NAMESCASESENSITIVE ON ;

UNITS
DATABASE MICRONS 1000 ;
END UNITS

LAYER NWELL
	TYPE MASTERSLICE ;
END NWELL
LAYER PP
	TYPE MASTERSLICE ;
END PP
LAYER NP
	TYPE MASTERSLICE ;
END NP
LAYER OD
	TYPE MASTERSLICE ;
END OD
LAYER POLY
	TYPE MASTERSLICE ;
END POLY
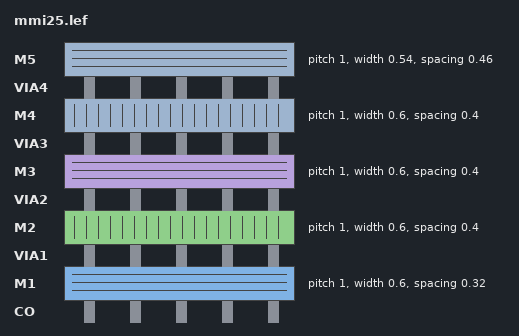
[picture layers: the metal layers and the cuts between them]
LAYER CO
	TYPE CUT ;
END CO
LAYER M1
	TYPE ROUTING ;
	PITCH 1.0 ;
	WIDTH 0.6 ;
	SPACING 0.32 ;
	DIRECTION HORIZONTAL ;
	RESISTANCE RPERSQ 0.09 ;
	CAPACITANCE CPERSQDIST .000389 ;
END M1
LAYER VIA1 
	TYPE CUT ;
END VIA1
LAYER M2
	TYPE ROUTING ;
	PITCH 1.0 ;
	WIDTH 0.6 ;
	SPACING 0.4 ;
	DIRECTION VERTICAL ;
	RESISTANCE RPERSQ 0.09 ;
	CAPACITANCE CPERSQDIST .000353 ;
END M2
LAYER VIA2
	TYPE CUT ;
END VIA2
LAYER M3
	TYPE ROUTING ;
	PITCH 1.0 ;
	WIDTH 0.6 ;
	SPACING 0.4 ;
	DIRECTION HORIZONTAL ;
	RESISTANCE RPERSQ 0.09 ;
	CAPACITANCE CPERSQDIST .000320 ;
END M3
LAYER VIA3
	TYPE CUT ;
END VIA3
LAYER M4
	TYPE ROUTING ;
	PITCH 1.0 ;
	WIDTH 0.6 ;
	SPACING 0.4 ;
	DIRECTION VERTICAL ;
	RESISTANCE RPERSQ 0.05 ;
	CAPACITANCE CPERSQDIST .000296 ;
END M4
LAYER VIA4
	TYPE CUT ;
END VIA4
LAYER M5
	TYPE ROUTING ;
	PITCH 1.0 ;
	WIDTH 0.54 ;
	SPACING 0.46 ;
	DIRECTION HORIZONTAL ;
	RESISTANCE RPERSQ 0.05 ;
	CAPACITANCE CPERSQDIST .000296 ;
END M5
VIA VIA12 DEFAULT
	RESISTANCE 1.21 ;
	LAYER M1 ; RECT -0.28 -0.28 0.28 0.28 ;
	LAYER VIA1 ; RECT -0.18 -0.18 0.18 0.18 ;
	LAYER M2 ; RECT -0.28 -0.28 0.28 0.28 ;
END VIA12
VIA VIA23 DEFAULT
	RESISTANCE 1.07 ;
	LAYER M2 ; RECT -0.28 -0.28 0.28 0.28 ;
	LAYER VIA2 ; RECT -0.18 -0.18 0.18 0.18 ;
	LAYER M3 ; RECT -0.28 -0.28 0.28 0.28 ;
END VIA23
VIA VIA34 DEFAULT
	RESISTANCE 1.19 ;
	LAYER M3 ; RECT -0.28 -0.28 0.28 0.28 ;
	LAYER VIA3 ; RECT -0.18 -0.18 0.18 0.18 ;
	LAYER M4 ; RECT -0.28 -0.28 0.28 0.28 ;
END VIA34
VIA VIA45 DEFAULT
	RESISTANCE 1.19 ;
	LAYER M4 ; RECT -0.27 -0.27 0.27 0.27 ;
	LAYER VIA4 ; RECT -0.18 -0.18 0.18 0.18 ;
	LAYER M5 ; RECT -0.27 -0.27 0.27 0.27 ;
END VIA45
VIARULE TURN1 GENERATE
	LAYER M1 ; DIRECTION HORIZONTAL ;
	LAYER M1 ; DIRECTION VERTICAL ;
END TURN1
VIARULE TURN2 GENERATE
	LAYER M2 ; DIRECTION VERTICAL ;
	LAYER M2 ; DIRECTION HORIZONTAL ;
END TURN2
VIARULE TURN3 GENERATE
	LAYER M3 ; DIRECTION HORIZONTAL ;
	LAYER M3 ; DIRECTION VERTICAL ;
END TURN3
VIARULE TURN4 GENERATE
	LAYER M4 ; DIRECTION VERTICAL ;
	LAYER M4 ; DIRECTION HORIZONTAL ;
END TURN4
VIARULE TURN5 GENERATE
	LAYER M5 ; DIRECTION HORIZONTAL ;
	LAYER M5 ; DIRECTION VERTICAL ;
END TURN5
VIARULE ONEVIA12
	LAYER M1 ; DIRECTION HORIZONTAL ; WIDTH 0.5 TO 0.9 ;
	LAYER M2 ; DIRECTION VERTICAL ; WIDTH 0.6 TO 0.9 ;
	VIA VIA12 ;
END ONEVIA12
VIARULE ONEVIA23
	LAYER M2 ; DIRECTION VERTICAL ; WIDTH 0.6 TO 0.9 ;
	LAYER M3 ; DIRECTION HORIZONTAL ; WIDTH 0.6 TO 0.9 ;
	VIA VIA23 ;
END ONEVIA23
VIARULE ONEVIA34
	LAYER M3 ; DIRECTION HORIZONTAL ; WIDTH 0.6 TO 0.9 ;
	LAYER M4 ; DIRECTION VERTICAL ; WIDTH 0.6 TO 0.9 ;
	VIA VIA34 ;
END ONEVIA34
VIARULE ONEVIA45
	LAYER M4 ; DIRECTION VERTICAL ; WIDTH 0.6 TO 0.9 ;
	LAYER M5 ; DIRECTION HORIZONTAL ; WIDTH 0.6 TO 0.9 ;
	VIA VIA45 ;
END ONEVIA45
VIARULE VIAGEN12 GENERATE
	LAYER M1 ; DIRECTION HORIZONTAL ; OVERHANG 0.1 ; METALOVERHANG 0.1 ;
	LAYER M2 ; DIRECTION VERTICAL ; OVERHANG 0.1 ; METALOVERHANG 0.1 ;
	LAYER VIA1 ; RECT  -0.18 -0.18 0.18 0.18 ; SPACING 1.00 BY 1.00 ;
END VIAGEN12
VIARULE VIAGEN23 GENERATE
	LAYER M2 ; DIRECTION VERTICAL ; OVERHANG 0.1 ; METALOVERHANG 0.1 ;
	LAYER M3 ; DIRECTION HORIZONTAL ; OVERHANG 0.1 ; METALOVERHANG 0.1 ;
	LAYER VIA2 ; RECT  -0.18 -0.18 0.18 0.18 ; SPACING 1.00 BY 1.00 ;
END VIAGEN23
VIARULE VIAGEN34 GENERATE
	LAYER M3 ; DIRECTION HORIZONTAL ; OVERHANG 0.1 ; METALOVERHANG 0.1 ;
	LAYER M4 ; DIRECTION VERTICAL ; OVERHANG 0.1 ; METALOVERHANG 0.1 ;
	LAYER VIA3 ; RECT  -0.18 -0.18 0.18 0.18 ; SPACING 1.00 BY 1.00 ;
END VIAGEN34
VIARULE VIAGEN45 GENERATE
	LAYER M4 ; DIRECTION VERTICAL ; OVERHANG 0.09 ; METALOVERHANG 0.09 ;
	LAYER M5 ; DIRECTION HORIZONTAL ; OVERHANG 0.09 ; METALOVERHANG 0.09 ;
	LAYER VIA4 ; RECT  -0.18 -0.18 0.18 0.18 ; SPACING 1.00 BY 1.00 ;
END VIAGEN45
SPACING
        SAMENET M1 M1 0.32 STACK ;
        SAMENET M2 M2 0.40 STACK ;
        SAMENET M3 M3 0.40 STACK ;
        SAMENET M4 M4 0.40 STACK ;
        SAMENET M5 M5 0.46 ;
	SAMENET VIA1 VIA1 0.35 STACK ;
	SAMENET VIA2 VIA2 0.35 STACK ;
	SAMENET VIA3 VIA3 0.35 STACK ;
	SAMENET VIA4 VIA4 0.35 STACK ;
END SPACING
MINFEATURE 0.01 0.01 ;
SITE CORE1
	SIZE 1.0 BY 10 ;
	CLASS CORE ;
	SYMMETRY Y ;
END CORE1
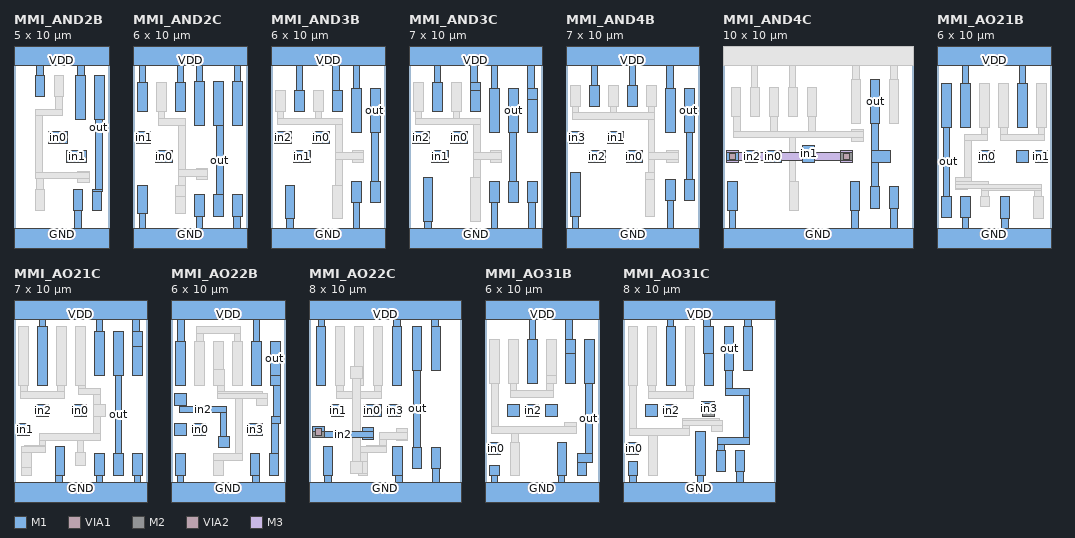
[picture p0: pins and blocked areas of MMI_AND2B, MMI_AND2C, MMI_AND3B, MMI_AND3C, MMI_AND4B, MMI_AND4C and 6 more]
MACRO MMI_AND2B
	CLASS CORE ;
	FOREIGN MMI_AND2B 0 0 ;
	SIZE 5 BY 10 ;
	SYMMETRY X Y ;
	SITE CORE1 ;
	PIN out
		DIRECTION output ;
		PORT
			LAYER M1 ;
			RECT 4.26 6.46 4.74 8.78 ;
			LAYER M1 ;
			RECT 4.28 2.76 4.64 6.46 ;
			LAYER M1 ;
			RECT 4.14 2.66 4.64 2.76 ;
			LAYER M1 ;
			RECT 4.14 1.64 4.62 2.66 ;
		END
	END out
	PIN in1
		DIRECTION input ;
		PORT
			LAYER M1 ;
			RECT 2.78 4.2 3.8 4.8 ;
		END
	END in1
	PIN GND
		DIRECTION inout ;
		USE GROUND ;
		SHAPE ABUTMENT ;
		PORT
			LAYER M1 ;
			RECT 3.14 1.64 3.62 2.76 ;
			LAYER M1 ;
			RECT 3.2 0.7 3.56 1.64 ;
			LAYER M1 ;
			RECT 0 -0.7 5 0.7 ;
		END
	END GND
	PIN VDD
		DIRECTION inout ;
		USE POWER ;
		SHAPE ABUTMENT ;
		PORT
			LAYER M1 ;
			RECT 0 9.3 5 10.7 ;
			LAYER M1 ;
			RECT 1.2 8.76 1.56 9.3 ;
			LAYER M1 ;
			RECT 3.32 8.78 3.7 9.3 ;
			LAYER M1 ;
			RECT 1.14 7.66 1.62 8.76 ;
			LAYER M1 ;
			RECT 3.26 6.46 3.74 8.78 ;
		END
	END VDD
	PIN in0
		DIRECTION input ;
		PORT
			LAYER M1 ;
			RECT 1.8 5.2 2.8 5.8 ;
		END
	END in0
	OBS
		LAYER M1 ;
		RECT 2.14 7.66 2.62 8.76 ;
		LAYER M1 ;
		RECT 2.2 6.98 2.56 7.66 ;
		LAYER M1 ;
		RECT 1.12 6.64 2.56 6.98 ;
		LAYER M1 ;
		RECT 1.12 3.66 1.48 6.64 ;
		LAYER M1 ;
		RECT 3.36 3.66 3.96 3.72 ;
		LAYER M1 ;
		RECT 1.12 3.32 3.96 3.66 ;
		LAYER M1 ;
		RECT 1.2 2.76 1.56 3.32 ;
		LAYER M1 ;
		RECT 3.36 3.12 3.96 3.32 ;
		LAYER M1 ;
		RECT 1.14 1.64 1.62 2.76 ;
	END
END MMI_AND2B
MACRO MMI_AND2C
	CLASS CORE ;
	FOREIGN MMI_AND2C 0 0 ;
	SIZE 6 BY 10 ;
	SYMMETRY X Y ;
	SITE CORE1 ;
	PIN in1
		DIRECTION input ;
		PORT
			LAYER M1 ;
			RECT 0.2 5.2 0.9 5.8 ;
		END
	END in1
	PIN out
		DIRECTION output ;
		PORT
			LAYER M1 ;
			RECT 4.26 6.14 4.74 8.46 ;
			LAYER M1 ;
			RECT 4.38 2.48 4.74 6.14 ;
			LAYER M1 ;
			RECT 4.26 1.36 4.74 2.48 ;
		END
	END out
	PIN GND
		DIRECTION inout ;
		USE GROUND ;
		SHAPE ABUTMENT ;
		PORT
			LAYER M1 ;
			RECT 0.26 1.48 0.74 3 ;
			LAYER M1 ;
			RECT 0.32 0.7 0.68 1.48 ;
			LAYER M1 ;
			RECT 3.26 1.36 3.74 2.48 ;
			LAYER M1 ;
			RECT 5.26 1.36 5.74 2.48 ;
			LAYER M1 ;
			RECT 3.32 0.7 3.66 1.36 ;
			LAYER M1 ;
			RECT 5.28 0.7 5.64 1.36 ;
			LAYER M1 ;
			RECT 0 -0.7 6 0.7 ;
		END
	END GND
	PIN VDD
		DIRECTION inout ;
		USE POWER ;
		SHAPE ABUTMENT ;
		PORT
			LAYER M1 ;
			RECT 0 9.3 6 10.7 ;
			LAYER M1 ;
			RECT 0.32 8.38 0.68 9.3 ;
			LAYER M1 ;
			RECT 2.32 8.38 2.68 9.3 ;
			LAYER M1 ;
			RECT 3.32 8.46 3.68 9.3 ;
			LAYER M1 ;
			RECT 5.32 8.46 5.68 9.3 ;
			LAYER M1 ;
			RECT 0.26 6.86 0.74 8.38 ;
			LAYER M1 ;
			RECT 2.26 6.86 2.74 8.38 ;
			LAYER M1 ;
			RECT 3.26 6.14 3.74 8.46 ;
			LAYER M1 ;
			RECT 5.26 6.14 5.74 8.46 ;
		END
	END VDD
	PIN in0
		DIRECTION input ;
		PORT
			LAYER M1 ;
			RECT 1.2 4.2 2.08 4.8 ;
		END
	END in0
	OBS
		LAYER M1 ;
		RECT 1.26 6.86 1.74 8.38 ;
		LAYER M1 ;
		RECT 1.32 6.48 1.68 6.86 ;
		LAYER M1 ;
		RECT 1.32 6.12 2.76 6.48 ;
		LAYER M1 ;
		RECT 2.4 3.82 2.76 6.12 ;
		LAYER M1 ;
		RECT 3.34 3.82 3.94 3.88 ;
		LAYER M1 ;
		RECT 2.4 3.46 3.94 3.82 ;
		LAYER M1 ;
		RECT 2.4 3 2.76 3.46 ;
		LAYER M1 ;
		RECT 3.34 3.28 3.94 3.46 ;
		LAYER M1 ;
		RECT 2.26 2.38 2.76 3 ;
		LAYER M1 ;
		RECT 2.26 1.48 2.74 2.38 ;
	END
END MMI_AND2C
MACRO MMI_AND3B
	CLASS CORE ;
	FOREIGN MMI_AND3B 0 0 ;
	SIZE 6 BY 10 ;
	SYMMETRY X Y ;
	SITE CORE1 ;
	PIN out
		DIRECTION output ;
		PORT
			LAYER M1 ;
			RECT 5.26 5.78 5.74 8.1 ;
			LAYER M1 ;
			RECT 5.28 3.2 5.64 5.78 ;
			LAYER M1 ;
			RECT 5.26 2.08 5.74 3.2 ;
		END
	END out
	PIN in1
		DIRECTION input ;
		PORT
			LAYER M1 ;
			RECT 1.2 4.2 2.08 4.8 ;
		END
	END in1
	PIN in2
		DIRECTION input ;
		PORT
			LAYER M1 ;
			RECT 0.2 5.2 1.06 5.8 ;
		END
	END in2
	PIN GND
		DIRECTION inout ;
		USE GROUND ;
		SHAPE ABUTMENT ;
		PORT
			LAYER M1 ;
			RECT 0.78 1.26 1.26 2.98 ;
			LAYER M1 ;
			RECT 4.26 2.08 4.74 3.2 ;
			LAYER M1 ;
			RECT 0.84 0.7 1.2 1.26 ;
			LAYER M1 ;
			RECT 4.32 0.7 4.66 2.08 ;
			LAYER M1 ;
			RECT 0 -0.7 6 0.7 ;
		END
	END GND
	PIN VDD
		DIRECTION inout ;
		USE POWER ;
		SHAPE ABUTMENT ;
		PORT
			LAYER M1 ;
			RECT 0 9.3 6 10.7 ;
			LAYER M1 ;
			RECT 1.32 7.96 1.66 9.3 ;
			LAYER M1 ;
			RECT 3.24 7.96 3.6 9.3 ;
			LAYER M1 ;
			RECT 4.32 8.1 4.66 9.3 ;
			LAYER M1 ;
			RECT 1.26 6.86 1.74 7.96 ;
			LAYER M1 ;
			RECT 3.26 6.86 3.74 7.96 ;
			LAYER M1 ;
			RECT 4.26 5.78 4.74 8.1 ;
		END
	END VDD
	PIN in0
		DIRECTION input ;
		PORT
			LAYER M1 ;
			RECT 2.2 5.2 3.08 5.8 ;
		END
	END in0
	OBS
		LAYER M1 ;
		RECT 0.26 6.86 0.74 7.96 ;
		LAYER M1 ;
		RECT 2.26 6.86 2.74 7.96 ;
		LAYER M1 ;
		RECT 0.32 6.52 0.66 6.86 ;
		LAYER M1 ;
		RECT 2.32 6.52 2.66 6.86 ;
		LAYER M1 ;
		RECT 0.32 6.16 3.74 6.52 ;
		LAYER M1 ;
		RECT 3.4 4.7 3.74 6.16 ;
		LAYER M1 ;
		RECT 4.28 4.7 4.88 4.8 ;
		LAYER M1 ;
		RECT 3.4 4.34 4.88 4.7 ;
		LAYER M1 ;
		RECT 3.4 2.98 3.74 4.34 ;
		LAYER M1 ;
		RECT 4.28 4.2 4.88 4.34 ;
		LAYER M1 ;
		RECT 3.26 1.26 3.74 2.98 ;
	END
END MMI_AND3B
MACRO MMI_AND3C
	CLASS CORE ;
	FOREIGN MMI_AND3C 0 0 ;
	SIZE 7 BY 10 ;
	SYMMETRY X Y ;
	SITE CORE1 ;
	PIN in1
		DIRECTION input ;
		PORT
			LAYER M1 ;
			RECT 1.2 4.2 2.06 4.8 ;
		END
	END in1
	PIN out
		DIRECTION output ;
		PORT
			LAYER M1 ;
			RECT 5.26 5.78 5.74 8.1 ;
			LAYER M1 ;
			RECT 5.28 3.2 5.64 5.78 ;
			LAYER M1 ;
			RECT 5.26 2.08 5.74 3.2 ;
		END
	END out
	PIN in2
		DIRECTION input ;
		PORT
			LAYER M1 ;
			RECT 0.2 5.2 1.06 5.8 ;
		END
	END in2
	PIN GND
		DIRECTION inout ;
		USE GROUND ;
		SHAPE ABUTMENT ;
		PORT
			LAYER M1 ;
			RECT 0.76 1.06 1.24 3.38 ;
			LAYER M1 ;
			RECT 4.26 2.08 4.74 3.2 ;
			LAYER M1 ;
			RECT 6.26 2.08 6.74 3.2 ;
			LAYER M1 ;
			RECT 0.84 0.7 1.2 1.06 ;
			LAYER M1 ;
			RECT 4.32 0.7 4.66 2.08 ;
			LAYER M1 ;
			RECT 6.28 0.7 6.64 2.08 ;
			LAYER M1 ;
			RECT 0 -0.7 7 0.7 ;
		END
	END GND
	PIN VDD
		DIRECTION inout ;
		USE POWER ;
		SHAPE ABUTMENT ;
		PORT
			LAYER M1 ;
			RECT 0 9.3 7 10.7 ;
			LAYER M1 ;
			RECT 1.32 8.38 1.66 9.3 ;
			LAYER M1 ;
			RECT 3.24 8.38 3.6 9.3 ;
			LAYER M1 ;
			RECT 1.26 6.86 1.74 8.38 ;
			LAYER M1 ;
			RECT 3.24 7.96 3.74 8.38 ;
			LAYER M1 ;
			RECT 4.32 8.1 4.66 9.3 ;
			LAYER M1 ;
			RECT 6.24 8.1 6.6 9.3 ;
			LAYER M1 ;
			RECT 3.26 6.86 3.74 7.96 ;
			LAYER M1 ;
			RECT 4.26 5.78 4.74 8.1 ;
			LAYER M1 ;
			RECT 6.24 7.48 6.74 8.1 ;
			LAYER M1 ;
			RECT 6.26 5.78 6.74 7.48 ;
		END
	END VDD
	PIN in0
		DIRECTION input ;
		PORT
			LAYER M1 ;
			RECT 2.2 5.2 3.08 5.8 ;
		END
	END in0
	OBS
		LAYER M1 ;
		RECT 0.26 6.86 0.74 8.38 ;
		LAYER M1 ;
		RECT 2.26 6.86 2.74 8.38 ;
		LAYER M1 ;
		RECT 0.32 6.52 0.66 6.86 ;
		LAYER M1 ;
		RECT 2.32 6.52 2.66 6.86 ;
		LAYER M1 ;
		RECT 0.32 6.16 3.74 6.52 ;
		LAYER M1 ;
		RECT 3.4 4.7 3.74 6.16 ;
		LAYER M1 ;
		RECT 4.28 4.7 4.88 4.8 ;
		LAYER M1 ;
		RECT 3.4 4.34 4.88 4.7 ;
		LAYER M1 ;
		RECT 3.4 3.38 3.74 4.34 ;
		LAYER M1 ;
		RECT 4.28 4.2 4.88 4.34 ;
		LAYER M1 ;
		RECT 3.26 1.06 3.74 3.38 ;
	END
END MMI_AND3C
MACRO MMI_AND4B
	CLASS CORE ;
	FOREIGN MMI_AND4B 0 0 ;
	SIZE 7 BY 10 ;
	SYMMETRY X Y ;
	SITE CORE1 ;
	PIN out
		DIRECTION output ;
		PORT
			LAYER M1 ;
			RECT 6.26 5.78 6.74 8.1 ;
			LAYER M1 ;
			RECT 6.32 3.28 6.68 5.78 ;
			LAYER M1 ;
			RECT 6.26 2.16 6.74 3.28 ;
		END
	END out
	PIN in1
		DIRECTION input ;
		PORT
			LAYER M1 ;
			RECT 2.2 5.2 3.04 5.8 ;
		END
	END in1
	PIN GND
		DIRECTION inout ;
		USE GROUND ;
		SHAPE ABUTMENT ;
		PORT
			LAYER M1 ;
			RECT 0.26 1.32 0.74 3.64 ;
			LAYER M1 ;
			RECT 5.26 2.16 5.74 3.28 ;
			LAYER M1 ;
			RECT 0.32 0.7 0.68 1.32 ;
			LAYER M1 ;
			RECT 5.32 0.7 5.68 2.16 ;
			LAYER M1 ;
			RECT 0 -0.7 7 0.7 ;
		END
	END GND
	PIN in2
		DIRECTION input ;
		PORT
			LAYER M1 ;
			RECT 1.2 4.2 2.08 4.8 ;
		END
	END in2
	PIN VDD
		DIRECTION inout ;
		USE POWER ;
		SHAPE ABUTMENT ;
		PORT
			LAYER M1 ;
			RECT 0 9.3 7 10.7 ;
			LAYER M1 ;
			RECT 1.32 8.24 1.66 9.3 ;
			LAYER M1 ;
			RECT 3.32 8.24 3.68 9.3 ;
			LAYER M1 ;
			RECT 1.26 7.14 1.74 8.24 ;
			LAYER M1 ;
			RECT 3.26 7.14 3.74 8.24 ;
			LAYER M1 ;
			RECT 5.28 8.1 5.64 9.3 ;
			LAYER M1 ;
			RECT 5.26 5.78 5.74 8.1 ;
		END
	END VDD
	PIN in3
		DIRECTION input ;
		PORT
			LAYER M1 ;
			RECT 0.2 5.2 0.9 5.8 ;
		END
	END in3
	PIN in0
		DIRECTION input ;
		PORT
			LAYER M1 ;
			RECT 3.2 4.2 4 4.8 ;
		END
	END in0
	OBS
		LAYER M1 ;
		RECT 0.26 7.14 0.74 8.24 ;
		LAYER M1 ;
		RECT 2.26 7.14 2.74 8.24 ;
		LAYER M1 ;
		RECT 4.26 7.14 4.74 8.24 ;
		LAYER M1 ;
		RECT 0.32 6.82 0.68 7.14 ;
		LAYER M1 ;
		RECT 2.32 6.82 2.68 7.14 ;
		LAYER M1 ;
		RECT 4.32 6.82 4.68 7.14 ;
		LAYER M1 ;
		RECT 0.32 6.46 4.68 6.82 ;
		LAYER M1 ;
		RECT 4.32 4.7 4.68 6.46 ;
		LAYER M1 ;
		RECT 5.3 4.7 5.9 4.8 ;
		LAYER M1 ;
		RECT 4.32 4.34 5.9 4.7 ;
		LAYER M1 ;
		RECT 4.32 3.64 4.68 4.34 ;
		LAYER M1 ;
		RECT 5.3 4.2 5.9 4.34 ;
		LAYER M1 ;
		RECT 4.16 3.28 4.68 3.64 ;
		LAYER M1 ;
		RECT 4.16 1.32 4.64 3.28 ;
	END
END MMI_AND4B
MACRO MMI_AND4C
	CLASS CORE ;
	FOREIGN MMI_AND4C 0 0 ;
	SIZE 10 BY 10 ;
	SYMMETRY X Y ;
	SITE CORE1 ;
	PIN out
		DIRECTION output ;
		PORT
			LAYER M1 ;
			RECT 7.76 6.22 8.24 8.54 ;
			LAYER M1 ;
			RECT 7.82 4.8 8.16 6.22 ;
			LAYER M1 ;
			RECT 7.82 4.2 8.8 4.8 ;
			LAYER M1 ;
			RECT 7.82 2.9 8.16 4.2 ;
			LAYER M1 ;
			RECT 7.76 1.78 8.24 2.9 ;
		END
	END out
	PIN in1
		DIRECTION input ;
		PORT
			LAYER M1 ;
			RECT 4.2 4.2 4.8 5.1 ;
		END
	END in1
	PIN in2
		DIRECTION input ;
		PORT
			LAYER M1 ;
			RECT 1.2 4.2 1.8 4.8 ;
		END
	END in2
	PIN GND
		DIRECTION inout ;
		USE GROUND ;
		SHAPE ABUTMENT ;
		PORT
			LAYER M1 ;
			RECT 0.26 1.68 0.74 3.2 ;
			LAYER M1 ;
			RECT 6.7 1.68 7.18 3.2 ;
			LAYER M1 ;
			RECT 8.76 1.78 9.24 2.9 ;
			LAYER M1 ;
			RECT 0.32 0.7 0.68 1.68 ;
			LAYER M1 ;
			RECT 6.76 0.7 7.12 1.68 ;
			LAYER M1 ;
			RECT 8.84 0.7 9.18 1.78 ;
			LAYER M1 ;
			RECT 0 -0.7 10 0.7 ;
		END
	END GND
	PIN in3
		DIRECTION input ;
		PORT
			LAYER M1 ;
			RECT 0.2 4.2 0.8 4.8 ;
			LAYER M1 ;
			RECT 6.2 4.2 6.8 4.8 ;
			LAYER VIA1 ;
			RECT 0.32 4.32 0.68 4.68 ;
			LAYER VIA1 ;
			RECT 6.32 4.32 6.68 4.68 ;
			LAYER M2 ;
			RECT 0.2 4.2 0.82 4.8 ;
			LAYER M2 ;
			RECT 6.2 4.2 6.8 4.8 ;
			LAYER VIA2 ;
			RECT 0.32 4.32 0.68 4.68 ;
			LAYER VIA2 ;
			RECT 6.32 4.32 6.68 4.68 ;
			LAYER M3 ;
			RECT 0.2 4.7 0.8 4.8 ;
			LAYER M3 ;
			RECT 6.2 4.7 6.8 4.8 ;
			LAYER M3 ;
			RECT 0.2 4.28 6.8 4.7 ;
			LAYER M3 ;
			RECT 0.2 4.2 0.8 4.28 ;
			LAYER M3 ;
			RECT 6.2 4.2 6.8 4.28 ;
		END
	END in3
	PIN in0
		DIRECTION input ;
		PORT
			LAYER M1 ;
			RECT 2.2 4.2 3.08 4.8 ;
		END
	END in0
	OBS
		LAYER M1 ;
		RECT 0 9.3 10 10.7 ;
		LAYER M1 ;
		RECT 1.5 8.14 1.84 9.3 ;
		LAYER M1 ;
		RECT 3.5 8.14 3.84 9.3 ;
		LAYER M1 ;
		RECT 6.84 8.54 7.18 9.3 ;
		LAYER M1 ;
		RECT 8.84 8.54 9.18 9.3 ;
		LAYER M1 ;
		RECT 0.46 6.62 0.94 8.14 ;
		LAYER M1 ;
		RECT 1.46 6.62 1.94 8.14 ;
		LAYER M1 ;
		RECT 2.46 6.62 2.94 8.14 ;
		LAYER M1 ;
		RECT 3.46 6.62 3.94 8.14 ;
		LAYER M1 ;
		RECT 4.46 6.62 4.94 8.14 ;
		LAYER M1 ;
		RECT 0.56 5.84 0.92 6.62 ;
		LAYER M1 ;
		RECT 2.52 5.84 2.88 6.62 ;
		LAYER M1 ;
		RECT 4.52 5.84 4.88 6.62 ;
		LAYER M1 ;
		RECT 6.76 6.22 7.24 8.54 ;
		LAYER M1 ;
		RECT 8.76 6.22 9.24 8.54 ;
		LAYER M1 ;
		RECT 6.78 5.84 7.38 5.9 ;
		LAYER M1 ;
		RECT 0.56 5.48 7.38 5.84 ;
		LAYER M1 ;
		RECT 3.48 3.2 3.84 5.48 ;
		LAYER M1 ;
		RECT 6.78 5.3 7.38 5.48 ;
		LAYER M1 ;
		RECT 3.48 1.68 3.96 3.2 ;
	END
END MMI_AND4C
MACRO MMI_AO21B
	CLASS CORE ;
	FOREIGN MMI_AO21B 0 0 ;
	SIZE 6 BY 10 ;
	SYMMETRY X Y ;
	SITE CORE1 ;
	PIN in1
		DIRECTION input ;
		PORT
			LAYER M1 ;
			RECT 5.2 4.2 5.8 4.8 ;
		END
	END in1
	PIN out
		DIRECTION output ;
		PORT
			LAYER M1 ;
			RECT 0.26 6.04 0.74 8.36 ;
			LAYER M1 ;
			RECT 0.32 2.42 0.66 6.04 ;
			LAYER M1 ;
			RECT 0.26 1.3 0.74 2.42 ;
		END
	END out
	PIN in2
		DIRECTION input ;
		PORT
			LAYER M1 ;
			RECT 4.2 4.2 4.8 4.8 ;
		END
	END in2
	PIN GND
		DIRECTION inout ;
		USE GROUND ;
		SHAPE ABUTMENT ;
		PORT
			LAYER M1 ;
			RECT 1.26 1.3 1.74 2.42 ;
			LAYER M1 ;
			RECT 1.32 0.7 1.66 1.3 ;
			LAYER M1 ;
			RECT 3.36 1.26 3.84 2.38 ;
			LAYER M1 ;
			RECT 3.42 0.7 3.78 1.26 ;
			LAYER M1 ;
			RECT 0 -0.7 6 0.7 ;
		END
	END GND
	PIN VDD
		DIRECTION inout ;
		USE POWER ;
		SHAPE ABUTMENT ;
		PORT
			LAYER M1 ;
			RECT 0 9.3 6 10.7 ;
			LAYER M1 ;
			RECT 1.32 8.36 1.66 9.3 ;
			LAYER M1 ;
			RECT 4.32 8.36 4.66 9.3 ;
			LAYER M1 ;
			RECT 1.26 6.04 1.74 8.36 ;
			LAYER M1 ;
			RECT 4.26 6.04 4.74 8.36 ;
		END
	END VDD
	PIN in0
		DIRECTION input ;
		PORT
			LAYER M1 ;
			RECT 2.2 4.2 3.02 4.8 ;
		END
	END in0
	OBS
		LAYER M1 ;
		RECT 2.26 6.04 2.74 8.36 ;
		LAYER M1 ;
		RECT 3.26 6.04 3.74 8.36 ;
		LAYER M1 ;
		RECT 5.26 6.04 5.74 8.36 ;
		LAYER M1 ;
		RECT 2.32 5.66 2.66 6.04 ;
		LAYER M1 ;
		RECT 1.46 5.32 2.66 5.66 ;
		LAYER M1 ;
		RECT 3.34 5.66 3.7 6.04 ;
		LAYER M1 ;
		RECT 5.32 5.66 5.68 6.04 ;
		LAYER M1 ;
		RECT 3.34 5.32 5.68 5.66 ;
		LAYER M1 ;
		RECT 1.46 3.38 1.82 5.32 ;
		LAYER M1 ;
		RECT 0.98 3.16 1.82 3.38 ;
		LAYER M1 ;
		RECT 0.98 3.04 2.7 3.16 ;
		LAYER M1 ;
		RECT 0.98 2.82 5.48 3.04 ;
		LAYER M1 ;
		RECT 0.98 2.78 1.58 2.82 ;
		LAYER M1 ;
		RECT 2.34 2.7 5.48 2.82 ;
		LAYER M1 ;
		RECT 2.34 2.38 2.7 2.7 ;
		LAYER M1 ;
		RECT 5.14 2.38 5.48 2.7 ;
		LAYER M1 ;
		RECT 2.3 1.86 2.78 2.38 ;
		LAYER M1 ;
		RECT 5.1 1.26 5.58 2.38 ;
	END
END MMI_AO21B
MACRO MMI_AO21C
	CLASS CORE ;
	FOREIGN MMI_AO21C 0 0 ;
	SIZE 7 BY 10 ;
	SYMMETRY X Y ;
	SITE CORE1 ;
	PIN in1
		DIRECTION input ;
		PORT
			LAYER M1 ;
			RECT 0.2 3.2 0.8 3.8 ;
		END
	END in1
	PIN out
		DIRECTION output ;
		PORT
			LAYER M1 ;
			RECT 5.26 6.34 5.74 8.66 ;
			LAYER M1 ;
			RECT 5.32 2.22 5.66 6.34 ;
			LAYER M1 ;
			RECT 5.26 1.1 5.74 2.22 ;
		END
	END out
	PIN in2
		DIRECTION input ;
		PORT
			LAYER M1 ;
			RECT 1.2 4.2 1.8 4.8 ;
		END
	END in2
	PIN GND
		DIRECTION inout ;
		USE GROUND ;
		SHAPE ABUTMENT ;
		PORT
			LAYER M1 ;
			RECT 2.16 1.1 2.64 2.62 ;
			LAYER M1 ;
			RECT 4.26 1.1 4.74 2.22 ;
			LAYER M1 ;
			RECT 6.26 1.1 6.74 2.22 ;
			LAYER M1 ;
			RECT 2.2 0.7 2.56 1.1 ;
			LAYER M1 ;
			RECT 4.32 0.7 4.66 1.1 ;
			LAYER M1 ;
			RECT 6.32 0.7 6.68 1.1 ;
			LAYER M1 ;
			RECT 0 -0.7 7 0.7 ;
		END
	END GND
	PIN VDD
		DIRECTION inout ;
		USE POWER ;
		SHAPE ABUTMENT ;
		PORT
			LAYER M1 ;
			RECT 0 9.3 7 10.7 ;
			LAYER M1 ;
			RECT 1.32 8.92 1.66 9.3 ;
			LAYER M1 ;
			RECT 1.26 5.82 1.74 8.92 ;
			LAYER M1 ;
			RECT 4.32 8.66 4.66 9.3 ;
			LAYER M1 ;
			RECT 6.24 8.66 6.6 9.3 ;
			LAYER M1 ;
			RECT 4.26 6.34 4.74 8.66 ;
			LAYER M1 ;
			RECT 6.24 7.86 6.74 8.66 ;
			LAYER M1 ;
			RECT 6.26 6.34 6.74 7.86 ;
		END
	END VDD
	PIN in0
		DIRECTION input ;
		PORT
			LAYER M1 ;
			RECT 3.18 4.2 3.8 4.8 ;
		END
	END in0
	OBS
		LAYER M1 ;
		RECT 0.26 5.82 0.74 8.92 ;
		LAYER M1 ;
		RECT 2.26 5.82 2.74 8.92 ;
		LAYER M1 ;
		RECT 3.26 5.82 3.74 8.92 ;
		LAYER M1 ;
		RECT 0.34 5.5 0.7 5.82 ;
		LAYER M1 ;
		RECT 2.28 5.5 2.64 5.82 ;
		LAYER M1 ;
		RECT 0.34 5.14 2.64 5.5 ;
		LAYER M1 ;
		RECT 3.4 5.68 3.74 5.82 ;
		LAYER M1 ;
		RECT 3.4 5.34 4.56 5.68 ;
		LAYER M1 ;
		RECT 4.2 4.8 4.56 5.34 ;
		LAYER M1 ;
		RECT 4.2 4.2 4.8 4.8 ;
		LAYER M1 ;
		RECT 4.2 3.3 4.56 4.2 ;
		LAYER M1 ;
		RECT 1.32 2.94 4.56 3.3 ;
		LAYER M1 ;
		RECT 1.32 2.64 1.66 2.94 ;
		LAYER M1 ;
		RECT 0.56 2.62 1.66 2.64 ;
		LAYER M1 ;
		RECT 0.42 2.28 1.66 2.62 ;
		LAYER M1 ;
		RECT 0.42 1.52 0.92 2.28 ;
		LAYER M1 ;
		RECT 0.42 1.1 0.9 1.52 ;
		LAYER M1 ;
		RECT 3.32 2.3 3.68 2.94 ;
		LAYER M1 ;
		RECT 3.24 1.58 3.74 2.3 ;
	END
END MMI_AO21C
MACRO MMI_AO22B
	CLASS CORE ;
	FOREIGN MMI_AO22B 0 0 ;
	SIZE 6 BY 10 ;
	SYMMETRY X Y ;
	SITE CORE1 ;
	PIN in1
		DIRECTION input ;
		PORT
			LAYER M1 ;
			RECT 0.2 3.2 0.8 3.8 ;
		END
	END in1
	PIN out
		DIRECTION input ;
		PORT
			LAYER M1 ;
			RECT 5.26 6.34 5.74 8.12 ;
			LAYER M1 ;
			RECT 5.26 5.8 5.76 6.34 ;
			LAYER M1 ;
			RECT 5.4 4.16 5.76 5.8 ;
			LAYER M1 ;
			RECT 5.28 3.84 5.76 4.16 ;
			LAYER M1 ;
			RECT 5.28 2.22 5.64 3.84 ;
			LAYER M1 ;
			RECT 5.2 1.1 5.68 2.22 ;
		END
	END out
	PIN in2
		DIRECTION input ;
		PORT
			LAYER M1 ;
			RECT 0.2 4.78 0.8 5.38 ;
			LAYER M1 ;
			RECT 0.44 4.72 0.8 4.78 ;
			LAYER M1 ;
			RECT 0.44 4.38 2.94 4.72 ;
			LAYER M1 ;
			RECT 2.58 3.14 2.94 4.38 ;
			LAYER M1 ;
			RECT 2.48 2.54 3.08 3.14 ;
		END
	END in2
	PIN GND
		DIRECTION inout ;
		USE GROUND ;
		SHAPE ABUTMENT ;
		PORT
			LAYER M1 ;
			RECT 0.26 1.1 0.74 2.22 ;
			LAYER M1 ;
			RECT 4.2 1.1 4.68 2.22 ;
			LAYER M1 ;
			RECT 0.32 0.7 0.66 1.1 ;
			LAYER M1 ;
			RECT 4.28 0.7 4.64 1.1 ;
			LAYER M1 ;
			RECT 0 -0.7 6 0.7 ;
		END
	END GND
	PIN in3
		DIRECTION input ;
		PORT
			LAYER M1 ;
			RECT 4.08 3.2 4.8 3.8 ;
		END
	END in3
	PIN VDD
		DIRECTION inout ;
		USE POWER ;
		SHAPE ABUTMENT ;
		PORT
			LAYER M1 ;
			RECT 0 9.3 6 10.7 ;
			LAYER M1 ;
			RECT 0.34 8.12 0.7 9.3 ;
			LAYER M1 ;
			RECT 4.32 8.12 4.68 9.3 ;
			LAYER M1 ;
			RECT 0.26 5.8 0.74 8.12 ;
			LAYER M1 ;
			RECT 4.26 5.8 4.74 8.12 ;
		END
	END VDD
	PIN in0
		DIRECTION input ;
		PORT
			LAYER M1 ;
			RECT 1.2 3.2 1.8 3.8 ;
		END
	END in0
	OBS
		LAYER M1 ;
		RECT 1.34 8.56 3.68 8.92 ;
		LAYER M1 ;
		RECT 1.34 8.12 1.7 8.56 ;
		LAYER M1 ;
		RECT 3.32 8.12 3.68 8.56 ;
		LAYER M1 ;
		RECT 1.26 5.8 1.74 8.12 ;
		LAYER M1 ;
		RECT 2.26 6.66 2.74 8.12 ;
		LAYER M1 ;
		RECT 2.26 5.8 2.82 6.66 ;
		LAYER M1 ;
		RECT 3.26 5.8 3.74 8.12 ;
		LAYER M1 ;
		RECT 2.46 5.48 2.82 5.8 ;
		LAYER M1 ;
		RECT 2.46 5.38 4.84 5.48 ;
		LAYER M1 ;
		RECT 2.46 5.12 5.08 5.38 ;
		LAYER M1 ;
		RECT 3.4 2.22 3.76 5.12 ;
		LAYER M1 ;
		RECT 4.48 4.78 5.08 5.12 ;
		LAYER M1 ;
		RECT 2.26 1.86 3.76 2.22 ;
		LAYER M1 ;
		RECT 2.26 1.1 2.74 1.86 ;
	END
END MMI_AO22B
MACRO MMI_AO22C
	CLASS CORE ;
	FOREIGN MMI_AO22C 0 0 ;
	SIZE 8 BY 10 ;
	SYMMETRY X Y ;
	SITE CORE1 ;
	PIN in1
		DIRECTION input ;
		PORT
			LAYER M1 ;
			RECT 1.2 4.2 1.8 4.8 ;
		END
	END in1
	PIN out
		DIRECTION output ;
		PORT
			LAYER M1 ;
			RECT 5.44 6.6 5.92 8.92 ;
			LAYER M1 ;
			RECT 5.52 2.56 5.88 6.6 ;
			LAYER M1 ;
			RECT 5.44 1.44 5.92 2.56 ;
		END
	END out
	PIN in2
		DIRECTION input ;
		PORT
			LAYER M1 ;
			RECT 0.2 3.42 0.84 3.66 ;
			LAYER M1 ;
			RECT 2.8 3.42 3.4 3.58 ;
			LAYER M1 ;
			RECT 0.2 3.06 3.4 3.42 ;
			LAYER M1 ;
			RECT 2.8 2.98 3.4 3.06 ;
			LAYER VIA1 ;
			RECT 0.32 3.18 0.68 3.54 ;
			LAYER M2 ;
			RECT 0.2 3.06 0.8 3.66 ;
		END
	END in2
	PIN GND
		DIRECTION inout ;
		USE GROUND ;
		SHAPE ABUTMENT ;
		PORT
			LAYER M1 ;
			RECT 0.78 1.1 1.26 2.62 ;
			LAYER M1 ;
			RECT 4.38 2.6 4.86 2.62 ;
			LAYER M1 ;
			RECT 4.38 1.1 4.9 2.6 ;
			LAYER M1 ;
			RECT 6.44 1.44 6.92 2.56 ;
			LAYER M1 ;
			RECT 0.8 0.7 1.18 1.1 ;
			LAYER M1 ;
			RECT 4.54 0.7 4.9 1.1 ;
			LAYER M1 ;
			RECT 6.5 0.7 6.86 1.44 ;
			LAYER M1 ;
			RECT 0 -0.7 8 0.7 ;
		END
	END GND
	PIN in3
		DIRECTION input ;
		PORT
			LAYER M1 ;
			RECT 4.2 4.2 4.8 4.8 ;
		END
	END in3
	PIN VDD
		DIRECTION inout ;
		USE POWER ;
		SHAPE ABUTMENT ;
		PORT
			LAYER M1 ;
			RECT 0 9.3 8 10.7 ;
			LAYER M1 ;
			RECT 0.48 8.9 0.84 9.3 ;
			LAYER M1 ;
			RECT 4.46 8.9 4.82 9.3 ;
			LAYER M1 ;
			RECT 6.46 8.92 6.8 9.3 ;
			LAYER M1 ;
			RECT 0.38 5.8 0.86 8.9 ;
			LAYER M1 ;
			RECT 4.38 5.8 4.86 8.9 ;
			LAYER M1 ;
			RECT 6.44 6.6 6.92 8.92 ;
		END
	END VDD
	PIN in0
		DIRECTION input ;
		PORT
			LAYER M1 ;
			RECT 2.86 4.2 3.8 4.8 ;
		END
	END in0
	OBS
		LAYER M1 ;
		RECT 1.38 5.8 1.86 8.9 ;
		LAYER M1 ;
		RECT 2.38 6.8 2.86 8.9 ;
		LAYER M1 ;
		RECT 2.2 6.2 2.86 6.8 ;
		LAYER M1 ;
		RECT 2.38 5.8 2.86 6.2 ;
		LAYER M1 ;
		RECT 3.38 5.8 3.86 8.9 ;
		LAYER M1 ;
		RECT 1.46 5.48 1.82 5.8 ;
		LAYER M1 ;
		RECT 3.46 5.48 3.82 5.8 ;
		LAYER M1 ;
		RECT 1.46 5.12 3.82 5.48 ;
		LAYER M1 ;
		RECT 4.6 3.32 5.2 3.54 ;
		LAYER M1 ;
		RECT 3.72 2.96 5.2 3.32 ;
		LAYER M1 ;
		RECT 3.72 2.64 4.06 2.96 ;
		LAYER M1 ;
		RECT 4.6 2.94 5.2 2.96 ;
		LAYER M1 ;
		RECT 3.04 2.62 4.06 2.64 ;
		LAYER M1 ;
		RECT 2.58 2.28 4.06 2.62 ;
		LAYER M1 ;
		RECT 4.38 2.6 4.86 2.62 ;
		LAYER M1 ;
		RECT 2.58 1.8 3.06 2.28 ;
		LAYER M1 ;
		RECT 2.2 1.2 3.06 1.8 ;
		LAYER M1 ;
		RECT 2.58 1.1 3.06 1.2 ;
		LAYER M2 ;
		RECT 2.2 6.2 2.8 6.8 ;
		LAYER M2 ;
		RECT 2.3 1.8 2.72 6.2 ;
		LAYER M2 ;
		RECT 2.2 1.2 2.8 1.8 ;
	END
END MMI_AO22C
MACRO MMI_AO31B
	CLASS CORE ;
	FOREIGN MMI_AO31B 0 0 ;
	SIZE 6 BY 10 ;
	SYMMETRY X Y ;
	SITE CORE1 ;
	PIN in1
		DIRECTION input ;
		PORT
			LAYER M1 ;
			RECT 1.2 4.2 1.8 4.8 ;
		END
	END in1
	PIN out
		DIRECTION output ;
		PORT
			LAYER M1 ;
			RECT 5.26 5.92 5.74 8.24 ;
			LAYER M1 ;
			RECT 5.3 2.22 5.66 5.92 ;
			LAYER M1 ;
			RECT 4.88 1.78 5.66 2.22 ;
			LAYER M1 ;
			RECT 4.88 1.1 5.36 1.78 ;
		END
	END out
	PIN in2
		DIRECTION input ;
		PORT
			LAYER M1 ;
			RECT 2.2 4.2 2.8 4.8 ;
		END
	END in2
	PIN GND
		DIRECTION inout ;
		USE GROUND ;
		SHAPE ABUTMENT ;
		PORT
			LAYER M1 ;
			RECT 0.26 1.1 0.74 1.62 ;
			LAYER M1 ;
			RECT 3.8 1.1 4.28 2.82 ;
			LAYER M1 ;
			RECT 0.32 0.7 0.66 1.1 ;
			LAYER M1 ;
			RECT 3.86 0.7 4.2 1.1 ;
			LAYER M1 ;
			RECT 0 -0.7 6 0.7 ;
		END
	END GND
	PIN in3
		DIRECTION input ;
		PORT
			LAYER M1 ;
			RECT 3.2 4.2 3.8 4.8 ;
		END
	END in3
	PIN VDD
		DIRECTION inout ;
		USE POWER ;
		SHAPE ABUTMENT ;
		PORT
			LAYER M1 ;
			RECT 0 9.3 6 10.7 ;
			LAYER M1 ;
			RECT 2.32 8.24 2.66 9.3 ;
			LAYER M1 ;
			RECT 4.24 8.24 4.6 9.3 ;
			LAYER M1 ;
			RECT 2.26 5.92 2.74 8.24 ;
			LAYER M1 ;
			RECT 4.24 7.48 4.74 8.24 ;
			LAYER M1 ;
			RECT 4.26 5.92 4.74 7.48 ;
		END
	END VDD
	PIN in0
		DIRECTION input ;
		PORT
			LAYER M1 ;
			RECT 0.2 2.2 0.8 2.8 ;
		END
	END in0
	OBS
		LAYER M1 ;
		RECT 0.26 5.92 0.74 8.24 ;
		LAYER M1 ;
		RECT 1.26 5.92 1.74 8.24 ;
		LAYER M1 ;
		RECT 3.26 6.34 3.74 8.24 ;
		LAYER M1 ;
		RECT 3.24 5.92 3.74 6.34 ;
		LAYER M1 ;
		RECT 0.34 3.64 0.7 5.92 ;
		LAYER M1 ;
		RECT 1.32 5.54 1.66 5.92 ;
		LAYER M1 ;
		RECT 3.24 5.54 3.6 5.92 ;
		LAYER M1 ;
		RECT 1.32 5.18 3.6 5.54 ;
		LAYER M1 ;
		RECT 4.2 3.64 4.8 3.88 ;
		LAYER M1 ;
		RECT 0.34 3.28 4.8 3.64 ;
		LAYER M1 ;
		RECT 1.38 2.82 1.74 3.28 ;
		LAYER M1 ;
		RECT 1.32 1.1 1.8 2.82 ;
	END
END MMI_AO31B
MACRO MMI_AO31C
	CLASS CORE ;
	FOREIGN MMI_AO31C 0 0 ;
	SIZE 8 BY 10 ;
	SYMMETRY X Y ;
	SITE CORE1 ;
	PIN in1
		DIRECTION input ;
		PORT
			LAYER M1 ;
			RECT 1.2 4.2 1.82 4.8 ;
		END
	END in1
	PIN out
		DIRECTION output ;
		PORT
			LAYER M1 ;
			RECT 5.34 6.62 5.82 8.94 ;
			LAYER M1 ;
			RECT 5.4 5.64 5.76 6.62 ;
			LAYER M1 ;
			RECT 5.4 5.28 6.66 5.64 ;
			LAYER M1 ;
			RECT 6.32 3.08 6.66 5.28 ;
			LAYER M1 ;
			RECT 4.96 2.72 6.66 3.08 ;
			LAYER M1 ;
			RECT 4.96 2.4 5.32 2.72 ;
			LAYER M1 ;
			RECT 4.9 1.28 5.38 2.4 ;
		END
	END out
	PIN in2
		DIRECTION input ;
		PORT
			LAYER M1 ;
			RECT 2.2 4.2 2.8 4.8 ;
		END
	END in2
	PIN GND
		DIRECTION inout ;
		USE GROUND ;
		SHAPE ABUTMENT ;
		PORT
			LAYER M1 ;
			RECT 0.28 1.1 0.78 1.82 ;
			LAYER M1 ;
			RECT 0.36 0.7 0.7 1.1 ;
			LAYER M1 ;
			RECT 3.84 1.08 4.32 3.4 ;
			LAYER M1 ;
			RECT 5.9 1.28 6.38 2.4 ;
			LAYER M1 ;
			RECT 3.92 0.7 4.26 1.08 ;
			LAYER M1 ;
			RECT 5.96 0.7 6.32 1.28 ;
			LAYER M1 ;
			RECT 0 -0.7 8 0.7 ;
		END
	END GND
	PIN in3
		DIRECTION input ;
		PORT
			LAYER M1 ;
			RECT 4.12 4.4 4.8 5 ;
			LAYER VIA1 ;
			RECT 4.32 4.52 4.68 4.88 ;
			LAYER M2 ;
			RECT 4.2 4.2 4.8 5 ;
		END
	END in3
	PIN VDD
		DIRECTION inout ;
		USE POWER ;
		SHAPE ABUTMENT ;
		PORT
			LAYER M1 ;
			RECT 0 9.3 8 10.7 ;
			LAYER M1 ;
			RECT 2.32 8.92 2.66 9.3 ;
			LAYER M1 ;
			RECT 4.24 8.92 4.6 9.3 ;
			LAYER M1 ;
			RECT 6.4 8.94 6.76 9.3 ;
			LAYER M1 ;
			RECT 2.28 5.82 2.76 8.92 ;
			LAYER M1 ;
			RECT 4.24 7.48 4.76 8.92 ;
			LAYER M1 ;
			RECT 4.28 5.82 4.76 7.48 ;
			LAYER M1 ;
			RECT 6.34 6.62 6.82 8.94 ;
		END
	END VDD
	PIN in0
		DIRECTION input ;
		PORT
			LAYER M1 ;
			RECT 0.2 2.2 0.8 2.8 ;
		END
	END in0
	OBS
		LAYER M1 ;
		RECT 0.28 5.82 0.76 8.92 ;
		LAYER M1 ;
		RECT 1.28 5.82 1.76 8.92 ;
		LAYER M1 ;
		RECT 3.28 5.82 3.76 8.92 ;
		LAYER M1 ;
		RECT 0.34 3.56 0.7 5.82 ;
		LAYER M1 ;
		RECT 1.36 5.5 1.7 5.82 ;
		LAYER M1 ;
		RECT 3.36 5.5 3.7 5.82 ;
		LAYER M1 ;
		RECT 1.36 5.14 3.7 5.5 ;
		LAYER M1 ;
		RECT 3.12 4 5.06 4.08 ;
		LAYER M1 ;
		RECT 3.12 3.72 5.24 4 ;
		LAYER M1 ;
		RECT 3.12 3.56 3.48 3.72 ;
		LAYER M1 ;
		RECT 0.34 3.2 3.48 3.56 ;
		LAYER M1 ;
		RECT 4.64 3.4 5.24 3.72 ;
		LAYER M1 ;
		RECT 1.34 1.08 1.82 3.2 ;
	END
END MMI_AO31C
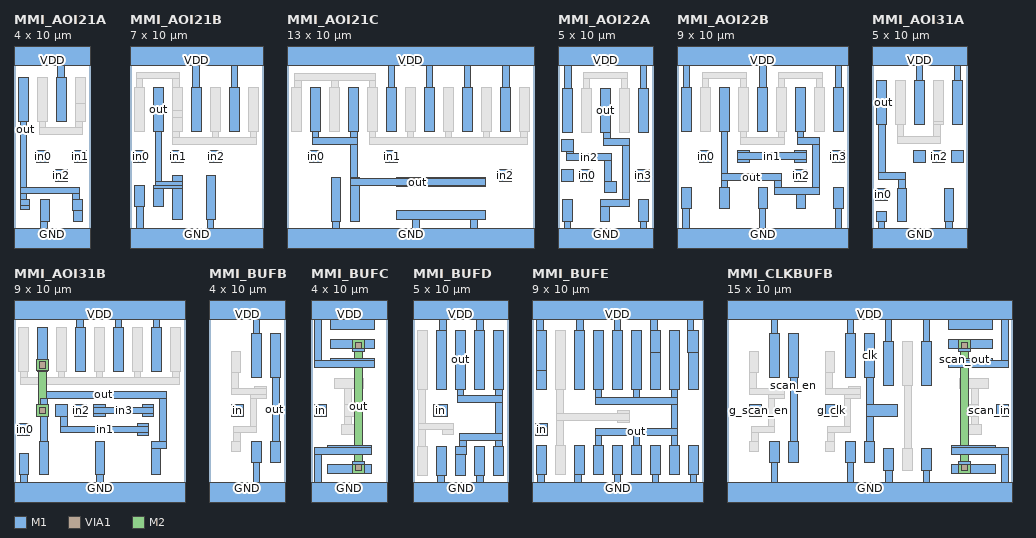
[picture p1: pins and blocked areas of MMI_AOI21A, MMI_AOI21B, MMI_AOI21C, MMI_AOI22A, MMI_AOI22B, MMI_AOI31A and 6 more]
MACRO MMI_AOI21A
	CLASS CORE ;
	FOREIGN MMI_AOI21A 0 0 ;
	SIZE 4 BY 10 ;
	SYMMETRY X Y ;
	SITE CORE1 ;
	PIN in1
		DIRECTION input ;
		PORT
			LAYER M1 ;
			RECT 3.2 4.2 3.8 4.8 ;
		END
	END in1
	PIN out
		DIRECTION output ;
		PORT
			LAYER M1 ;
			RECT 0.26 6.36 0.74 8.68 ;
			LAYER M1 ;
			RECT 0.32 2.88 0.66 6.36 ;
			LAYER M1 ;
			RECT 0.32 2.54 3.46 2.88 ;
			LAYER M1 ;
			RECT 0.32 2.22 0.66 2.54 ;
			LAYER M1 ;
			RECT 3.1 2.22 3.46 2.54 ;
			LAYER M1 ;
			RECT 0.32 1.92 0.82 2.22 ;
			LAYER M1 ;
			RECT 0.34 1.7 0.82 1.92 ;
			LAYER M1 ;
			RECT 3.1 1.64 3.62 2.22 ;
			LAYER M1 ;
			RECT 3.14 1.1 3.62 1.64 ;
		END
	END out
	PIN in2
		DIRECTION input ;
		PORT
			LAYER M1 ;
			RECT 2.16 3.2 2.8 3.8 ;
		END
	END in2
	PIN GND
		DIRECTION inout ;
		USE GROUND ;
		SHAPE ABUTMENT ;
		PORT
			LAYER M1 ;
			RECT 1.4 1.1 1.88 2.22 ;
			LAYER M1 ;
			RECT 1.42 0.7 1.78 1.1 ;
			LAYER M1 ;
			RECT 0 -0.7 4 0.7 ;
		END
	END GND
	PIN VDD
		DIRECTION inout ;
		USE POWER ;
		SHAPE ABUTMENT ;
		PORT
			LAYER M1 ;
			RECT 0 9.3 4 10.7 ;
			LAYER M1 ;
			RECT 2.28 8.68 2.64 9.3 ;
			LAYER M1 ;
			RECT 2.26 6.36 2.74 8.68 ;
		END
	END VDD
	PIN in0
		DIRECTION input ;
		PORT
			LAYER M1 ;
			RECT 1.2 4.2 1.8 4.8 ;
		END
	END in0
	OBS
		LAYER M1 ;
		RECT 1.26 6.36 1.74 8.68 ;
		LAYER M1 ;
		RECT 3.26 7.28 3.74 8.68 ;
		LAYER M1 ;
		RECT 3.24 6.36 3.74 7.28 ;
		LAYER M1 ;
		RECT 1.32 6.02 1.66 6.36 ;
		LAYER M1 ;
		RECT 3.24 6.02 3.6 6.36 ;
		LAYER M1 ;
		RECT 1.32 5.66 3.6 6.02 ;
	END
END MMI_AOI21A
MACRO MMI_AOI21B
	CLASS CORE ;
	FOREIGN MMI_AOI21B 0 0 ;
	SIZE 7 BY 10 ;
	SYMMETRY X Y ;
	SITE CORE1 ;
	PIN in1
		DIRECTION input ;
		PORT
			LAYER M1 ;
			RECT 2.2 4.2 2.8 4.8 ;
		END
	END in1
	PIN out
		DIRECTION output ;
		PORT
			LAYER M1 ;
			RECT 1.26 5.8 1.74 8.12 ;
			LAYER M1 ;
			RECT 1.32 3.2 1.66 5.8 ;
			LAYER M1 ;
			RECT 2.26 3.2 2.74 3.48 ;
			LAYER M1 ;
			RECT 1.32 3 2.74 3.2 ;
			LAYER M1 ;
			RECT 1.26 2.84 2.74 3 ;
			LAYER M1 ;
			RECT 1.26 1.88 1.74 2.84 ;
			LAYER M1 ;
			RECT 2.26 1.16 2.74 2.84 ;
		END
	END out
	PIN in2
		DIRECTION input ;
		PORT
			LAYER M1 ;
			RECT 4.2 4.2 4.8 4.8 ;
		END
	END in2
	PIN GND
		DIRECTION inout ;
		USE GROUND ;
		SHAPE ABUTMENT ;
		PORT
			LAYER M1 ;
			RECT 0.26 1.88 0.74 3 ;
			LAYER M1 ;
			RECT 0.34 0.7 0.7 1.88 ;
			LAYER M1 ;
			RECT 4 1.16 4.48 3.48 ;
			LAYER M1 ;
			RECT 4.06 0.7 4.42 1.16 ;
			LAYER M1 ;
			RECT 0 -0.7 7 0.7 ;
		END
	END GND
	PIN VDD
		DIRECTION inout ;
		USE POWER ;
		SHAPE ABUTMENT ;
		PORT
			LAYER M1 ;
			RECT 0 9.3 7 10.7 ;
			LAYER M1 ;
			RECT 3.3 8.12 3.66 9.3 ;
			LAYER M1 ;
			RECT 5.32 8.12 5.68 9.3 ;
			LAYER M1 ;
			RECT 3.26 5.8 3.74 8.12 ;
			LAYER M1 ;
			RECT 5.26 5.8 5.74 8.12 ;
		END
	END VDD
	PIN in0
		DIRECTION input ;
		PORT
			LAYER M1 ;
			RECT 0.2 4.2 0.8 4.8 ;
		END
	END in0
	OBS
		LAYER M1 ;
		RECT 0.32 8.58 2.6 8.94 ;
		LAYER M1 ;
		RECT 0.32 8.12 0.66 8.58 ;
		LAYER M1 ;
		RECT 2.24 8.12 2.6 8.58 ;
		LAYER M1 ;
		RECT 0.26 5.8 0.74 8.12 ;
		LAYER M1 ;
		RECT 2.24 6.9 2.74 8.12 ;
		LAYER M1 ;
		RECT 2.26 6.56 2.74 6.9 ;
		LAYER M1 ;
		RECT 2.24 5.8 2.74 6.56 ;
		LAYER M1 ;
		RECT 4.26 5.8 4.74 8.12 ;
		LAYER M1 ;
		RECT 6.26 5.8 6.74 8.12 ;
		LAYER M1 ;
		RECT 2.24 5.48 2.6 5.8 ;
		LAYER M1 ;
		RECT 4.32 5.48 4.68 5.8 ;
		LAYER M1 ;
		RECT 6.32 5.48 6.66 5.8 ;
		LAYER M1 ;
		RECT 2.24 5.12 6.66 5.48 ;
	END
END MMI_AOI21B
MACRO MMI_AOI21C
	CLASS CORE ;
	FOREIGN MMI_AOI21C 0 0 ;
	SIZE 13 BY 10 ;
	SYMMETRY X Y ;
	SITE CORE1 ;
	PIN in1
		DIRECTION input ;
		PORT
			LAYER M1 ;
			RECT 5.2 4.2 5.8 4.8 ;
		END
	END in1
	PIN out
		DIRECTION output ;
		PORT
			LAYER M1 ;
			RECT 1.26 5.8 1.74 8.12 ;
			LAYER M1 ;
			RECT 3.26 5.8 3.74 8.12 ;
			LAYER M1 ;
			RECT 1.32 5.48 1.68 5.8 ;
			LAYER M1 ;
			RECT 3.34 5.48 3.7 5.8 ;
			LAYER M1 ;
			RECT 1.32 5.12 3.7 5.48 ;
			LAYER M1 ;
			RECT 3.34 3.42 3.7 5.12 ;
			LAYER M1 ;
			RECT 3.32 3.32 3.8 3.42 ;
			LAYER M1 ;
			RECT 5.76 3.32 10.46 3.38 ;
			LAYER M1 ;
			RECT 3.32 2.96 10.46 3.32 ;
			LAYER M1 ;
			RECT 3.32 1.1 3.8 2.96 ;
			LAYER M1 ;
			RECT 5.76 2.9 10.46 2.96 ;
		END
	END out
	PIN in2
		DIRECTION input ;
		PORT
			LAYER M1 ;
			RECT 11.16 3.16 11.82 3.82 ;
		END
	END in2
	PIN GND
		DIRECTION inout ;
		USE GROUND ;
		SHAPE ABUTMENT ;
		PORT
			LAYER M1 ;
			RECT 2.32 1.1 2.8 3.42 ;
			LAYER M1 ;
			RECT 5.76 1.16 10.46 1.64 ;
			LAYER M1 ;
			RECT 2.38 0.7 2.74 1.1 ;
			LAYER M1 ;
			RECT 6.6 0.7 6.96 1.16 ;
			LAYER M1 ;
			RECT 9.66 0.7 10.02 1.16 ;
			LAYER M1 ;
			RECT 0 -0.7 13 0.7 ;
		END
	END GND
	PIN VDD
		DIRECTION inout ;
		USE POWER ;
		SHAPE ABUTMENT ;
		PORT
			LAYER M1 ;
			RECT 0 9.3 13 10.7 ;
			LAYER M1 ;
			RECT 5.32 8.12 5.68 9.3 ;
			LAYER M1 ;
			RECT 7.32 8.12 7.68 9.3 ;
			LAYER M1 ;
			RECT 9.34 8.12 9.68 9.3 ;
			LAYER M1 ;
			RECT 11.34 8.12 11.7 9.3 ;
			LAYER M1 ;
			RECT 5.26 5.8 5.74 8.12 ;
			LAYER M1 ;
			RECT 7.26 5.8 7.74 8.12 ;
			LAYER M1 ;
			RECT 9.26 5.8 9.74 8.12 ;
			LAYER M1 ;
			RECT 11.26 5.8 11.74 8.12 ;
		END
	END VDD
	PIN in0
		DIRECTION input ;
		PORT
			LAYER M1 ;
			RECT 1.2 4.2 1.8 4.8 ;
		END
	END in0
	OBS
		LAYER M1 ;
		RECT 0.38 8.5 4.68 8.86 ;
		LAYER M1 ;
		RECT 0.38 8.12 0.74 8.5 ;
		LAYER M1 ;
		RECT 2.34 8.12 2.7 8.5 ;
		LAYER M1 ;
		RECT 4.32 8.12 4.68 8.5 ;
		LAYER M1 ;
		RECT 0.26 5.8 0.74 8.12 ;
		LAYER M1 ;
		RECT 2.26 5.8 2.74 8.12 ;
		LAYER M1 ;
		RECT 4.26 5.8 4.74 8.12 ;
		LAYER M1 ;
		RECT 6.26 5.8 6.74 8.12 ;
		LAYER M1 ;
		RECT 8.26 5.8 8.74 8.12 ;
		LAYER M1 ;
		RECT 10.26 5.8 10.74 8.12 ;
		LAYER M1 ;
		RECT 12.26 5.8 12.74 8.12 ;
		LAYER M1 ;
		RECT 4.32 5.48 4.68 5.8 ;
		LAYER M1 ;
		RECT 6.32 5.48 6.68 5.8 ;
		LAYER M1 ;
		RECT 8.32 5.48 8.68 5.8 ;
		LAYER M1 ;
		RECT 10.32 5.48 10.68 5.8 ;
		LAYER M1 ;
		RECT 12.3 5.48 12.66 5.8 ;
		LAYER M1 ;
		RECT 4.32 5.12 12.66 5.48 ;
	END
END MMI_AOI21C
MACRO MMI_AOI22A
	CLASS CORE ;
	FOREIGN MMI_AOI22A 0 0 ;
	SIZE 5 BY 10 ;
	SYMMETRY X Y ;
	SITE CORE1 ;
	PIN in1
		DIRECTION input ;
		PORT
			LAYER M1 ;
			RECT 0.2 3.2 0.8 3.8 ;
		END
	END in1
	PIN out
		DIRECTION output ;
		PORT
			LAYER M1 ;
			RECT 2.26 5.78 2.74 8.1 ;
			LAYER M1 ;
			RECT 2.38 5.46 2.74 5.78 ;
			LAYER M1 ;
			RECT 2.38 5.1 3.74 5.46 ;
			LAYER M1 ;
			RECT 3.38 2.22 3.74 5.1 ;
			LAYER M1 ;
			RECT 2.24 1.86 3.74 2.22 ;
			LAYER M1 ;
			RECT 2.24 1.1 2.72 1.86 ;
		END
	END out
	PIN in2
		DIRECTION input ;
		PORT
			LAYER M1 ;
			RECT 0.2 4.78 0.8 5.38 ;
			LAYER M1 ;
			RECT 0.44 4.64 0.8 4.78 ;
			LAYER M1 ;
			RECT 0.44 4.28 2.8 4.64 ;
			LAYER M1 ;
			RECT 2.46 3.2 2.8 4.28 ;
			LAYER M1 ;
			RECT 2.46 2.6 3.06 3.2 ;
		END
	END in2
	PIN GND
		DIRECTION inout ;
		USE GROUND ;
		SHAPE ABUTMENT ;
		PORT
			LAYER M1 ;
			RECT 0.26 1.1 0.74 2.22 ;
			LAYER M1 ;
			RECT 4.26 1.1 4.74 2.22 ;
			LAYER M1 ;
			RECT 0.34 0.7 0.68 1.1 ;
			LAYER M1 ;
			RECT 4.32 0.7 4.68 1.1 ;
			LAYER M1 ;
			RECT 0 -0.7 5 0.7 ;
		END
	END GND
	PIN in3
		DIRECTION input ;
		PORT
			LAYER M1 ;
			RECT 4.2 3.2 4.8 3.8 ;
		END
	END in3
	PIN VDD
		DIRECTION inout ;
		USE POWER ;
		SHAPE ABUTMENT ;
		PORT
			LAYER M1 ;
			RECT 0 9.3 5 10.7 ;
			LAYER M1 ;
			RECT 0.34 8.1 0.7 9.3 ;
			LAYER M1 ;
			RECT 4.32 8.1 4.68 9.3 ;
			LAYER M1 ;
			RECT 0.26 5.78 0.74 8.1 ;
			LAYER M1 ;
			RECT 4.26 5.78 4.74 8.1 ;
		END
	END VDD
	PIN in0
		DIRECTION input ;
		PORT
			LAYER M1 ;
			RECT 1.2 3.2 1.8 3.8 ;
		END
	END in0
	OBS
		LAYER M1 ;
		RECT 1.32 8.58 3.68 8.94 ;
		LAYER M1 ;
		RECT 1.32 8.1 1.66 8.58 ;
		LAYER M1 ;
		RECT 3.32 8.1 3.68 8.58 ;
		LAYER M1 ;
		RECT 1.26 5.78 1.74 8.1 ;
		LAYER M1 ;
		RECT 3.26 5.78 3.74 8.1 ;
	END
END MMI_AOI22A
MACRO MMI_AOI22B
	CLASS CORE ;
	FOREIGN MMI_AOI22B 0 0 ;
	SIZE 9 BY 10 ;
	SYMMETRY X Y ;
	SITE CORE1 ;
	PIN in1
		DIRECTION input ;
		PORT
			LAYER M1 ;
			RECT 3.2 4.7 3.8 4.8 ;
			LAYER M1 ;
			RECT 6.2 4.7 6.8 4.8 ;
			LAYER M1 ;
			RECT 3.2 4.34 6.8 4.7 ;
			LAYER M1 ;
			RECT 3.2 4.2 3.8 4.34 ;
			LAYER M1 ;
			RECT 6.2 4.2 6.8 4.34 ;
		END
	END in1
	PIN out
		DIRECTION output ;
		PORT
			LAYER M1 ;
			RECT 2.26 5.82 2.74 8.14 ;
			LAYER M1 ;
			RECT 6.26 5.82 6.74 8.14 ;
			LAYER M1 ;
			RECT 2.32 3.6 2.66 5.82 ;
			LAYER M1 ;
			RECT 6.32 5.5 6.68 5.82 ;
			LAYER M1 ;
			RECT 6.32 5.14 7.5 5.5 ;
			LAYER M1 ;
			RECT 2.32 3.24 5.48 3.6 ;
			LAYER M1 ;
			RECT 2.32 2.88 2.66 3.24 ;
			LAYER M1 ;
			RECT 5.12 2.88 5.48 3.24 ;
			LAYER M1 ;
			RECT 7.14 2.88 7.5 5.14 ;
			LAYER M1 ;
			RECT 2.26 1.76 2.74 2.88 ;
			LAYER M1 ;
			RECT 5.12 2.52 7.5 2.88 ;
			LAYER M1 ;
			RECT 6.28 1.76 6.76 2.52 ;
		END
	END out
	PIN in2
		DIRECTION input ;
		PORT
			LAYER M1 ;
			RECT 6.2 3.2 6.8 3.8 ;
		END
	END in2
	PIN GND
		DIRECTION inout ;
		USE GROUND ;
		SHAPE ABUTMENT ;
		PORT
			LAYER M1 ;
			RECT 0.26 1.76 0.74 2.88 ;
			LAYER M1 ;
			RECT 4.28 1.76 4.76 2.88 ;
			LAYER M1 ;
			RECT 8.26 1.76 8.74 2.88 ;
			LAYER M1 ;
			RECT 0.28 0.7 0.64 1.76 ;
			LAYER M1 ;
			RECT 4.32 0.7 4.68 1.76 ;
			LAYER M1 ;
			RECT 8.32 0.7 8.68 1.76 ;
			LAYER M1 ;
			RECT 0 -0.68 9 0.7 ;
		END
	END GND
	PIN in3
		DIRECTION input ;
		PORT
			LAYER M1 ;
			RECT 8.2 4.2 8.8 4.8 ;
		END
	END in3
	PIN VDD
		DIRECTION inout ;
		USE POWER ;
		SHAPE ABUTMENT ;
		PORT
			LAYER M1 ;
			RECT 0 9.3 9 10.7 ;
			LAYER M1 ;
			RECT 0.32 8.14 0.66 9.3 ;
			LAYER M1 ;
			RECT 4.34 8.14 4.7 9.3 ;
			LAYER M1 ;
			RECT 8.32 8.14 8.68 9.3 ;
			LAYER M1 ;
			RECT 0.26 5.82 0.74 8.14 ;
			LAYER M1 ;
			RECT 4.26 5.82 4.74 8.14 ;
			LAYER M1 ;
			RECT 8.26 5.82 8.74 8.14 ;
		END
	END VDD
	PIN in0
		DIRECTION input ;
		PORT
			LAYER M1 ;
			RECT 1.2 4.2 1.8 4.8 ;
		END
	END in0
	OBS
		LAYER M1 ;
		RECT 1.32 8.58 3.68 8.94 ;
		LAYER M1 ;
		RECT 1.32 8.14 1.66 8.58 ;
		LAYER M1 ;
		RECT 3.32 8.14 3.68 8.58 ;
		LAYER M1 ;
		RECT 5.34 8.58 7.66 8.94 ;
		LAYER M1 ;
		RECT 5.34 8.14 5.68 8.58 ;
		LAYER M1 ;
		RECT 7.32 8.14 7.66 8.58 ;
		LAYER M1 ;
		RECT 1.26 5.82 1.74 8.14 ;
		LAYER M1 ;
		RECT 3.26 5.82 3.74 8.14 ;
		LAYER M1 ;
		RECT 5.26 5.82 5.74 8.14 ;
		LAYER M1 ;
		RECT 7.26 5.82 7.74 8.14 ;
		LAYER M1 ;
		RECT 3.32 5.5 3.68 5.82 ;
		LAYER M1 ;
		RECT 5.34 5.5 5.68 5.82 ;
		LAYER M1 ;
		RECT 3.32 5.14 5.68 5.5 ;
	END
END MMI_AOI22B
MACRO MMI_AOI31A
	CLASS CORE ;
	FOREIGN MMI_AOI31A 0 0 ;
	SIZE 5 BY 10 ;
	SYMMETRY X Y ;
	SITE CORE1 ;
	PIN in1
		DIRECTION input ;
		PORT
			LAYER M1 ;
			RECT 2.16 4.2 2.8 4.8 ;
		END
	END in1
	PIN out
		DIRECTION output ;
		PORT
			LAYER M1 ;
			RECT 0.26 6.16 0.74 8.48 ;
			LAYER M1 ;
			RECT 0.34 3.64 0.7 6.16 ;
			LAYER M1 ;
			RECT 0.34 3.28 1.74 3.64 ;
			LAYER M1 ;
			RECT 1.38 2.82 1.74 3.28 ;
			LAYER M1 ;
			RECT 1.34 1.1 1.82 2.82 ;
		END
	END out
	PIN in2
		DIRECTION input ;
		PORT
			LAYER M1 ;
			RECT 3.2 4.2 3.8 4.8 ;
		END
	END in2
	PIN GND
		DIRECTION inout ;
		USE GROUND ;
		SHAPE ABUTMENT ;
		PORT
			LAYER M1 ;
			RECT 0.26 1.1 0.74 1.62 ;
			LAYER M1 ;
			RECT 3.82 1.1 4.3 2.82 ;
			LAYER M1 ;
			RECT 0.32 0.7 0.66 1.1 ;
			LAYER M1 ;
			RECT 3.88 0.7 4.22 1.1 ;
			LAYER M1 ;
			RECT 0 -0.7 5 0.7 ;
		END
	END GND
	PIN in3
		DIRECTION input ;
		PORT
			LAYER M1 ;
			RECT 4.2 4.2 4.8 4.8 ;
		END
	END in3
	PIN VDD
		DIRECTION inout ;
		USE POWER ;
		SHAPE ABUTMENT ;
		PORT
			LAYER M1 ;
			RECT 0 9.3 5 10.7 ;
			LAYER M1 ;
			RECT 2.32 8.48 2.66 9.3 ;
			LAYER M1 ;
			RECT 4.32 8.48 4.68 9.3 ;
			LAYER M1 ;
			RECT 2.26 6.16 2.74 8.48 ;
			LAYER M1 ;
			RECT 4.26 6.16 4.74 8.48 ;
		END
	END VDD
	PIN in0
		DIRECTION input ;
		PORT
			LAYER M1 ;
			RECT 0.2 2.2 0.8 2.8 ;
		END
	END in0
	OBS
		LAYER M1 ;
		RECT 1.26 6.16 1.74 8.48 ;
		LAYER M1 ;
		RECT 3.26 6.34 3.74 8.48 ;
		LAYER M1 ;
		RECT 3.24 6.16 3.74 6.34 ;
		LAYER M1 ;
		RECT 1.32 5.54 1.66 6.16 ;
		LAYER M1 ;
		RECT 3.24 5.54 3.6 6.16 ;
		LAYER M1 ;
		RECT 1.32 5.18 3.6 5.54 ;
	END
END MMI_AOI31A
MACRO MMI_AOI31B
	CLASS CORE ;
	FOREIGN MMI_AOI31B 0 0 ;
	SIZE 9 BY 10 ;
	SYMMETRY X Y ;
	SITE CORE1 ;
	PIN in1
		DIRECTION input ;
		PORT
			LAYER M1 ;
			RECT 2.2 4.2 2.8 4.8 ;
			LAYER M1 ;
			RECT 2.46 3.68 2.8 4.2 ;
			LAYER M1 ;
			RECT 6.48 3.68 7.08 3.8 ;
			LAYER M1 ;
			RECT 2.46 3.34 7.08 3.68 ;
			LAYER M1 ;
			RECT 6.48 3.2 7.08 3.34 ;
		END
	END in1
	PIN out
		DIRECTION output ;
		PORT
			LAYER M1 ;
			RECT 1.26 7.18 1.74 8.86 ;
			LAYER M1 ;
			RECT 1.2 6.58 1.8 7.18 ;
			LAYER M1 ;
			RECT 1.26 6.54 1.74 6.58 ;
			LAYER M1 ;
			RECT 1.38 5.14 8.04 5.5 ;
			LAYER M1 ;
			RECT 1.38 4.8 1.74 5.14 ;
			LAYER M1 ;
			RECT 1.2 4.2 1.8 4.8 ;
			LAYER M1 ;
			RECT 1.38 2.86 1.74 4.2 ;
			LAYER M1 ;
			RECT 7.68 2.86 8.04 5.14 ;
			LAYER M1 ;
			RECT 1.34 1.14 1.82 2.86 ;
			LAYER M1 ;
			RECT 7.22 2.52 8.04 2.86 ;
			LAYER M1 ;
			RECT 7.22 1.14 7.7 2.52 ;
			LAYER VIA1 ;
			RECT 1.32 6.7 1.68 7.06 ;
			LAYER VIA1 ;
			RECT 1.32 4.32 1.68 4.68 ;
			LAYER M2 ;
			RECT 1.2 6.58 1.8 7.18 ;
			LAYER M2 ;
			RECT 1.28 4.8 1.7 6.58 ;
			LAYER M2 ;
			RECT 1.2 4.2 1.8 4.8 ;
		END
	END out
	PIN in2
		DIRECTION input ;
		PORT
			LAYER M1 ;
			RECT 3.2 4.2 3.82 4.8 ;
		END
	END in2
	PIN GND
		DIRECTION inout ;
		USE GROUND ;
		SHAPE ABUTMENT ;
		PORT
			LAYER M1 ;
			RECT 0.28 1.12 0.76 2.24 ;
			LAYER M1 ;
			RECT 4.28 1.14 4.76 2.86 ;
			LAYER M1 ;
			RECT 0.36 0.7 0.7 1.12 ;
			LAYER M1 ;
			RECT 4.34 0.7 4.7 1.14 ;
			LAYER M1 ;
			RECT 0 -0.7 9 0.7 ;
		END
	END GND
	PIN in3
		DIRECTION input ;
		PORT
			LAYER M1 ;
			RECT 4.2 4.66 4.8 4.8 ;
			LAYER M1 ;
			RECT 6.76 4.66 7.36 4.8 ;
			LAYER M1 ;
			RECT 4.2 4.32 7.36 4.66 ;
			LAYER M1 ;
			RECT 4.2 4.2 4.8 4.32 ;
			LAYER M1 ;
			RECT 6.76 4.2 7.36 4.32 ;
		END
	END in3
	PIN VDD
		DIRECTION inout ;
		USE POWER ;
		SHAPE ABUTMENT ;
		PORT
			LAYER M1 ;
			RECT 0 9.3 9 10.7 ;
			LAYER M1 ;
			RECT 3.3 8.86 3.66 9.3 ;
			LAYER M1 ;
			RECT 5.32 8.86 5.68 9.3 ;
			LAYER M1 ;
			RECT 7.34 8.86 7.68 9.3 ;
			LAYER M1 ;
			RECT 3.26 6.54 3.74 8.86 ;
			LAYER M1 ;
			RECT 5.26 6.54 5.74 8.86 ;
			LAYER M1 ;
			RECT 7.26 6.54 7.74 8.86 ;
		END
	END VDD
	PIN in0
		DIRECTION input ;
		PORT
			LAYER M1 ;
			RECT 0.2 3.2 0.8 3.8 ;
		END
	END in0
	OBS
		LAYER M1 ;
		RECT 0.26 6.54 0.74 8.86 ;
		LAYER M1 ;
		RECT 2.26 6.54 2.74 8.86 ;
		LAYER M1 ;
		RECT 4.26 6.54 4.74 8.86 ;
		LAYER M1 ;
		RECT 6.26 6.54 6.74 8.86 ;
		LAYER M1 ;
		RECT 8.26 6.54 8.74 8.86 ;
		LAYER M1 ;
		RECT 0.34 6.22 0.7 6.54 ;
		LAYER M1 ;
		RECT 2.32 6.22 2.66 6.54 ;
		LAYER M1 ;
		RECT 4.32 6.22 4.68 6.54 ;
		LAYER M1 ;
		RECT 6.34 6.22 6.68 6.54 ;
		LAYER M1 ;
		RECT 8.34 6.22 8.7 6.54 ;
		LAYER M1 ;
		RECT 0.34 5.86 8.7 6.22 ;
	END
END MMI_AOI31B
MACRO MMI_BUFB
	CLASS CORE ;
	FOREIGN MMI_BUFB 0 0 ;
	SIZE 4 BY 10 ;
	SYMMETRY X Y ;
	SITE CORE1 ;
	PIN out
		DIRECTION output ;
		PORT
			LAYER M1 ;
			RECT 3.26 6.24 3.74 8.56 ;
			LAYER M1 ;
			RECT 3.34 2.88 3.7 6.24 ;
			LAYER M1 ;
			RECT 3.26 1.76 3.74 2.88 ;
		END
	END out
	PIN GND
		DIRECTION inout ;
		USE GROUND ;
		SHAPE ABUTMENT ;
		PORT
			LAYER M1 ;
			RECT 2.26 1.76 2.74 2.88 ;
			LAYER M1 ;
			RECT 2.32 0.7 2.66 1.76 ;
			LAYER M1 ;
			RECT 0 -0.7 4 0.7 ;
		END
	END GND
	PIN VDD
		DIRECTION inout ;
		USE POWER ;
		SHAPE ABUTMENT ;
		PORT
			LAYER M1 ;
			RECT 0 9.3 4 10.7 ;
			LAYER M1 ;
			RECT 2.32 8.56 2.66 9.3 ;
			LAYER M1 ;
			RECT 2.26 6.24 2.74 8.56 ;
		END
	END VDD
	PIN in
		DIRECTION input ;
		PORT
			LAYER M1 ;
			RECT 1.2 4.2 1.82 4.8 ;
		END
	END in
	OBS
		LAYER M1 ;
		RECT 1.2 6.48 1.68 7.58 ;
		LAYER M1 ;
		RECT 1.2 5.68 1.56 6.48 ;
		LAYER M1 ;
		RECT 2.42 5.68 3.02 5.74 ;
		LAYER M1 ;
		RECT 1.2 5.34 3.02 5.68 ;
		LAYER M1 ;
		RECT 2.16 5.14 3.02 5.34 ;
		LAYER M1 ;
		RECT 2.16 3.66 2.52 5.14 ;
		LAYER M1 ;
		RECT 1.28 3.32 2.52 3.66 ;
		LAYER M1 ;
		RECT 1.28 2.88 1.64 3.32 ;
		LAYER M1 ;
		RECT 1.2 2.36 1.68 2.88 ;
	END
END MMI_BUFB
MACRO MMI_BUFC
	CLASS CORE ;
	FOREIGN MMI_BUFC 0 0 ;
	SIZE 4 BY 10 ;
	SYMMETRY X Y ;
	SITE CORE1 ;
	PIN out
		DIRECTION output ;
		PORT
			LAYER M1 ;
			RECT 1.02 7.74 3.34 8.22 ;
			LAYER M1 ;
			RECT 2.2 7.62 2.8 7.74 ;
			LAYER M1 ;
			RECT 2.2 1.66 2.8 1.8 ;
			LAYER M1 ;
			RECT 0.88 1.18 3.2 1.66 ;
			LAYER VIA1 ;
			RECT 2.32 7.74 2.68 8.1 ;
			LAYER VIA1 ;
			RECT 2.32 1.32 2.68 1.68 ;
			LAYER M2 ;
			RECT 2.2 7.62 2.8 8.22 ;
			LAYER M2 ;
			RECT 2.28 1.8 2.7 7.62 ;
			LAYER M2 ;
			RECT 2.2 1.2 2.8 1.8 ;
		END
	END out
	PIN GND
		DIRECTION inout ;
		USE GROUND ;
		SHAPE ABUTMENT ;
		PORT
			LAYER M1 ;
			RECT 0.88 2.56 3.2 2.66 ;
			LAYER M1 ;
			RECT 0.2 2.2 3.2 2.56 ;
			LAYER M1 ;
			RECT 0.2 0.7 0.56 2.2 ;
			LAYER M1 ;
			RECT 0.88 2.18 3.2 2.2 ;
			LAYER M1 ;
			RECT 0 -0.7 4 0.7 ;
		END
	END GND
	PIN VDD
		DIRECTION inout ;
		USE POWER ;
		SHAPE ABUTMENT ;
		PORT
			LAYER M1 ;
			RECT 0 9.3 4 10.7 ;
			LAYER M1 ;
			RECT 0.2 7.12 0.56 9.3 ;
			LAYER M1 ;
			RECT 1.02 8.74 3.34 9.3 ;
			LAYER M1 ;
			RECT 1.02 7.12 3.34 7.22 ;
			LAYER M1 ;
			RECT 0.2 6.76 3.34 7.12 ;
			LAYER M1 ;
			RECT 1.02 6.74 3.34 6.76 ;
		END
	END VDD
	PIN in
		DIRECTION input ;
		PORT
			LAYER M1 ;
			RECT 0.2 4.2 0.8 4.8 ;
		END
	END in
	OBS
		LAYER M1 ;
		RECT 1.22 5.68 2.74 6.16 ;
		LAYER M1 ;
		RECT 1.78 4.8 2.14 5.68 ;
		LAYER M1 ;
		RECT 1.78 4.2 2.38 4.8 ;
		LAYER M1 ;
		RECT 1.78 3.76 2.14 4.2 ;
		LAYER M1 ;
		RECT 1.6 3.26 2.32 3.76 ;
	END
END MMI_BUFC
MACRO MMI_BUFD
	CLASS CORE ;
	FOREIGN MMI_BUFD 0 0 ;
	SIZE 5 BY 10 ;
	SYMMETRY X Y ;
	SITE CORE1 ;
	PIN out
		DIRECTION output ;
		PORT
			LAYER M1 ;
			RECT 2.26 5.62 2.74 8.72 ;
			LAYER M1 ;
			RECT 4.26 5.62 4.74 8.72 ;
			LAYER M1 ;
			RECT 2.32 5.3 2.66 5.62 ;
			LAYER M1 ;
			RECT 4.34 5.3 4.7 5.62 ;
			LAYER M1 ;
			RECT 2.32 4.94 4.7 5.3 ;
			LAYER M1 ;
			RECT 4.34 3.28 4.7 4.94 ;
			LAYER M1 ;
			RECT 2.46 2.94 4.7 3.28 ;
			LAYER M1 ;
			RECT 2.46 2.62 2.82 2.94 ;
			LAYER M1 ;
			RECT 4.34 2.62 4.7 2.94 ;
			LAYER M1 ;
			RECT 2.26 2.18 2.82 2.62 ;
			LAYER M1 ;
			RECT 2.26 1.1 2.74 2.18 ;
			LAYER M1 ;
			RECT 4.26 1.1 4.74 2.62 ;
		END
	END out
	PIN GND
		DIRECTION inout ;
		USE GROUND ;
		SHAPE ABUTMENT ;
		PORT
			LAYER M1 ;
			RECT 1.26 1.1 1.74 2.62 ;
			LAYER M1 ;
			RECT 3.26 1.1 3.74 2.62 ;
			LAYER M1 ;
			RECT 1.28 0.7 1.64 1.1 ;
			LAYER M1 ;
			RECT 3.34 0.7 3.7 1.1 ;
			LAYER M1 ;
			RECT 0 -0.7 5 0.7 ;
		END
	END GND
	PIN VDD
		DIRECTION inout ;
		USE POWER ;
		SHAPE ABUTMENT ;
		PORT
			LAYER M1 ;
			RECT 0 9.3 5 10.7 ;
			LAYER M1 ;
			RECT 1.38 8.72 1.74 9.3 ;
			LAYER M1 ;
			RECT 3.34 8.72 3.7 9.3 ;
			LAYER M1 ;
			RECT 1.26 5.62 1.74 8.72 ;
			LAYER M1 ;
			RECT 3.26 5.62 3.74 8.72 ;
		END
	END VDD
	PIN in
		DIRECTION input ;
		PORT
			LAYER M1 ;
			RECT 1.08 4.2 1.8 4.8 ;
		END
	END in
	OBS
		LAYER M1 ;
		RECT 0.26 5.62 0.74 8.72 ;
		LAYER M1 ;
		RECT 0.3 3.84 0.64 5.62 ;
		LAYER M1 ;
		RECT 0.3 3.48 2.14 3.84 ;
		LAYER M1 ;
		RECT 0.3 2.62 0.64 3.48 ;
		LAYER M1 ;
		RECT 1.54 3.24 2.14 3.48 ;
		LAYER M1 ;
		RECT 0.26 1.1 0.74 2.62 ;
	END
END MMI_BUFD
MACRO MMI_BUFE
	CLASS CORE ;
	FOREIGN MMI_BUFE 0 0 ;
	SIZE 9 BY 10 ;
	SYMMETRY X Y ;
	SITE CORE1 ;
	PIN out
		DIRECTION output ;
		PORT
			LAYER M1 ;
			RECT 3.26 5.62 3.74 8.72 ;
			LAYER M1 ;
			RECT 5.26 5.62 5.74 8.72 ;
			LAYER M1 ;
			RECT 7.26 5.62 7.74 8.72 ;
			LAYER M1 ;
			RECT 3.32 5.16 3.68 5.62 ;
			LAYER M1 ;
			RECT 5.32 5.16 5.68 5.62 ;
			LAYER M1 ;
			RECT 7.32 5.16 7.68 5.62 ;
			LAYER M1 ;
			RECT 3.32 4.82 7.68 5.16 ;
			LAYER M1 ;
			RECT 7.32 3.56 7.68 4.82 ;
			LAYER M1 ;
			RECT 3.32 3.2 7.68 3.56 ;
			LAYER M1 ;
			RECT 3.32 2.66 3.68 3.2 ;
			LAYER M1 ;
			RECT 5.32 2.66 5.68 3.2 ;
			LAYER M1 ;
			RECT 7.32 2.66 7.68 3.2 ;
			LAYER M1 ;
			RECT 3.26 1.14 3.74 2.66 ;
			LAYER M1 ;
			RECT 5.26 1.14 5.74 2.66 ;
			LAYER M1 ;
			RECT 7.26 1.14 7.74 2.66 ;
		END
	END out
	PIN GND
		DIRECTION inout ;
		USE GROUND ;
		SHAPE ABUTMENT ;
		PORT
			LAYER M1 ;
			RECT 0.26 1.14 0.74 2.66 ;
			LAYER M1 ;
			RECT 2.26 1.14 2.74 2.66 ;
			LAYER M1 ;
			RECT 4.26 1.14 4.74 2.66 ;
			LAYER M1 ;
			RECT 6.26 1.14 6.74 2.66 ;
			LAYER M1 ;
			RECT 8.26 1.14 8.74 2.66 ;
			LAYER M1 ;
			RECT 0.3 0.7 0.64 1.14 ;
			LAYER M1 ;
			RECT 2.26 0.7 2.62 1.14 ;
			LAYER M1 ;
			RECT 4.34 0.7 4.68 1.14 ;
			LAYER M1 ;
			RECT 6.32 0.7 6.66 1.14 ;
			LAYER M1 ;
			RECT 8.32 0.7 8.68 1.14 ;
			LAYER M1 ;
			RECT 0 -0.7 9 0.7 ;
		END
	END GND
	PIN VDD
		DIRECTION inout ;
		USE POWER ;
		SHAPE ABUTMENT ;
		PORT
			LAYER M1 ;
			RECT 0 9.3 9 10.7 ;
			LAYER M1 ;
			RECT 0.24 8.72 0.6 9.3 ;
			LAYER M1 ;
			RECT 2.34 8.72 2.7 9.3 ;
			LAYER M1 ;
			RECT 4.32 8.72 4.66 9.3 ;
			LAYER M1 ;
			RECT 6.24 8.72 6.6 9.3 ;
			LAYER M1 ;
			RECT 8.16 8.72 8.52 9.3 ;
			LAYER M1 ;
			RECT 0.24 6.6 0.74 8.72 ;
			LAYER M1 ;
			RECT 0.26 5.62 0.74 6.6 ;
			LAYER M1 ;
			RECT 2.26 5.62 2.74 8.72 ;
			LAYER M1 ;
			RECT 4.26 5.62 4.74 8.72 ;
			LAYER M1 ;
			RECT 6.24 7.56 6.74 8.72 ;
			LAYER M1 ;
			RECT 8.16 7.56 8.74 8.72 ;
			LAYER M1 ;
			RECT 6.26 5.62 6.74 7.56 ;
			LAYER M1 ;
			RECT 8.26 5.62 8.74 7.56 ;
		END
	END VDD
	PIN in
		DIRECTION input ;
		PORT
			LAYER M1 ;
			RECT 0.2 3.2 0.8 3.8 ;
		END
	END in
	OBS
		LAYER M1 ;
		RECT 1.26 5.62 1.74 8.72 ;
		LAYER M1 ;
		RECT 1.28 4.34 1.64 5.62 ;
		LAYER M1 ;
		RECT 4.52 4.34 5.12 4.48 ;
		LAYER M1 ;
		RECT 1.28 4 5.12 4.34 ;
		LAYER M1 ;
		RECT 1.28 2.66 1.64 4 ;
		LAYER M1 ;
		RECT 4.52 3.88 5.12 4 ;
		LAYER M1 ;
		RECT 1.26 1.14 1.74 2.66 ;
	END
END MMI_BUFE
MACRO MMI_CLKBUFB
	CLASS CORE ;
	FOREIGN MMI_CLKBUFB 0 0 ;
	SIZE 15 BY 10 ;
	SYMMETRY X Y ;
	SITE CORE1 ;
	PIN g_clk
		DIRECTION input ;
		PORT
			LAYER M1 ;
			RECT 5.2 4.2 5.82 4.8 ;
		END
	END g_clk
	PIN scan_out
		DIRECTION output ;
		PORT
			LAYER M1 ;
			RECT 11.66 7.74 13.98 8.22 ;
			LAYER M1 ;
			RECT 12.2 7.62 12.8 7.74 ;
			LAYER M1 ;
			RECT 12.2 1.66 12.8 1.8 ;
			LAYER M1 ;
			RECT 11.8 1.18 14.12 1.66 ;
			LAYER VIA1 ;
			RECT 12.32 7.74 12.68 8.1 ;
			LAYER VIA1 ;
			RECT 12.32 1.32 12.68 1.68 ;
			LAYER M2 ;
			RECT 12.2 7.62 12.8 8.22 ;
			LAYER M2 ;
			RECT 12.3 1.8 12.72 7.62 ;
			LAYER M2 ;
			RECT 12.2 1.2 12.8 1.8 ;
		END
	END scan_out
	PIN GND
		DIRECTION inout ;
		USE GROUND ;
		SHAPE ABUTMENT ;
		PORT
			LAYER M1 ;
			RECT 2.26 1.76 2.74 2.88 ;
			LAYER M1 ;
			RECT 6.26 1.76 6.74 2.88 ;
			LAYER M1 ;
			RECT 11.8 2.56 14.12 2.66 ;
			LAYER M1 ;
			RECT 8.36 2.48 8.72 2.5 ;
			LAYER M1 ;
			RECT 2.32 0.7 2.66 1.76 ;
			LAYER M1 ;
			RECT 6.32 0.7 6.66 1.76 ;
			LAYER M1 ;
			RECT 8.26 1.36 8.74 2.48 ;
			LAYER M1 ;
			RECT 10.26 1.36 10.74 2.48 ;
			LAYER M1 ;
			RECT 11.8 2.2 14.8 2.56 ;
			LAYER M1 ;
			RECT 11.8 2.18 14.12 2.2 ;
			LAYER M1 ;
			RECT 8.36 0.7 8.72 1.36 ;
			LAYER M1 ;
			RECT 10.34 0.7 10.68 1.36 ;
			LAYER M1 ;
			RECT 14.44 0.7 14.8 2.2 ;
			LAYER M1 ;
			RECT 0 -0.7 15 0.7 ;
		END
	END GND
	PIN g_scan_en
		DIRECTION input ;
		PORT
			LAYER M1 ;
			RECT 1.2 4.2 1.82 4.8 ;
		END
	END g_scan_en
	PIN VDD
		DIRECTION inout ;
		USE POWER ;
		SHAPE ABUTMENT ;
		PORT
			LAYER M1 ;
			RECT 0 9.3 15 10.7 ;
			LAYER M1 ;
			RECT 2.32 8.56 2.66 9.3 ;
			LAYER M1 ;
			RECT 6.32 8.56 6.66 9.3 ;
			LAYER M1 ;
			RECT 2.26 6.24 2.74 8.56 ;
			LAYER M1 ;
			RECT 6.26 6.24 6.74 8.56 ;
			LAYER M1 ;
			RECT 8.34 8.12 8.68 9.3 ;
			LAYER M1 ;
			RECT 10.34 8.12 10.68 9.3 ;
			LAYER M1 ;
			RECT 11.66 8.74 13.98 9.3 ;
			LAYER M1 ;
			RECT 8.26 5.8 8.74 8.12 ;
			LAYER M1 ;
			RECT 10.26 5.8 10.74 8.12 ;
			LAYER M1 ;
			RECT 11.66 7.12 13.98 7.22 ;
			LAYER M1 ;
			RECT 14.44 7.12 14.8 9.3 ;
			LAYER M1 ;
			RECT 11.66 6.76 14.8 7.12 ;
			LAYER M1 ;
			RECT 11.66 6.74 13.98 6.76 ;
		END
	END VDD
	PIN clk
		DIRECTION output ;
		PORT
			LAYER M1 ;
			RECT 7.26 6.24 7.74 8.56 ;
			LAYER M1 ;
			RECT 7.34 4.8 7.7 6.24 ;
			LAYER M1 ;
			RECT 7.34 4.2 8.98 4.8 ;
			LAYER M1 ;
			RECT 7.34 2.88 7.7 4.2 ;
			LAYER M1 ;
			RECT 7.26 1.76 7.74 2.88 ;
		END
	END clk
	PIN scan_in
		DIRECTION input ;
		PORT
			LAYER M1 ;
			RECT 14.2 4.2 14.8 4.8 ;
		END
	END scan_in
	PIN scan_en
		DIRECTION output ;
		PORT
			LAYER M1 ;
			RECT 3.26 6.24 3.74 8.56 ;
			LAYER M1 ;
			RECT 3.34 2.88 3.7 6.24 ;
			LAYER M1 ;
			RECT 3.26 1.76 3.74 2.88 ;
		END
	END scan_en
	OBS
		LAYER M1 ;
		RECT 1.2 6.48 1.68 7.58 ;
		LAYER M1 ;
		RECT 1.2 5.68 1.56 6.48 ;
		LAYER M1 ;
		RECT 5.2 6.48 5.68 7.58 ;
		LAYER M1 ;
		RECT 2.42 5.68 3.02 5.74 ;
		LAYER M1 ;
		RECT 1.2 5.34 3.02 5.68 ;
		LAYER M1 ;
		RECT 2.16 5.14 3.02 5.34 ;
		LAYER M1 ;
		RECT 2.16 3.66 2.52 5.14 ;
		LAYER M1 ;
		RECT 1.28 3.32 2.52 3.66 ;
		LAYER M1 ;
		RECT 1.28 2.88 1.64 3.32 ;
		LAYER M1 ;
		RECT 5.2 5.68 5.56 6.48 ;
		LAYER M1 ;
		RECT 6.42 5.68 7.02 5.74 ;
		LAYER M1 ;
		RECT 5.2 5.34 7.02 5.68 ;
		LAYER M1 ;
		RECT 6.16 5.14 7.02 5.34 ;
		LAYER M1 ;
		RECT 6.16 3.66 6.52 5.14 ;
		LAYER M1 ;
		RECT 5.28 3.32 6.52 3.66 ;
		LAYER M1 ;
		RECT 9.26 5.8 9.74 8.12 ;
		LAYER M1 ;
		RECT 5.28 2.88 5.64 3.32 ;
		LAYER M1 ;
		RECT 1.2 2.36 1.68 2.88 ;
		LAYER M1 ;
		RECT 5.2 2.36 5.68 2.88 ;
		LAYER M1 ;
		RECT 8.36 2.48 8.72 2.5 ;
		LAYER M1 ;
		RECT 9.36 2.48 9.72 5.8 ;
		LAYER M1 ;
		RECT 12.26 5.68 13.78 6.16 ;
		LAYER M1 ;
		RECT 12.86 4.8 13.22 5.68 ;
		LAYER M1 ;
		RECT 12.62 4.2 13.22 4.8 ;
		LAYER M1 ;
		RECT 12.86 3.76 13.22 4.2 ;
		LAYER M1 ;
		RECT 12.68 3.26 13.4 3.76 ;
		LAYER M1 ;
		RECT 9.26 1.36 9.74 2.48 ;
	END
END MMI_CLKBUFB
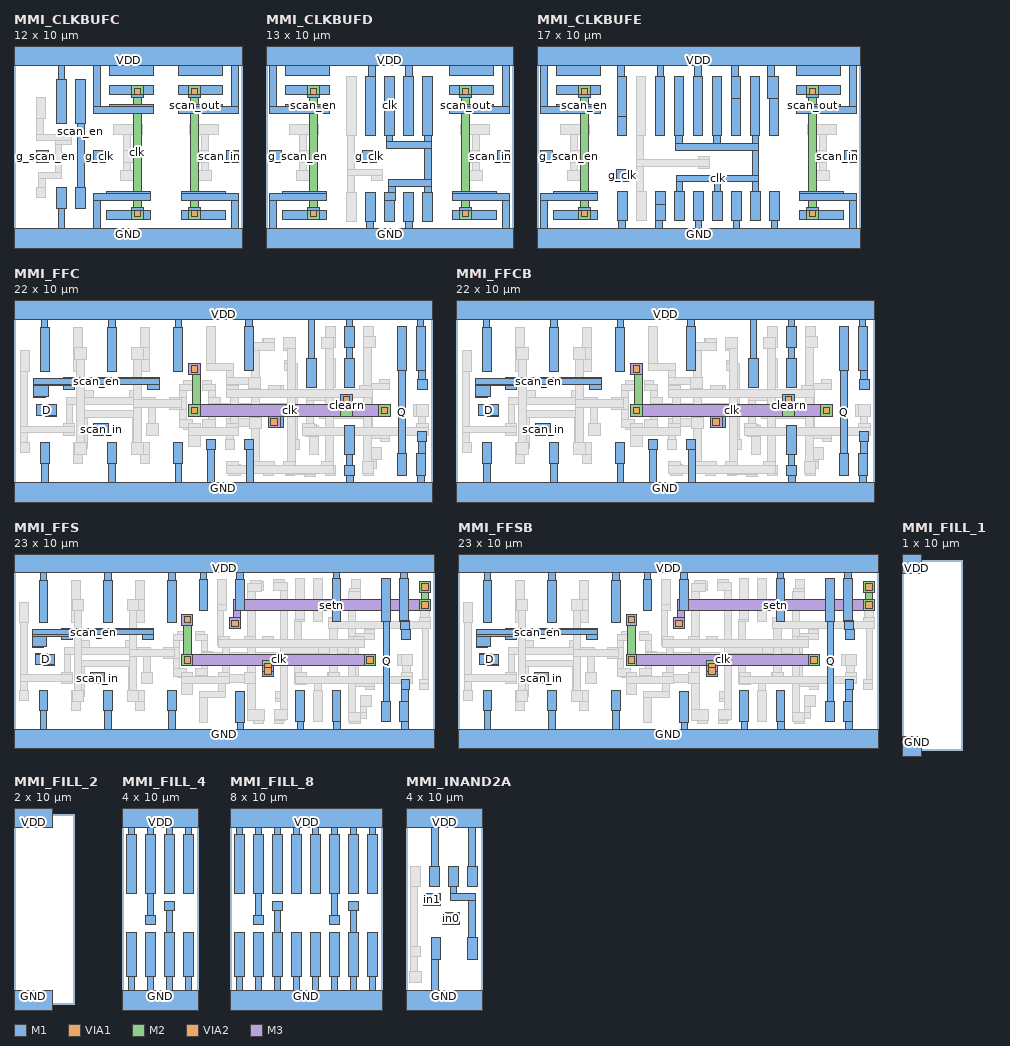
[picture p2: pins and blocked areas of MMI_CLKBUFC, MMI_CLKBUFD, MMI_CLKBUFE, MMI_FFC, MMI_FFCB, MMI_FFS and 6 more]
MACRO MMI_CLKBUFC
	CLASS CORE ;
	FOREIGN MMI_CLKBUFC 0 0 ;
	SIZE 12 BY 10 ;
	SYMMETRY X Y ;
	SITE CORE1 ;
	PIN scan_out
		DIRECTION output ;
		PORT
			LAYER M1 ;
			RECT 8.66 7.74 10.98 8.22 ;
			LAYER M1 ;
			RECT 9.2 7.62 9.8 7.74 ;
			LAYER M1 ;
			RECT 9.2 1.66 9.8 1.8 ;
			LAYER M1 ;
			RECT 8.8 1.18 11.12 1.66 ;
			LAYER VIA1 ;
			RECT 9.32 7.74 9.68 8.1 ;
			LAYER VIA1 ;
			RECT 9.32 1.32 9.68 1.68 ;
			LAYER M2 ;
			RECT 9.2 7.62 9.8 8.22 ;
			LAYER M2 ;
			RECT 9.3 1.8 9.72 7.62 ;
			LAYER M2 ;
			RECT 9.2 1.2 9.8 1.8 ;
		END
	END scan_out
	PIN g_clk
		DIRECTION input ;
		PORT
			LAYER M1 ;
			RECT 4.2 4.2 4.8 4.8 ;
		END
	END g_clk
	PIN GND
		DIRECTION inout ;
		USE GROUND ;
		SHAPE ABUTMENT ;
		PORT
			LAYER M1 ;
			RECT 2.26 1.76 2.74 2.88 ;
			LAYER M1 ;
			RECT 4.88 2.56 7.2 2.66 ;
			LAYER M1 ;
			RECT 4.2 2.2 7.2 2.56 ;
			LAYER M1 ;
			RECT 2.32 0.7 2.66 1.76 ;
			LAYER M1 ;
			RECT 4.2 0.7 4.56 2.2 ;
			LAYER M1 ;
			RECT 4.88 2.18 7.2 2.2 ;
			LAYER M1 ;
			RECT 8.8 2.56 11.12 2.66 ;
			LAYER M1 ;
			RECT 8.8 2.2 11.8 2.56 ;
			LAYER M1 ;
			RECT 8.8 2.18 11.12 2.2 ;
			LAYER M1 ;
			RECT 11.44 0.7 11.8 2.2 ;
			LAYER M1 ;
			RECT 0 -0.7 12 0.7 ;
		END
	END GND
	PIN g_scan_en
		DIRECTION input ;
		PORT
			LAYER M1 ;
			RECT 1.2 4.2 1.82 4.8 ;
		END
	END g_scan_en
	PIN VDD
		DIRECTION inout ;
		USE POWER ;
		SHAPE ABUTMENT ;
		PORT
			LAYER M1 ;
			RECT 0 9.3 12 10.7 ;
			LAYER M1 ;
			RECT 2.32 8.56 2.66 9.3 ;
			LAYER M1 ;
			RECT 2.26 6.24 2.74 8.56 ;
			LAYER M1 ;
			RECT 4.2 7.12 4.56 9.3 ;
			LAYER M1 ;
			RECT 5.02 8.74 7.34 9.3 ;
			LAYER M1 ;
			RECT 8.66 8.74 10.98 9.3 ;
			LAYER M1 ;
			RECT 5.02 7.12 7.34 7.22 ;
			LAYER M1 ;
			RECT 4.2 6.76 7.34 7.12 ;
			LAYER M1 ;
			RECT 5.02 6.74 7.34 6.76 ;
			LAYER M1 ;
			RECT 8.66 7.12 10.98 7.22 ;
			LAYER M1 ;
			RECT 11.44 7.12 11.8 9.3 ;
			LAYER M1 ;
			RECT 8.66 6.76 11.8 7.12 ;
			LAYER M1 ;
			RECT 8.66 6.74 10.98 6.76 ;
		END
	END VDD
	PIN clk
		DIRECTION output ;
		PORT
			LAYER M1 ;
			RECT 5.02 7.74 7.34 8.22 ;
			LAYER M1 ;
			RECT 6.2 7.62 6.8 7.74 ;
			LAYER M1 ;
			RECT 6.2 1.66 6.8 1.8 ;
			LAYER M1 ;
			RECT 4.88 1.18 7.2 1.66 ;
			LAYER VIA1 ;
			RECT 6.32 7.74 6.68 8.1 ;
			LAYER VIA1 ;
			RECT 6.32 1.32 6.68 1.68 ;
			LAYER M2 ;
			RECT 6.2 7.62 6.8 8.22 ;
			LAYER M2 ;
			RECT 6.28 1.8 6.7 7.62 ;
			LAYER M2 ;
			RECT 6.2 1.2 6.8 1.8 ;
		END
	END clk
	PIN scan_en
		DIRECTION output ;
		PORT
			LAYER M1 ;
			RECT 3.26 6.24 3.74 8.56 ;
			LAYER M1 ;
			RECT 3.34 2.88 3.7 6.24 ;
			LAYER M1 ;
			RECT 3.26 1.76 3.74 2.88 ;
		END
	END scan_en
	PIN scan_in
		DIRECTION input ;
		PORT
			LAYER M1 ;
			RECT 11.2 4.2 11.8 4.8 ;
		END
	END scan_in
	OBS
		LAYER M1 ;
		RECT 1.2 6.48 1.68 7.58 ;
		LAYER M1 ;
		RECT 1.2 5.68 1.56 6.48 ;
		LAYER M1 ;
		RECT 2.42 5.68 3.02 5.74 ;
		LAYER M1 ;
		RECT 1.2 5.34 3.02 5.68 ;
		LAYER M1 ;
		RECT 2.16 5.14 3.02 5.34 ;
		LAYER M1 ;
		RECT 2.16 3.66 2.52 5.14 ;
		LAYER M1 ;
		RECT 1.28 3.32 2.52 3.66 ;
		LAYER M1 ;
		RECT 1.28 2.88 1.64 3.32 ;
		LAYER M1 ;
		RECT 5.22 5.68 6.74 6.16 ;
		LAYER M1 ;
		RECT 9.26 5.68 10.78 6.16 ;
		LAYER M1 ;
		RECT 5.78 4.8 6.14 5.68 ;
		LAYER M1 ;
		RECT 9.86 4.8 10.22 5.68 ;
		LAYER M1 ;
		RECT 5.78 4.2 6.38 4.8 ;
		LAYER M1 ;
		RECT 9.62 4.2 10.22 4.8 ;
		LAYER M1 ;
		RECT 5.78 3.76 6.14 4.2 ;
		LAYER M1 ;
		RECT 9.86 3.76 10.22 4.2 ;
		LAYER M1 ;
		RECT 5.6 3.26 6.32 3.76 ;
		LAYER M1 ;
		RECT 9.68 3.26 10.4 3.76 ;
		LAYER M1 ;
		RECT 1.2 2.36 1.68 2.88 ;
	END
END MMI_CLKBUFC
MACRO MMI_CLKBUFD
	CLASS CORE ;
	FOREIGN MMI_CLKBUFD 0 0 ;
	SIZE 13 BY 10 ;
	SYMMETRY X Y ;
	SITE CORE1 ;
	PIN scan_out
		DIRECTION output ;
		PORT
			LAYER M1 ;
			RECT 9.66 7.74 11.98 8.22 ;
			LAYER M1 ;
			RECT 10.2 7.62 10.8 7.74 ;
			LAYER M1 ;
			RECT 10.2 1.66 10.8 1.8 ;
			LAYER M1 ;
			RECT 9.8 1.18 12.12 1.66 ;
			LAYER VIA1 ;
			RECT 10.32 7.74 10.68 8.1 ;
			LAYER VIA1 ;
			RECT 10.32 1.32 10.68 1.68 ;
			LAYER M2 ;
			RECT 10.2 7.62 10.8 8.22 ;
			LAYER M2 ;
			RECT 10.3 1.8 10.72 7.62 ;
			LAYER M2 ;
			RECT 10.2 1.2 10.8 1.8 ;
		END
	END scan_out
	PIN g_clk
		DIRECTION input ;
		PORT
			LAYER M1 ;
			RECT 5.08 4.2 5.8 4.8 ;
		END
	END g_clk
	PIN GND
		DIRECTION inout ;
		USE GROUND ;
		SHAPE ABUTMENT ;
		PORT
			LAYER M1 ;
			RECT 0.88 2.56 3.2 2.66 ;
			LAYER M1 ;
			RECT 0.2 2.2 3.2 2.56 ;
			LAYER M1 ;
			RECT 0.2 0.7 0.56 2.2 ;
			LAYER M1 ;
			RECT 0.88 2.18 3.2 2.2 ;
			LAYER M1 ;
			RECT 5.26 1.1 5.74 2.62 ;
			LAYER M1 ;
			RECT 7.26 1.1 7.74 2.62 ;
			LAYER M1 ;
			RECT 9.8 2.56 12.12 2.66 ;
			LAYER M1 ;
			RECT 9.8 2.2 12.8 2.56 ;
			LAYER M1 ;
			RECT 9.8 2.18 12.12 2.2 ;
			LAYER M1 ;
			RECT 5.28 0.7 5.64 1.1 ;
			LAYER M1 ;
			RECT 7.34 0.7 7.7 1.1 ;
			LAYER M1 ;
			RECT 12.44 0.7 12.8 2.2 ;
			LAYER M1 ;
			RECT 0 -0.7 13 0.7 ;
		END
	END GND
	PIN g_scan_en
		DIRECTION input ;
		PORT
			LAYER M1 ;
			RECT 0.2 4.2 0.8 4.8 ;
		END
	END g_scan_en
	PIN VDD
		DIRECTION inout ;
		USE POWER ;
		SHAPE ABUTMENT ;
		PORT
			LAYER M1 ;
			RECT 0 10.68 4 10.7 ;
			LAYER M1 ;
			RECT 9 10.68 13 10.7 ;
			LAYER M1 ;
			RECT 0 9.3 13 10.68 ;
			LAYER M1 ;
			RECT 0.2 7.12 0.56 9.3 ;
			LAYER M1 ;
			RECT 1.02 8.74 3.34 9.3 ;
			LAYER M1 ;
			RECT 4 9.28 9 9.3 ;
			LAYER M1 ;
			RECT 5.38 8.72 5.74 9.28 ;
			LAYER M1 ;
			RECT 7.34 8.72 7.7 9.28 ;
			LAYER M1 ;
			RECT 9.66 8.74 11.98 9.3 ;
			LAYER M1 ;
			RECT 1.02 7.12 3.34 7.22 ;
			LAYER M1 ;
			RECT 0.2 6.76 3.34 7.12 ;
			LAYER M1 ;
			RECT 1.02 6.74 3.34 6.76 ;
			LAYER M1 ;
			RECT 5.26 5.62 5.74 8.72 ;
			LAYER M1 ;
			RECT 7.26 5.62 7.74 8.72 ;
			LAYER M1 ;
			RECT 9.66 7.12 11.98 7.22 ;
			LAYER M1 ;
			RECT 12.44 7.12 12.8 9.3 ;
			LAYER M1 ;
			RECT 9.66 6.76 12.8 7.12 ;
			LAYER M1 ;
			RECT 9.66 6.74 11.98 6.76 ;
		END
	END VDD
	PIN clk
		DIRECTION output ;
		PORT
			LAYER M1 ;
			RECT 6.26 5.62 6.74 8.72 ;
			LAYER M1 ;
			RECT 8.26 5.62 8.74 8.72 ;
			LAYER M1 ;
			RECT 6.32 5.3 6.66 5.62 ;
			LAYER M1 ;
			RECT 8.34 5.3 8.7 5.62 ;
			LAYER M1 ;
			RECT 6.32 4.94 8.7 5.3 ;
			LAYER M1 ;
			RECT 8.34 3.28 8.7 4.94 ;
			LAYER M1 ;
			RECT 6.46 2.94 8.7 3.28 ;
			LAYER M1 ;
			RECT 6.46 2.62 6.82 2.94 ;
			LAYER M1 ;
			RECT 8.34 2.62 8.7 2.94 ;
			LAYER M1 ;
			RECT 6.26 2.18 6.82 2.62 ;
			LAYER M1 ;
			RECT 6.26 1.1 6.74 2.18 ;
			LAYER M1 ;
			RECT 8.26 1.1 8.74 2.62 ;
		END
	END clk
	PIN scan_in
		DIRECTION input ;
		PORT
			LAYER M1 ;
			RECT 12.2 4.2 12.8 4.8 ;
		END
	END scan_in
	PIN scan_en
		DIRECTION output ;
		PORT
			LAYER M1 ;
			RECT 1.02 7.74 3.34 8.22 ;
			LAYER M1 ;
			RECT 2.2 7.62 2.8 7.74 ;
			LAYER M1 ;
			RECT 2.2 1.66 2.8 1.8 ;
			LAYER M1 ;
			RECT 0.88 1.18 3.2 1.66 ;
			LAYER VIA1 ;
			RECT 2.32 7.74 2.68 8.1 ;
			LAYER VIA1 ;
			RECT 2.32 1.32 2.68 1.68 ;
			LAYER M2 ;
			RECT 2.2 7.62 2.8 8.22 ;
			LAYER M2 ;
			RECT 2.28 1.8 2.7 7.62 ;
			LAYER M2 ;
			RECT 2.2 1.2 2.8 1.8 ;
		END
	END scan_en
	OBS
		LAYER M1 ;
		RECT 0 10.68 4 10.7 ;
		LAYER M1 ;
		RECT 9 10.68 13 10.7 ;
		LAYER M1 ;
		RECT 1.22 5.68 2.74 6.16 ;
		LAYER M1 ;
		RECT 1.78 4.8 2.14 5.68 ;
		LAYER M1 ;
		RECT 4.26 5.62 4.74 8.72 ;
		LAYER M1 ;
		RECT 10.26 5.68 11.78 6.16 ;
		LAYER M1 ;
		RECT 1.78 4.2 2.38 4.8 ;
		LAYER M1 ;
		RECT 1.78 3.76 2.14 4.2 ;
		LAYER M1 ;
		RECT 4.3 3.84 4.64 5.62 ;
		LAYER M1 ;
		RECT 1.6 3.26 2.32 3.76 ;
		LAYER M1 ;
		RECT 4.3 3.48 6.14 3.84 ;
		LAYER M1 ;
		RECT 4.3 2.62 4.64 3.48 ;
		LAYER M1 ;
		RECT 5.54 3.24 6.14 3.48 ;
		LAYER M1 ;
		RECT 10.86 4.8 11.22 5.68 ;
		LAYER M1 ;
		RECT 10.62 4.2 11.22 4.8 ;
		LAYER M1 ;
		RECT 10.86 3.76 11.22 4.2 ;
		LAYER M1 ;
		RECT 10.68 3.26 11.4 3.76 ;
		LAYER M1 ;
		RECT 4.26 1.1 4.74 2.62 ;
	END
END MMI_CLKBUFD
MACRO MMI_CLKBUFE
	CLASS CORE ;
	FOREIGN MMI_CLKBUFE 0 0 ;
	SIZE 17 BY 10 ;
	SYMMETRY X Y ;
	SITE CORE1 ;
	PIN g_clk
		DIRECTION input ;
		PORT
			LAYER M1 ;
			RECT 4.2 3.2 4.8 3.8 ;
		END
	END g_clk
	PIN scan_out
		DIRECTION output ;
		PORT
			LAYER M1 ;
			RECT 13.66 7.74 15.98 8.22 ;
			LAYER M1 ;
			RECT 14.2 7.62 14.8 7.74 ;
			LAYER M1 ;
			RECT 14.2 1.66 14.8 1.8 ;
			LAYER M1 ;
			RECT 13.8 1.18 16.12 1.66 ;
			LAYER VIA1 ;
			RECT 14.32 7.74 14.68 8.1 ;
			LAYER VIA1 ;
			RECT 14.32 1.32 14.68 1.68 ;
			LAYER M2 ;
			RECT 14.2 7.62 14.8 8.22 ;
			LAYER M2 ;
			RECT 14.3 1.8 14.72 7.62 ;
			LAYER M2 ;
			RECT 14.2 1.2 14.8 1.8 ;
		END
	END scan_out
	PIN GND
		DIRECTION inout ;
		USE GROUND ;
		SHAPE ABUTMENT ;
		PORT
			LAYER M1 ;
			RECT 0.88 2.56 3.2 2.66 ;
			LAYER M1 ;
			RECT 0.2 2.2 3.2 2.56 ;
			LAYER M1 ;
			RECT 0.2 0.7 0.56 2.2 ;
			LAYER M1 ;
			RECT 0.88 2.18 3.2 2.2 ;
			LAYER M1 ;
			RECT 4.26 1.14 4.74 2.66 ;
			LAYER M1 ;
			RECT 6.26 1.96 6.74 2.66 ;
			LAYER M1 ;
			RECT 6.22 1.14 6.74 1.96 ;
			LAYER M1 ;
			RECT 8.26 1.14 8.74 2.66 ;
			LAYER M1 ;
			RECT 10.26 1.14 10.74 2.66 ;
			LAYER M1 ;
			RECT 12.26 1.14 12.74 2.66 ;
			LAYER M1 ;
			RECT 13.8 2.56 16.12 2.66 ;
			LAYER M1 ;
			RECT 13.8 2.2 16.8 2.56 ;
			LAYER M1 ;
			RECT 13.8 2.18 16.12 2.2 ;
			LAYER M1 ;
			RECT 4.3 0.7 4.64 1.14 ;
			LAYER M1 ;
			RECT 6.22 0.7 6.58 1.14 ;
			LAYER M1 ;
			RECT 8.34 0.7 8.68 1.14 ;
			LAYER M1 ;
			RECT 10.32 0.7 10.66 1.14 ;
			LAYER M1 ;
			RECT 12.32 0.7 12.68 1.14 ;
			LAYER M1 ;
			RECT 16.44 0.7 16.8 2.2 ;
			LAYER M1 ;
			RECT 0 -0.7 17 0.7 ;
		END
	END GND
	PIN g_scan_en
		DIRECTION input ;
		PORT
			LAYER M1 ;
			RECT 0.2 4.2 0.8 4.8 ;
		END
	END g_scan_en
	PIN VDD
		DIRECTION inout ;
		USE POWER ;
		SHAPE ABUTMENT ;
		PORT
			LAYER M1 ;
			RECT 0 9.3 17 10.7 ;
			LAYER M1 ;
			RECT 0.2 7.12 0.56 9.3 ;
			LAYER M1 ;
			RECT 1.02 8.74 3.34 9.3 ;
			LAYER M1 ;
			RECT 4.22 8.72 4.58 9.3 ;
			LAYER M1 ;
			RECT 6.32 8.72 6.68 9.3 ;
			LAYER M1 ;
			RECT 8.3 8.72 8.64 9.3 ;
			LAYER M1 ;
			RECT 10.22 8.72 10.58 9.3 ;
			LAYER M1 ;
			RECT 12.14 8.72 12.5 9.3 ;
			LAYER M1 ;
			RECT 13.66 8.74 15.98 9.3 ;
			LAYER M1 ;
			RECT 1.02 7.12 3.34 7.22 ;
			LAYER M1 ;
			RECT 0.2 6.76 3.34 7.12 ;
			LAYER M1 ;
			RECT 1.02 6.74 3.34 6.76 ;
			LAYER M1 ;
			RECT 4.22 6.6 4.72 8.72 ;
			LAYER M1 ;
			RECT 4.24 5.62 4.72 6.6 ;
			LAYER M1 ;
			RECT 6.24 5.62 6.72 8.72 ;
			LAYER M1 ;
			RECT 8.24 5.62 8.72 8.72 ;
			LAYER M1 ;
			RECT 10.22 7.56 10.72 8.72 ;
			LAYER M1 ;
			RECT 12.14 7.56 12.72 8.72 ;
			LAYER M1 ;
			RECT 10.24 5.62 10.72 7.56 ;
			LAYER M1 ;
			RECT 12.24 5.62 12.72 7.56 ;
			LAYER M1 ;
			RECT 13.66 7.12 15.98 7.22 ;
			LAYER M1 ;
			RECT 16.44 7.12 16.8 9.3 ;
			LAYER M1 ;
			RECT 13.66 6.76 16.8 7.12 ;
			LAYER M1 ;
			RECT 13.66 6.74 15.98 6.76 ;
		END
	END VDD
	PIN clk
		DIRECTION output ;
		PORT
			LAYER M1 ;
			RECT 7.24 5.62 7.72 8.72 ;
			LAYER M1 ;
			RECT 9.24 5.62 9.72 8.72 ;
			LAYER M1 ;
			RECT 11.24 5.62 11.72 8.72 ;
			LAYER M1 ;
			RECT 7.3 5.16 7.66 5.62 ;
			LAYER M1 ;
			RECT 9.3 5.16 9.66 5.62 ;
			LAYER M1 ;
			RECT 11.32 5.16 11.68 5.62 ;
			LAYER M1 ;
			RECT 7.3 4.82 11.68 5.16 ;
			LAYER M1 ;
			RECT 11.32 3.52 11.68 4.82 ;
			LAYER M1 ;
			RECT 7.32 3.16 11.68 3.52 ;
			LAYER M1 ;
			RECT 7.32 2.66 7.68 3.16 ;
			LAYER M1 ;
			RECT 9.32 2.66 9.68 3.16 ;
			LAYER M1 ;
			RECT 11.32 2.66 11.68 3.16 ;
			LAYER M1 ;
			RECT 7.26 1.14 7.74 2.66 ;
			LAYER M1 ;
			RECT 9.26 1.14 9.74 2.66 ;
			LAYER M1 ;
			RECT 11.26 1.14 11.74 2.66 ;
		END
	END clk
	PIN scan_en
		DIRECTION output ;
		PORT
			LAYER M1 ;
			RECT 1.02 7.74 3.34 8.22 ;
			LAYER M1 ;
			RECT 2.2 7.62 2.8 7.74 ;
			LAYER M1 ;
			RECT 2.2 1.66 2.8 1.8 ;
			LAYER M1 ;
			RECT 0.88 1.18 3.2 1.66 ;
			LAYER VIA1 ;
			RECT 2.32 7.74 2.68 8.1 ;
			LAYER VIA1 ;
			RECT 2.32 1.32 2.68 1.68 ;
			LAYER M2 ;
			RECT 2.2 7.62 2.8 8.22 ;
			LAYER M2 ;
			RECT 2.28 1.8 2.7 7.62 ;
			LAYER M2 ;
			RECT 2.2 1.2 2.8 1.8 ;
		END
	END scan_en
	PIN scan_in
		DIRECTION input ;
		PORT
			LAYER M1 ;
			RECT 16.2 4.2 16.8 4.8 ;
		END
	END scan_in
	OBS
		LAYER M1 ;
		RECT 1.22 5.68 2.74 6.16 ;
		LAYER M1 ;
		RECT 1.78 4.8 2.14 5.68 ;
		LAYER M1 ;
		RECT 5.24 5.62 5.72 8.72 ;
		LAYER M1 ;
		RECT 14.26 5.68 15.78 6.16 ;
		LAYER M1 ;
		RECT 1.78 4.2 2.38 4.8 ;
		LAYER M1 ;
		RECT 5.26 4.34 5.62 5.62 ;
		LAYER M1 ;
		RECT 8.5 4.34 9.1 4.48 ;
		LAYER M1 ;
		RECT 1.78 3.76 2.14 4.2 ;
		LAYER M1 ;
		RECT 5.26 4 9.1 4.34 ;
		LAYER M1 ;
		RECT 1.6 3.26 2.32 3.76 ;
		LAYER M1 ;
		RECT 5.26 2.66 5.62 4 ;
		LAYER M1 ;
		RECT 8.5 3.88 9.1 4 ;
		LAYER M1 ;
		RECT 14.86 4.8 15.22 5.68 ;
		LAYER M1 ;
		RECT 14.62 4.2 15.22 4.8 ;
		LAYER M1 ;
		RECT 14.86 3.76 15.22 4.2 ;
		LAYER M1 ;
		RECT 14.68 3.26 15.4 3.76 ;
		LAYER M1 ;
		RECT 5.26 1.14 5.74 2.66 ;
	END
END MMI_CLKBUFE
MACRO MMI_FFC
	CLASS CORE ;
	FOREIGN MMI_FFC 0 0 ;
	SIZE 22 BY 10 ;
	SYMMETRY X ;
	SITE CORE1 ;
	PIN Q
		DIRECTION output ;
		PORT
			LAYER M1 ;
			RECT 20.16 6.62 20.64 8.94 ;
			LAYER M1 ;
			RECT 20.24 2.22 20.58 6.62 ;
			LAYER M1 ;
			RECT 20.16 1.1 20.64 2.22 ;
		END
	END Q
	PIN D
		DIRECTION input ;
		PORT
			LAYER M1 ;
			RECT 1.2 4.8 1.86 4.84 ;
			LAYER M1 ;
			RECT 1.2 4.24 2.24 4.8 ;
			LAYER M1 ;
			RECT 1.64 4.2 2.24 4.24 ;
		END
	END D
	PIN clearn
		DIRECTION input ;
		PORT
			LAYER M1 ;
			RECT 17.16 4.74 17.8 5.34 ;
			LAYER VIA1 ;
			RECT 17.32 4.86 17.68 5.22 ;
			LAYER M2 ;
			RECT 17.2 4.2 17.8 5.34 ;
		END
	END clearn
	PIN scan_en
		DIRECTION input ;
		PORT
			LAYER M1 ;
			RECT 2.6 6.16 7.64 6.22 ;
			LAYER M1 ;
			RECT 1.04 5.86 7.64 6.16 ;
			LAYER M1 ;
			RECT 1.04 5.8 3.2 5.86 ;
			LAYER M1 ;
			RECT 1.04 5.24 1.8 5.8 ;
			LAYER M1 ;
			RECT 2.6 5.62 3.2 5.8 ;
			LAYER M1 ;
			RECT 7.04 5.62 7.64 5.86 ;
			LAYER M1 ;
			RECT 1.04 5.2 1.64 5.24 ;
		END
	END scan_en
	PIN GND
		DIRECTION inout ;
		USE GROUND ;
		SHAPE ABUTMENT ;
		PORT
			LAYER M1 ;
			RECT 1.38 1.7 1.86 2.82 ;
			LAYER M1 ;
			RECT 4.9 1.7 5.38 2.82 ;
			LAYER M1 ;
			RECT 8.4 1.7 8.88 2.82 ;
			LAYER M1 ;
			RECT 10.14 2.44 10.62 2.96 ;
			LAYER M1 ;
			RECT 12.12 2.44 12.62 2.96 ;
			LAYER M1 ;
			RECT 1.44 0.7 1.8 1.7 ;
			LAYER M1 ;
			RECT 4.96 0.7 5.32 1.7 ;
			LAYER M1 ;
			RECT 8.48 0.7 8.84 1.7 ;
			LAYER M1 ;
			RECT 10.2 0.7 10.56 2.44 ;
			LAYER M1 ;
			RECT 12.22 0.7 12.58 2.44 ;
			LAYER M1 ;
			RECT 17.42 2.2 17.9 3.72 ;
			LAYER M1 ;
			RECT 21.24 2.88 21.72 3.4 ;
			LAYER M1 ;
			RECT 21.3 2.22 21.64 2.88 ;
			LAYER M1 ;
			RECT 17.48 1.58 17.84 2.2 ;
			LAYER M1 ;
			RECT 17.42 1.06 17.9 1.58 ;
			LAYER M1 ;
			RECT 21.16 1.1 21.64 2.22 ;
			LAYER M1 ;
			RECT 17.48 0.7 17.86 1.06 ;
			LAYER M1 ;
			RECT 21.24 0.7 21.6 1.1 ;
			LAYER M1 ;
			RECT 0 -0.7 22 0.7 ;
		END
	END GND
	PIN clk
		DIRECTION input ;
		PORT
			LAYER M1 ;
			RECT 9.2 6.4 9.8 7 ;
			LAYER M1 ;
			RECT 19.2 4.2 19.8 4.8 ;
			LAYER M1 ;
			RECT 13.4 3.6 14.2 4.2 ;
			LAYER VIA1 ;
			RECT 9.32 6.52 9.68 6.88 ;
			LAYER VIA1 ;
			RECT 19.32 4.32 19.68 4.68 ;
			LAYER VIA1 ;
			RECT 13.52 3.72 13.88 4.08 ;
			LAYER M2 ;
			RECT 9.2 6.4 9.8 7 ;
			LAYER M2 ;
			RECT 9.4 4.8 9.8 6.4 ;
			LAYER M2 ;
			RECT 9.2 4.2 9.8 4.8 ;
			LAYER M2 ;
			RECT 19.2 4.2 19.8 4.8 ;
			LAYER M2 ;
			RECT 13.4 3.6 14 4.2 ;
			LAYER VIA2 ;
			RECT 9.32 6.52 9.68 6.88 ;
			LAYER VIA2 ;
			RECT 9.32 4.32 9.68 4.68 ;
			LAYER VIA2 ;
			RECT 19.32 4.32 19.68 4.68 ;
			LAYER VIA2 ;
			RECT 13.52 3.72 13.88 4.08 ;
			LAYER M3 ;
			RECT 9.2 6.4 9.8 7 ;
			LAYER M3 ;
			RECT 9.2 4.2 19.8 4.8 ;
			LAYER M3 ;
			RECT 13.4 3.6 14 4.2 ;
		END
	END clk
	PIN scan_in
		DIRECTION input ;
		PORT
			LAYER M1 ;
			RECT 4.2 3.2 4.96 3.8 ;
		END
	END scan_in
	PIN VDD
		DIRECTION inout ;
		USE POWER ;
		SHAPE ABUTMENT ;
		PORT
			LAYER M1 ;
			RECT 0 9.3 22 10.7 ;
			LAYER M1 ;
			RECT 1.44 8.86 1.78 9.3 ;
			LAYER M1 ;
			RECT 4.98 8.86 5.34 9.3 ;
			LAYER M1 ;
			RECT 8.48 8.86 8.84 9.3 ;
			LAYER M1 ;
			RECT 12.2 8.92 12.56 9.3 ;
			LAYER M1 ;
			RECT 1.38 6.54 1.86 8.86 ;
			LAYER M1 ;
			RECT 4.9 6.54 5.38 8.86 ;
			LAYER M1 ;
			RECT 8.4 6.54 8.88 8.86 ;
			LAYER M1 ;
			RECT 12.14 6.6 12.62 8.92 ;
			LAYER M1 ;
			RECT 15.48 7.22 15.84 9.3 ;
			LAYER M1 ;
			RECT 17.48 8.92 17.84 9.3 ;
			LAYER M1 ;
			RECT 21.24 8.94 21.56 9.3 ;
			LAYER M1 ;
			RECT 17.42 7.82 17.9 8.92 ;
			LAYER M1 ;
			RECT 17.48 7.22 17.84 7.82 ;
			LAYER M1 ;
			RECT 15.42 5.7 15.9 7.22 ;
			LAYER M1 ;
			RECT 17.42 5.7 17.9 7.22 ;
			LAYER M1 ;
			RECT 21.16 6.62 21.64 8.94 ;
			LAYER M1 ;
			RECT 21.3 6.14 21.64 6.62 ;
			LAYER M1 ;
			RECT 21.24 5.62 21.74 6.14 ;
			LAYER M1 ;
			RECT 21.3 5.58 21.64 5.62 ;
		END
	END VDD
	OBS
		LAYER M1 ;
		RECT 0.32 6.54 0.8 7.64 ;
		LAYER M1 ;
		RECT 3.14 7.8 3.62 8.86 ;
		LAYER M1 ;
		RECT 3.14 7.2 3.8 7.8 ;
		LAYER M1 ;
		RECT 3.14 6.54 3.62 7.2 ;
		LAYER M1 ;
		RECT 6.66 7.8 7.14 8.86 ;
		LAYER M1 ;
		RECT 6.2 7.2 7.14 7.8 ;
		LAYER M1 ;
		RECT 6.66 6.54 7.14 7.2 ;
		LAYER M1 ;
		RECT 0.36 3.68 0.72 6.54 ;
		LAYER M1 ;
		RECT 10.14 6.96 10.62 8.92 ;
		LAYER M1 ;
		RECT 10.14 6.6 11.56 6.96 ;
		LAYER M1 ;
		RECT 13.08 7.68 13.72 8.28 ;
		LAYER M1 ;
		RECT 14.2 7.66 14.84 8.34 ;
		LAYER M1 ;
		RECT 16.42 8.36 16.9 8.92 ;
		LAYER M1 ;
		RECT 16.2 7.82 16.9 8.36 ;
		LAYER M1 ;
		RECT 18.42 8.4 18.9 8.92 ;
		LAYER M1 ;
		RECT 16.2 7.76 16.8 7.82 ;
		LAYER M1 ;
		RECT 18.4 7.8 19 8.4 ;
		LAYER M1 ;
		RECT 14.22 6.98 14.7 7.12 ;
		LAYER M1 ;
		RECT 14.22 6.6 14.94 6.98 ;
		LAYER M1 ;
		RECT 11.2 6.24 11.56 6.6 ;
		LAYER M1 ;
		RECT 12.36 6.24 12.96 6.26 ;
		LAYER M1 ;
		RECT 8.94 5.86 9.42 6.06 ;
		LAYER M1 ;
		RECT 8.72 5.54 9.42 5.86 ;
		LAYER M1 ;
		RECT 9.94 5.88 10.42 6.06 ;
		LAYER M1 ;
		RECT 11.2 5.88 12.96 6.24 ;
		LAYER M1 ;
		RECT 9.94 5.54 10.62 5.88 ;
		LAYER M1 ;
		RECT 12.36 5.66 12.96 5.88 ;
		LAYER M1 ;
		RECT 3.56 5.16 4.16 5.54 ;
		LAYER M1 ;
		RECT 6.08 5.16 6.68 5.54 ;
		LAYER M1 ;
		RECT 8.72 5.16 9.08 5.54 ;
		LAYER M1 ;
		RECT 2.74 4.8 7.46 5.16 ;
		LAYER M1 ;
		RECT 2.74 3.8 3.1 4.8 ;
		LAYER M1 ;
		RECT 3.52 4.12 6.62 4.48 ;
		LAYER M1 ;
		RECT 2.6 3.68 3.2 3.8 ;
		LAYER M1 ;
		RECT 0.36 3.32 3.2 3.68 ;
		LAYER M1 ;
		RECT 0.36 2.82 0.72 3.32 ;
		LAYER M1 ;
		RECT 2.6 3.2 3.2 3.32 ;
		LAYER M1 ;
		RECT 3.52 2.82 3.88 4.12 ;
		LAYER M1 ;
		RECT 6.26 2.82 6.62 4.12 ;
		LAYER M1 ;
		RECT 7.1 3.8 7.46 4.8 ;
		LAYER M1 ;
		RECT 8.2 4.56 9.08 5.16 ;
		LAYER M1 ;
		RECT 8.72 4.04 9.08 4.56 ;
		LAYER M1 ;
		RECT 10.26 5.18 10.62 5.54 ;
		LAYER M1 ;
		RECT 13.4 5.2 14.2 5.8 ;
		LAYER M1 ;
		RECT 10.26 4.88 10.88 5.18 ;
		LAYER M1 ;
		RECT 14.54 4.88 14.94 6.6 ;
		LAYER M1 ;
		RECT 16.42 5.7 16.9 7.22 ;
		LAYER M1 ;
		RECT 19.24 5.94 19.74 6.14 ;
		LAYER M1 ;
		RECT 16.48 5.38 16.84 5.7 ;
		LAYER M1 ;
		RECT 10.26 4.52 14.94 4.88 ;
		LAYER M1 ;
		RECT 10.26 4.04 10.62 4.52 ;
		LAYER M1 ;
		RECT 12.4 4.06 13 4.14 ;
		LAYER M1 ;
		RECT 6.98 3.2 7.58 3.8 ;
		LAYER M1 ;
		RECT 8.72 3.6 9.42 4.04 ;
		LAYER M1 ;
		RECT 8.94 3.52 9.42 3.6 ;
		LAYER M1 ;
		RECT 9.94 3.62 10.62 4.04 ;
		LAYER M1 ;
		RECT 11.2 3.66 13 4.06 ;
		LAYER M1 ;
		RECT 9.94 3.52 10.42 3.62 ;
		LAYER M1 ;
		RECT 0.32 2.3 0.8 2.82 ;
		LAYER M1 ;
		RECT 3.14 2.5 3.88 2.82 ;
		LAYER M1 ;
		RECT 3.14 2.2 3.8 2.5 ;
		LAYER M1 ;
		RECT 3.14 1.7 3.62 2.2 ;
		LAYER M1 ;
		RECT 6.26 2.8 7.14 2.82 ;
		LAYER M1 ;
		RECT 6.2 2.2 7.14 2.8 ;
		LAYER M1 ;
		RECT 6.66 1.7 7.14 2.2 ;
		LAYER M1 ;
		RECT 9.2 2.6 9.8 3.2 ;
		LAYER M1 ;
		RECT 11.2 2.96 11.56 3.66 ;
		LAYER M1 ;
		RECT 12.4 3.54 13 3.66 ;
		LAYER M1 ;
		RECT 14.54 2.96 14.94 4.52 ;
		LAYER M1 ;
		RECT 15.4 5.02 16.84 5.38 ;
		LAYER M1 ;
		RECT 18.5 5.62 19.74 5.94 ;
		LAYER M1 ;
		RECT 15.4 3.74 15.76 5.02 ;
		LAYER M1 ;
		RECT 16.08 4.4 16.68 4.7 ;
		LAYER M1 ;
		RECT 18.5 4.4 18.88 5.62 ;
		LAYER M1 ;
		RECT 16.08 4.1 18.88 4.4 ;
		LAYER M1 ;
		RECT 16.22 4.06 18.88 4.1 ;
		LAYER M1 ;
		RECT 15.34 3.72 15.94 3.74 ;
		LAYER M1 ;
		RECT 15.34 3.14 16.02 3.72 ;
		LAYER M1 ;
		RECT 11.14 2.44 11.62 2.96 ;
		LAYER M1 ;
		RECT 14.52 2.44 15.02 2.96 ;
		LAYER M1 ;
		RECT 11.2 1.68 11.8 1.8 ;
		LAYER M1 ;
		RECT 11.2 1.2 11.9 1.68 ;
		LAYER M1 ;
		RECT 11.3 1.08 11.9 1.2 ;
		LAYER M1 ;
		RECT 15.54 2.2 16.02 3.14 ;
		LAYER M1 ;
		RECT 18.5 3.38 18.88 4.06 ;
		LAYER M1 ;
		RECT 19.28 3.38 19.76 3.4 ;
		LAYER M1 ;
		RECT 18.5 3.02 19.76 3.38 ;
		LAYER M1 ;
		RECT 19.28 2.88 19.76 3.02 ;
		LAYER M1 ;
		RECT 13.1 1.2 13.7 1.8 ;
		LAYER M1 ;
		RECT 14.2 1.5 14.8 1.8 ;
		LAYER M1 ;
		RECT 15.28 1.5 15.88 1.62 ;
		LAYER M1 ;
		RECT 14.2 1.2 15.88 1.5 ;
		LAYER M1 ;
		RECT 16.2 1.58 16.8 1.8 ;
		LAYER M1 ;
		RECT 18.72 1.94 19.32 2.54 ;
		LAYER M1 ;
		RECT 21 4.2 21.8 4.8 ;
		LAYER M1 ;
		RECT 18.72 1.8 19.08 1.94 ;
		LAYER M1 ;
		RECT 16.2 1.2 16.9 1.58 ;
		LAYER M1 ;
		RECT 13.14 1.06 13.64 1.2 ;
		LAYER M1 ;
		RECT 14.28 1.12 15.88 1.2 ;
		LAYER M1 ;
		RECT 14.28 1.06 14.78 1.12 ;
		LAYER M1 ;
		RECT 15.28 1.02 15.88 1.12 ;
		LAYER M1 ;
		RECT 16.42 1.06 16.9 1.2 ;
		LAYER M1 ;
		RECT 18.34 1.46 19.08 1.8 ;
		LAYER M1 ;
		RECT 18.34 1.2 18.94 1.46 ;
		LAYER M1 ;
		RECT 18.42 1.06 18.9 1.2 ;
		LAYER M2 ;
		RECT 13.12 8.08 13.72 8.28 ;
		LAYER M2 ;
		RECT 3.2 7.2 3.8 7.8 ;
		LAYER M2 ;
		RECT 6.2 7.2 6.8 7.8 ;
		LAYER M2 ;
		RECT 12.52 7.68 13.72 8.08 ;
		LAYER M2 ;
		RECT 14.2 7.74 14.8 8.34 ;
		LAYER M2 ;
		RECT 16.2 7.76 16.8 8.36 ;
		LAYER M2 ;
		RECT 3.3 2.8 3.7 7.2 ;
		LAYER M2 ;
		RECT 6.3 5.06 6.7 7.2 ;
		LAYER M2 ;
		RECT 8.2 5.06 8.8 5.16 ;
		LAYER M2 ;
		RECT 6.3 4.66 8.8 5.06 ;
		LAYER M2 ;
		RECT 12.52 6.26 12.92 7.68 ;
		LAYER M2 ;
		RECT 11.2 5.2 11.8 5.8 ;
		LAYER M2 ;
		RECT 12.36 5.66 12.96 6.26 ;
		LAYER M2 ;
		RECT 6.3 2.8 6.7 4.66 ;
		LAYER M2 ;
		RECT 8.2 4.56 8.8 4.66 ;
		LAYER M2 ;
		RECT 11.4 3.8 11.8 5.2 ;
		LAYER M2 ;
		RECT 12.52 4.14 12.92 5.66 ;
		LAYER M2 ;
		RECT 13.4 5.2 14 5.8 ;
		LAYER M2 ;
		RECT 3.2 2.2 3.8 2.8 ;
		LAYER M2 ;
		RECT 6.2 2.2 6.8 2.8 ;
		LAYER M2 ;
		RECT 9.2 2.6 9.8 3.8 ;
		LAYER M2 ;
		RECT 11.2 3.2 11.8 3.8 ;
		LAYER M2 ;
		RECT 12.4 3.54 13 4.14 ;
		LAYER M2 ;
		RECT 12.52 1.8 12.92 3.54 ;
		LAYER M2 ;
		RECT 14.4 1.8 14.8 7.74 ;
		LAYER M2 ;
		RECT 15.2 3.74 15.8 3.8 ;
		LAYER M2 ;
		RECT 15.2 3.2 15.94 3.74 ;
		LAYER M2 ;
		RECT 15.34 3.14 15.94 3.2 ;
		LAYER M2 ;
		RECT 16.4 1.8 16.8 7.76 ;
		LAYER M2 ;
		RECT 18.4 7.8 19 8.4 ;
		LAYER M2 ;
		RECT 18.4 5.8 18.8 7.8 ;
		LAYER M2 ;
		RECT 18.2 5.2 18.8 5.8 ;
		LAYER M2 ;
		RECT 18.4 1.8 18.8 5.2 ;
		LAYER M2 ;
		RECT 21.2 4.2 21.8 4.8 ;
		LAYER M2 ;
		RECT 21.28 3.8 21.68 4.2 ;
		LAYER M2 ;
		RECT 21.2 3.2 21.8 3.8 ;
		LAYER M2 ;
		RECT 11.2 1.2 11.8 1.8 ;
		LAYER M2 ;
		RECT 12.52 1.4 13.7 1.8 ;
		LAYER M2 ;
		RECT 13.1 1.2 13.7 1.4 ;
		LAYER M2 ;
		RECT 14.2 1.2 14.8 1.8 ;
		LAYER M2 ;
		RECT 16.2 1.2 16.8 1.8 ;
		LAYER M2 ;
		RECT 18.34 1.2 18.94 1.8 ;
		LAYER M3 ;
		RECT 11.2 5.6 11.8 5.8 ;
		LAYER M3 ;
		RECT 13.4 5.6 14 5.8 ;
		LAYER M3 ;
		RECT 18.2 5.6 18.8 5.8 ;
		LAYER M3 ;
		RECT 11.2 5.2 18.88 5.6 ;
		LAYER M3 ;
		RECT 9.2 3.6 9.8 3.8 ;
		LAYER M3 ;
		RECT 11.2 3.6 11.8 3.8 ;
		LAYER M3 ;
		RECT 15.2 3.6 15.8 3.8 ;
		LAYER M3 ;
		RECT 21.2 3.6 21.8 3.8 ;
		LAYER M3 ;
		RECT 9.2 3.2 11.8 3.6 ;
		LAYER M3 ;
		RECT 15.2 3.2 21.8 3.6 ;
		LAYER M3 ;
		RECT 11.2 1.6 11.8 1.8 ;
		LAYER M3 ;
		RECT 16.2 1.6 16.8 1.8 ;
		LAYER M3 ;
		RECT 11.2 1.2 16.8 1.6 ;
	END
END MMI_FFC
MACRO MMI_FFCB
	CLASS CORE ;
	FOREIGN MMI_FFCB 0 0 ;
	SIZE 22 BY 10 ;
	SYMMETRY X ;
	SITE CORE1 ;
	PIN Q
		DIRECTION output ;
		PORT
			LAYER M1 ;
			RECT 20.16 6.62 20.64 8.94 ;
			LAYER M1 ;
			RECT 20.24 2.22 20.58 6.62 ;
			LAYER M1 ;
			RECT 20.16 1.1 20.64 2.22 ;
		END
	END Q
	PIN D
		DIRECTION input ;
		PORT
			LAYER M1 ;
			RECT 1.2 4.8 1.86 4.84 ;
			LAYER M1 ;
			RECT 1.2 4.24 2.24 4.8 ;
			LAYER M1 ;
			RECT 1.64 4.2 2.24 4.24 ;
		END
	END D
	PIN clearn
		DIRECTION input ;
		PORT
			LAYER M1 ;
			RECT 17.16 4.74 17.8 5.34 ;
			LAYER VIA1 ;
			RECT 17.32 4.86 17.68 5.22 ;
			LAYER M2 ;
			RECT 17.2 4.2 17.8 5.34 ;
		END
	END clearn
	PIN scan_en
		DIRECTION input ;
		PORT
			LAYER M1 ;
			RECT 2.6 6.16 7.64 6.22 ;
			LAYER M1 ;
			RECT 1.04 5.86 7.64 6.16 ;
			LAYER M1 ;
			RECT 1.04 5.8 3.2 5.86 ;
			LAYER M1 ;
			RECT 1.04 5.24 1.8 5.8 ;
			LAYER M1 ;
			RECT 2.6 5.62 3.2 5.8 ;
			LAYER M1 ;
			RECT 7.04 5.62 7.64 5.86 ;
			LAYER M1 ;
			RECT 1.04 5.2 1.64 5.24 ;
		END
	END scan_en
	PIN GND
		DIRECTION inout ;
		USE GROUND ;
		SHAPE ABUTMENT ;
		PORT
			LAYER M1 ;
			RECT 1.38 1.7 1.86 2.82 ;
			LAYER M1 ;
			RECT 4.9 1.7 5.38 2.82 ;
			LAYER M1 ;
			RECT 8.4 1.7 8.88 2.82 ;
			LAYER M1 ;
			RECT 10.14 2.44 10.62 2.96 ;
			LAYER M1 ;
			RECT 12.12 2.44 12.62 2.96 ;
			LAYER M1 ;
			RECT 1.44 0.7 1.8 1.7 ;
			LAYER M1 ;
			RECT 4.96 0.7 5.32 1.7 ;
			LAYER M1 ;
			RECT 8.48 0.7 8.84 1.7 ;
			LAYER M1 ;
			RECT 10.2 0.7 10.56 2.44 ;
			LAYER M1 ;
			RECT 12.22 0.7 12.58 2.44 ;
			LAYER M1 ;
			RECT 17.42 2.2 17.9 3.72 ;
			LAYER M1 ;
			RECT 21.24 2.88 21.72 3.4 ;
			LAYER M1 ;
			RECT 21.3 2.22 21.64 2.88 ;
			LAYER M1 ;
			RECT 17.48 1.58 17.84 2.2 ;
			LAYER M1 ;
			RECT 17.42 1.06 17.9 1.58 ;
			LAYER M1 ;
			RECT 21.16 1.1 21.64 2.22 ;
			LAYER M1 ;
			RECT 17.48 0.7 17.86 1.06 ;
			LAYER M1 ;
			RECT 21.24 0.7 21.6 1.1 ;
			LAYER M1 ;
			RECT 0 -0.7 22 0.7 ;
		END
	END GND
	PIN clk
		DIRECTION input ;
		PORT
			LAYER M1 ;
			RECT 9.2 6.4 9.8 7 ;
			LAYER M1 ;
			RECT 19.2 4.2 19.8 4.8 ;
			LAYER M1 ;
			RECT 13.4 3.6 14.2 4.2 ;
			LAYER VIA1 ;
			RECT 9.32 6.52 9.68 6.88 ;
			LAYER VIA1 ;
			RECT 19.32 4.32 19.68 4.68 ;
			LAYER VIA1 ;
			RECT 13.52 3.72 13.88 4.08 ;
			LAYER M2 ;
			RECT 9.2 6.4 9.8 7 ;
			LAYER M2 ;
			RECT 9.4 4.8 9.8 6.4 ;
			LAYER M2 ;
			RECT 9.2 4.2 9.8 4.8 ;
			LAYER M2 ;
			RECT 19.2 4.2 19.8 4.8 ;
			LAYER M2 ;
			RECT 13.4 3.6 14 4.2 ;
			LAYER VIA2 ;
			RECT 9.32 6.52 9.68 6.88 ;
			LAYER VIA2 ;
			RECT 9.32 4.32 9.68 4.68 ;
			LAYER VIA2 ;
			RECT 19.32 4.32 19.68 4.68 ;
			LAYER VIA2 ;
			RECT 13.52 3.72 13.88 4.08 ;
			LAYER M3 ;
			RECT 9.2 6.4 9.8 7 ;
			LAYER M3 ;
			RECT 9.2 4.2 19.8 4.8 ;
			LAYER M3 ;
			RECT 13.4 3.6 14 4.2 ;
		END
	END clk
	PIN scan_in
		DIRECTION input ;
		PORT
			LAYER M1 ;
			RECT 4.2 3.2 4.96 3.8 ;
		END
	END scan_in
	PIN VDD
		DIRECTION inout ;
		USE POWER ;
		SHAPE ABUTMENT ;
		PORT
			LAYER M1 ;
			RECT 0 9.3 22 10.7 ;
			LAYER M1 ;
			RECT 1.44 8.86 1.78 9.3 ;
			LAYER M1 ;
			RECT 4.98 8.86 5.34 9.3 ;
			LAYER M1 ;
			RECT 8.48 8.86 8.84 9.3 ;
			LAYER M1 ;
			RECT 12.2 8.92 12.56 9.3 ;
			LAYER M1 ;
			RECT 1.38 6.54 1.86 8.86 ;
			LAYER M1 ;
			RECT 4.9 6.54 5.38 8.86 ;
			LAYER M1 ;
			RECT 8.4 6.54 8.88 8.86 ;
			LAYER M1 ;
			RECT 12.14 6.6 12.62 8.92 ;
			LAYER M1 ;
			RECT 15.48 7.22 15.84 9.3 ;
			LAYER M1 ;
			RECT 17.48 8.92 17.84 9.3 ;
			LAYER M1 ;
			RECT 21.24 8.94 21.56 9.3 ;
			LAYER M1 ;
			RECT 17.42 7.82 17.9 8.92 ;
			LAYER M1 ;
			RECT 17.48 7.22 17.84 7.82 ;
			LAYER M1 ;
			RECT 15.42 5.7 15.9 7.22 ;
			LAYER M1 ;
			RECT 17.42 5.7 17.9 7.22 ;
			LAYER M1 ;
			RECT 21.16 6.62 21.64 8.94 ;
			LAYER M1 ;
			RECT 21.3 6.14 21.64 6.62 ;
			LAYER M1 ;
			RECT 21.24 5.62 21.74 6.14 ;
			LAYER M1 ;
			RECT 21.3 5.58 21.64 5.62 ;
		END
	END VDD
	OBS
		LAYER M1 ;
		RECT 0.32 6.54 0.8 7.64 ;
		LAYER M1 ;
		RECT 3.14 7.8 3.62 8.86 ;
		LAYER M1 ;
		RECT 3.14 7.2 3.8 7.8 ;
		LAYER M1 ;
		RECT 3.14 6.54 3.62 7.2 ;
		LAYER M1 ;
		RECT 6.66 7.8 7.14 8.86 ;
		LAYER M1 ;
		RECT 6.2 7.2 7.14 7.8 ;
		LAYER M1 ;
		RECT 6.66 6.54 7.14 7.2 ;
		LAYER M1 ;
		RECT 0.36 3.68 0.72 6.54 ;
		LAYER M1 ;
		RECT 10.14 6.96 10.62 8.92 ;
		LAYER M1 ;
		RECT 10.14 6.6 11.56 6.96 ;
		LAYER M1 ;
		RECT 13.08 7.68 13.72 8.28 ;
		LAYER M1 ;
		RECT 14.2 7.66 14.84 8.34 ;
		LAYER M1 ;
		RECT 16.42 8.36 16.9 8.92 ;
		LAYER M1 ;
		RECT 16.2 7.82 16.9 8.36 ;
		LAYER M1 ;
		RECT 18.42 8.4 18.9 8.92 ;
		LAYER M1 ;
		RECT 16.2 7.76 16.8 7.82 ;
		LAYER M1 ;
		RECT 18.4 7.8 19 8.4 ;
		LAYER M1 ;
		RECT 14.22 6.98 14.7 7.12 ;
		LAYER M1 ;
		RECT 14.22 6.6 14.94 6.98 ;
		LAYER M1 ;
		RECT 11.2 6.24 11.56 6.6 ;
		LAYER M1 ;
		RECT 12.36 6.24 12.96 6.26 ;
		LAYER M1 ;
		RECT 8.94 5.86 9.42 6.06 ;
		LAYER M1 ;
		RECT 8.72 5.54 9.42 5.86 ;
		LAYER M1 ;
		RECT 9.94 5.88 10.42 6.06 ;
		LAYER M1 ;
		RECT 11.2 5.88 12.96 6.24 ;
		LAYER M1 ;
		RECT 9.94 5.54 10.62 5.88 ;
		LAYER M1 ;
		RECT 12.36 5.66 12.96 5.88 ;
		LAYER M1 ;
		RECT 3.56 5.16 4.16 5.54 ;
		LAYER M1 ;
		RECT 6.08 5.16 6.68 5.54 ;
		LAYER M1 ;
		RECT 8.72 5.16 9.08 5.54 ;
		LAYER M1 ;
		RECT 2.74 4.8 7.46 5.16 ;
		LAYER M1 ;
		RECT 2.74 3.8 3.1 4.8 ;
		LAYER M1 ;
		RECT 3.52 4.12 6.62 4.48 ;
		LAYER M1 ;
		RECT 2.6 3.68 3.2 3.8 ;
		LAYER M1 ;
		RECT 0.36 3.32 3.2 3.68 ;
		LAYER M1 ;
		RECT 0.36 2.82 0.72 3.32 ;
		LAYER M1 ;
		RECT 2.6 3.2 3.2 3.32 ;
		LAYER M1 ;
		RECT 3.52 2.82 3.88 4.12 ;
		LAYER M1 ;
		RECT 6.26 2.82 6.62 4.12 ;
		LAYER M1 ;
		RECT 7.1 3.8 7.46 4.8 ;
		LAYER M1 ;
		RECT 8.2 4.56 9.08 5.16 ;
		LAYER M1 ;
		RECT 8.72 4.04 9.08 4.56 ;
		LAYER M1 ;
		RECT 10.26 5.18 10.62 5.54 ;
		LAYER M1 ;
		RECT 13.4 5.2 14.2 5.8 ;
		LAYER M1 ;
		RECT 10.26 4.88 10.88 5.18 ;
		LAYER M1 ;
		RECT 14.54 4.88 14.94 6.6 ;
		LAYER M1 ;
		RECT 16.42 5.7 16.9 7.22 ;
		LAYER M1 ;
		RECT 19.24 5.94 19.74 6.14 ;
		LAYER M1 ;
		RECT 16.48 5.38 16.84 5.7 ;
		LAYER M1 ;
		RECT 10.26 4.52 14.94 4.88 ;
		LAYER M1 ;
		RECT 10.26 4.04 10.62 4.52 ;
		LAYER M1 ;
		RECT 12.4 4.06 13 4.14 ;
		LAYER M1 ;
		RECT 6.98 3.2 7.58 3.8 ;
		LAYER M1 ;
		RECT 8.72 3.6 9.42 4.04 ;
		LAYER M1 ;
		RECT 8.94 3.52 9.42 3.6 ;
		LAYER M1 ;
		RECT 9.94 3.62 10.62 4.04 ;
		LAYER M1 ;
		RECT 11.2 3.66 13 4.06 ;
		LAYER M1 ;
		RECT 9.94 3.52 10.42 3.62 ;
		LAYER M1 ;
		RECT 0.32 2.3 0.8 2.82 ;
		LAYER M1 ;
		RECT 3.14 2.5 3.88 2.82 ;
		LAYER M1 ;
		RECT 3.14 2.2 3.8 2.5 ;
		LAYER M1 ;
		RECT 3.14 1.7 3.62 2.2 ;
		LAYER M1 ;
		RECT 6.26 2.8 7.14 2.82 ;
		LAYER M1 ;
		RECT 6.2 2.2 7.14 2.8 ;
		LAYER M1 ;
		RECT 6.66 1.7 7.14 2.2 ;
		LAYER M1 ;
		RECT 9.2 2.6 9.8 3.2 ;
		LAYER M1 ;
		RECT 11.2 2.96 11.56 3.66 ;
		LAYER M1 ;
		RECT 12.4 3.54 13 3.66 ;
		LAYER M1 ;
		RECT 14.54 2.96 14.94 4.52 ;
		LAYER M1 ;
		RECT 15.4 5.02 16.84 5.38 ;
		LAYER M1 ;
		RECT 18.5 5.62 19.74 5.94 ;
		LAYER M1 ;
		RECT 15.4 3.74 15.76 5.02 ;
		LAYER M1 ;
		RECT 16.08 4.4 16.68 4.7 ;
		LAYER M1 ;
		RECT 18.5 4.4 18.88 5.62 ;
		LAYER M1 ;
		RECT 16.08 4.1 18.88 4.4 ;
		LAYER M1 ;
		RECT 16.22 4.06 18.88 4.1 ;
		LAYER M1 ;
		RECT 15.34 3.72 15.94 3.74 ;
		LAYER M1 ;
		RECT 15.34 3.14 16.02 3.72 ;
		LAYER M1 ;
		RECT 11.14 2.44 11.62 2.96 ;
		LAYER M1 ;
		RECT 14.52 2.44 15.02 2.96 ;
		LAYER M1 ;
		RECT 11.2 1.68 11.8 1.8 ;
		LAYER M1 ;
		RECT 11.2 1.2 11.9 1.68 ;
		LAYER M1 ;
		RECT 11.3 1.08 11.9 1.2 ;
		LAYER M1 ;
		RECT 15.54 2.2 16.02 3.14 ;
		LAYER M1 ;
		RECT 18.5 3.38 18.88 4.06 ;
		LAYER M1 ;
		RECT 19.28 3.38 19.76 3.4 ;
		LAYER M1 ;
		RECT 18.5 3.02 19.76 3.38 ;
		LAYER M1 ;
		RECT 19.28 2.88 19.76 3.02 ;
		LAYER M1 ;
		RECT 13.1 1.2 13.7 1.8 ;
		LAYER M1 ;
		RECT 14.2 1.5 14.8 1.8 ;
		LAYER M1 ;
		RECT 15.28 1.5 15.88 1.62 ;
		LAYER M1 ;
		RECT 14.2 1.2 15.88 1.5 ;
		LAYER M1 ;
		RECT 16.2 1.58 16.8 1.8 ;
		LAYER M1 ;
		RECT 18.72 1.94 19.32 2.54 ;
		LAYER M1 ;
		RECT 21 4.2 21.8 4.8 ;
		LAYER M1 ;
		RECT 18.72 1.8 19.08 1.94 ;
		LAYER M1 ;
		RECT 16.2 1.2 16.9 1.58 ;
		LAYER M1 ;
		RECT 13.14 1.06 13.64 1.2 ;
		LAYER M1 ;
		RECT 14.28 1.12 15.88 1.2 ;
		LAYER M1 ;
		RECT 14.28 1.06 14.78 1.12 ;
		LAYER M1 ;
		RECT 15.28 1.02 15.88 1.12 ;
		LAYER M1 ;
		RECT 16.42 1.06 16.9 1.2 ;
		LAYER M1 ;
		RECT 18.34 1.46 19.08 1.8 ;
		LAYER M1 ;
		RECT 18.34 1.2 18.94 1.46 ;
		LAYER M1 ;
		RECT 18.42 1.06 18.9 1.2 ;
		LAYER M2 ;
		RECT 13.12 8.08 13.72 8.28 ;
		LAYER M2 ;
		RECT 3.2 7.2 3.8 7.8 ;
		LAYER M2 ;
		RECT 6.2 7.2 6.8 7.8 ;
		LAYER M2 ;
		RECT 12.52 7.68 13.72 8.08 ;
		LAYER M2 ;
		RECT 14.2 7.74 14.8 8.34 ;
		LAYER M2 ;
		RECT 16.2 7.76 16.8 8.36 ;
		LAYER M2 ;
		RECT 3.3 2.8 3.7 7.2 ;
		LAYER M2 ;
		RECT 6.3 5.06 6.7 7.2 ;
		LAYER M2 ;
		RECT 8.2 5.06 8.8 5.16 ;
		LAYER M2 ;
		RECT 6.3 4.66 8.8 5.06 ;
		LAYER M2 ;
		RECT 12.52 6.26 12.92 7.68 ;
		LAYER M2 ;
		RECT 11.2 5.2 11.8 5.8 ;
		LAYER M2 ;
		RECT 12.36 5.66 12.96 6.26 ;
		LAYER M2 ;
		RECT 6.3 2.8 6.7 4.66 ;
		LAYER M2 ;
		RECT 8.2 4.56 8.8 4.66 ;
		LAYER M2 ;
		RECT 11.4 3.8 11.8 5.2 ;
		LAYER M2 ;
		RECT 12.52 4.14 12.92 5.66 ;
		LAYER M2 ;
		RECT 13.4 5.2 14 5.8 ;
		LAYER M2 ;
		RECT 3.2 2.2 3.8 2.8 ;
		LAYER M2 ;
		RECT 6.2 2.2 6.8 2.8 ;
		LAYER M2 ;
		RECT 9.2 2.6 9.8 3.8 ;
		LAYER M2 ;
		RECT 11.2 3.2 11.8 3.8 ;
		LAYER M2 ;
		RECT 12.4 3.54 13 4.14 ;
		LAYER M2 ;
		RECT 12.52 1.8 12.92 3.54 ;
		LAYER M2 ;
		RECT 14.4 1.8 14.8 7.74 ;
		LAYER M2 ;
		RECT 15.2 3.74 15.8 3.8 ;
		LAYER M2 ;
		RECT 15.2 3.2 15.94 3.74 ;
		LAYER M2 ;
		RECT 15.34 3.14 15.94 3.2 ;
		LAYER M2 ;
		RECT 16.4 1.8 16.8 7.76 ;
		LAYER M2 ;
		RECT 18.4 7.8 19 8.4 ;
		LAYER M2 ;
		RECT 18.4 5.8 18.8 7.8 ;
		LAYER M2 ;
		RECT 18.2 5.2 18.8 5.8 ;
		LAYER M2 ;
		RECT 18.4 1.8 18.8 5.2 ;
		LAYER M2 ;
		RECT 21.2 4.2 21.8 4.8 ;
		LAYER M2 ;
		RECT 21.28 3.8 21.68 4.2 ;
		LAYER M2 ;
		RECT 21.2 3.2 21.8 3.8 ;
		LAYER M2 ;
		RECT 11.2 1.2 11.8 1.8 ;
		LAYER M2 ;
		RECT 12.52 1.4 13.7 1.8 ;
		LAYER M2 ;
		RECT 13.1 1.2 13.7 1.4 ;
		LAYER M2 ;
		RECT 14.2 1.2 14.8 1.8 ;
		LAYER M2 ;
		RECT 16.2 1.2 16.8 1.8 ;
		LAYER M2 ;
		RECT 18.34 1.2 18.94 1.8 ;
		LAYER M3 ;
		RECT 11.2 5.6 11.8 5.8 ;
		LAYER M3 ;
		RECT 13.4 5.6 14 5.8 ;
		LAYER M3 ;
		RECT 18.2 5.6 18.8 5.8 ;
		LAYER M3 ;
		RECT 11.2 5.2 18.88 5.6 ;
		LAYER M3 ;
		RECT 9.2 3.6 9.8 3.8 ;
		LAYER M3 ;
		RECT 11.2 3.6 11.8 3.8 ;
		LAYER M3 ;
		RECT 15.2 3.6 15.8 3.8 ;
		LAYER M3 ;
		RECT 21.2 3.6 21.8 3.8 ;
		LAYER M3 ;
		RECT 9.2 3.2 11.8 3.6 ;
		LAYER M3 ;
		RECT 15.2 3.2 21.8 3.6 ;
		LAYER M3 ;
		RECT 11.2 1.6 11.8 1.8 ;
		LAYER M3 ;
		RECT 16.2 1.6 16.8 1.8 ;
		LAYER M3 ;
		RECT 11.2 1.2 16.8 1.6 ;
	END
END MMI_FFCB
MACRO MMI_FFS
	CLASS CORE ;
	FOREIGN MMI_FFS 0 0 ;
	SIZE 23 BY 10 ;
	SYMMETRY X ;
	SITE CORE1 ;
	PIN Q
		DIRECTION output ;
		PORT
			LAYER M1 ;
			RECT 20.12 6.62 20.6 8.94 ;
			LAYER M1 ;
			RECT 20.24 2.22 20.58 6.62 ;
			LAYER M1 ;
			RECT 20.12 1.1 20.6 2.22 ;
		END
	END Q
	PIN setn
		DIRECTION input ;
		PORT
			LAYER M1 ;
			RECT 22.2 8.2 22.8 8.8 ;
			LAYER M1 ;
			RECT 11.8 6.2 12.4 6.8 ;
			LAYER VIA1 ;
			RECT 22.32 8.32 22.68 8.68 ;
			LAYER VIA1 ;
			RECT 11.92 6.32 12.28 6.68 ;
			LAYER M2 ;
			RECT 22.2 8.2 22.8 8.8 ;
			LAYER M2 ;
			RECT 22.3 7.8 22.7 8.2 ;
			LAYER M2 ;
			RECT 22.2 7.2 22.8 7.8 ;
			LAYER M2 ;
			RECT 11.8 6.2 12.4 6.8 ;
			LAYER VIA2 ;
			RECT 22.32 7.32 22.68 7.68 ;
			LAYER VIA2 ;
			RECT 11.92 6.32 12.28 6.68 ;
			LAYER M3 ;
			RECT 12 7.2 22.8 7.8 ;
			LAYER M3 ;
			RECT 12 6.8 12.4 7.2 ;
			LAYER M3 ;
			RECT 11.8 6.2 12.4 6.8 ;
		END
	END setn
	PIN D
		DIRECTION input ;
		PORT
			LAYER M1 ;
			RECT 1.2 4.8 1.86 4.84 ;
			LAYER M1 ;
			RECT 1.2 4.24 2.24 4.8 ;
			LAYER M1 ;
			RECT 1.64 4.2 2.24 4.24 ;
		END
	END D
	PIN scan_en
		DIRECTION input ;
		PORT
			LAYER M1 ;
			RECT 2.6 6.16 7.64 6.22 ;
			LAYER M1 ;
			RECT 1.04 5.86 7.64 6.16 ;
			LAYER M1 ;
			RECT 1.04 5.8 3.2 5.86 ;
			LAYER M1 ;
			RECT 1.04 5.24 1.8 5.8 ;
			LAYER M1 ;
			RECT 2.6 5.62 3.2 5.8 ;
			LAYER M1 ;
			RECT 7.04 5.62 7.64 5.86 ;
			LAYER M1 ;
			RECT 1.04 5.2 1.64 5.24 ;
		END
	END scan_en
	PIN GND
		DIRECTION inout ;
		USE GROUND ;
		SHAPE ABUTMENT ;
		PORT
			LAYER M1 ;
			RECT 21.2 2.88 21.68 3.4 ;
			LAYER M1 ;
			RECT 1.38 1.7 1.86 2.82 ;
			LAYER M1 ;
			RECT 4.9 1.7 5.38 2.82 ;
			LAYER M1 ;
			RECT 8.4 1.7 8.88 2.82 ;
			LAYER M1 ;
			RECT 1.44 0.7 1.8 1.7 ;
			LAYER M1 ;
			RECT 4.96 0.7 5.32 1.7 ;
			LAYER M1 ;
			RECT 8.48 0.7 8.84 1.7 ;
			LAYER M1 ;
			RECT 12.14 1.06 12.62 2.78 ;
			LAYER M1 ;
			RECT 15.42 1.1 15.9 2.82 ;
			LAYER M1 ;
			RECT 17.42 1.1 17.9 2.82 ;
			LAYER M1 ;
			RECT 21.24 2.22 21.6 2.88 ;
			LAYER M1 ;
			RECT 21.12 1.1 21.6 2.22 ;
			LAYER M1 ;
			RECT 12.22 0.7 12.58 1.06 ;
			LAYER M1 ;
			RECT 15.5 0.7 15.86 1.1 ;
			LAYER M1 ;
			RECT 17.48 0.7 17.86 1.1 ;
			LAYER M1 ;
			RECT 21.24 0.7 21.6 1.1 ;
			LAYER M1 ;
			RECT 0 -0.7 23 0.7 ;
		END
	END GND
	PIN clk
		DIRECTION input ;
		PORT
			LAYER M1 ;
			RECT 9.2 6.4 9.8 7 ;
			LAYER M1 ;
			RECT 19.2 4.2 19.8 4.8 ;
			LAYER M1 ;
			RECT 13.6 3.6 14.2 4.2 ;
			LAYER VIA1 ;
			RECT 9.32 6.52 9.68 6.88 ;
			LAYER VIA1 ;
			RECT 19.32 4.32 19.68 4.68 ;
			LAYER VIA1 ;
			RECT 13.72 3.72 14.08 4.08 ;
			LAYER M2 ;
			RECT 9.2 6.4 9.8 7 ;
			LAYER M2 ;
			RECT 9.3 4.8 9.7 6.4 ;
			LAYER M2 ;
			RECT 9.2 4.2 9.8 4.8 ;
			LAYER M2 ;
			RECT 13.6 3.6 14.2 4.44 ;
			LAYER M2 ;
			RECT 19.2 4.2 19.8 4.8 ;
			LAYER VIA2 ;
			RECT 9.32 6.52 9.68 6.88 ;
			LAYER VIA2 ;
			RECT 9.32 4.32 9.68 4.68 ;
			LAYER VIA2 ;
			RECT 19.32 4.32 19.68 4.68 ;
			LAYER VIA2 ;
			RECT 13.72 3.96 14.08 4.32 ;
			LAYER M3 ;
			RECT 9.2 6.4 9.8 7 ;
			LAYER M3 ;
			RECT 9.2 4.2 19.8 4.8 ;
			LAYER M3 ;
			RECT 13.6 3.84 14.2 4.2 ;
		END
	END clk
	PIN scan_in
		DIRECTION input ;
		PORT
			LAYER M1 ;
			RECT 4.2 3.2 4.96 3.8 ;
		END
	END scan_in
	PIN VDD
		DIRECTION inout ;
		USE POWER ;
		SHAPE ABUTMENT ;
		PORT
			LAYER M1 ;
			RECT 0 9.3 23 10.7 ;
			LAYER M1 ;
			RECT 1.44 8.86 1.78 9.3 ;
			LAYER M1 ;
			RECT 4.98 8.86 5.34 9.3 ;
			LAYER M1 ;
			RECT 8.48 8.86 8.84 9.3 ;
			LAYER M1 ;
			RECT 10.2 8.92 10.56 9.3 ;
			LAYER M1 ;
			RECT 12.2 8.92 12.56 9.3 ;
			LAYER M1 ;
			RECT 17.48 8.94 17.84 9.3 ;
			LAYER M1 ;
			RECT 21.18 8.94 21.54 9.3 ;
			LAYER M1 ;
			RECT 1.38 6.54 1.86 8.86 ;
			LAYER M1 ;
			RECT 4.9 6.54 5.38 8.86 ;
			LAYER M1 ;
			RECT 8.4 6.54 8.88 8.86 ;
			LAYER M1 ;
			RECT 10.14 7.2 10.62 8.92 ;
			LAYER M1 ;
			RECT 12.14 7.2 12.62 8.92 ;
			LAYER M1 ;
			RECT 17.42 6.62 17.9 8.94 ;
			LAYER M1 ;
			RECT 21.12 6.64 21.6 8.94 ;
			LAYER M1 ;
			RECT 21.12 6.62 21.64 6.64 ;
			LAYER M1 ;
			RECT 21.16 6.14 21.64 6.62 ;
			LAYER M1 ;
			RECT 21.2 5.62 21.7 6.14 ;
		END
	END VDD
	OBS
		LAYER M1 ;
		RECT 0.32 6.54 0.8 7.64 ;
		LAYER M1 ;
		RECT 3.14 7.8 3.62 8.86 ;
		LAYER M1 ;
		RECT 3.14 7.2 3.8 7.8 ;
		LAYER M1 ;
		RECT 3.14 6.54 3.62 7.2 ;
		LAYER M1 ;
		RECT 6.66 7.8 7.14 8.86 ;
		LAYER M1 ;
		RECT 6.2 7.2 7.14 7.8 ;
		LAYER M1 ;
		RECT 6.66 6.54 7.14 7.2 ;
		LAYER M1 ;
		RECT 11.14 7.54 11.62 8.92 ;
		LAYER M1 ;
		RECT 11.12 7.2 11.62 7.54 ;
		LAYER M1 ;
		RECT 12.96 8.8 13.56 8.86 ;
		LAYER M1 ;
		RECT 12.96 8.3 13.64 8.8 ;
		LAYER M1 ;
		RECT 14.2 8.32 14.8 8.92 ;
		LAYER M1 ;
		RECT 14.28 8.3 14.78 8.32 ;
		LAYER M1 ;
		RECT 12.96 8.26 13.56 8.3 ;
		LAYER M1 ;
		RECT 14.22 7.56 14.7 7.72 ;
		LAYER M1 ;
		RECT 14.22 7.2 15 7.56 ;
		LAYER M1 ;
		RECT 0.36 3.68 0.72 6.54 ;
		LAYER M1 ;
		RECT 8.94 5.86 9.42 6.06 ;
		LAYER M1 ;
		RECT 8.72 5.54 9.42 5.86 ;
		LAYER M1 ;
		RECT 9.94 5.88 10.42 6.06 ;
		LAYER M1 ;
		RECT 9.94 5.54 10.62 5.88 ;
		LAYER M1 ;
		RECT 3.56 5.16 4.16 5.54 ;
		LAYER M1 ;
		RECT 6.08 5.16 6.68 5.54 ;
		LAYER M1 ;
		RECT 8.72 5.16 9.08 5.54 ;
		LAYER M1 ;
		RECT 2.74 4.8 7.46 5.16 ;
		LAYER M1 ;
		RECT 2.74 3.8 3.1 4.8 ;
		LAYER M1 ;
		RECT 3.52 4.12 6.62 4.48 ;
		LAYER M1 ;
		RECT 2.6 3.68 3.2 3.8 ;
		LAYER M1 ;
		RECT 0.36 3.32 3.2 3.68 ;
		LAYER M1 ;
		RECT 0.36 2.82 0.72 3.32 ;
		LAYER M1 ;
		RECT 2.6 3.2 3.2 3.32 ;
		LAYER M1 ;
		RECT 3.52 2.82 3.88 4.12 ;
		LAYER M1 ;
		RECT 6.26 2.82 6.62 4.12 ;
		LAYER M1 ;
		RECT 7.1 3.8 7.46 4.8 ;
		LAYER M1 ;
		RECT 8.2 4.56 9.08 5.16 ;
		LAYER M1 ;
		RECT 8.72 4.04 9.08 4.56 ;
		LAYER M1 ;
		RECT 10.26 4.96 10.62 5.54 ;
		LAYER M1 ;
		RECT 11.12 5.64 11.48 7.2 ;
		LAYER M1 ;
		RECT 12.6 5.64 13.2 5.8 ;
		LAYER M1 ;
		RECT 11.12 5.28 13.2 5.64 ;
		LAYER M1 ;
		RECT 12.6 5.2 13.2 5.28 ;
		LAYER M1 ;
		RECT 13.6 5.2 14.2 5.8 ;
		LAYER M1 ;
		RECT 10.26 4.88 10.88 4.96 ;
		LAYER M1 ;
		RECT 14.6 4.88 15 7.2 ;
		LAYER M1 ;
		RECT 15.42 6.72 15.9 8.94 ;
		LAYER M1 ;
		RECT 10.26 4.52 15 4.88 ;
		LAYER M1 ;
		RECT 10.26 4.36 10.88 4.52 ;
		LAYER M1 ;
		RECT 10.26 4.04 10.62 4.36 ;
		LAYER M1 ;
		RECT 6.98 3.2 7.58 3.8 ;
		LAYER M1 ;
		RECT 8.72 3.6 9.42 4.04 ;
		LAYER M1 ;
		RECT 8.94 3.52 9.42 3.6 ;
		LAYER M1 ;
		RECT 9.94 3.62 10.62 4.04 ;
		LAYER M1 ;
		RECT 12.6 3.68 13.2 3.8 ;
		LAYER M1 ;
		RECT 9.94 3.52 10.42 3.62 ;
		LAYER M1 ;
		RECT 11.2 3.28 13.2 3.68 ;
		LAYER M1 ;
		RECT 0.32 2.3 0.8 2.82 ;
		LAYER M1 ;
		RECT 3.14 2.5 3.88 2.82 ;
		LAYER M1 ;
		RECT 3.14 2.2 3.8 2.5 ;
		LAYER M1 ;
		RECT 3.14 1.7 3.62 2.2 ;
		LAYER M1 ;
		RECT 6.26 2.8 7.14 2.82 ;
		LAYER M1 ;
		RECT 6.2 2.2 7.14 2.8 ;
		LAYER M1 ;
		RECT 6.66 1.7 7.14 2.2 ;
		LAYER M1 ;
		RECT 9.2 2.6 9.8 3.2 ;
		LAYER M1 ;
		RECT 11.2 2.78 11.56 3.28 ;
		LAYER M1 ;
		RECT 12.6 3.2 13.2 3.28 ;
		LAYER M1 ;
		RECT 10.14 2.42 11.56 2.78 ;
		LAYER M1 ;
		RECT 10.14 1.06 10.62 2.42 ;
		LAYER M1 ;
		RECT 14.6 2.74 15 4.52 ;
		LAYER M1 ;
		RECT 15.38 6.62 15.9 6.72 ;
		LAYER M1 ;
		RECT 16.42 6.62 16.9 8.94 ;
		LAYER M1 ;
		RECT 18.5 8.38 18.98 8.92 ;
		LAYER M1 ;
		RECT 18.36 7.82 18.98 8.38 ;
		LAYER M1 ;
		RECT 18.36 7.78 18.96 7.82 ;
		LAYER M1 ;
		RECT 22.26 6.8 22.74 7.72 ;
		LAYER M1 ;
		RECT 15.38 3.74 15.74 6.62 ;
		LAYER M1 ;
		RECT 19.22 5.94 19.72 6.14 ;
		LAYER M1 ;
		RECT 18.5 5.62 19.72 5.94 ;
		LAYER M1 ;
		RECT 16.06 5.18 16.68 5.42 ;
		LAYER M1 ;
		RECT 18.5 5.18 18.88 5.62 ;
		LAYER M1 ;
		RECT 16.06 4.84 18.88 5.18 ;
		LAYER M1 ;
		RECT 16.06 4.82 16.68 4.84 ;
		LAYER M1 ;
		RECT 15.38 3.56 16 3.74 ;
		LAYER M1 ;
		RECT 15.38 3.2 16.84 3.56 ;
		LAYER M1 ;
		RECT 17.16 3.2 17.8 3.8 ;
		LAYER M1 ;
		RECT 18.5 3.38 18.88 4.84 ;
		LAYER M1 ;
		RECT 19.26 3.38 19.74 3.4 ;
		LAYER M1 ;
		RECT 15.4 3.14 16 3.2 ;
		LAYER M1 ;
		RECT 16.48 2.82 16.84 3.2 ;
		LAYER M1 ;
		RECT 18.5 3.02 19.74 3.38 ;
		LAYER M1 ;
		RECT 19.26 2.88 19.74 3.02 ;
		LAYER M1 ;
		RECT 14.3 2.38 15 2.74 ;
		LAYER M1 ;
		RECT 14.3 2.22 14.78 2.38 ;
		LAYER M1 ;
		RECT 13.1 1.2 13.7 1.8 ;
		LAYER M1 ;
		RECT 14.26 1.2 14.86 1.8 ;
		LAYER M1 ;
		RECT 13.14 1.02 13.64 1.2 ;
		LAYER M1 ;
		RECT 14.28 1.02 14.78 1.2 ;
		LAYER M1 ;
		RECT 16.42 1.1 16.9 2.82 ;
		LAYER M1 ;
		RECT 19 1.94 19.6 2.54 ;
		LAYER M1 ;
		RECT 22.2 6.2 22.8 6.8 ;
		LAYER M1 ;
		RECT 21 4.2 21.8 4.8 ;
		LAYER M1 ;
		RECT 22.36 3.4 22.72 6.2 ;
		LAYER M1 ;
		RECT 22.2 3.18 22.72 3.4 ;
		LAYER M1 ;
		RECT 22.2 2.88 22.68 3.18 ;
		LAYER M1 ;
		RECT 19 1.62 19.32 1.94 ;
		LAYER M1 ;
		RECT 18.4 1.26 19.32 1.62 ;
		LAYER M1 ;
		RECT 18.4 1.02 19 1.26 ;
		LAYER M2 ;
		RECT 12.96 8.66 13.56 8.86 ;
		LAYER M2 ;
		RECT 12.8 8.26 13.56 8.66 ;
		LAYER M2 ;
		RECT 14.2 8.76 14.8 8.92 ;
		LAYER M2 ;
		RECT 14.2 8.32 15 8.76 ;
		LAYER M2 ;
		RECT 3.2 7.2 3.8 7.8 ;
		LAYER M2 ;
		RECT 6.2 7.2 6.8 7.8 ;
		LAYER M2 ;
		RECT 3.3 2.8 3.7 7.2 ;
		LAYER M2 ;
		RECT 6.3 5.06 6.7 7.2 ;
		LAYER M2 ;
		RECT 8.2 5.06 8.8 5.16 ;
		LAYER M2 ;
		RECT 6.3 4.66 8.8 5.06 ;
		LAYER M2 ;
		RECT 12.8 5.8 13.2 8.26 ;
		LAYER M2 ;
		RECT 11.2 5.2 11.8 5.8 ;
		LAYER M2 ;
		RECT 12.6 5.2 13.2 5.8 ;
		LAYER M2 ;
		RECT 13.6 5.2 14.2 5.8 ;
		LAYER M2 ;
		RECT 14.6 5.22 15 8.32 ;
		LAYER M2 ;
		RECT 18.36 8.26 18.96 8.38 ;
		LAYER M2 ;
		RECT 18.3 7.78 18.96 8.26 ;
		LAYER M2 ;
		RECT 17.2 6.2 17.8 6.8 ;
		LAYER M2 ;
		RECT 16.06 5.22 16.66 5.42 ;
		LAYER M2 ;
		RECT 6.3 2.8 6.7 4.66 ;
		LAYER M2 ;
		RECT 8.2 4.56 8.8 4.66 ;
		LAYER M2 ;
		RECT 11.4 3.8 11.8 5.2 ;
		LAYER M2 ;
		RECT 12.8 3.8 13.2 5.2 ;
		LAYER M2 ;
		RECT 14.6 4.82 16.66 5.22 ;
		LAYER M2 ;
		RECT 3.2 2.2 3.8 2.8 ;
		LAYER M2 ;
		RECT 6.2 2.2 6.8 2.8 ;
		LAYER M2 ;
		RECT 9.2 2.6 9.8 3.8 ;
		LAYER M2 ;
		RECT 11.2 3.2 11.8 3.8 ;
		LAYER M2 ;
		RECT 12.6 3.2 13.2 3.8 ;
		LAYER M2 ;
		RECT 12.8 1.8 13.2 3.2 ;
		LAYER M2 ;
		RECT 14.6 1.8 15 4.82 ;
		LAYER M2 ;
		RECT 17.3 3.8 17.7 6.2 ;
		LAYER M2 ;
		RECT 18.3 5.8 18.7 7.78 ;
		LAYER M2 ;
		RECT 22.2 6.2 22.8 6.8 ;
		LAYER M2 ;
		RECT 18.3 5.2 19.2 5.8 ;
		LAYER M2 ;
		RECT 15.4 3.14 16 3.78 ;
		LAYER M2 ;
		RECT 17.2 3.2 17.8 3.8 ;
		LAYER M2 ;
		RECT 12.8 1.2 13.7 1.8 ;
		LAYER M2 ;
		RECT 14.26 1.24 15 1.8 ;
		LAYER M2 ;
		RECT 18.3 1.62 18.7 5.2 ;
		LAYER M2 ;
		RECT 21.2 4.2 21.8 4.8 ;
		LAYER M2 ;
		RECT 21.3 3.8 21.7 4.2 ;
		LAYER M2 ;
		RECT 21.2 3.2 21.8 3.8 ;
		LAYER M2 ;
		RECT 14.26 1.2 14.86 1.24 ;
		LAYER M2 ;
		RECT 18.3 1.14 19 1.62 ;
		LAYER M2 ;
		RECT 18.4 1.02 19 1.14 ;
		LAYER M3 ;
		RECT 17.2 6.6 17.8 6.8 ;
		LAYER M3 ;
		RECT 22.2 6.6 22.8 6.8 ;
		LAYER M3 ;
		RECT 17.2 6.2 22.8 6.6 ;
		LAYER M3 ;
		RECT 11.2 5.6 11.8 5.8 ;
		LAYER M3 ;
		RECT 13.6 5.6 14.2 5.8 ;
		LAYER M3 ;
		RECT 18.6 5.6 19.2 5.8 ;
		LAYER M3 ;
		RECT 11.2 5.2 19.2 5.6 ;
		LAYER M3 ;
		RECT 9.2 3.6 9.8 3.8 ;
		LAYER M3 ;
		RECT 11.2 3.6 11.8 3.8 ;
		LAYER M3 ;
		RECT 9.2 3.2 11.8 3.6 ;
		LAYER M3 ;
		RECT 15.4 3.6 16 3.78 ;
		LAYER M3 ;
		RECT 21.2 3.6 21.8 3.8 ;
		LAYER M3 ;
		RECT 15.4 3.2 21.8 3.6 ;
		LAYER M3 ;
		RECT 15.4 3.18 16 3.2 ;
	END
END MMI_FFS
MACRO MMI_FFSB
	CLASS CORE ;
	FOREIGN MMI_FFSB 0 0 ;
	SIZE 23 BY 10 ;
	SYMMETRY X ;
	SITE CORE1 ;
	PIN Q
		DIRECTION output ;
		PORT
			LAYER M1 ;
			RECT 20.12 6.62 20.6 8.94 ;
			LAYER M1 ;
			RECT 20.24 2.22 20.58 6.62 ;
			LAYER M1 ;
			RECT 20.12 1.1 20.6 2.22 ;
		END
	END Q
	PIN setn
		DIRECTION input ;
		PORT
			LAYER M1 ;
			RECT 22.2 8.2 22.8 8.8 ;
			LAYER M1 ;
			RECT 11.8 6.2 12.4 6.8 ;
			LAYER VIA1 ;
			RECT 22.32 8.32 22.68 8.68 ;
			LAYER VIA1 ;
			RECT 11.92 6.32 12.28 6.68 ;
			LAYER M2 ;
			RECT 22.2 8.2 22.8 8.8 ;
			LAYER M2 ;
			RECT 22.3 7.8 22.7 8.2 ;
			LAYER M2 ;
			RECT 22.2 7.2 22.8 7.8 ;
			LAYER M2 ;
			RECT 11.8 6.2 12.4 6.8 ;
			LAYER VIA2 ;
			RECT 22.32 7.32 22.68 7.68 ;
			LAYER VIA2 ;
			RECT 11.92 6.32 12.28 6.68 ;
			LAYER M3 ;
			RECT 12 7.2 22.8 7.8 ;
			LAYER M3 ;
			RECT 12 6.8 12.4 7.2 ;
			LAYER M3 ;
			RECT 11.8 6.2 12.4 6.8 ;
		END
	END setn
	PIN D
		DIRECTION input ;
		PORT
			LAYER M1 ;
			RECT 1.2 4.8 1.86 4.84 ;
			LAYER M1 ;
			RECT 1.2 4.24 2.24 4.8 ;
			LAYER M1 ;
			RECT 1.64 4.2 2.24 4.24 ;
		END
	END D
	PIN scan_en
		DIRECTION input ;
		PORT
			LAYER M1 ;
			RECT 2.6 6.16 7.64 6.22 ;
			LAYER M1 ;
			RECT 1.04 5.86 7.64 6.16 ;
			LAYER M1 ;
			RECT 1.04 5.8 3.2 5.86 ;
			LAYER M1 ;
			RECT 1.04 5.24 1.8 5.8 ;
			LAYER M1 ;
			RECT 2.6 5.62 3.2 5.8 ;
			LAYER M1 ;
			RECT 7.04 5.62 7.64 5.86 ;
			LAYER M1 ;
			RECT 1.04 5.2 1.64 5.24 ;
		END
	END scan_en
	PIN GND
		DIRECTION inout ;
		USE GROUND ;
		SHAPE ABUTMENT ;
		PORT
			LAYER M1 ;
			RECT 21.2 2.88 21.68 3.4 ;
			LAYER M1 ;
			RECT 1.38 1.7 1.86 2.82 ;
			LAYER M1 ;
			RECT 4.9 1.7 5.38 2.82 ;
			LAYER M1 ;
			RECT 8.4 1.7 8.88 2.82 ;
			LAYER M1 ;
			RECT 1.44 0.7 1.8 1.7 ;
			LAYER M1 ;
			RECT 4.96 0.7 5.32 1.7 ;
			LAYER M1 ;
			RECT 8.48 0.7 8.84 1.7 ;
			LAYER M1 ;
			RECT 12.14 1.06 12.62 2.78 ;
			LAYER M1 ;
			RECT 15.42 1.1 15.9 2.82 ;
			LAYER M1 ;
			RECT 17.42 1.1 17.9 2.82 ;
			LAYER M1 ;
			RECT 21.24 2.22 21.6 2.88 ;
			LAYER M1 ;
			RECT 21.12 1.1 21.6 2.22 ;
			LAYER M1 ;
			RECT 12.22 0.7 12.58 1.06 ;
			LAYER M1 ;
			RECT 15.5 0.7 15.86 1.1 ;
			LAYER M1 ;
			RECT 17.48 0.7 17.86 1.1 ;
			LAYER M1 ;
			RECT 21.24 0.7 21.6 1.1 ;
			LAYER M1 ;
			RECT 0 -0.7 23 0.7 ;
		END
	END GND
	PIN clk
		DIRECTION input ;
		PORT
			LAYER M1 ;
			RECT 9.2 6.4 9.8 7 ;
			LAYER M1 ;
			RECT 19.2 4.2 19.8 4.8 ;
			LAYER M1 ;
			RECT 13.6 3.6 14.2 4.2 ;
			LAYER VIA1 ;
			RECT 9.32 6.52 9.68 6.88 ;
			LAYER VIA1 ;
			RECT 19.32 4.32 19.68 4.68 ;
			LAYER VIA1 ;
			RECT 13.72 3.72 14.08 4.08 ;
			LAYER M2 ;
			RECT 9.2 6.4 9.8 7 ;
			LAYER M2 ;
			RECT 9.3 4.8 9.7 6.4 ;
			LAYER M2 ;
			RECT 9.2 4.2 9.8 4.8 ;
			LAYER M2 ;
			RECT 13.6 3.6 14.2 4.44 ;
			LAYER M2 ;
			RECT 19.2 4.2 19.8 4.8 ;
			LAYER VIA2 ;
			RECT 9.32 6.52 9.68 6.88 ;
			LAYER VIA2 ;
			RECT 9.32 4.32 9.68 4.68 ;
			LAYER VIA2 ;
			RECT 19.32 4.32 19.68 4.68 ;
			LAYER VIA2 ;
			RECT 13.72 3.96 14.08 4.32 ;
			LAYER M3 ;
			RECT 9.2 6.4 9.8 7 ;
			LAYER M3 ;
			RECT 9.2 4.2 19.8 4.8 ;
			LAYER M3 ;
			RECT 13.6 3.84 14.2 4.2 ;
		END
	END clk
	PIN scan_in
		DIRECTION input ;
		PORT
			LAYER M1 ;
			RECT 4.2 3.2 4.96 3.8 ;
		END
	END scan_in
	PIN VDD
		DIRECTION inout ;
		USE POWER ;
		SHAPE ABUTMENT ;
		PORT
			LAYER M1 ;
			RECT 0 9.3 23 10.7 ;
			LAYER M1 ;
			RECT 1.44 8.86 1.78 9.3 ;
			LAYER M1 ;
			RECT 4.98 8.86 5.34 9.3 ;
			LAYER M1 ;
			RECT 8.48 8.86 8.84 9.3 ;
			LAYER M1 ;
			RECT 10.2 8.92 10.56 9.3 ;
			LAYER M1 ;
			RECT 12.2 8.92 12.56 9.3 ;
			LAYER M1 ;
			RECT 17.48 8.94 17.84 9.3 ;
			LAYER M1 ;
			RECT 21.18 8.94 21.54 9.3 ;
			LAYER M1 ;
			RECT 1.38 6.54 1.86 8.86 ;
			LAYER M1 ;
			RECT 4.9 6.54 5.38 8.86 ;
			LAYER M1 ;
			RECT 8.4 6.54 8.88 8.86 ;
			LAYER M1 ;
			RECT 10.14 7.2 10.62 8.92 ;
			LAYER M1 ;
			RECT 12.14 7.2 12.62 8.92 ;
			LAYER M1 ;
			RECT 17.42 6.62 17.9 8.94 ;
			LAYER M1 ;
			RECT 21.12 6.64 21.6 8.94 ;
			LAYER M1 ;
			RECT 21.12 6.62 21.64 6.64 ;
			LAYER M1 ;
			RECT 21.16 6.14 21.64 6.62 ;
			LAYER M1 ;
			RECT 21.2 5.62 21.7 6.14 ;
		END
	END VDD
	OBS
		LAYER M1 ;
		RECT 0.32 6.54 0.8 7.64 ;
		LAYER M1 ;
		RECT 3.14 7.8 3.62 8.86 ;
		LAYER M1 ;
		RECT 3.14 7.2 3.8 7.8 ;
		LAYER M1 ;
		RECT 3.14 6.54 3.62 7.2 ;
		LAYER M1 ;
		RECT 6.66 7.8 7.14 8.86 ;
		LAYER M1 ;
		RECT 6.2 7.2 7.14 7.8 ;
		LAYER M1 ;
		RECT 6.66 6.54 7.14 7.2 ;
		LAYER M1 ;
		RECT 11.14 7.54 11.62 8.92 ;
		LAYER M1 ;
		RECT 11.12 7.2 11.62 7.54 ;
		LAYER M1 ;
		RECT 12.96 8.8 13.56 8.86 ;
		LAYER M1 ;
		RECT 12.96 8.3 13.64 8.8 ;
		LAYER M1 ;
		RECT 14.2 8.32 14.8 8.92 ;
		LAYER M1 ;
		RECT 14.28 8.3 14.78 8.32 ;
		LAYER M1 ;
		RECT 12.96 8.26 13.56 8.3 ;
		LAYER M1 ;
		RECT 14.22 7.56 14.7 7.72 ;
		LAYER M1 ;
		RECT 14.22 7.2 15 7.56 ;
		LAYER M1 ;
		RECT 0.36 3.68 0.72 6.54 ;
		LAYER M1 ;
		RECT 8.94 5.86 9.42 6.06 ;
		LAYER M1 ;
		RECT 8.72 5.54 9.42 5.86 ;
		LAYER M1 ;
		RECT 9.94 5.88 10.42 6.06 ;
		LAYER M1 ;
		RECT 9.94 5.54 10.62 5.88 ;
		LAYER M1 ;
		RECT 3.56 5.16 4.16 5.54 ;
		LAYER M1 ;
		RECT 6.08 5.16 6.68 5.54 ;
		LAYER M1 ;
		RECT 8.72 5.16 9.08 5.54 ;
		LAYER M1 ;
		RECT 2.74 4.8 7.46 5.16 ;
		LAYER M1 ;
		RECT 2.74 3.8 3.1 4.8 ;
		LAYER M1 ;
		RECT 3.52 4.12 6.62 4.48 ;
		LAYER M1 ;
		RECT 2.6 3.68 3.2 3.8 ;
		LAYER M1 ;
		RECT 0.36 3.32 3.2 3.68 ;
		LAYER M1 ;
		RECT 0.36 2.82 0.72 3.32 ;
		LAYER M1 ;
		RECT 2.6 3.2 3.2 3.32 ;
		LAYER M1 ;
		RECT 3.52 2.82 3.88 4.12 ;
		LAYER M1 ;
		RECT 6.26 2.82 6.62 4.12 ;
		LAYER M1 ;
		RECT 7.1 3.8 7.46 4.8 ;
		LAYER M1 ;
		RECT 8.2 4.56 9.08 5.16 ;
		LAYER M1 ;
		RECT 8.72 4.04 9.08 4.56 ;
		LAYER M1 ;
		RECT 10.26 4.96 10.62 5.54 ;
		LAYER M1 ;
		RECT 11.12 5.64 11.48 7.2 ;
		LAYER M1 ;
		RECT 12.6 5.64 13.2 5.8 ;
		LAYER M1 ;
		RECT 11.12 5.28 13.2 5.64 ;
		LAYER M1 ;
		RECT 12.6 5.2 13.2 5.28 ;
		LAYER M1 ;
		RECT 13.6 5.2 14.2 5.8 ;
		LAYER M1 ;
		RECT 10.26 4.88 10.88 4.96 ;
		LAYER M1 ;
		RECT 14.6 4.88 15 7.2 ;
		LAYER M1 ;
		RECT 15.42 6.72 15.9 8.94 ;
		LAYER M1 ;
		RECT 10.26 4.52 15 4.88 ;
		LAYER M1 ;
		RECT 10.26 4.36 10.88 4.52 ;
		LAYER M1 ;
		RECT 10.26 4.04 10.62 4.36 ;
		LAYER M1 ;
		RECT 6.98 3.2 7.58 3.8 ;
		LAYER M1 ;
		RECT 8.72 3.6 9.42 4.04 ;
		LAYER M1 ;
		RECT 8.94 3.52 9.42 3.6 ;
		LAYER M1 ;
		RECT 9.94 3.62 10.62 4.04 ;
		LAYER M1 ;
		RECT 12.6 3.68 13.2 3.8 ;
		LAYER M1 ;
		RECT 9.94 3.52 10.42 3.62 ;
		LAYER M1 ;
		RECT 11.2 3.28 13.2 3.68 ;
		LAYER M1 ;
		RECT 0.32 2.3 0.8 2.82 ;
		LAYER M1 ;
		RECT 3.14 2.5 3.88 2.82 ;
		LAYER M1 ;
		RECT 3.14 2.2 3.8 2.5 ;
		LAYER M1 ;
		RECT 3.14 1.7 3.62 2.2 ;
		LAYER M1 ;
		RECT 6.26 2.8 7.14 2.82 ;
		LAYER M1 ;
		RECT 6.2 2.2 7.14 2.8 ;
		LAYER M1 ;
		RECT 6.66 1.7 7.14 2.2 ;
		LAYER M1 ;
		RECT 9.2 2.6 9.8 3.2 ;
		LAYER M1 ;
		RECT 11.2 2.78 11.56 3.28 ;
		LAYER M1 ;
		RECT 12.6 3.2 13.2 3.28 ;
		LAYER M1 ;
		RECT 10.14 2.42 11.56 2.78 ;
		LAYER M1 ;
		RECT 10.14 1.06 10.62 2.42 ;
		LAYER M1 ;
		RECT 14.6 2.74 15 4.52 ;
		LAYER M1 ;
		RECT 15.38 6.62 15.9 6.72 ;
		LAYER M1 ;
		RECT 16.42 6.62 16.9 8.94 ;
		LAYER M1 ;
		RECT 18.5 8.38 18.98 8.92 ;
		LAYER M1 ;
		RECT 18.36 7.82 18.98 8.38 ;
		LAYER M1 ;
		RECT 18.36 7.78 18.96 7.82 ;
		LAYER M1 ;
		RECT 22.26 6.8 22.74 7.72 ;
		LAYER M1 ;
		RECT 15.38 3.74 15.74 6.62 ;
		LAYER M1 ;
		RECT 19.22 5.94 19.72 6.14 ;
		LAYER M1 ;
		RECT 18.5 5.62 19.72 5.94 ;
		LAYER M1 ;
		RECT 16.06 5.18 16.68 5.42 ;
		LAYER M1 ;
		RECT 18.5 5.18 18.88 5.62 ;
		LAYER M1 ;
		RECT 16.06 4.84 18.88 5.18 ;
		LAYER M1 ;
		RECT 16.06 4.82 16.68 4.84 ;
		LAYER M1 ;
		RECT 15.38 3.56 16 3.74 ;
		LAYER M1 ;
		RECT 15.38 3.2 16.84 3.56 ;
		LAYER M1 ;
		RECT 17.16 3.2 17.8 3.8 ;
		LAYER M1 ;
		RECT 18.5 3.38 18.88 4.84 ;
		LAYER M1 ;
		RECT 19.26 3.38 19.74 3.4 ;
		LAYER M1 ;
		RECT 15.4 3.14 16 3.2 ;
		LAYER M1 ;
		RECT 16.48 2.82 16.84 3.2 ;
		LAYER M1 ;
		RECT 18.5 3.02 19.74 3.38 ;
		LAYER M1 ;
		RECT 19.26 2.88 19.74 3.02 ;
		LAYER M1 ;
		RECT 14.3 2.38 15 2.74 ;
		LAYER M1 ;
		RECT 14.3 2.22 14.78 2.38 ;
		LAYER M1 ;
		RECT 13.1 1.2 13.7 1.8 ;
		LAYER M1 ;
		RECT 14.26 1.2 14.86 1.8 ;
		LAYER M1 ;
		RECT 13.14 1.02 13.64 1.2 ;
		LAYER M1 ;
		RECT 14.28 1.02 14.78 1.2 ;
		LAYER M1 ;
		RECT 16.42 1.1 16.9 2.82 ;
		LAYER M1 ;
		RECT 19 1.94 19.6 2.54 ;
		LAYER M1 ;
		RECT 22.2 6.2 22.8 6.8 ;
		LAYER M1 ;
		RECT 21 4.2 21.8 4.8 ;
		LAYER M1 ;
		RECT 22.36 3.4 22.72 6.2 ;
		LAYER M1 ;
		RECT 22.2 3.18 22.72 3.4 ;
		LAYER M1 ;
		RECT 22.2 2.88 22.68 3.18 ;
		LAYER M1 ;
		RECT 19 1.62 19.32 1.94 ;
		LAYER M1 ;
		RECT 18.4 1.26 19.32 1.62 ;
		LAYER M1 ;
		RECT 18.4 1.02 19 1.26 ;
		LAYER M2 ;
		RECT 12.96 8.66 13.56 8.86 ;
		LAYER M2 ;
		RECT 12.8 8.26 13.56 8.66 ;
		LAYER M2 ;
		RECT 14.2 8.76 14.8 8.92 ;
		LAYER M2 ;
		RECT 14.2 8.32 15 8.76 ;
		LAYER M2 ;
		RECT 3.2 7.2 3.8 7.8 ;
		LAYER M2 ;
		RECT 6.2 7.2 6.8 7.8 ;
		LAYER M2 ;
		RECT 3.3 2.8 3.7 7.2 ;
		LAYER M2 ;
		RECT 6.3 5.06 6.7 7.2 ;
		LAYER M2 ;
		RECT 8.2 5.06 8.8 5.16 ;
		LAYER M2 ;
		RECT 6.3 4.66 8.8 5.06 ;
		LAYER M2 ;
		RECT 12.8 5.8 13.2 8.26 ;
		LAYER M2 ;
		RECT 11.2 5.2 11.8 5.8 ;
		LAYER M2 ;
		RECT 12.6 5.2 13.2 5.8 ;
		LAYER M2 ;
		RECT 13.6 5.2 14.2 5.8 ;
		LAYER M2 ;
		RECT 14.6 5.22 15 8.32 ;
		LAYER M2 ;
		RECT 18.36 8.26 18.96 8.38 ;
		LAYER M2 ;
		RECT 18.3 7.78 18.96 8.26 ;
		LAYER M2 ;
		RECT 17.2 6.2 17.8 6.8 ;
		LAYER M2 ;
		RECT 16.06 5.22 16.66 5.42 ;
		LAYER M2 ;
		RECT 6.3 2.8 6.7 4.66 ;
		LAYER M2 ;
		RECT 8.2 4.56 8.8 4.66 ;
		LAYER M2 ;
		RECT 11.4 3.8 11.8 5.2 ;
		LAYER M2 ;
		RECT 12.8 3.8 13.2 5.2 ;
		LAYER M2 ;
		RECT 14.6 4.82 16.66 5.22 ;
		LAYER M2 ;
		RECT 3.2 2.2 3.8 2.8 ;
		LAYER M2 ;
		RECT 6.2 2.2 6.8 2.8 ;
		LAYER M2 ;
		RECT 9.2 2.6 9.8 3.8 ;
		LAYER M2 ;
		RECT 11.2 3.2 11.8 3.8 ;
		LAYER M2 ;
		RECT 12.6 3.2 13.2 3.8 ;
		LAYER M2 ;
		RECT 12.8 1.8 13.2 3.2 ;
		LAYER M2 ;
		RECT 14.6 1.8 15 4.82 ;
		LAYER M2 ;
		RECT 17.3 3.8 17.7 6.2 ;
		LAYER M2 ;
		RECT 18.3 5.8 18.7 7.78 ;
		LAYER M2 ;
		RECT 22.2 6.2 22.8 6.8 ;
		LAYER M2 ;
		RECT 18.3 5.2 19.2 5.8 ;
		LAYER M2 ;
		RECT 15.4 3.14 16 3.78 ;
		LAYER M2 ;
		RECT 17.2 3.2 17.8 3.8 ;
		LAYER M2 ;
		RECT 12.8 1.2 13.7 1.8 ;
		LAYER M2 ;
		RECT 14.26 1.24 15 1.8 ;
		LAYER M2 ;
		RECT 18.3 1.62 18.7 5.2 ;
		LAYER M2 ;
		RECT 21.2 4.2 21.8 4.8 ;
		LAYER M2 ;
		RECT 21.3 3.8 21.7 4.2 ;
		LAYER M2 ;
		RECT 21.2 3.2 21.8 3.8 ;
		LAYER M2 ;
		RECT 14.26 1.2 14.86 1.24 ;
		LAYER M2 ;
		RECT 18.3 1.14 19 1.62 ;
		LAYER M2 ;
		RECT 18.4 1.02 19 1.14 ;
		LAYER M3 ;
		RECT 17.2 6.6 17.8 6.8 ;
		LAYER M3 ;
		RECT 22.2 6.6 22.8 6.8 ;
		LAYER M3 ;
		RECT 17.2 6.2 22.8 6.6 ;
		LAYER M3 ;
		RECT 11.2 5.6 11.8 5.8 ;
		LAYER M3 ;
		RECT 13.6 5.6 14.2 5.8 ;
		LAYER M3 ;
		RECT 18.6 5.6 19.2 5.8 ;
		LAYER M3 ;
		RECT 11.2 5.2 19.2 5.6 ;
		LAYER M3 ;
		RECT 9.2 3.6 9.8 3.8 ;
		LAYER M3 ;
		RECT 11.2 3.6 11.8 3.8 ;
		LAYER M3 ;
		RECT 9.2 3.2 11.8 3.6 ;
		LAYER M3 ;
		RECT 15.4 3.6 16 3.78 ;
		LAYER M3 ;
		RECT 21.2 3.6 21.8 3.8 ;
		LAYER M3 ;
		RECT 15.4 3.2 21.8 3.6 ;
		LAYER M3 ;
		RECT 15.4 3.18 16 3.2 ;
	END
END MMI_FFSB
MACRO MMI_FILL_1
	CLASS CORE ;
	FOREIGN MMI_FILL_1 0 0 ;
	SIZE 1 BY 10 ;
	SYMMETRY X Y ;
	SITE CORE1 ;
	PIN GND
		DIRECTION inout ;
		USE GROUND ;
		SHAPE ABUTMENT ;
		PORT
			LAYER M1 ;
			RECT 0 -0.7 1 0.7 ;
		END
	END GND
	PIN VDD
		DIRECTION inout ;
		USE POWER ;
		SHAPE ABUTMENT ;
		PORT
			LAYER M1 ;
			RECT 0 9.3 1 10.7 ;
		END
	END VDD
	OBS
	END
END MMI_FILL_1
MACRO MMI_FILL_2
	CLASS CORE ;
	FOREIGN MMI_FILL_2 0 0 ;
	SIZE 2 BY 10 ;
	SYMMETRY X Y ;
	SITE CORE1 ;
	PIN GND
		DIRECTION inout ;
		USE GROUND ;
		SHAPE ABUTMENT ;
		PORT
			LAYER M1 ;
			RECT 0 -0.7 2 0.7 ;
		END
	END GND
	PIN VDD
		DIRECTION inout ;
		USE POWER ;
		SHAPE ABUTMENT ;
		PORT
			LAYER M1 ;
			RECT 0 9.3 2 10.7 ;
		END
	END VDD
	OBS
	END
END MMI_FILL_2
MACRO MMI_FILL_4
	CLASS CORE ;
	FOREIGN MMI_FILL_4 0 0 ;
	SIZE 4 BY 10 ;
	SYMMETRY X Y ;
	SITE CORE1 ;
	PIN GND
		DIRECTION inout ;
		USE GROUND ;
		SHAPE ABUTMENT ;
		PORT
			LAYER M1 ;
			RECT 2.26 4.94 2.74 5.42 ;
			LAYER M1 ;
			RECT 2.34 3.78 2.66 4.94 ;
			LAYER M1 ;
			RECT 0.26 1.46 0.74 3.78 ;
			LAYER M1 ;
			RECT 1.26 1.46 1.74 3.78 ;
			LAYER M1 ;
			RECT 2.26 1.46 2.74 3.78 ;
			LAYER M1 ;
			RECT 3.26 1.46 3.74 3.78 ;
			LAYER M1 ;
			RECT 0.34 0.7 0.66 1.46 ;
			LAYER M1 ;
			RECT 1.34 0.7 1.66 1.46 ;
			LAYER M1 ;
			RECT 2.34 0.7 2.66 1.46 ;
			LAYER M1 ;
			RECT 3.34 0.7 3.66 1.46 ;
			LAYER M1 ;
			RECT 0 -0.7 4 0.7 ;
		END
	END GND
	PIN VDD
		DIRECTION inout ;
		USE POWER ;
		SHAPE ABUTMENT ;
		PORT
			LAYER M1 ;
			RECT 0 9.3 4 10.7 ;
			LAYER M1 ;
			RECT 0.34 8.92 0.66 9.3 ;
			LAYER M1 ;
			RECT 1.34 8.92 1.66 9.3 ;
			LAYER M1 ;
			RECT 2.34 8.92 2.66 9.3 ;
			LAYER M1 ;
			RECT 3.34 8.92 3.66 9.3 ;
			LAYER M1 ;
			RECT 0.26 5.82 0.74 8.92 ;
			LAYER M1 ;
			RECT 1.26 5.82 1.74 8.92 ;
			LAYER M1 ;
			RECT 2.26 5.82 2.74 8.92 ;
			LAYER M1 ;
			RECT 3.26 5.82 3.74 8.92 ;
			LAYER M1 ;
			RECT 1.34 4.66 1.66 5.82 ;
			LAYER M1 ;
			RECT 1.26 4.18 1.74 4.66 ;
		END
	END VDD
	OBS
	END
END MMI_FILL_4
MACRO MMI_FILL_8
	CLASS CORE ;
	FOREIGN MMI_FILL_8 0 0 ;
	SIZE 8 BY 10 ;
	SYMMETRY X Y ;
	SITE CORE1 ;
	PIN GND
		DIRECTION inout ;
		USE GROUND ;
		SHAPE ABUTMENT ;
		PORT
			LAYER M1 ;
			RECT 2.26 4.94 2.74 5.42 ;
			LAYER M1 ;
			RECT 6.26 4.94 6.74 5.42 ;
			LAYER M1 ;
			RECT 2.34 3.78 2.66 4.94 ;
			LAYER M1 ;
			RECT 6.34 3.78 6.66 4.94 ;
			LAYER M1 ;
			RECT 0.26 1.46 0.74 3.78 ;
			LAYER M1 ;
			RECT 1.26 1.46 1.74 3.78 ;
			LAYER M1 ;
			RECT 2.26 1.46 2.74 3.78 ;
			LAYER M1 ;
			RECT 3.26 1.46 3.74 3.78 ;
			LAYER M1 ;
			RECT 4.26 1.46 4.74 3.78 ;
			LAYER M1 ;
			RECT 5.26 1.46 5.74 3.78 ;
			LAYER M1 ;
			RECT 6.26 1.46 6.74 3.78 ;
			LAYER M1 ;
			RECT 7.26 1.46 7.74 3.78 ;
			LAYER M1 ;
			RECT 0.34 0.7 0.66 1.46 ;
			LAYER M1 ;
			RECT 1.34 0.7 1.66 1.46 ;
			LAYER M1 ;
			RECT 2.34 0.7 2.66 1.46 ;
			LAYER M1 ;
			RECT 3.34 0.7 3.66 1.46 ;
			LAYER M1 ;
			RECT 4.34 0.7 4.66 1.46 ;
			LAYER M1 ;
			RECT 5.34 0.7 5.66 1.46 ;
			LAYER M1 ;
			RECT 6.34 0.7 6.66 1.46 ;
			LAYER M1 ;
			RECT 7.34 0.7 7.66 1.46 ;
			LAYER M1 ;
			RECT 0 -0.7 8 0.7 ;
		END
	END GND
	PIN VDD
		DIRECTION inout ;
		USE POWER ;
		SHAPE ABUTMENT ;
		PORT
			LAYER M1 ;
			RECT 0 9.3 8 10.7 ;
			LAYER M1 ;
			RECT 0.34 8.92 0.66 9.3 ;
			LAYER M1 ;
			RECT 1.34 8.92 1.66 9.3 ;
			LAYER M1 ;
			RECT 2.34 8.92 2.66 9.3 ;
			LAYER M1 ;
			RECT 3.34 8.92 3.66 9.3 ;
			LAYER M1 ;
			RECT 4.34 8.92 4.66 9.3 ;
			LAYER M1 ;
			RECT 5.34 8.92 5.66 9.3 ;
			LAYER M1 ;
			RECT 6.34 8.92 6.66 9.3 ;
			LAYER M1 ;
			RECT 7.34 8.92 7.66 9.3 ;
			LAYER M1 ;
			RECT 0.26 5.82 0.74 8.92 ;
			LAYER M1 ;
			RECT 1.26 5.82 1.74 8.92 ;
			LAYER M1 ;
			RECT 2.26 5.82 2.74 8.92 ;
			LAYER M1 ;
			RECT 3.26 5.82 3.74 8.92 ;
			LAYER M1 ;
			RECT 4.26 5.82 4.74 8.92 ;
			LAYER M1 ;
			RECT 5.26 5.82 5.74 8.92 ;
			LAYER M1 ;
			RECT 6.26 5.82 6.74 8.92 ;
			LAYER M1 ;
			RECT 7.26 5.82 7.74 8.92 ;
			LAYER M1 ;
			RECT 1.34 4.66 1.66 5.82 ;
			LAYER M1 ;
			RECT 5.34 4.66 5.66 5.82 ;
			LAYER M1 ;
			RECT 1.26 4.18 1.74 4.66 ;
			LAYER M1 ;
			RECT 5.26 4.18 5.74 4.66 ;
		END
	END VDD
	OBS
	END
END MMI_FILL_8
MACRO MMI_INAND2A
	CLASS CORE ;
	FOREIGN MMI_INAND2A 0 0 ;
	SIZE 4 BY 10 ;
	SYMMETRY X Y ;
	SITE CORE1 ;
	PIN in1
		DIRECTION input ;
		PORT
			LAYER M1 ;
			RECT 0.92 5.2 1.8 5.8 ;
		END
	END in1
	PIN out
		DIRECTION output ;
		PORT
			LAYER M1 ;
			RECT 2.26 6.16 2.74 7.26 ;
			LAYER M1 ;
			RECT 2.32 5.82 2.66 6.16 ;
			LAYER M1 ;
			RECT 2.32 5.46 3.64 5.82 ;
			LAYER M1 ;
			RECT 3.28 3.48 3.64 5.46 ;
			LAYER M1 ;
			RECT 3.26 2.36 3.74 3.48 ;
		END
	END out
	PIN GND
		DIRECTION inout ;
		USE GROUND ;
		SHAPE ABUTMENT ;
		PORT
			LAYER M1 ;
			RECT 1.34 2.36 1.82 3.48 ;
			LAYER M1 ;
			RECT 1.34 0.7 1.7 2.36 ;
			LAYER M1 ;
			RECT 0 -0.7 4 0.7 ;
		END
	END GND
	PIN VDD
		DIRECTION inout ;
		USE POWER ;
		SHAPE ABUTMENT ;
		PORT
			LAYER M1 ;
			RECT 0 9.3 4 10.7 ;
			LAYER M1 ;
			RECT 1.34 7.26 1.7 9.3 ;
			LAYER M1 ;
			RECT 3.28 7.26 3.64 9.3 ;
			LAYER M1 ;
			RECT 1.26 6.16 1.74 7.26 ;
			LAYER M1 ;
			RECT 3.26 6.16 3.74 7.26 ;
		END
	END VDD
	PIN in0
		DIRECTION input ;
		PORT
			LAYER M1 ;
			RECT 1.92 4.2 2.8 4.8 ;
		END
	END in0
	OBS
		LAYER M1 ;
		RECT 0.26 6.16 0.74 7.26 ;
		LAYER M1 ;
		RECT 0.26 3.02 0.6 6.16 ;
		LAYER M1 ;
		RECT 0.26 2.5 0.74 3.02 ;
		LAYER M1 ;
		RECT 0.26 1.72 0.6 2.5 ;
		LAYER M1 ;
		RECT 0.2 1.12 0.8 1.72 ;
	END
END MMI_INAND2A
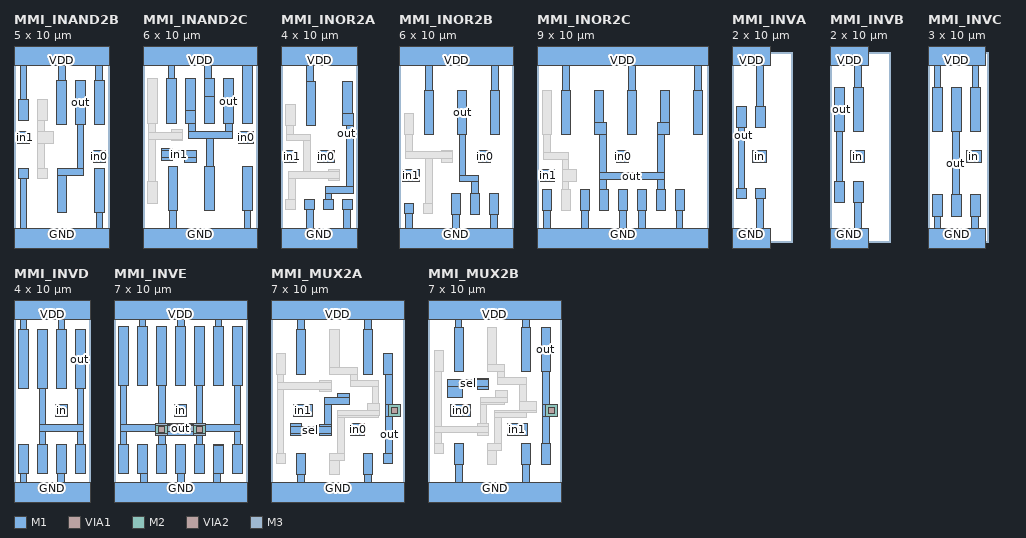
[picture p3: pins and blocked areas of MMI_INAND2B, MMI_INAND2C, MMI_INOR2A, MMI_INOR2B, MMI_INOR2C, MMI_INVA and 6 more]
MACRO MMI_INAND2B
	CLASS CORE ;
	FOREIGN MMI_INAND2B 0 0 ;
	SIZE 5 BY 10 ;
	SYMMETRY X Y ;
	SITE CORE1 ;
	PIN in1
		DIRECTION input ;
		PORT
			LAYER M1 ;
			RECT 0.2 5.2 0.8 5.8 ;
		END
	END in1
	PIN out
		DIRECTION output ;
		PORT
			LAYER M1 ;
			RECT 3.26 6.16 3.74 8.48 ;
			LAYER M1 ;
			RECT 3.32 3.88 3.68 6.16 ;
			LAYER M1 ;
			RECT 2.28 3.5 3.68 3.88 ;
			LAYER M1 ;
			RECT 2.28 1.56 2.76 3.5 ;
		END
	END out
	PIN GND
		DIRECTION inout ;
		USE GROUND ;
		SHAPE ABUTMENT ;
		PORT
			LAYER M1 ;
			RECT 0.26 3.36 0.74 3.88 ;
			LAYER M1 ;
			RECT 0.32 0.7 0.68 3.36 ;
			LAYER M1 ;
			RECT 4.26 1.56 4.74 3.88 ;
			LAYER M1 ;
			RECT 4.32 0.7 4.68 1.56 ;
			LAYER M1 ;
			RECT 0 -0.7 5 0.7 ;
		END
	END GND
	PIN VDD
		DIRECTION inout ;
		USE POWER ;
		SHAPE ABUTMENT ;
		PORT
			LAYER M1 ;
			RECT 0 9.3 5 10.7 ;
			LAYER M1 ;
			RECT 0.32 7.52 0.68 9.3 ;
			LAYER M1 ;
			RECT 2.34 8.48 2.7 9.3 ;
			LAYER M1 ;
			RECT 4.28 8.48 4.64 9.3 ;
			LAYER M1 ;
			RECT 0.26 6.42 0.74 7.52 ;
			LAYER M1 ;
			RECT 2.26 6.16 2.74 8.48 ;
			LAYER M1 ;
			RECT 4.26 6.16 4.74 8.48 ;
		END
	END VDD
	PIN in0
		DIRECTION input ;
		PORT
			LAYER M1 ;
			RECT 4.2 4.2 4.82 4.8 ;
		END
	END in0
	OBS
		LAYER M1 ;
		RECT 1.26 6.42 1.74 7.52 ;
		LAYER M1 ;
		RECT 1.26 5.8 1.6 6.42 ;
		LAYER M1 ;
		RECT 1.26 5.2 2.08 5.8 ;
		LAYER M1 ;
		RECT 1.26 3.88 1.6 5.2 ;
		LAYER M1 ;
		RECT 1.26 3.36 1.74 3.88 ;
	END
END MMI_INAND2B
MACRO MMI_INAND2C
	CLASS CORE ;
	FOREIGN MMI_INAND2C 0 0 ;
	SIZE 6 BY 10 ;
	SYMMETRY X Y ;
	SITE CORE1 ;
	PIN in1
		DIRECTION input ;
		PORT
			LAYER M1 ;
			RECT 0.96 4.8 1.56 4.9 ;
			LAYER M1 ;
			RECT 0.96 4.44 2.8 4.8 ;
			LAYER M1 ;
			RECT 0.96 4.3 1.56 4.44 ;
			LAYER M1 ;
			RECT 2.18 4.2 2.8 4.44 ;
		END
	END in1
	PIN out
		DIRECTION output ;
		PORT
			LAYER M1 ;
			RECT 2.26 6.92 2.74 8.58 ;
			LAYER M1 ;
			RECT 2.26 6.26 2.76 6.92 ;
			LAYER M1 ;
			RECT 4.26 6.26 4.74 8.58 ;
			LAYER M1 ;
			RECT 2.4 5.82 2.76 6.26 ;
			LAYER M1 ;
			RECT 4.36 5.82 4.7 6.26 ;
			LAYER M1 ;
			RECT 2.4 5.46 4.7 5.82 ;
			LAYER M1 ;
			RECT 3.34 3.98 3.7 5.46 ;
			LAYER M1 ;
			RECT 3.26 1.66 3.74 3.98 ;
		END
	END out
	PIN GND
		DIRECTION inout ;
		USE GROUND ;
		SHAPE ABUTMENT ;
		PORT
			LAYER M1 ;
			RECT 1.34 1.66 1.82 3.98 ;
			LAYER M1 ;
			RECT 5.26 1.66 5.74 3.98 ;
			LAYER M1 ;
			RECT 1.38 0.7 1.74 1.66 ;
			LAYER M1 ;
			RECT 5.32 0.7 5.68 1.66 ;
			LAYER M1 ;
			RECT 0 -0.7 6 0.7 ;
		END
	END GND
	PIN VDD
		DIRECTION inout ;
		USE POWER ;
		SHAPE ABUTMENT ;
		PORT
			LAYER M1 ;
			RECT 0 9.3 6 10.7 ;
			LAYER M1 ;
			RECT 1.32 8.58 1.66 9.3 ;
			LAYER M1 ;
			RECT 3.24 8.58 3.6 9.3 ;
			LAYER M1 ;
			RECT 1.26 6.26 1.74 8.58 ;
			LAYER M1 ;
			RECT 3.24 7.64 3.74 8.58 ;
			LAYER M1 ;
			RECT 3.26 6.26 3.74 7.64 ;
			LAYER M1 ;
			RECT 5.26 6.26 5.74 9.3 ;
		END
	END VDD
	PIN in0
		DIRECTION input ;
		PORT
			LAYER M1 ;
			RECT 5.02 5.2 5.8 5.8 ;
		END
	END in0
	OBS
		LAYER M1 ;
		RECT 0.26 6.26 0.74 8.58 ;
		LAYER M1 ;
		RECT 0.28 5.74 0.64 6.26 ;
		LAYER M1 ;
		RECT 1.48 5.74 2.08 5.94 ;
		LAYER M1 ;
		RECT 0.28 5.38 2.08 5.74 ;
		LAYER M1 ;
		RECT 0.28 3.16 0.64 5.38 ;
		LAYER M1 ;
		RECT 1.48 5.34 2.08 5.38 ;
		LAYER M1 ;
		RECT 0.26 2.04 0.74 3.16 ;
	END
END MMI_INAND2C
MACRO MMI_INOR2A
	CLASS CORE ;
	FOREIGN MMI_INOR2A 0 0 ;
	SIZE 4 BY 10 ;
	SYMMETRY X Y ;
	SITE CORE1 ;
	PIN in1
		DIRECTION input ;
		PORT
			LAYER M1 ;
			RECT 0.2 4.2 0.8 4.8 ;
		END
	END in1
	PIN out
		DIRECTION output ;
		PORT
			LAYER M1 ;
			RECT 3.26 6.78 3.74 8.44 ;
			LAYER M1 ;
			RECT 3.26 6.12 3.8 6.78 ;
			LAYER M1 ;
			RECT 3.44 2.92 3.8 6.12 ;
			LAYER M1 ;
			RECT 2.32 2.56 3.8 2.92 ;
			LAYER M1 ;
			RECT 2.32 2.24 2.66 2.56 ;
			LAYER M1 ;
			RECT 2.26 1.72 2.74 2.24 ;
		END
	END out
	PIN GND
		DIRECTION inout ;
		USE GROUND ;
		SHAPE ABUTMENT ;
		PORT
			LAYER M1 ;
			RECT 1.26 1.72 1.74 2.24 ;
			LAYER M1 ;
			RECT 3.26 1.72 3.74 2.24 ;
			LAYER M1 ;
			RECT 1.34 0.7 1.7 1.72 ;
			LAYER M1 ;
			RECT 3.28 0.7 3.64 1.72 ;
			LAYER M1 ;
			RECT 0 -0.7 4 0.7 ;
		END
	END GND
	PIN VDD
		DIRECTION inout ;
		USE POWER ;
		SHAPE ABUTMENT ;
		PORT
			LAYER M1 ;
			RECT 0 9.3 4 10.7 ;
			LAYER M1 ;
			RECT 1.34 8.44 1.7 9.3 ;
			LAYER M1 ;
			RECT 1.32 6.12 1.8 8.44 ;
		END
	END VDD
	PIN in0
		DIRECTION input ;
		PORT
			LAYER M1 ;
			RECT 1.92 4.2 2.8 4.8 ;
		END
	END in0
	OBS
		LAYER M1 ;
		RECT 0.26 6.12 0.74 7.22 ;
		LAYER M1 ;
		RECT 0.28 5.66 0.64 6.12 ;
		LAYER M1 ;
		RECT 0.28 5.32 1.56 5.66 ;
		LAYER M1 ;
		RECT 1.2 3.72 1.56 5.32 ;
		LAYER M1 ;
		RECT 2.48 3.72 3.08 3.84 ;
		LAYER M1 ;
		RECT 0.38 3.36 3.08 3.72 ;
		LAYER M1 ;
		RECT 0.38 2.24 0.74 3.36 ;
		LAYER M1 ;
		RECT 2.48 3.24 3.08 3.36 ;
		LAYER M1 ;
		RECT 0.26 1.72 0.74 2.24 ;
	END
END MMI_INOR2A
MACRO MMI_INOR2B
	CLASS CORE ;
	FOREIGN MMI_INOR2B 0 0 ;
	SIZE 6 BY 10 ;
	SYMMETRY X Y ;
	SITE CORE1 ;
	PIN in1
		DIRECTION input ;
		PORT
			LAYER M1 ;
			RECT 0.2 3.2 1.06 3.8 ;
		END
	END in1
	PIN out
		DIRECTION output ;
		PORT
			LAYER M1 ;
			RECT 3.08 5.68 3.56 8 ;
			LAYER M1 ;
			RECT 3.16 3.52 3.52 5.68 ;
			LAYER M1 ;
			RECT 3.16 3.16 4.2 3.52 ;
			LAYER M1 ;
			RECT 3.84 2.56 4.2 3.16 ;
			LAYER M1 ;
			RECT 3.78 1.44 4.26 2.56 ;
		END
	END out
	PIN GND
		DIRECTION inout ;
		USE GROUND ;
		SHAPE ABUTMENT ;
		PORT
			LAYER M1 ;
			RECT 0.28 1.5 0.76 2.02 ;
			LAYER M1 ;
			RECT 0.34 0.7 0.7 1.5 ;
			LAYER M1 ;
			RECT 2.78 1.44 3.26 2.56 ;
			LAYER M1 ;
			RECT 4.78 1.44 5.26 2.56 ;
			LAYER M1 ;
			RECT 2.84 0.7 3.18 1.44 ;
			LAYER M1 ;
			RECT 4.84 0.7 5.2 1.44 ;
			LAYER M1 ;
			RECT 0 -0.7 6 0.7 ;
		END
	END GND
	PIN VDD
		DIRECTION inout ;
		USE POWER ;
		SHAPE ABUTMENT ;
		PORT
			LAYER M1 ;
			RECT 0 9.3 6 10.7 ;
			LAYER M1 ;
			RECT 1.42 8 1.78 9.3 ;
			LAYER M1 ;
			RECT 4.86 8 5.22 9.3 ;
			LAYER M1 ;
			RECT 1.34 5.68 1.82 8 ;
			LAYER M1 ;
			RECT 4.82 5.68 5.3 8 ;
		END
	END VDD
	PIN in0
		DIRECTION input ;
		PORT
			LAYER M1 ;
			RECT 4.2 4.2 4.8 4.8 ;
		END
	END in0
	OBS
		LAYER M1 ;
		RECT 0.28 5.68 0.76 6.78 ;
		LAYER M1 ;
		RECT 0.34 4.74 0.7 5.68 ;
		LAYER M1 ;
		RECT 2.24 4.74 2.84 4.8 ;
		LAYER M1 ;
		RECT 0.34 4.38 2.84 4.74 ;
		LAYER M1 ;
		RECT 1.38 2.02 1.74 4.38 ;
		LAYER M1 ;
		RECT 2.24 4.2 2.84 4.38 ;
		LAYER M1 ;
		RECT 1.28 1.5 1.76 2.02 ;
	END
END MMI_INOR2B
MACRO MMI_INOR2C
	CLASS CORE ;
	FOREIGN MMI_INOR2C 0 0 ;
	SIZE 9 BY 10 ;
	SYMMETRY X Y ;
	SITE CORE1 ;
	PIN in1
		DIRECTION input ;
		PORT
			LAYER M1 ;
			RECT 0.2 3.2 0.9 3.8 ;
		END
	END in1
	PIN out
		DIRECTION output ;
		PORT
			LAYER M1 ;
			RECT 3.02 6.28 3.5 8 ;
			LAYER M1 ;
			RECT 6.5 6.28 6.98 8 ;
			LAYER M1 ;
			RECT 3.02 5.68 3.64 6.28 ;
			LAYER M1 ;
			RECT 3.28 3.64 3.64 5.68 ;
			LAYER M1 ;
			RECT 6.34 5.68 6.98 6.28 ;
			LAYER M1 ;
			RECT 6.34 3.64 6.7 5.68 ;
			LAYER M1 ;
			RECT 3.28 3.3 6.7 3.64 ;
			LAYER M1 ;
			RECT 3.28 2.78 3.64 3.3 ;
			LAYER M1 ;
			RECT 6.34 2.78 6.7 3.3 ;
			LAYER M1 ;
			RECT 3.28 1.66 3.76 2.78 ;
			LAYER M1 ;
			RECT 6.28 1.66 6.76 2.78 ;
		END
	END out
	PIN GND
		DIRECTION inout ;
		USE GROUND ;
		SHAPE ABUTMENT ;
		PORT
			LAYER M1 ;
			RECT 0.28 1.66 0.76 2.78 ;
			LAYER M1 ;
			RECT 2.28 1.66 2.76 2.78 ;
			LAYER M1 ;
			RECT 4.28 1.66 4.76 2.78 ;
			LAYER M1 ;
			RECT 5.28 1.66 5.76 2.78 ;
			LAYER M1 ;
			RECT 7.28 1.66 7.76 2.78 ;
			LAYER M1 ;
			RECT 0.34 0.7 0.7 1.66 ;
			LAYER M1 ;
			RECT 2.34 0.7 2.7 1.66 ;
			LAYER M1 ;
			RECT 4.34 0.7 4.7 1.66 ;
			LAYER M1 ;
			RECT 5.34 0.7 5.7 1.66 ;
			LAYER M1 ;
			RECT 7.32 0.7 7.66 1.66 ;
			LAYER M1 ;
			RECT 0 -0.7 9 0.7 ;
		END
	END GND
	PIN VDD
		DIRECTION inout ;
		USE POWER ;
		SHAPE ABUTMENT ;
		PORT
			LAYER M1 ;
			RECT 0 9.3 9 10.7 ;
			LAYER M1 ;
			RECT 1.36 8 1.7 9.3 ;
			LAYER M1 ;
			RECT 4.82 8 5.18 9.3 ;
			LAYER M1 ;
			RECT 8.3 8 8.66 9.3 ;
			LAYER M1 ;
			RECT 1.28 5.68 1.76 8 ;
			LAYER M1 ;
			RECT 4.76 5.68 5.24 8 ;
			LAYER M1 ;
			RECT 8.24 5.68 8.72 8 ;
		END
	END VDD
	PIN in0
		DIRECTION input ;
		PORT
			LAYER M1 ;
			RECT 4.2 4.2 4.8 4.8 ;
		END
	END in0
	OBS
		LAYER M1 ;
		RECT 0.28 5.68 0.76 8 ;
		LAYER M1 ;
		RECT 0.34 4.7 0.7 5.68 ;
		LAYER M1 ;
		RECT 0.34 4.34 1.66 4.7 ;
		LAYER M1 ;
		RECT 1.32 3.8 1.66 4.34 ;
		LAYER M1 ;
		RECT 1.32 3.2 2.1 3.8 ;
		LAYER M1 ;
		RECT 1.32 2.78 1.66 3.2 ;
		LAYER M1 ;
		RECT 1.28 1.66 1.76 2.78 ;
	END
END MMI_INOR2C
MACRO MMI_INVA
	CLASS CORE ;
	FOREIGN MMI_INVA 0 0 ;
	SIZE 2 BY 10 ;
	SYMMETRY X Y ;
	SITE CORE1 ;
	PIN out
		DIRECTION output ;
		PORT
			LAYER M1 ;
			RECT 0.26 6.04 0.74 7.14 ;
			LAYER M1 ;
			RECT 0.32 2.84 0.66 6.04 ;
			LAYER M1 ;
			RECT 0.32 2.82 0.72 2.84 ;
			LAYER M1 ;
			RECT 0.26 2.3 0.74 2.82 ;
		END
	END out
	PIN GND
		DIRECTION inout ;
		USE GROUND ;
		SHAPE ABUTMENT ;
		PORT
			LAYER M1 ;
			RECT 1.26 2.3 1.74 2.82 ;
			LAYER M1 ;
			RECT 1.3 0.7 1.64 2.3 ;
			LAYER M1 ;
			RECT 0 -0.7 2 0.7 ;
		END
	END GND
	PIN VDD
		DIRECTION inout ;
		USE POWER ;
		SHAPE ABUTMENT ;
		PORT
			LAYER M1 ;
			RECT 0 9.3 2 10.7 ;
			LAYER M1 ;
			RECT 1.3 7.14 1.64 9.3 ;
			LAYER M1 ;
			RECT 1.26 6.04 1.74 7.14 ;
		END
	END VDD
	PIN in
		DIRECTION input ;
		PORT
			LAYER M1 ;
			RECT 1.08 4.2 1.8 4.8 ;
		END
	END in
	OBS
	END
END MMI_INVA
MACRO MMI_INVB
	CLASS CORE ;
	FOREIGN MMI_INVB 0 0 ;
	SIZE 2 BY 10 ;
	SYMMETRY X Y ;
	SITE CORE1 ;
	PIN out
		DIRECTION output ;
		PORT
			LAYER M1 ;
			RECT 0.26 5.8 0.74 8.12 ;
			LAYER M1 ;
			RECT 0.34 3.2 0.68 5.8 ;
			LAYER M1 ;
			RECT 0.26 2.08 0.74 3.2 ;
		END
	END out
	PIN GND
		DIRECTION inout ;
		USE GROUND ;
		SHAPE ABUTMENT ;
		PORT
			LAYER M1 ;
			RECT 1.26 2.08 1.74 3.2 ;
			LAYER M1 ;
			RECT 1.3 0.7 1.64 2.08 ;
			LAYER M1 ;
			RECT 0 -0.7 2 0.7 ;
		END
	END GND
	PIN VDD
		DIRECTION inout ;
		USE POWER ;
		SHAPE ABUTMENT ;
		PORT
			LAYER M1 ;
			RECT 0 9.3 2 10.7 ;
			LAYER M1 ;
			RECT 1.3 8.12 1.64 9.3 ;
			LAYER M1 ;
			RECT 1.26 5.8 1.74 8.12 ;
		END
	END VDD
	PIN in
		DIRECTION input ;
		PORT
			LAYER M1 ;
			RECT 1.1 4.2 1.8 4.8 ;
		END
	END in
	OBS
	END
END MMI_INVB
MACRO MMI_INVC
	CLASS CORE ;
	FOREIGN MMI_INVC 0 0 ;
	SIZE 3 BY 10 ;
	SYMMETRY X Y ;
	SITE CORE1 ;
	PIN out
		DIRECTION output ;
		PORT
			LAYER M1 ;
			RECT 1.26 5.8 1.74 8.12 ;
			LAYER M1 ;
			RECT 1.28 2.48 1.64 5.8 ;
			LAYER M1 ;
			RECT 1.26 1.36 1.74 2.48 ;
		END
	END out
	PIN GND
		DIRECTION inout ;
		USE GROUND ;
		SHAPE ABUTMENT ;
		PORT
			LAYER M1 ;
			RECT 2.28 2.48 2.64 2.5 ;
			LAYER M1 ;
			RECT 0.26 1.36 0.74 2.48 ;
			LAYER M1 ;
			RECT 2.26 1.36 2.74 2.48 ;
			LAYER M1 ;
			RECT 0.32 0.7 0.66 1.36 ;
			LAYER M1 ;
			RECT 2.28 0.7 2.64 1.36 ;
			LAYER M1 ;
			RECT 0 -0.7 3 0.7 ;
		END
	END GND
	PIN VDD
		DIRECTION inout ;
		USE POWER ;
		SHAPE ABUTMENT ;
		PORT
			LAYER M1 ;
			RECT 0 9.3 3 10.7 ;
			LAYER M1 ;
			RECT 0.32 8.12 0.66 9.3 ;
			LAYER M1 ;
			RECT 2.32 8.12 2.66 9.3 ;
			LAYER M1 ;
			RECT 0.26 5.8 0.74 8.12 ;
			LAYER M1 ;
			RECT 2.26 5.8 2.74 8.12 ;
		END
	END VDD
	PIN in
		DIRECTION input ;
		PORT
			LAYER M1 ;
			RECT 2.02 4.2 2.8 4.8 ;
		END
	END in
	OBS
		LAYER M1 ;
		RECT 2.28 2.48 2.64 2.5 ;
	END
END MMI_INVC
MACRO MMI_INVD
	CLASS CORE ;
	FOREIGN MMI_INVD 0 0 ;
	SIZE 4 BY 10 ;
	SYMMETRY X Y ;
	SITE CORE1 ;
	PIN out
		DIRECTION output ;
		PORT
			LAYER M1 ;
			RECT 1.26 5.64 1.74 8.74 ;
			LAYER M1 ;
			RECT 3.26 5.64 3.74 8.74 ;
			LAYER M1 ;
			RECT 1.32 3.74 1.68 5.64 ;
			LAYER M1 ;
			RECT 3.32 3.74 3.68 5.64 ;
			LAYER M1 ;
			RECT 1.32 3.38 3.68 3.74 ;
			LAYER M1 ;
			RECT 1.32 2.7 1.68 3.38 ;
			LAYER M1 ;
			RECT 3.32 2.7 3.68 3.38 ;
			LAYER M1 ;
			RECT 1.26 1.18 1.74 2.7 ;
			LAYER M1 ;
			RECT 3.26 1.18 3.74 2.7 ;
		END
	END out
	PIN GND
		DIRECTION inout ;
		USE GROUND ;
		SHAPE ABUTMENT ;
		PORT
			LAYER M1 ;
			RECT 0.26 1.18 0.74 2.7 ;
			LAYER M1 ;
			RECT 2.26 1.18 2.74 2.7 ;
			LAYER M1 ;
			RECT 0.32 0.7 0.66 1.18 ;
			LAYER M1 ;
			RECT 2.28 0.7 2.64 1.18 ;
			LAYER M1 ;
			RECT 0 -0.7 4 0.7 ;
		END
	END GND
	PIN VDD
		DIRECTION inout ;
		USE POWER ;
		SHAPE ABUTMENT ;
		PORT
			LAYER M1 ;
			RECT 0 9.3 4 10.7 ;
			LAYER M1 ;
			RECT 0.32 8.74 0.66 9.3 ;
			LAYER M1 ;
			RECT 2.32 8.74 2.66 9.3 ;
			LAYER M1 ;
			RECT 0.26 5.64 0.74 8.74 ;
			LAYER M1 ;
			RECT 2.26 5.64 2.74 8.74 ;
		END
	END VDD
	PIN in
		DIRECTION input ;
		PORT
			LAYER M1 ;
			RECT 2.2 4.2 2.8 4.8 ;
		END
	END in
	OBS
	END
END MMI_INVD
MACRO MMI_INVE
	CLASS CORE ;
	FOREIGN MMI_INVE 0 0 ;
	SIZE 7 BY 10 ;
	SYMMETRY X Y ;
	SITE CORE1 ;
	PIN out
		DIRECTION output ;
		PORT
			LAYER M1 ;
			RECT 0.26 5.8 0.74 8.9 ;
			LAYER M1 ;
			RECT 2.26 5.8 2.74 8.9 ;
			LAYER M1 ;
			RECT 4.26 5.8 4.74 8.9 ;
			LAYER M1 ;
			RECT 6.26 5.8 6.74 8.9 ;
			LAYER M1 ;
			RECT 0.32 3.74 0.68 5.8 ;
			LAYER M1 ;
			RECT 2.34 3.82 2.7 5.8 ;
			LAYER M1 ;
			RECT 4.32 3.82 4.66 5.8 ;
			LAYER M1 ;
			RECT 2.24 3.8 4.66 3.82 ;
			LAYER M1 ;
			RECT 2.2 3.74 4.8 3.8 ;
			LAYER M1 ;
			RECT 6.32 3.74 6.68 5.8 ;
			LAYER M1 ;
			RECT 0.32 3.38 6.68 3.74 ;
			LAYER M1 ;
			RECT 0.32 2.7 0.68 3.38 ;
			LAYER M1 ;
			RECT 2.2 3.2 4.8 3.38 ;
			LAYER M1 ;
			RECT 2.24 3.16 4.66 3.2 ;
			LAYER M1 ;
			RECT 2.34 2.7 2.7 3.16 ;
			LAYER M1 ;
			RECT 4.32 2.7 4.66 3.16 ;
			LAYER M1 ;
			RECT 6.32 2.7 6.68 3.38 ;
			LAYER M1 ;
			RECT 0.26 1.18 0.74 2.7 ;
			LAYER M1 ;
			RECT 2.26 1.18 2.74 2.7 ;
			LAYER M1 ;
			RECT 4.26 1.18 4.74 2.7 ;
			LAYER M1 ;
			RECT 6.26 1.18 6.74 2.7 ;
			LAYER VIA1 ;
			RECT 2.32 3.32 2.68 3.68 ;
			LAYER VIA1 ;
			RECT 4.32 3.32 4.68 3.68 ;
			LAYER M2 ;
			RECT 2.2 3.2 2.8 3.8 ;
			LAYER M2 ;
			RECT 4.2 3.2 4.8 3.8 ;
			LAYER VIA2 ;
			RECT 2.32 3.32 2.68 3.68 ;
			LAYER VIA2 ;
			RECT 4.32 3.32 4.68 3.68 ;
			LAYER M3 ;
			RECT 2.2 3.7 2.8 3.8 ;
			LAYER M3 ;
			RECT 4.2 3.7 4.8 3.8 ;
			LAYER M3 ;
			RECT 2.2 3.28 4.8 3.7 ;
			LAYER M3 ;
			RECT 2.2 3.2 2.8 3.28 ;
			LAYER M3 ;
			RECT 4.2 3.2 4.8 3.28 ;
		END
	END out
	PIN GND
		DIRECTION inout ;
		USE GROUND ;
		SHAPE ABUTMENT ;
		PORT
			LAYER M1 ;
			RECT 1.26 1.18 1.74 2.7 ;
			LAYER M1 ;
			RECT 3.26 1.18 3.74 2.7 ;
			LAYER M1 ;
			RECT 5.26 2.64 5.74 2.7 ;
			LAYER M1 ;
			RECT 5.24 1.18 5.74 2.64 ;
			LAYER M1 ;
			RECT 1.38 0.7 1.74 1.18 ;
			LAYER M1 ;
			RECT 3.34 0.7 3.7 1.18 ;
			LAYER M1 ;
			RECT 5.24 0.7 5.6 1.18 ;
			LAYER M1 ;
			RECT 0 -0.7 7 0.7 ;
		END
	END GND
	PIN VDD
		DIRECTION inout ;
		USE POWER ;
		SHAPE ABUTMENT ;
		PORT
			LAYER M1 ;
			RECT 0 9.3 7 10.7 ;
			LAYER M1 ;
			RECT 1.32 8.9 1.68 9.3 ;
			LAYER M1 ;
			RECT 3.34 8.9 3.7 9.3 ;
			LAYER M1 ;
			RECT 5.32 8.9 5.68 9.3 ;
			LAYER M1 ;
			RECT 1.26 5.8 1.74 8.9 ;
			LAYER M1 ;
			RECT 3.26 5.8 3.74 8.9 ;
			LAYER M1 ;
			RECT 5.26 5.8 5.74 8.9 ;
		END
	END VDD
	PIN in
		DIRECTION input ;
		PORT
			LAYER M1 ;
			RECT 3.2 4.2 3.8 4.8 ;
		END
	END in
	OBS
		LAYER M1 ;
		RECT 2.24 3.8 4.66 3.82 ;
	END
END MMI_INVE
MACRO MMI_MUX2A
	CLASS CORE ;
	FOREIGN MMI_MUX2A 0 0 ;
	SIZE 7 BY 10 ;
	SYMMETRY X Y ;
	SITE CORE1 ;
	PIN in1
		DIRECTION input ;
		PORT
			LAYER M1 ;
			RECT 1.2 4.2 2.2 4.8 ;
		END
	END in1
	PIN sel
		DIRECTION input ;
		PORT
			LAYER M1 ;
			RECT 3.52 5.18 4.12 5.42 ;
			LAYER M1 ;
			RECT 2.8 4.82 4.12 5.18 ;
			LAYER M1 ;
			RECT 1 3.64 1.6 3.8 ;
			LAYER M1 ;
			RECT 2.8 3.76 3.16 4.82 ;
			LAYER M1 ;
			RECT 2.56 3.64 3.16 3.76 ;
			LAYER M1 ;
			RECT 1 3.28 3.16 3.64 ;
			LAYER M1 ;
			RECT 1 3.2 1.6 3.28 ;
			LAYER M1 ;
			RECT 2.56 3.16 3.16 3.28 ;
		END
	END sel
	PIN out
		DIRECTION output ;
		PORT
			LAYER M1 ;
			RECT 5.92 6.42 6.4 7.52 ;
			LAYER M1 ;
			RECT 6.04 4.8 6.4 6.42 ;
			LAYER M1 ;
			RECT 6.04 4.2 6.8 4.8 ;
			LAYER M1 ;
			RECT 6.04 2.24 6.4 4.2 ;
			LAYER M1 ;
			RECT 5.92 1.72 6.4 2.24 ;
			LAYER VIA1 ;
			RECT 6.32 4.32 6.68 4.68 ;
			LAYER M2 ;
			RECT 6.2 4.2 6.8 4.8 ;
		END
	END out
	PIN GND
		DIRECTION inout ;
		USE GROUND ;
		SHAPE ABUTMENT ;
		PORT
			LAYER M1 ;
			RECT 1.34 1.12 1.82 2.24 ;
			LAYER M1 ;
			RECT 4.86 1.12 5.34 2.24 ;
			LAYER M1 ;
			RECT 1.4 0.7 1.76 1.12 ;
			LAYER M1 ;
			RECT 4.92 0.7 5.28 1.12 ;
			LAYER M1 ;
			RECT 0 -0.7 7 0.7 ;
		END
	END GND
	PIN VDD
		DIRECTION inout ;
		USE POWER ;
		SHAPE ABUTMENT ;
		PORT
			LAYER M1 ;
			RECT 0 9.3 7 10.7 ;
			LAYER M1 ;
			RECT 1.4 8.74 1.74 9.3 ;
			LAYER M1 ;
			RECT 4.94 8.74 5.3 9.3 ;
			LAYER M1 ;
			RECT 1.34 6.42 1.82 8.74 ;
			LAYER M1 ;
			RECT 4.86 6.42 5.34 8.74 ;
		END
	END VDD
	PIN in0
		DIRECTION input ;
		PORT
			LAYER M1 ;
			RECT 4.2 3.2 4.92 3.8 ;
		END
	END in0
	OBS
		LAYER M1 ;
		RECT 0.28 6.42 0.76 7.52 ;
		LAYER M1 ;
		RECT 3.1 6.78 3.58 8.74 ;
		LAYER M1 ;
		RECT 3.1 6.42 4.54 6.78 ;
		LAYER M1 ;
		RECT 0.32 5.98 0.68 6.42 ;
		LAYER M1 ;
		RECT 4.18 6.1 4.54 6.42 ;
		LAYER M1 ;
		RECT 2.56 5.98 3.16 6.1 ;
		LAYER M1 ;
		RECT 0.32 5.62 3.16 5.98 ;
		LAYER M1 ;
		RECT 4.18 5.74 5.68 6.1 ;
		LAYER M1 ;
		RECT 0.32 2.24 0.68 5.62 ;
		LAYER M1 ;
		RECT 2.56 5.5 3.16 5.62 ;
		LAYER M1 ;
		RECT 5.32 4.86 5.68 5.74 ;
		LAYER M1 ;
		RECT 5.1 4.48 5.7 4.86 ;
		LAYER M1 ;
		RECT 3.52 4.26 5.7 4.48 ;
		LAYER M1 ;
		RECT 3.52 4.12 5.68 4.26 ;
		LAYER M1 ;
		RECT 3.52 2.24 3.88 4.12 ;
		LAYER M1 ;
		RECT 0.28 1.72 0.76 2.24 ;
		LAYER M1 ;
		RECT 3.1 1.88 3.88 2.24 ;
		LAYER M1 ;
		RECT 3.1 1.12 3.58 1.88 ;
	END
END MMI_MUX2A
MACRO MMI_MUX2B
	CLASS CORE ;
	FOREIGN MMI_MUX2B 0 0 ;
	SIZE 7 BY 10 ;
	SYMMETRY X Y ;
	SITE CORE1 ;
	PIN sel
		DIRECTION input ;
		PORT
			LAYER M1 ;
			RECT 2.6 6.12 3.2 6.2 ;
			LAYER M1 ;
			RECT 1.04 5.76 3.2 6.12 ;
			LAYER M1 ;
			RECT 1.04 5.2 1.8 5.76 ;
			LAYER M1 ;
			RECT 2.6 5.6 3.2 5.76 ;
		END
	END sel
	PIN in1
		DIRECTION input ;
		PORT
			LAYER M1 ;
			RECT 4.2 3.2 5.22 3.8 ;
		END
	END in1
	PIN out
		DIRECTION output ;
		PORT
			LAYER M1 ;
			RECT 5.96 6.54 6.44 8.86 ;
			LAYER M1 ;
			RECT 6.04 4.8 6.4 6.54 ;
			LAYER M1 ;
			RECT 6.04 4.2 6.8 4.8 ;
			LAYER M1 ;
			RECT 6.04 2.78 6.4 4.2 ;
			LAYER M1 ;
			RECT 5.96 1.66 6.44 2.78 ;
			LAYER VIA1 ;
			RECT 6.32 4.32 6.68 4.68 ;
			LAYER M2 ;
			RECT 6.2 4.2 6.8 4.8 ;
		END
	END out
	PIN GND
		DIRECTION inout ;
		USE GROUND ;
		SHAPE ABUTMENT ;
		PORT
			LAYER M1 ;
			RECT 1.38 1.66 1.86 2.78 ;
			LAYER M1 ;
			RECT 4.9 1.66 5.38 2.78 ;
			LAYER M1 ;
			RECT 1.44 0.7 1.8 1.66 ;
			LAYER M1 ;
			RECT 4.96 0.7 5.32 1.66 ;
			LAYER M1 ;
			RECT 0 -0.7 7 0.7 ;
		END
	END GND
	PIN VDD
		DIRECTION inout ;
		USE POWER ;
		SHAPE ABUTMENT ;
		PORT
			LAYER M1 ;
			RECT 0 9.3 7 10.7 ;
			LAYER M1 ;
			RECT 1.44 8.86 1.78 9.3 ;
			LAYER M1 ;
			RECT 4.98 8.86 5.34 9.3 ;
			LAYER M1 ;
			RECT 1.38 6.54 1.86 8.86 ;
			LAYER M1 ;
			RECT 4.9 6.54 5.38 8.86 ;
		END
	END VDD
	PIN in0
		DIRECTION input ;
		PORT
			LAYER M1 ;
			RECT 1.2 4.2 2.24 4.8 ;
		END
	END in0
	OBS
		LAYER M1 ;
		RECT 0.32 6.54 0.8 7.64 ;
		LAYER M1 ;
		RECT 3.14 6.9 3.62 8.86 ;
		LAYER M1 ;
		RECT 3.14 6.54 4 6.9 ;
		LAYER M1 ;
		RECT 0.36 3.68 0.72 6.54 ;
		LAYER M1 ;
		RECT 3.64 6.22 4 6.54 ;
		LAYER M1 ;
		RECT 3.64 5.86 5.18 6.22 ;
		LAYER M1 ;
		RECT 3.56 5.16 4.16 5.54 ;
		LAYER M1 ;
		RECT 2.74 4.94 4.16 5.16 ;
		LAYER M1 ;
		RECT 4.82 5 5.18 5.86 ;
		LAYER M1 ;
		RECT 2.74 4.8 4.04 4.94 ;
		LAYER M1 ;
		RECT 2.74 3.8 3.1 4.8 ;
		LAYER M1 ;
		RECT 4.82 4.48 5.72 5 ;
		LAYER M1 ;
		RECT 3.52 4.4 5.72 4.48 ;
		LAYER M1 ;
		RECT 3.52 4.12 5.18 4.4 ;
		LAYER M1 ;
		RECT 2.6 3.68 3.2 3.8 ;
		LAYER M1 ;
		RECT 0.36 3.32 3.2 3.68 ;
		LAYER M1 ;
		RECT 0.36 2.78 0.72 3.32 ;
		LAYER M1 ;
		RECT 2.6 3.2 3.2 3.32 ;
		LAYER M1 ;
		RECT 3.52 2.78 3.88 4.12 ;
		LAYER M1 ;
		RECT 0.32 2.26 0.8 2.78 ;
		LAYER M1 ;
		RECT 3.14 2.42 3.88 2.78 ;
		LAYER M1 ;
		RECT 3.14 1.66 3.62 2.42 ;
	END
END MMI_MUX2B
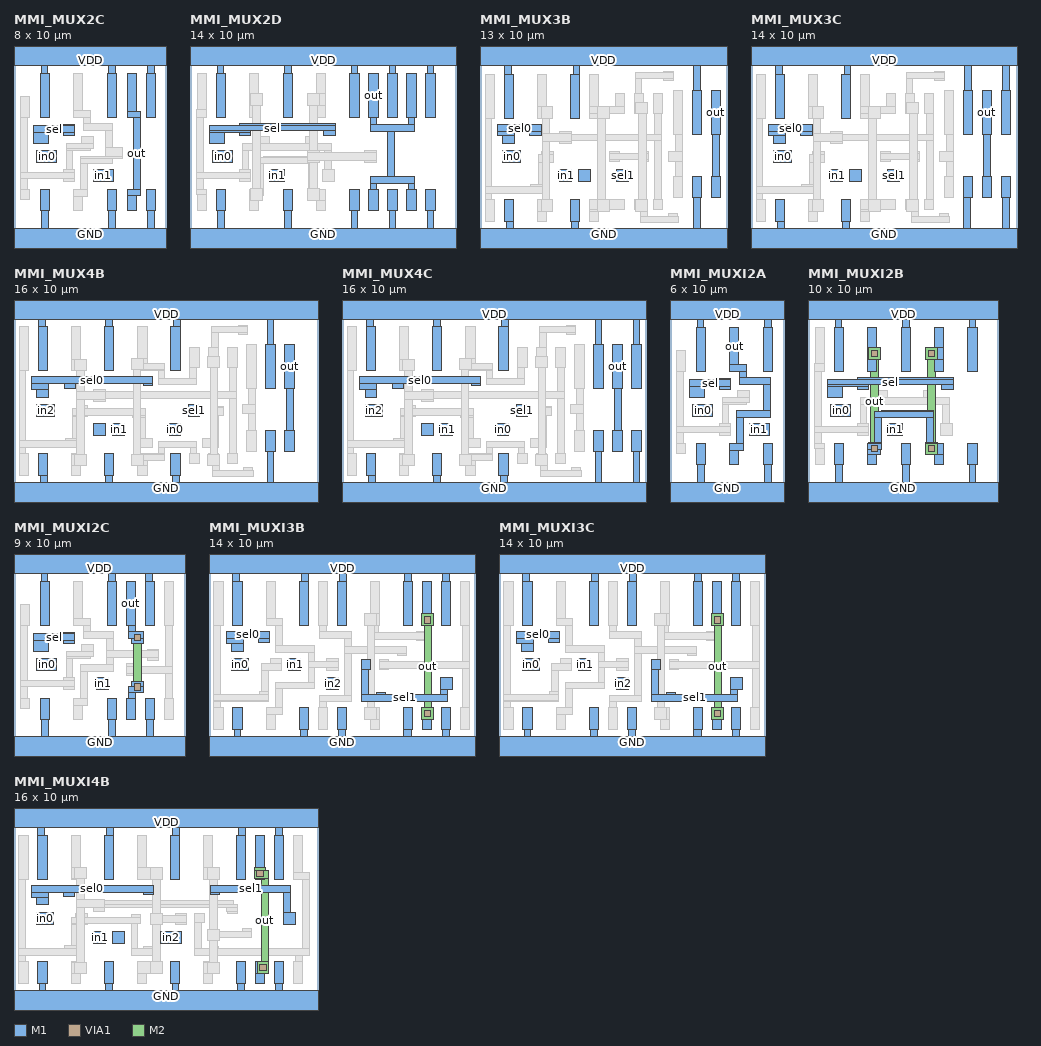
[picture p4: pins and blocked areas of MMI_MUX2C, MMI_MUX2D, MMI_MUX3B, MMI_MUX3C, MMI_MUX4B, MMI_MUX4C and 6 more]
MACRO MMI_MUX2C
	CLASS CORE ;
	FOREIGN MMI_MUX2C 0 0 ;
	SIZE 8 BY 10 ;
	SYMMETRY X Y ;
	SITE CORE1 ;
	PIN out
		DIRECTION output ;
		PORT
			LAYER M1 ;
			RECT 5.96 6.88 6.44 8.86 ;
			LAYER M1 ;
			RECT 5.96 6.54 6.64 6.88 ;
			LAYER M1 ;
			RECT 6.28 2.78 6.64 6.54 ;
			LAYER M1 ;
			RECT 5.96 2.46 6.64 2.78 ;
			LAYER M1 ;
			RECT 5.96 1.66 6.44 2.46 ;
		END
	END out
	PIN sel
		DIRECTION input ;
		PORT
			LAYER M1 ;
			RECT 2.6 6.12 3.2 6.2 ;
			LAYER M1 ;
			RECT 1.04 5.76 3.2 6.12 ;
			LAYER M1 ;
			RECT 1.04 5.2 1.8 5.76 ;
			LAYER M1 ;
			RECT 2.6 5.6 3.2 5.76 ;
		END
	END sel
	PIN in1
		DIRECTION input ;
		PORT
			LAYER M1 ;
			RECT 4.2 3.2 5.22 3.8 ;
		END
	END in1
	PIN GND
		DIRECTION inout ;
		USE GROUND ;
		SHAPE ABUTMENT ;
		PORT
			LAYER M1 ;
			RECT 1.38 1.66 1.86 2.78 ;
			LAYER M1 ;
			RECT 4.9 1.66 5.38 2.78 ;
			LAYER M1 ;
			RECT 6.96 1.66 7.44 2.78 ;
			LAYER M1 ;
			RECT 1.44 0.7 1.8 1.66 ;
			LAYER M1 ;
			RECT 4.96 0.7 5.32 1.66 ;
			LAYER M1 ;
			RECT 7.02 0.7 7.38 1.66 ;
			LAYER M1 ;
			RECT 0 -0.7 8 0.7 ;
		END
	END GND
	PIN VDD
		DIRECTION inout ;
		USE POWER ;
		SHAPE ABUTMENT ;
		PORT
			LAYER M1 ;
			RECT 0 9.3 8 10.7 ;
			LAYER M1 ;
			RECT 1.44 8.86 1.78 9.3 ;
			LAYER M1 ;
			RECT 4.98 8.86 5.34 9.3 ;
			LAYER M1 ;
			RECT 7.02 8.86 7.38 9.3 ;
			LAYER M1 ;
			RECT 1.38 6.54 1.86 8.86 ;
			LAYER M1 ;
			RECT 4.9 6.54 5.38 8.86 ;
			LAYER M1 ;
			RECT 6.96 6.54 7.44 8.86 ;
		END
	END VDD
	PIN in0
		DIRECTION input ;
		PORT
			LAYER M1 ;
			RECT 1.2 4.2 2.24 4.8 ;
		END
	END in0
	OBS
		LAYER M1 ;
		RECT 0.32 6.54 0.8 7.64 ;
		LAYER M1 ;
		RECT 3.14 6.9 3.62 8.86 ;
		LAYER M1 ;
		RECT 3.14 6.54 4 6.9 ;
		LAYER M1 ;
		RECT 0.36 3.68 0.72 6.54 ;
		LAYER M1 ;
		RECT 3.64 6.22 4 6.54 ;
		LAYER M1 ;
		RECT 3.64 5.86 5.18 6.22 ;
		LAYER M1 ;
		RECT 3.56 5.16 4.16 5.54 ;
		LAYER M1 ;
		RECT 2.74 4.94 4.16 5.16 ;
		LAYER M1 ;
		RECT 4.82 5 5.18 5.86 ;
		LAYER M1 ;
		RECT 2.74 4.8 4.04 4.94 ;
		LAYER M1 ;
		RECT 2.74 3.8 3.1 4.8 ;
		LAYER M1 ;
		RECT 4.82 4.48 5.72 5 ;
		LAYER M1 ;
		RECT 3.52 4.4 5.72 4.48 ;
		LAYER M1 ;
		RECT 3.52 4.12 5.18 4.4 ;
		LAYER M1 ;
		RECT 2.6 3.68 3.2 3.8 ;
		LAYER M1 ;
		RECT 0.36 3.32 3.2 3.68 ;
		LAYER M1 ;
		RECT 0.36 2.78 0.72 3.32 ;
		LAYER M1 ;
		RECT 2.6 3.2 3.2 3.32 ;
		LAYER M1 ;
		RECT 3.52 2.78 3.88 4.12 ;
		LAYER M1 ;
		RECT 0.32 2.26 0.8 2.78 ;
		LAYER M1 ;
		RECT 3.14 2.42 3.88 2.78 ;
		LAYER M1 ;
		RECT 3.14 1.66 3.62 2.42 ;
	END
END MMI_MUX2C
MACRO MMI_MUX2D
	CLASS CORE ;
	FOREIGN MMI_MUX2D 0 0 ;
	SIZE 14 BY 10 ;
	SYMMETRY X Y ;
	SITE CORE1 ;
	PIN out
		DIRECTION output ;
		PORT
			LAYER M1 ;
			RECT 9.42 6.54 9.9 8.86 ;
			LAYER M1 ;
			RECT 11.42 6.54 11.9 8.86 ;
			LAYER M1 ;
			RECT 9.48 6.2 9.84 6.54 ;
			LAYER M1 ;
			RECT 11.48 6.2 11.84 6.54 ;
			LAYER M1 ;
			RECT 9.48 5.84 11.84 6.2 ;
			LAYER M1 ;
			RECT 10.4 3.46 10.76 5.84 ;
			LAYER M1 ;
			RECT 9.48 3.1 11.84 3.46 ;
			LAYER M1 ;
			RECT 9.48 2.78 9.84 3.1 ;
			LAYER M1 ;
			RECT 11.48 2.78 11.84 3.1 ;
			LAYER M1 ;
			RECT 9.42 1.66 9.9 2.78 ;
			LAYER M1 ;
			RECT 11.42 1.66 11.9 2.78 ;
		END
	END out
	PIN sel
		DIRECTION input ;
		PORT
			LAYER M1 ;
			RECT 2.6 6.12 7.64 6.22 ;
			LAYER M1 ;
			RECT 1.04 5.86 7.64 6.12 ;
			LAYER M1 ;
			RECT 1.04 5.76 3.2 5.86 ;
			LAYER M1 ;
			RECT 1.04 5.2 1.8 5.76 ;
			LAYER M1 ;
			RECT 2.6 5.62 3.2 5.76 ;
			LAYER M1 ;
			RECT 7.04 5.62 7.64 5.86 ;
		END
	END sel
	PIN in1
		DIRECTION input ;
		PORT
			LAYER M1 ;
			RECT 4.2 3.2 4.96 3.8 ;
		END
	END in1
	PIN GND
		DIRECTION inout ;
		USE GROUND ;
		SHAPE ABUTMENT ;
		PORT
			LAYER M1 ;
			RECT 1.38 1.66 1.86 2.78 ;
			LAYER M1 ;
			RECT 4.9 1.66 5.38 2.78 ;
			LAYER M1 ;
			RECT 8.42 1.66 8.9 2.78 ;
			LAYER M1 ;
			RECT 10.42 1.66 10.9 2.78 ;
			LAYER M1 ;
			RECT 12.42 1.66 12.9 2.78 ;
			LAYER M1 ;
			RECT 1.44 0.7 1.8 1.66 ;
			LAYER M1 ;
			RECT 4.96 0.7 5.32 1.66 ;
			LAYER M1 ;
			RECT 8.48 0.7 8.84 1.66 ;
			LAYER M1 ;
			RECT 10.48 0.7 10.84 1.66 ;
			LAYER M1 ;
			RECT 12.48 0.7 12.84 1.66 ;
			LAYER M1 ;
			RECT 0 -0.7 14 0.7 ;
		END
	END GND
	PIN VDD
		DIRECTION inout ;
		USE POWER ;
		SHAPE ABUTMENT ;
		PORT
			LAYER M1 ;
			RECT 0 9.3 14 10.7 ;
			LAYER M1 ;
			RECT 1.44 8.86 1.78 9.3 ;
			LAYER M1 ;
			RECT 4.98 8.86 5.34 9.3 ;
			LAYER M1 ;
			RECT 8.48 8.86 8.84 9.3 ;
			LAYER M1 ;
			RECT 10.48 8.86 10.84 9.3 ;
			LAYER M1 ;
			RECT 12.48 8.86 12.84 9.3 ;
			LAYER M1 ;
			RECT 1.38 6.54 1.86 8.86 ;
			LAYER M1 ;
			RECT 4.9 6.54 5.38 8.86 ;
			LAYER M1 ;
			RECT 8.42 6.54 8.9 8.86 ;
			LAYER M1 ;
			RECT 10.42 6.54 10.9 8.86 ;
			LAYER M1 ;
			RECT 12.42 6.54 12.9 8.86 ;
		END
	END VDD
	PIN in0
		DIRECTION input ;
		PORT
			LAYER M1 ;
			RECT 1.2 4.2 2.24 4.8 ;
		END
	END in0
	OBS
		LAYER M1 ;
		RECT 0.38 6.96 0.86 8.86 ;
		LAYER M1 ;
		RECT 0.36 6.54 0.86 6.96 ;
		LAYER M1 ;
		RECT 3.14 7.8 3.62 8.86 ;
		LAYER M1 ;
		RECT 3.14 7.2 3.8 7.8 ;
		LAYER M1 ;
		RECT 3.14 6.54 3.62 7.2 ;
		LAYER M1 ;
		RECT 6.66 7.8 7.14 8.86 ;
		LAYER M1 ;
		RECT 6.2 7.2 7.14 7.8 ;
		LAYER M1 ;
		RECT 6.66 6.54 7.14 7.2 ;
		LAYER M1 ;
		RECT 0.36 3.68 0.72 6.54 ;
		LAYER M1 ;
		RECT 3.56 5.16 4.16 5.54 ;
		LAYER M1 ;
		RECT 6.08 5.16 6.68 5.54 ;
		LAYER M1 ;
		RECT 2.74 4.8 7.46 5.16 ;
		LAYER M1 ;
		RECT 2.74 3.8 3.1 4.8 ;
		LAYER M1 ;
		RECT 3.86 4.46 6.62 4.48 ;
		LAYER M1 ;
		RECT 3.52 4.12 6.62 4.46 ;
		LAYER M1 ;
		RECT 2.6 3.68 3.2 3.8 ;
		LAYER M1 ;
		RECT 0.36 3.32 3.2 3.68 ;
		LAYER M1 ;
		RECT 0.36 2.78 0.72 3.32 ;
		LAYER M1 ;
		RECT 2.6 3.2 3.2 3.32 ;
		LAYER M1 ;
		RECT 3.52 2.8 3.88 4.12 ;
		LAYER M1 ;
		RECT 6.26 2.8 6.62 4.12 ;
		LAYER M1 ;
		RECT 7.1 3.8 7.46 4.8 ;
		LAYER M1 ;
		RECT 9.2 4.2 9.8 4.8 ;
		LAYER M1 ;
		RECT 6.98 3.2 7.58 3.8 ;
		LAYER M1 ;
		RECT 3.2 2.78 3.88 2.8 ;
		LAYER M1 ;
		RECT 6.2 2.78 6.8 2.8 ;
		LAYER M1 ;
		RECT 0.36 2.5 0.86 2.78 ;
		LAYER M1 ;
		RECT 0.38 1.66 0.86 2.5 ;
		LAYER M1 ;
		RECT 3.14 2.46 3.88 2.78 ;
		LAYER M1 ;
		RECT 3.14 2.2 3.8 2.46 ;
		LAYER M1 ;
		RECT 3.14 1.66 3.62 2.2 ;
		LAYER M1 ;
		RECT 6.2 2.2 7.14 2.78 ;
		LAYER M1 ;
		RECT 6.66 1.66 7.14 2.2 ;
		LAYER M2 ;
		RECT 3.2 7.2 3.8 7.8 ;
		LAYER M2 ;
		RECT 6.2 7.2 6.8 7.8 ;
		LAYER M2 ;
		RECT 3.3 2.8 3.7 7.2 ;
		LAYER M2 ;
		RECT 6.3 4.8 6.7 7.2 ;
		LAYER M2 ;
		RECT 6.2 4.2 6.8 4.8 ;
		LAYER M2 ;
		RECT 9.2 4.2 9.8 4.8 ;
		LAYER M2 ;
		RECT 6.3 2.8 6.7 4.2 ;
		LAYER M2 ;
		RECT 3.2 2.2 3.8 2.8 ;
		LAYER M2 ;
		RECT 6.2 2.2 6.8 2.8 ;
		LAYER M3 ;
		RECT 6.2 4.7 6.8 4.8 ;
		LAYER M3 ;
		RECT 9.2 4.7 9.8 4.8 ;
		LAYER M3 ;
		RECT 6.2 4.3 9.8 4.7 ;
		LAYER M3 ;
		RECT 6.2 4.2 6.8 4.3 ;
		LAYER M3 ;
		RECT 9.2 4.2 9.8 4.3 ;
	END
END MMI_MUX2D
MACRO MMI_MUX3B
	CLASS CORE ;
	FOREIGN MMI_MUX3B 0 0 ;
	SIZE 13 BY 10 ;
	SYMMETRY X Y ;
	SITE CORE1 ;
	PIN out
		DIRECTION output ;
		PORT
			LAYER M1 ;
			RECT 12.18 5.66 12.66 7.98 ;
			LAYER M1 ;
			RECT 12.26 3.44 12.62 5.66 ;
			LAYER M1 ;
			RECT 12.18 2.32 12.66 3.44 ;
		END
	END out
	PIN in0
		DIRECTION input ;
		PORT
			LAYER M1 ;
			RECT 1.2 4.2 2.12 4.8 ;
		END
	END in0
	PIN in1
		DIRECTION input ;
		PORT
			LAYER M1 ;
			RECT 4.2 3.2 4.8 3.8 ;
		END
	END in1
	PIN GND
		DIRECTION inout ;
		USE GROUND ;
		SHAPE ABUTMENT ;
		PORT
			LAYER M1 ;
			RECT 11.18 2.32 11.66 3.44 ;
			LAYER M1 ;
			RECT 1.38 2.22 1.74 2.24 ;
			LAYER M1 ;
			RECT 1.3 1.1 1.78 2.22 ;
			LAYER M1 ;
			RECT 4.78 1.1 5.26 2.22 ;
			LAYER M1 ;
			RECT 1.38 0.7 1.74 1.1 ;
			LAYER M1 ;
			RECT 4.84 0.7 5.2 1.1 ;
			LAYER M1 ;
			RECT 11.24 0.7 11.6 2.32 ;
			LAYER M1 ;
			RECT 0 -0.7 13 0.7 ;
		END
	END GND
	PIN in2
		DIRECTION input ;
		PORT
			LAYER M1 ;
			RECT 5.2 3.2 5.8 3.8 ;
		END
	END in2
	PIN sel0
		DIRECTION input ;
		PORT
			LAYER M1 ;
			RECT 0.94 5.82 3.22 6.18 ;
			LAYER M1 ;
			RECT 0.94 5.58 1.8 5.82 ;
			LAYER M1 ;
			RECT 2.62 5.58 3.22 5.82 ;
			LAYER M1 ;
			RECT 1.2 5.2 1.8 5.58 ;
		END
	END sel0
	PIN sel1
		DIRECTION input ;
		PORT
			LAYER M1 ;
			RECT 7.2 3.2 7.8 3.8 ;
		END
	END sel1
	PIN VDD
		DIRECTION inout ;
		USE POWER ;
		SHAPE ABUTMENT ;
		PORT
			LAYER M1 ;
			RECT 0 9.3 13 10.7 ;
			LAYER M1 ;
			RECT 1.3 8.84 1.66 9.3 ;
			LAYER M1 ;
			RECT 4.9 8.84 5.26 9.3 ;
			LAYER M1 ;
			RECT 1.3 6.52 1.78 8.84 ;
			LAYER M1 ;
			RECT 4.78 6.52 5.26 8.84 ;
			LAYER M1 ;
			RECT 11.24 7.98 11.6 9.3 ;
			LAYER M1 ;
			RECT 11.18 5.66 11.66 7.98 ;
		END
	END VDD
	OBS
		LAYER M1 ;
		RECT 9.68 8.92 10.16 8.96 ;
		LAYER M1 ;
		RECT 0.3 6.52 0.78 8.84 ;
		LAYER M1 ;
		RECT 3.04 7.12 3.52 8.84 ;
		LAYER M1 ;
		RECT 3.04 6.52 3.82 7.12 ;
		LAYER M1 ;
		RECT 5.78 7.12 6.26 8.84 ;
		LAYER M1 ;
		RECT 8.2 8.6 10.16 8.92 ;
		LAYER M1 ;
		RECT 8.2 7.84 8.52 8.6 ;
		LAYER M1 ;
		RECT 9.68 8.48 10.16 8.6 ;
		LAYER M1 ;
		RECT 7.12 7.12 7.6 7.84 ;
		LAYER M1 ;
		RECT 5.78 6.74 7.6 7.12 ;
		LAYER M1 ;
		RECT 8.12 7.36 8.6 7.84 ;
		LAYER M1 ;
		RECT 8.12 6.76 8.8 7.36 ;
		LAYER M1 ;
		RECT 8.12 6.74 8.6 6.76 ;
		LAYER M1 ;
		RECT 9.12 6.74 9.6 7.84 ;
		LAYER M1 ;
		RECT 5.78 6.52 6.8 6.74 ;
		LAYER M1 ;
		RECT 0.3 2.92 0.62 6.52 ;
		LAYER M1 ;
		RECT 4.2 5.68 4.8 5.8 ;
		LAYER M1 ;
		RECT 9.2 5.68 9.56 6.74 ;
		LAYER M1 ;
		RECT 4.2 5.32 9.56 5.68 ;
		LAYER M1 ;
		RECT 10.18 5.66 10.66 7.98 ;
		LAYER M1 ;
		RECT 4.2 5.2 4.8 5.32 ;
		LAYER M1 ;
		RECT 3.26 4.62 3.86 4.76 ;
		LAYER M1 ;
		RECT 3.1 4.16 3.86 4.62 ;
		LAYER M1 ;
		RECT 6.84 4.68 7.32 4.74 ;
		LAYER M1 ;
		RECT 8.4 4.68 8.88 4.74 ;
		LAYER M1 ;
		RECT 6.84 4.32 8.88 4.68 ;
		LAYER M1 ;
		RECT 6.84 4.26 7.32 4.32 ;
		LAYER M1 ;
		RECT 8.4 4.26 8.88 4.32 ;
		LAYER M1 ;
		RECT 3.1 3.04 3.44 4.16 ;
		LAYER M1 ;
		RECT 2.68 2.92 3.44 3.04 ;
		LAYER M1 ;
		RECT 0.3 2.56 3.44 2.92 ;
		LAYER M1 ;
		RECT 0.3 2.22 0.62 2.56 ;
		LAYER M1 ;
		RECT 1.38 2.22 1.74 2.24 ;
		LAYER M1 ;
		RECT 9.2 2.22 9.56 5.32 ;
		LAYER M1 ;
		RECT 10.28 4.74 10.64 5.66 ;
		LAYER M1 ;
		RECT 9.9 4.26 10.64 4.74 ;
		LAYER M1 ;
		RECT 10.28 3.44 10.64 4.26 ;
		LAYER M1 ;
		RECT 10.18 2.32 10.66 3.44 ;
		LAYER M1 ;
		RECT 0.3 1.1 0.78 2.22 ;
		LAYER M1 ;
		RECT 3.04 1.62 3.82 2.22 ;
		LAYER M1 ;
		RECT 3.04 1.1 3.52 1.62 ;
		LAYER M1 ;
		RECT 5.78 1.7 7.6 2.22 ;
		LAYER M1 ;
		RECT 8.12 1.7 8.8 2.22 ;
		LAYER M1 ;
		RECT 9.12 1.7 9.6 2.22 ;
		LAYER M1 ;
		RECT 5.78 1.62 6.8 1.7 ;
		LAYER M1 ;
		RECT 8.2 1.62 8.8 1.7 ;
		LAYER M1 ;
		RECT 5.78 1.1 6.26 1.62 ;
		LAYER M1 ;
		RECT 8.44 1.34 8.8 1.62 ;
		LAYER M1 ;
		RECT 9.92 1.34 10.4 1.5 ;
		LAYER M1 ;
		RECT 8.44 1.02 10.44 1.34 ;
		LAYER M2 ;
		RECT 3.22 6.52 3.82 7.12 ;
		LAYER M2 ;
		RECT 6.2 6.52 6.8 7.12 ;
		LAYER M2 ;
		RECT 8.2 6.76 8.8 7.36 ;
		LAYER M2 ;
		RECT 3.28 5.7 3.68 6.52 ;
		LAYER M2 ;
		RECT 4.2 5.7 4.8 5.8 ;
		LAYER M2 ;
		RECT 3.28 5.3 4.8 5.7 ;
		LAYER M2 ;
		RECT 3.28 2.22 3.68 5.3 ;
		LAYER M2 ;
		RECT 4.2 5.2 4.8 5.3 ;
		LAYER M2 ;
		RECT 6.2 2.22 6.6 6.52 ;
		LAYER M2 ;
		RECT 8.34 2.22 8.74 6.76 ;
		LAYER M2 ;
		RECT 3.22 1.62 3.82 2.22 ;
		LAYER M2 ;
		RECT 6.2 1.62 6.8 2.22 ;
		LAYER M2 ;
		RECT 8.2 1.62 8.8 2.22 ;
	END
END MMI_MUX3B
MACRO MMI_MUX3C
	CLASS CORE ;
	FOREIGN MMI_MUX3C 0 0 ;
	SIZE 14 BY 10 ;
	SYMMETRY X Y ;
	SITE CORE1 ;
	PIN out
		DIRECTION output ;
		PORT
			LAYER M1 ;
			RECT 12.18 5.66 12.66 7.98 ;
			LAYER M1 ;
			RECT 12.26 3.44 12.62 5.66 ;
			LAYER M1 ;
			RECT 12.18 2.32 12.66 3.44 ;
		END
	END out
	PIN in0
		DIRECTION input ;
		PORT
			LAYER M1 ;
			RECT 1.2 4.2 2.12 4.8 ;
		END
	END in0
	PIN in1
		DIRECTION input ;
		PORT
			LAYER M1 ;
			RECT 4.2 3.2 4.8 3.8 ;
		END
	END in1
	PIN GND
		DIRECTION inout ;
		USE GROUND ;
		SHAPE ABUTMENT ;
		PORT
			LAYER M1 ;
			RECT 11.18 2.32 11.66 3.44 ;
			LAYER M1 ;
			RECT 13.18 2.32 13.66 3.44 ;
			LAYER M1 ;
			RECT 1.38 2.22 1.74 2.24 ;
			LAYER M1 ;
			RECT 1.3 1.1 1.78 2.22 ;
			LAYER M1 ;
			RECT 4.78 1.1 5.26 2.22 ;
			LAYER M1 ;
			RECT 1.38 0.7 1.74 1.1 ;
			LAYER M1 ;
			RECT 4.84 0.7 5.2 1.1 ;
			LAYER M1 ;
			RECT 11.18 0.7 11.54 2.32 ;
			LAYER M1 ;
			RECT 13.24 0.7 13.6 2.32 ;
			LAYER M1 ;
			RECT 0 -0.7 14 0.7 ;
		END
	END GND
	PIN in2
		DIRECTION input ;
		PORT
			LAYER M1 ;
			RECT 5.2 3.2 5.8 3.8 ;
		END
	END in2
	PIN sel0
		DIRECTION input ;
		PORT
			LAYER M1 ;
			RECT 0.94 5.82 3.22 6.18 ;
			LAYER M1 ;
			RECT 0.94 5.58 1.8 5.82 ;
			LAYER M1 ;
			RECT 2.62 5.58 3.22 5.82 ;
			LAYER M1 ;
			RECT 1.2 5.2 1.8 5.58 ;
		END
	END sel0
	PIN sel1
		DIRECTION input ;
		PORT
			LAYER M1 ;
			RECT 7.2 3.2 7.8 3.8 ;
		END
	END sel1
	PIN VDD
		DIRECTION inout ;
		USE POWER ;
		SHAPE ABUTMENT ;
		PORT
			LAYER M1 ;
			RECT 0 9.3 14 10.7 ;
			LAYER M1 ;
			RECT 1.3 8.84 1.66 9.3 ;
			LAYER M1 ;
			RECT 4.9 8.84 5.26 9.3 ;
			LAYER M1 ;
			RECT 1.3 6.52 1.78 8.84 ;
			LAYER M1 ;
			RECT 4.78 6.52 5.26 8.84 ;
			LAYER M1 ;
			RECT 11.24 7.98 11.6 9.3 ;
			LAYER M1 ;
			RECT 13.24 7.98 13.6 9.3 ;
			LAYER M1 ;
			RECT 11.18 5.66 11.66 7.98 ;
			LAYER M1 ;
			RECT 13.18 5.66 13.66 7.98 ;
		END
	END VDD
	OBS
		LAYER M1 ;
		RECT 9.68 8.92 10.16 8.96 ;
		LAYER M1 ;
		RECT 0.3 6.52 0.78 8.84 ;
		LAYER M1 ;
		RECT 3.04 7.12 3.52 8.84 ;
		LAYER M1 ;
		RECT 3.04 6.52 3.82 7.12 ;
		LAYER M1 ;
		RECT 5.78 7.12 6.26 8.84 ;
		LAYER M1 ;
		RECT 8.2 8.6 10.16 8.92 ;
		LAYER M1 ;
		RECT 8.2 7.84 8.52 8.6 ;
		LAYER M1 ;
		RECT 9.68 8.48 10.16 8.6 ;
		LAYER M1 ;
		RECT 7.12 7.12 7.6 7.84 ;
		LAYER M1 ;
		RECT 5.78 6.74 7.6 7.12 ;
		LAYER M1 ;
		RECT 8.12 7.36 8.6 7.84 ;
		LAYER M1 ;
		RECT 8.12 6.76 8.8 7.36 ;
		LAYER M1 ;
		RECT 8.12 6.74 8.6 6.76 ;
		LAYER M1 ;
		RECT 9.12 6.74 9.6 7.84 ;
		LAYER M1 ;
		RECT 5.78 6.52 6.8 6.74 ;
		LAYER M1 ;
		RECT 0.3 2.92 0.62 6.52 ;
		LAYER M1 ;
		RECT 4.2 5.68 4.8 5.8 ;
		LAYER M1 ;
		RECT 9.22 5.68 9.58 6.74 ;
		LAYER M1 ;
		RECT 4.2 5.32 9.58 5.68 ;
		LAYER M1 ;
		RECT 10.18 5.66 10.66 7.98 ;
		LAYER M1 ;
		RECT 4.2 5.2 4.8 5.32 ;
		LAYER M1 ;
		RECT 3.26 4.62 3.86 4.76 ;
		LAYER M1 ;
		RECT 3.1 4.16 3.86 4.62 ;
		LAYER M1 ;
		RECT 6.84 4.68 7.32 4.74 ;
		LAYER M1 ;
		RECT 8.4 4.68 8.88 4.74 ;
		LAYER M1 ;
		RECT 6.84 4.32 8.88 4.68 ;
		LAYER M1 ;
		RECT 6.84 4.26 7.32 4.32 ;
		LAYER M1 ;
		RECT 8.4 4.26 8.88 4.32 ;
		LAYER M1 ;
		RECT 3.1 3.04 3.44 4.16 ;
		LAYER M1 ;
		RECT 2.68 2.92 3.44 3.04 ;
		LAYER M1 ;
		RECT 0.3 2.56 3.44 2.92 ;
		LAYER M1 ;
		RECT 0.3 2.22 0.62 2.56 ;
		LAYER M1 ;
		RECT 1.38 2.22 1.74 2.24 ;
		LAYER M1 ;
		RECT 9.22 2.22 9.58 5.32 ;
		LAYER M1 ;
		RECT 10.28 4.74 10.64 5.66 ;
		LAYER M1 ;
		RECT 9.9 4.26 10.64 4.74 ;
		LAYER M1 ;
		RECT 10.28 3.44 10.64 4.26 ;
		LAYER M1 ;
		RECT 10.18 2.32 10.66 3.44 ;
		LAYER M1 ;
		RECT 0.3 1.1 0.78 2.22 ;
		LAYER M1 ;
		RECT 3.04 1.62 3.82 2.22 ;
		LAYER M1 ;
		RECT 3.04 1.1 3.52 1.62 ;
		LAYER M1 ;
		RECT 5.78 1.7 7.6 2.22 ;
		LAYER M1 ;
		RECT 8.12 1.7 8.8 2.22 ;
		LAYER M1 ;
		RECT 9.12 1.7 9.6 2.22 ;
		LAYER M1 ;
		RECT 5.78 1.62 6.8 1.7 ;
		LAYER M1 ;
		RECT 8.2 1.62 8.8 1.7 ;
		LAYER M1 ;
		RECT 5.78 1.1 6.26 1.62 ;
		LAYER M1 ;
		RECT 8.44 1.34 8.8 1.62 ;
		LAYER M1 ;
		RECT 9.92 1.34 10.4 1.5 ;
		LAYER M1 ;
		RECT 8.44 1.02 10.44 1.34 ;
		LAYER M2 ;
		RECT 3.22 6.52 3.82 7.12 ;
		LAYER M2 ;
		RECT 6.2 6.52 6.8 7.12 ;
		LAYER M2 ;
		RECT 8.2 6.76 8.8 7.36 ;
		LAYER M2 ;
		RECT 3.28 5.7 3.68 6.52 ;
		LAYER M2 ;
		RECT 4.2 5.7 4.8 5.8 ;
		LAYER M2 ;
		RECT 3.28 5.3 4.8 5.7 ;
		LAYER M2 ;
		RECT 3.28 2.22 3.68 5.3 ;
		LAYER M2 ;
		RECT 4.2 5.2 4.8 5.3 ;
		LAYER M2 ;
		RECT 6.2 2.22 6.6 6.52 ;
		LAYER M2 ;
		RECT 8.34 2.22 8.74 6.76 ;
		LAYER M2 ;
		RECT 3.22 1.62 3.82 2.22 ;
		LAYER M2 ;
		RECT 6.2 1.62 6.8 2.22 ;
		LAYER M2 ;
		RECT 8.2 1.62 8.8 2.22 ;
	END
END MMI_MUX3C
MACRO MMI_MUX4B
	CLASS CORE ;
	FOREIGN MMI_MUX4B 0 0 ;
	SIZE 16 BY 10 ;
	SYMMETRY X Y ;
	SITE CORE1 ;
	PIN out
		DIRECTION output ;
		PORT
			LAYER M1 ;
			RECT 14.26 5.66 14.74 7.98 ;
			LAYER M1 ;
			RECT 14.34 3.44 14.7 5.66 ;
			LAYER M1 ;
			RECT 14.26 2.32 14.74 3.44 ;
		END
	END out
	PIN in0
		DIRECTION input ;
		PORT
			LAYER M1 ;
			RECT 8.16 3.2 8.76 3.8 ;
		END
	END in0
	PIN in1
		DIRECTION input ;
		PORT
			LAYER M1 ;
			RECT 5.2 3.2 5.8 3.8 ;
		END
	END in1
	PIN GND
		DIRECTION inout ;
		USE GROUND ;
		SHAPE ABUTMENT ;
		PORT
			LAYER M1 ;
			RECT 13.26 2.32 13.74 3.44 ;
			LAYER M1 ;
			RECT 1.3 1.1 1.78 2.22 ;
			LAYER M1 ;
			RECT 4.78 1.1 5.26 2.22 ;
			LAYER M1 ;
			RECT 8.26 1.1 8.74 2.22 ;
			LAYER M1 ;
			RECT 1.38 0.7 1.74 1.1 ;
			LAYER M1 ;
			RECT 4.84 0.7 5.2 1.1 ;
			LAYER M1 ;
			RECT 8.34 0.7 8.7 1.1 ;
			LAYER M1 ;
			RECT 13.32 0.7 13.68 2.32 ;
			LAYER M1 ;
			RECT 0 -0.7 16 0.7 ;
		END
	END GND
	PIN in2
		DIRECTION input ;
		PORT
			LAYER M1 ;
			RECT 1.2 4.2 2.12 4.8 ;
		END
	END in2
	PIN in3
		DIRECTION input ;
		PORT
			LAYER M1 ;
			RECT 4.2 3.2 4.8 3.8 ;
		END
	END in3
	PIN sel0
		DIRECTION input ;
		PORT
			LAYER M1 ;
			RECT 0.94 5.92 7.3 6.28 ;
			LAYER M1 ;
			RECT 0.94 5.58 1.82 5.92 ;
			LAYER M1 ;
			RECT 2.66 5.68 3.26 5.92 ;
			LAYER M1 ;
			RECT 6.82 5.8 7.3 5.92 ;
			LAYER M1 ;
			RECT 1.2 5.2 1.82 5.58 ;
		END
	END sel0
	PIN sel1
		DIRECTION input ;
		PORT
			LAYER M1 ;
			RECT 9.16 4.2 9.76 4.8 ;
		END
	END sel1
	PIN VDD
		DIRECTION inout ;
		USE POWER ;
		SHAPE ABUTMENT ;
		PORT
			LAYER M1 ;
			RECT 0 9.3 16 10.7 ;
			LAYER M1 ;
			RECT 1.3 8.94 1.66 9.3 ;
			LAYER M1 ;
			RECT 4.84 8.94 5.2 9.3 ;
			LAYER M1 ;
			RECT 8.38 8.94 8.74 9.3 ;
			LAYER M1 ;
			RECT 1.3 6.62 1.78 8.94 ;
			LAYER M1 ;
			RECT 4.78 6.62 5.26 8.94 ;
			LAYER M1 ;
			RECT 8.26 6.62 8.74 8.94 ;
			LAYER M1 ;
			RECT 13.32 7.98 13.68 9.3 ;
			LAYER M1 ;
			RECT 13.26 5.66 13.74 7.98 ;
		END
	END VDD
	OBS
		LAYER M1 ;
		RECT 0.3 6.62 0.78 8.94 ;
		LAYER M1 ;
		RECT 3.04 7.2 3.52 8.94 ;
		LAYER M1 ;
		RECT 3.04 6.62 3.8 7.2 ;
		LAYER M1 ;
		RECT 6.52 7.24 7 8.94 ;
		LAYER M1 ;
		RECT 6.2 6.98 7 7.24 ;
		LAYER M1 ;
		RECT 6.2 6.64 7.94 6.98 ;
		LAYER M1 ;
		RECT 6.52 6.62 7.94 6.64 ;
		LAYER M1 ;
		RECT 11.82 8.92 12.3 8.96 ;
		LAYER M1 ;
		RECT 10.42 8.6 12.3 8.92 ;
		LAYER M1 ;
		RECT 10.42 7.84 10.74 8.6 ;
		LAYER M1 ;
		RECT 11.82 8.48 12.3 8.6 ;
		LAYER M1 ;
		RECT 9.26 6.74 9.74 7.84 ;
		LAYER M1 ;
		RECT 10.26 7.36 10.74 7.84 ;
		LAYER M1 ;
		RECT 10.2 6.76 10.8 7.36 ;
		LAYER M1 ;
		RECT 10.26 6.74 10.74 6.76 ;
		LAYER M1 ;
		RECT 11.26 6.74 11.74 7.84 ;
		LAYER M1 ;
		RECT 0.3 2.9 0.62 6.62 ;
		LAYER M1 ;
		RECT 3.2 6.6 3.8 6.62 ;
		LAYER M1 ;
		RECT 7.62 6.18 7.94 6.62 ;
		LAYER M1 ;
		RECT 9.26 6.18 9.6 6.74 ;
		LAYER M1 ;
		RECT 7.62 5.86 9.6 6.18 ;
		LAYER M1 ;
		RECT 4.2 5.48 4.8 5.6 ;
		LAYER M1 ;
		RECT 11.36 5.48 11.72 6.74 ;
		LAYER M1 ;
		RECT 12.26 5.66 12.74 7.98 ;
		LAYER M1 ;
		RECT 4.2 5.12 11.72 5.48 ;
		LAYER M1 ;
		RECT 4.2 5 4.8 5.12 ;
		LAYER M1 ;
		RECT 3.28 4.62 3.88 4.76 ;
		LAYER M1 ;
		RECT 3.1 4.26 6.9 4.62 ;
		LAYER M1 ;
		RECT 3.1 4.16 3.88 4.26 ;
		LAYER M1 ;
		RECT 3.1 3.02 3.44 4.16 ;
		LAYER M1 ;
		RECT 6.22 4.12 6.9 4.26 ;
		LAYER M1 ;
		RECT 10.54 4.68 11.02 4.7 ;
		LAYER M1 ;
		RECT 10.38 4.22 11.02 4.68 ;
		LAYER M1 ;
		RECT 2.7 2.9 3.44 3.02 ;
		LAYER M1 ;
		RECT 0.3 2.54 3.44 2.9 ;
		LAYER M1 ;
		RECT 6.56 3.04 6.9 4.12 ;
		LAYER M1 ;
		RECT 10.38 3.04 10.74 4.22 ;
		LAYER M1 ;
		RECT 6.56 2.56 7.3 3.04 ;
		LAYER M1 ;
		RECT 6.56 2.54 7.1 2.56 ;
		LAYER M1 ;
		RECT 7.62 2.54 9.62 2.88 ;
		LAYER M1 ;
		RECT 9.94 2.56 10.74 3.04 ;
		LAYER M1 ;
		RECT 0.3 2.22 0.62 2.54 ;
		LAYER M1 ;
		RECT 7.62 2.22 7.94 2.54 ;
		LAYER M1 ;
		RECT 9.28 2.22 9.62 2.54 ;
		LAYER M1 ;
		RECT 11.36 2.22 11.72 5.12 ;
		LAYER M1 ;
		RECT 12.36 4.8 12.72 5.66 ;
		LAYER M1 ;
		RECT 12.04 4.32 12.72 4.8 ;
		LAYER M1 ;
		RECT 12.36 3.44 12.72 4.32 ;
		LAYER M1 ;
		RECT 12.26 2.32 12.74 3.44 ;
		LAYER M1 ;
		RECT 0.3 1.1 0.78 2.22 ;
		LAYER M1 ;
		RECT 3.04 2.2 3.52 2.22 ;
		LAYER M1 ;
		RECT 3.04 1.6 3.8 2.2 ;
		LAYER M1 ;
		RECT 3.04 1.1 3.52 1.6 ;
		LAYER M1 ;
		RECT 6.52 2.2 7.94 2.22 ;
		LAYER M1 ;
		RECT 6.2 1.86 7.94 2.2 ;
		LAYER M1 ;
		RECT 6.2 1.6 7 1.86 ;
		LAYER M1 ;
		RECT 6.52 1.1 7 1.6 ;
		LAYER M1 ;
		RECT 9.26 1.7 9.74 2.22 ;
		LAYER M1 ;
		RECT 10.26 2.2 10.74 2.22 ;
		LAYER M1 ;
		RECT 10.2 1.6 10.8 2.2 ;
		LAYER M1 ;
		RECT 11.26 1.7 11.74 2.22 ;
		LAYER M1 ;
		RECT 10.44 1.34 10.8 1.6 ;
		LAYER M1 ;
		RECT 12.06 1.34 12.54 1.5 ;
		LAYER M1 ;
		RECT 10.44 1.02 12.58 1.34 ;
		LAYER M2 ;
		RECT 3.2 6.6 3.8 7.2 ;
		LAYER M2 ;
		RECT 6.2 6.64 6.8 7.24 ;
		LAYER M2 ;
		RECT 10.2 6.76 10.8 7.36 ;
		LAYER M2 ;
		RECT 3.3 5.48 3.7 6.6 ;
		LAYER M2 ;
		RECT 4.2 5.48 4.8 5.6 ;
		LAYER M2 ;
		RECT 3.3 5.08 4.8 5.48 ;
		LAYER M2 ;
		RECT 3.3 2.2 3.7 5.08 ;
		LAYER M2 ;
		RECT 4.2 5 4.8 5.08 ;
		LAYER M2 ;
		RECT 6.28 2.2 6.68 6.64 ;
		LAYER M2 ;
		RECT 10.32 2.2 10.72 6.76 ;
		LAYER M2 ;
		RECT 3.2 1.6 3.8 2.2 ;
		LAYER M2 ;
		RECT 6.2 1.6 6.8 2.2 ;
		LAYER M2 ;
		RECT 10.2 1.6 10.8 2.2 ;
	END
END MMI_MUX4B
MACRO MMI_MUX4C
	CLASS CORE ;
	FOREIGN MMI_MUX4C 0 0 ;
	SIZE 16 BY 10 ;
	SYMMETRY X Y ;
	SITE CORE1 ;
	PIN out
		DIRECTION output ;
		PORT
			LAYER M1 ;
			RECT 14.26 5.66 14.74 7.98 ;
			LAYER M1 ;
			RECT 14.34 3.44 14.7 5.66 ;
			LAYER M1 ;
			RECT 14.26 2.32 14.74 3.44 ;
		END
	END out
	PIN in0
		DIRECTION input ;
		PORT
			LAYER M1 ;
			RECT 8.16 3.2 8.76 3.8 ;
		END
	END in0
	PIN in1
		DIRECTION input ;
		PORT
			LAYER M1 ;
			RECT 5.2 3.2 5.8 3.8 ;
		END
	END in1
	PIN GND
		DIRECTION inout ;
		USE GROUND ;
		SHAPE ABUTMENT ;
		PORT
			LAYER M1 ;
			RECT 13.26 2.32 13.74 3.44 ;
			LAYER M1 ;
			RECT 15.26 2.32 15.74 3.44 ;
			LAYER M1 ;
			RECT 1.3 1.1 1.78 2.22 ;
			LAYER M1 ;
			RECT 4.78 1.1 5.26 2.22 ;
			LAYER M1 ;
			RECT 8.26 1.1 8.74 2.22 ;
			LAYER M1 ;
			RECT 1.38 0.7 1.74 1.1 ;
			LAYER M1 ;
			RECT 4.84 0.7 5.2 1.1 ;
			LAYER M1 ;
			RECT 8.34 0.7 8.7 1.1 ;
			LAYER M1 ;
			RECT 13.32 0.7 13.68 2.32 ;
			LAYER M1 ;
			RECT 15.32 0.7 15.68 2.32 ;
			LAYER M1 ;
			RECT 0 -0.7 16 0.7 ;
		END
	END GND
	PIN in2
		DIRECTION input ;
		PORT
			LAYER M1 ;
			RECT 1.24 4.2 2.12 4.8 ;
		END
	END in2
	PIN in3
		DIRECTION input ;
		PORT
			LAYER M1 ;
			RECT 4.2 3.2 4.8 3.8 ;
		END
	END in3
	PIN sel0
		DIRECTION input ;
		PORT
			LAYER M1 ;
			RECT 0.94 5.92 7.3 6.28 ;
			LAYER M1 ;
			RECT 0.94 5.58 1.84 5.92 ;
			LAYER M1 ;
			RECT 2.66 5.68 3.26 5.92 ;
			LAYER M1 ;
			RECT 6.82 5.8 7.3 5.92 ;
			LAYER M1 ;
			RECT 1.22 5.2 1.84 5.58 ;
		END
	END sel0
	PIN sel1
		DIRECTION input ;
		PORT
			LAYER M1 ;
			RECT 9.16 4.2 9.76 4.8 ;
		END
	END sel1
	PIN VDD
		DIRECTION inout ;
		USE POWER ;
		SHAPE ABUTMENT ;
		PORT
			LAYER M1 ;
			RECT 0 9.3 16 10.7 ;
			LAYER M1 ;
			RECT 1.3 8.94 1.66 9.3 ;
			LAYER M1 ;
			RECT 4.84 8.94 5.2 9.3 ;
			LAYER M1 ;
			RECT 8.38 8.94 8.74 9.3 ;
			LAYER M1 ;
			RECT 1.3 6.62 1.78 8.94 ;
			LAYER M1 ;
			RECT 4.78 6.62 5.26 8.94 ;
			LAYER M1 ;
			RECT 8.26 6.62 8.74 8.94 ;
			LAYER M1 ;
			RECT 13.32 7.98 13.68 9.3 ;
			LAYER M1 ;
			RECT 15.32 7.98 15.68 9.3 ;
			LAYER M1 ;
			RECT 13.26 5.66 13.74 7.98 ;
			LAYER M1 ;
			RECT 15.26 5.66 15.74 7.98 ;
		END
	END VDD
	OBS
		LAYER M1 ;
		RECT 0.3 6.62 0.78 8.94 ;
		LAYER M1 ;
		RECT 3.04 7.2 3.52 8.94 ;
		LAYER M1 ;
		RECT 3.04 6.62 3.8 7.2 ;
		LAYER M1 ;
		RECT 6.52 7.24 7 8.94 ;
		LAYER M1 ;
		RECT 6.2 6.98 7 7.24 ;
		LAYER M1 ;
		RECT 6.2 6.64 7.94 6.98 ;
		LAYER M1 ;
		RECT 6.52 6.62 7.94 6.64 ;
		LAYER M1 ;
		RECT 11.82 8.92 12.3 8.96 ;
		LAYER M1 ;
		RECT 10.42 8.6 12.3 8.92 ;
		LAYER M1 ;
		RECT 10.42 7.84 10.74 8.6 ;
		LAYER M1 ;
		RECT 11.82 8.48 12.3 8.6 ;
		LAYER M1 ;
		RECT 9.26 6.74 9.74 7.84 ;
		LAYER M1 ;
		RECT 10.26 7.36 10.74 7.84 ;
		LAYER M1 ;
		RECT 10.2 6.76 10.8 7.36 ;
		LAYER M1 ;
		RECT 10.26 6.74 10.74 6.76 ;
		LAYER M1 ;
		RECT 11.26 6.74 11.74 7.84 ;
		LAYER M1 ;
		RECT 0.3 2.9 0.62 6.62 ;
		LAYER M1 ;
		RECT 3.2 6.6 3.8 6.62 ;
		LAYER M1 ;
		RECT 7.62 6.18 7.94 6.62 ;
		LAYER M1 ;
		RECT 9.26 6.18 9.6 6.74 ;
		LAYER M1 ;
		RECT 7.62 5.86 9.6 6.18 ;
		LAYER M1 ;
		RECT 4.2 5.48 4.8 5.6 ;
		LAYER M1 ;
		RECT 11.36 5.48 11.72 6.74 ;
		LAYER M1 ;
		RECT 12.26 5.66 12.74 7.98 ;
		LAYER M1 ;
		RECT 4.2 5.12 11.72 5.48 ;
		LAYER M1 ;
		RECT 4.2 5 4.8 5.12 ;
		LAYER M1 ;
		RECT 3.28 4.62 3.88 4.76 ;
		LAYER M1 ;
		RECT 3.1 4.26 6.9 4.62 ;
		LAYER M1 ;
		RECT 3.1 4.16 3.88 4.26 ;
		LAYER M1 ;
		RECT 3.1 3.02 3.44 4.16 ;
		LAYER M1 ;
		RECT 6.22 4.12 6.9 4.26 ;
		LAYER M1 ;
		RECT 10.54 4.68 11.02 4.7 ;
		LAYER M1 ;
		RECT 10.38 4.22 11.02 4.68 ;
		LAYER M1 ;
		RECT 2.7 2.9 3.44 3.02 ;
		LAYER M1 ;
		RECT 0.3 2.54 3.44 2.9 ;
		LAYER M1 ;
		RECT 6.56 3.04 6.9 4.12 ;
		LAYER M1 ;
		RECT 10.38 3.04 10.74 4.22 ;
		LAYER M1 ;
		RECT 6.56 2.56 7.3 3.04 ;
		LAYER M1 ;
		RECT 6.56 2.54 7.1 2.56 ;
		LAYER M1 ;
		RECT 7.62 2.54 9.62 2.88 ;
		LAYER M1 ;
		RECT 9.94 2.56 10.74 3.04 ;
		LAYER M1 ;
		RECT 0.3 2.22 0.62 2.54 ;
		LAYER M1 ;
		RECT 7.62 2.22 7.94 2.54 ;
		LAYER M1 ;
		RECT 9.28 2.22 9.62 2.54 ;
		LAYER M1 ;
		RECT 11.36 2.22 11.72 5.12 ;
		LAYER M1 ;
		RECT 12.36 4.8 12.72 5.66 ;
		LAYER M1 ;
		RECT 12.04 4.32 12.72 4.8 ;
		LAYER M1 ;
		RECT 12.36 3.44 12.72 4.32 ;
		LAYER M1 ;
		RECT 12.26 2.32 12.74 3.44 ;
		LAYER M1 ;
		RECT 0.3 1.1 0.78 2.22 ;
		LAYER M1 ;
		RECT 3.04 2.2 3.52 2.22 ;
		LAYER M1 ;
		RECT 3.04 1.6 3.8 2.2 ;
		LAYER M1 ;
		RECT 3.04 1.1 3.52 1.6 ;
		LAYER M1 ;
		RECT 6.52 2.2 7.94 2.22 ;
		LAYER M1 ;
		RECT 6.2 1.86 7.94 2.2 ;
		LAYER M1 ;
		RECT 6.2 1.6 7 1.86 ;
		LAYER M1 ;
		RECT 6.52 1.1 7 1.6 ;
		LAYER M1 ;
		RECT 9.26 1.7 9.74 2.22 ;
		LAYER M1 ;
		RECT 10.26 2.2 10.74 2.22 ;
		LAYER M1 ;
		RECT 10.2 1.6 10.8 2.2 ;
		LAYER M1 ;
		RECT 11.26 1.7 11.74 2.22 ;
		LAYER M1 ;
		RECT 10.44 1.34 10.8 1.6 ;
		LAYER M1 ;
		RECT 12.06 1.34 12.54 1.5 ;
		LAYER M1 ;
		RECT 10.44 1.02 12.58 1.34 ;
		LAYER M2 ;
		RECT 3.2 6.6 3.8 7.2 ;
		LAYER M2 ;
		RECT 6.2 6.64 6.8 7.24 ;
		LAYER M2 ;
		RECT 10.2 6.76 10.8 7.36 ;
		LAYER M2 ;
		RECT 3.3 5.48 3.7 6.6 ;
		LAYER M2 ;
		RECT 4.2 5.48 4.8 5.6 ;
		LAYER M2 ;
		RECT 3.3 5.08 4.8 5.48 ;
		LAYER M2 ;
		RECT 3.3 2.2 3.7 5.08 ;
		LAYER M2 ;
		RECT 4.2 5 4.8 5.08 ;
		LAYER M2 ;
		RECT 6.28 2.2 6.68 6.64 ;
		LAYER M2 ;
		RECT 10.32 2.2 10.72 6.76 ;
		LAYER M2 ;
		RECT 3.2 1.6 3.8 2.2 ;
		LAYER M2 ;
		RECT 6.2 1.6 6.8 2.2 ;
		LAYER M2 ;
		RECT 10.2 1.6 10.8 2.2 ;
	END
END MMI_MUX4C
MACRO MMI_MUXI2A
	CLASS CORE ;
	FOREIGN MMI_MUXI2A 0 0 ;
	SIZE 6 BY 10 ;
	SYMMETRY X Y ;
	SITE CORE1 ;
	PIN sel
		DIRECTION input ;
		PORT
			LAYER M1 ;
			RECT 2.6 6.12 3.2 6.2 ;
			LAYER M1 ;
			RECT 1.04 5.76 3.2 6.12 ;
			LAYER M1 ;
			RECT 1.04 5.2 1.8 5.76 ;
			LAYER M1 ;
			RECT 2.6 5.6 3.2 5.76 ;
		END
	END sel
	PIN out
		DIRECTION output ;
		PORT
			LAYER M1 ;
			RECT 3.14 6.9 3.62 8.86 ;
			LAYER M1 ;
			RECT 3.14 6.54 4 6.9 ;
			LAYER M1 ;
			RECT 3.64 6.22 4 6.54 ;
			LAYER M1 ;
			RECT 3.64 5.86 5.3 6.22 ;
			LAYER M1 ;
			RECT 4.94 4.48 5.3 5.86 ;
			LAYER M1 ;
			RECT 3.52 4.12 5.3 4.48 ;
			LAYER M1 ;
			RECT 3.52 2.78 3.88 4.12 ;
			LAYER M1 ;
			RECT 3.14 2.42 3.88 2.78 ;
			LAYER M1 ;
			RECT 3.14 1.66 3.62 2.42 ;
		END
	END out
	PIN in1
		DIRECTION input ;
		PORT
			LAYER M1 ;
			RECT 4.2 3.2 5.22 3.8 ;
		END
	END in1
	PIN GND
		DIRECTION inout ;
		USE GROUND ;
		SHAPE ABUTMENT ;
		PORT
			LAYER M1 ;
			RECT 1.38 1.66 1.86 2.78 ;
			LAYER M1 ;
			RECT 4.9 1.66 5.38 2.78 ;
			LAYER M1 ;
			RECT 1.44 0.7 1.8 1.66 ;
			LAYER M1 ;
			RECT 4.96 0.7 5.32 1.66 ;
			LAYER M1 ;
			RECT 0 -0.7 6 0.7 ;
		END
	END GND
	PIN VDD
		DIRECTION inout ;
		USE POWER ;
		SHAPE ABUTMENT ;
		PORT
			LAYER M1 ;
			RECT 0 9.3 6 10.7 ;
			LAYER M1 ;
			RECT 1.44 8.86 1.78 9.3 ;
			LAYER M1 ;
			RECT 4.98 8.86 5.34 9.3 ;
			LAYER M1 ;
			RECT 1.38 6.54 1.86 8.86 ;
			LAYER M1 ;
			RECT 4.9 6.54 5.38 8.86 ;
		END
	END VDD
	PIN in0
		DIRECTION input ;
		PORT
			LAYER M1 ;
			RECT 1.2 4.2 2.24 4.8 ;
		END
	END in0
	OBS
		LAYER M1 ;
		RECT 0.32 6.54 0.8 7.64 ;
		LAYER M1 ;
		RECT 0.36 3.68 0.72 6.54 ;
		LAYER M1 ;
		RECT 3.56 5.16 4.16 5.54 ;
		LAYER M1 ;
		RECT 2.74 4.94 4.16 5.16 ;
		LAYER M1 ;
		RECT 2.74 4.8 4.04 4.94 ;
		LAYER M1 ;
		RECT 2.74 3.8 3.1 4.8 ;
		LAYER M1 ;
		RECT 2.6 3.68 3.2 3.8 ;
		LAYER M1 ;
		RECT 0.36 3.32 3.2 3.68 ;
		LAYER M1 ;
		RECT 0.36 2.78 0.72 3.32 ;
		LAYER M1 ;
		RECT 2.6 3.2 3.2 3.32 ;
		LAYER M1 ;
		RECT 0.32 2.26 0.8 2.78 ;
	END
END MMI_MUXI2A
MACRO MMI_MUXI2B
	CLASS CORE ;
	FOREIGN MMI_MUXI2B 0 0 ;
	SIZE 10 BY 10 ;
	SYMMETRY X Y ;
	SITE CORE1 ;
	PIN sel
		DIRECTION input ;
		PORT
			LAYER M1 ;
			RECT 2.6 6.12 7.64 6.22 ;
			LAYER M1 ;
			RECT 1.04 5.86 7.64 6.12 ;
			LAYER M1 ;
			RECT 1.04 5.76 3.2 5.86 ;
			LAYER M1 ;
			RECT 1.04 5.2 1.8 5.76 ;
			LAYER M1 ;
			RECT 2.6 5.62 3.2 5.76 ;
			LAYER M1 ;
			RECT 7.04 5.62 7.64 5.86 ;
		END
	END sel
	PIN out
		DIRECTION output ;
		PORT
			LAYER M1 ;
			RECT 3.14 7.8 3.62 8.86 ;
			LAYER M1 ;
			RECT 6.66 7.8 7.14 8.86 ;
			LAYER M1 ;
			RECT 3.14 7.2 3.8 7.8 ;
			LAYER M1 ;
			RECT 6.2 7.2 7.14 7.8 ;
			LAYER M1 ;
			RECT 3.14 6.54 3.62 7.2 ;
			LAYER M1 ;
			RECT 6.66 6.54 7.14 7.2 ;
			LAYER M1 ;
			RECT 3.86 4.46 6.62 4.48 ;
			LAYER M1 ;
			RECT 3.52 4.12 6.62 4.46 ;
			LAYER M1 ;
			RECT 3.52 2.8 3.88 4.12 ;
			LAYER M1 ;
			RECT 6.26 2.8 6.62 4.12 ;
			LAYER M1 ;
			RECT 3.2 2.78 3.88 2.8 ;
			LAYER M1 ;
			RECT 3.14 2.46 3.88 2.78 ;
			LAYER M1 ;
			RECT 6.2 2.78 6.8 2.8 ;
			LAYER M1 ;
			RECT 3.14 2.2 3.8 2.46 ;
			LAYER M1 ;
			RECT 6.2 2.2 7.14 2.78 ;
			LAYER M1 ;
			RECT 3.14 1.66 3.62 2.2 ;
			LAYER M1 ;
			RECT 6.66 1.66 7.14 2.2 ;
			LAYER VIA1 ;
			RECT 3.32 7.32 3.68 7.68 ;
			LAYER VIA1 ;
			RECT 6.32 7.32 6.68 7.68 ;
			LAYER VIA1 ;
			RECT 3.32 2.32 3.68 2.68 ;
			LAYER VIA1 ;
			RECT 6.32 2.32 6.68 2.68 ;
			LAYER M2 ;
			RECT 3.2 7.2 3.8 7.8 ;
			LAYER M2 ;
			RECT 6.2 7.2 6.8 7.8 ;
			LAYER M2 ;
			RECT 3.3 2.8 3.7 7.2 ;
			LAYER M2 ;
			RECT 6.3 2.8 6.7 7.2 ;
			LAYER M2 ;
			RECT 3.2 2.2 3.8 2.8 ;
			LAYER M2 ;
			RECT 6.2 2.2 6.8 2.8 ;
		END
	END out
	PIN in1
		DIRECTION input ;
		PORT
			LAYER M1 ;
			RECT 4.2 3.2 4.96 3.8 ;
		END
	END in1
	PIN GND
		DIRECTION inout ;
		USE GROUND ;
		SHAPE ABUTMENT ;
		PORT
			LAYER M1 ;
			RECT 1.38 1.66 1.86 2.78 ;
			LAYER M1 ;
			RECT 4.9 1.66 5.38 2.78 ;
			LAYER M1 ;
			RECT 8.42 1.66 8.9 2.78 ;
			LAYER M1 ;
			RECT 1.44 0.7 1.8 1.66 ;
			LAYER M1 ;
			RECT 4.96 0.7 5.32 1.66 ;
			LAYER M1 ;
			RECT 8.48 0.7 8.84 1.66 ;
			LAYER M1 ;
			RECT 0 -0.7 10 0.7 ;
		END
	END GND
	PIN VDD
		DIRECTION inout ;
		USE POWER ;
		SHAPE ABUTMENT ;
		PORT
			LAYER M1 ;
			RECT 0 9.3 10 10.7 ;
			LAYER M1 ;
			RECT 1.44 8.86 1.78 9.3 ;
			LAYER M1 ;
			RECT 4.98 8.86 5.34 9.3 ;
			LAYER M1 ;
			RECT 8.48 8.86 8.84 9.3 ;
			LAYER M1 ;
			RECT 1.38 6.54 1.86 8.86 ;
			LAYER M1 ;
			RECT 4.9 6.54 5.38 8.86 ;
			LAYER M1 ;
			RECT 8.42 6.54 8.9 8.86 ;
		END
	END VDD
	PIN in0
		DIRECTION input ;
		PORT
			LAYER M1 ;
			RECT 1.2 4.2 2.24 4.8 ;
		END
	END in0
	OBS
		LAYER M1 ;
		RECT 0.38 6.96 0.86 8.86 ;
		LAYER M1 ;
		RECT 0.36 6.54 0.86 6.96 ;
		LAYER M1 ;
		RECT 0.36 3.68 0.72 6.54 ;
		LAYER M1 ;
		RECT 3.56 5.16 4.16 5.54 ;
		LAYER M1 ;
		RECT 6.08 5.16 6.68 5.54 ;
		LAYER M1 ;
		RECT 2.74 4.8 7.46 5.16 ;
		LAYER M1 ;
		RECT 2.74 3.8 3.1 4.8 ;
		LAYER M1 ;
		RECT 2.6 3.68 3.2 3.8 ;
		LAYER M1 ;
		RECT 0.36 3.32 3.2 3.68 ;
		LAYER M1 ;
		RECT 0.36 2.78 0.72 3.32 ;
		LAYER M1 ;
		RECT 2.6 3.2 3.2 3.32 ;
		LAYER M1 ;
		RECT 7.1 3.8 7.46 4.8 ;
		LAYER M1 ;
		RECT 6.98 3.2 7.58 3.8 ;
		LAYER M1 ;
		RECT 0.36 2.5 0.86 2.78 ;
		LAYER M1 ;
		RECT 0.38 1.66 0.86 2.5 ;
	END
END MMI_MUXI2B
MACRO MMI_MUXI2C
	CLASS CORE ;
	FOREIGN MMI_MUXI2C 0 0 ;
	SIZE 9 BY 10 ;
	SYMMETRY X Y ;
	SITE CORE1 ;
	PIN sel
		DIRECTION input ;
		PORT
			LAYER M1 ;
			RECT 2.6 6.12 3.2 6.2 ;
			LAYER M1 ;
			RECT 1.04 5.76 3.2 6.12 ;
			LAYER M1 ;
			RECT 1.04 5.2 1.8 5.76 ;
			LAYER M1 ;
			RECT 2.6 5.6 3.2 5.76 ;
		END
	END sel
	PIN out
		DIRECTION output ;
		PORT
			LAYER M1 ;
			RECT 5.9 6.54 6.38 8.86 ;
			LAYER M1 ;
			RECT 6 6.22 6.38 6.54 ;
			LAYER M1 ;
			RECT 6 5.86 6.8 6.22 ;
			LAYER M1 ;
			RECT 6.2 5.62 6.8 5.86 ;
			LAYER M1 ;
			RECT 6.2 3.36 6.8 3.62 ;
			LAYER M1 ;
			RECT 6.02 3.02 6.8 3.36 ;
			LAYER M1 ;
			RECT 6.02 2.7 6.38 3.02 ;
			LAYER M1 ;
			RECT 5.9 1.58 6.38 2.7 ;
			LAYER VIA1 ;
			RECT 6.32 5.74 6.68 6.1 ;
			LAYER VIA1 ;
			RECT 6.32 3.14 6.68 3.5 ;
			LAYER M2 ;
			RECT 6.2 5.62 6.8 6.22 ;
			LAYER M2 ;
			RECT 6.3 3.62 6.7 5.62 ;
			LAYER M2 ;
			RECT 6.2 3.02 6.8 3.62 ;
		END
	END out
	PIN in1
		DIRECTION input ;
		PORT
			LAYER M1 ;
			RECT 4.36 3.2 4.96 3.8 ;
		END
	END in1
	PIN GND
		DIRECTION inout ;
		USE GROUND ;
		SHAPE ABUTMENT ;
		PORT
			LAYER M1 ;
			RECT 1.38 1.58 1.86 2.7 ;
			LAYER M1 ;
			RECT 4.9 1.58 5.38 2.7 ;
			LAYER M1 ;
			RECT 6.9 1.58 7.38 2.7 ;
			LAYER M1 ;
			RECT 1.44 0.7 1.8 1.58 ;
			LAYER M1 ;
			RECT 4.96 0.7 5.32 1.58 ;
			LAYER M1 ;
			RECT 6.96 0.7 7.32 1.58 ;
			LAYER M1 ;
			RECT 0 -0.7 9 0.7 ;
		END
	END GND
	PIN VDD
		DIRECTION inout ;
		USE POWER ;
		SHAPE ABUTMENT ;
		PORT
			LAYER M1 ;
			RECT 0 9.3 9 10.7 ;
			LAYER M1 ;
			RECT 1.44 8.86 1.78 9.3 ;
			LAYER M1 ;
			RECT 4.98 8.86 5.34 9.3 ;
			LAYER M1 ;
			RECT 6.94 8.86 7.3 9.3 ;
			LAYER M1 ;
			RECT 1.38 6.54 1.86 8.86 ;
			LAYER M1 ;
			RECT 4.9 6.54 5.38 8.86 ;
			LAYER M1 ;
			RECT 6.9 6.54 7.38 8.86 ;
		END
	END VDD
	PIN in0
		DIRECTION input ;
		PORT
			LAYER M1 ;
			RECT 1.2 4.2 2.24 4.8 ;
		END
	END in0
	OBS
		LAYER M1 ;
		RECT 0.32 6.54 0.8 7.64 ;
		LAYER M1 ;
		RECT 3.14 6.9 3.62 8.86 ;
		LAYER M1 ;
		RECT 3.14 6.54 4 6.9 ;
		LAYER M1 ;
		RECT 7.9 6.54 8.38 8.86 ;
		LAYER M1 ;
		RECT 0.36 3.68 0.72 6.54 ;
		LAYER M1 ;
		RECT 3.64 6.22 4 6.54 ;
		LAYER M1 ;
		RECT 3.64 5.86 5.22 6.22 ;
		LAYER M1 ;
		RECT 3.56 5.16 4.16 5.54 ;
		LAYER M1 ;
		RECT 2.74 4.94 4.16 5.16 ;
		LAYER M1 ;
		RECT 4.86 5.22 5.22 5.86 ;
		LAYER M1 ;
		RECT 7 5.22 7.6 5.3 ;
		LAYER M1 ;
		RECT 2.74 4.8 4.04 4.94 ;
		LAYER M1 ;
		RECT 4.86 4.86 7.6 5.22 ;
		LAYER M1 ;
		RECT 2.74 3.8 3.1 4.8 ;
		LAYER M1 ;
		RECT 4.86 4.48 5.22 4.86 ;
		LAYER M1 ;
		RECT 7 4.7 7.6 4.86 ;
		LAYER M1 ;
		RECT 3.52 4.12 5.22 4.48 ;
		LAYER M1 ;
		RECT 5.94 4.38 6.54 4.54 ;
		LAYER M1 ;
		RECT 7.98 4.38 8.34 6.54 ;
		LAYER M1 ;
		RECT 2.6 3.68 3.2 3.8 ;
		LAYER M1 ;
		RECT 0.36 3.32 3.2 3.68 ;
		LAYER M1 ;
		RECT 0.36 2.7 0.72 3.32 ;
		LAYER M1 ;
		RECT 2.6 3.2 3.2 3.32 ;
		LAYER M1 ;
		RECT 3.52 2.7 3.88 4.12 ;
		LAYER M1 ;
		RECT 5.94 4.02 8.34 4.38 ;
		LAYER M1 ;
		RECT 5.94 3.94 6.54 4.02 ;
		LAYER M1 ;
		RECT 7.98 2.7 8.34 4.02 ;
		LAYER M1 ;
		RECT 0.32 2.18 0.8 2.7 ;
		LAYER M1 ;
		RECT 3.14 2.34 3.88 2.7 ;
		LAYER M1 ;
		RECT 3.14 1.58 3.62 2.34 ;
		LAYER M1 ;
		RECT 7.9 1.58 8.38 2.7 ;
	END
END MMI_MUXI2C
MACRO MMI_MUXI3B
	CLASS CORE ;
	FOREIGN MMI_MUXI3B 0 0 ;
	SIZE 14 BY 10 ;
	SYMMETRY X Y ;
	SITE CORE1 ;
	PIN out
		DIRECTION output ;
		PORT
			LAYER M1 ;
			RECT 11.22 7.16 11.7 8.88 ;
			LAYER M1 ;
			RECT 11.2 6.56 11.8 7.16 ;
			LAYER M1 ;
			RECT 11.2 1.62 11.8 2.22 ;
			LAYER M1 ;
			RECT 11.22 1.1 11.7 1.62 ;
			LAYER VIA1 ;
			RECT 11.32 6.68 11.68 7.04 ;
			LAYER VIA1 ;
			RECT 11.32 1.74 11.68 2.1 ;
			LAYER M2 ;
			RECT 11.2 6.56 11.8 7.16 ;
			LAYER M2 ;
			RECT 11.32 2.22 11.72 6.56 ;
			LAYER M2 ;
			RECT 11.2 1.62 11.8 2.22 ;
		END
	END out
	PIN in0
		DIRECTION input ;
		PORT
			LAYER M1 ;
			RECT 1.2 4.2 2.08 4.8 ;
		END
	END in0
	PIN in1
		DIRECTION input ;
		PORT
			LAYER M1 ;
			RECT 4.2 4.2 4.8 4.8 ;
		END
	END in1
	PIN GND
		DIRECTION inout ;
		USE GROUND ;
		SHAPE ABUTMENT ;
		PORT
			LAYER M1 ;
			RECT 1.26 1.1 1.74 2.22 ;
			LAYER M1 ;
			RECT 4.74 1.1 5.22 2.22 ;
			LAYER M1 ;
			RECT 6.74 1.1 7.22 2.22 ;
			LAYER M1 ;
			RECT 10.22 1.1 10.7 2.22 ;
			LAYER M1 ;
			RECT 12.22 1.1 12.7 2.22 ;
			LAYER M1 ;
			RECT 1.32 0.7 1.68 1.1 ;
			LAYER M1 ;
			RECT 4.8 0.7 5.16 1.1 ;
			LAYER M1 ;
			RECT 6.82 0.7 7.18 1.1 ;
			LAYER M1 ;
			RECT 10.26 0.7 10.64 1.1 ;
			LAYER M1 ;
			RECT 12.28 0.7 12.64 1.1 ;
			LAYER M1 ;
			RECT 0 -0.7 14 0.7 ;
		END
	END GND
	PIN in2
		DIRECTION input ;
		PORT
			LAYER M1 ;
			RECT 6.2 3.2 6.8 3.8 ;
		END
	END in2
	PIN sel0
		DIRECTION input ;
		PORT
			LAYER M1 ;
			RECT 0.9 5.88 3.18 6.24 ;
			LAYER M1 ;
			RECT 0.9 5.58 1.8 5.88 ;
			LAYER M1 ;
			RECT 2.58 5.64 3.18 5.88 ;
			LAYER M1 ;
			RECT 1.2 5.2 1.8 5.58 ;
		END
	END sel0
	PIN sel1
		DIRECTION input ;
		PORT
			LAYER M1 ;
			RECT 8.02 4.26 8.5 4.74 ;
			LAYER M1 ;
			RECT 8.02 2.92 8.38 4.26 ;
			LAYER M1 ;
			RECT 12.2 3.2 12.8 3.8 ;
			LAYER M1 ;
			RECT 8.8 2.92 9.28 3.02 ;
			LAYER M1 ;
			RECT 12.2 2.92 12.56 3.2 ;
			LAYER M1 ;
			RECT 8.02 2.56 12.56 2.92 ;
			LAYER M1 ;
			RECT 8.8 2.54 9.28 2.56 ;
		END
	END sel1
	PIN VDD
		DIRECTION inout ;
		USE POWER ;
		SHAPE ABUTMENT ;
		PORT
			LAYER M1 ;
			RECT 0 9.3 14 10.7 ;
			LAYER M1 ;
			RECT 1.26 8.88 1.62 9.3 ;
			LAYER M1 ;
			RECT 4.86 8.88 5.22 9.3 ;
			LAYER M1 ;
			RECT 6.86 8.88 7.22 9.3 ;
			LAYER M1 ;
			RECT 10.3 8.88 10.66 9.3 ;
			LAYER M1 ;
			RECT 12.28 8.88 12.64 9.3 ;
			LAYER M1 ;
			RECT 1.26 6.56 1.74 8.88 ;
			LAYER M1 ;
			RECT 4.74 6.56 5.22 8.88 ;
			LAYER M1 ;
			RECT 6.74 6.56 7.22 8.88 ;
			LAYER M1 ;
			RECT 10.22 6.56 10.7 8.88 ;
			LAYER M1 ;
			RECT 12.22 6.56 12.7 8.88 ;
		END
	END VDD
	OBS
		LAYER M1 ;
		RECT 0.26 6.56 0.74 8.88 ;
		LAYER M1 ;
		RECT 3 6.92 3.48 8.88 ;
		LAYER M1 ;
		RECT 3 6.56 3.86 6.92 ;
		LAYER M1 ;
		RECT 5.74 6.56 6.22 8.88 ;
		LAYER M1 ;
		RECT 8.48 7.16 8.96 8.88 ;
		LAYER M1 ;
		RECT 8.2 6.56 8.96 7.16 ;
		LAYER M1 ;
		RECT 13.22 6.56 13.7 8.88 ;
		LAYER M1 ;
		RECT 0.26 2.92 0.58 6.56 ;
		LAYER M1 ;
		RECT 3.52 5.48 3.86 6.56 ;
		LAYER M1 ;
		RECT 5.8 6.24 6.16 6.56 ;
		LAYER M1 ;
		RECT 5.8 5.88 7.5 6.24 ;
		LAYER M1 ;
		RECT 3.52 5.12 5.56 5.48 ;
		LAYER M1 ;
		RECT 3.22 4.54 3.82 4.8 ;
		LAYER M1 ;
		RECT 2.78 4.2 3.82 4.54 ;
		LAYER M1 ;
		RECT 5.22 4.68 5.56 5.12 ;
		LAYER M1 ;
		RECT 7.14 5.44 7.5 5.88 ;
		LAYER M1 ;
		RECT 8.54 6.2 8.9 6.56 ;
		LAYER M1 ;
		RECT 10.9 6.2 11.38 6.24 ;
		LAYER M1 ;
		RECT 8.54 5.84 11.38 6.2 ;
		LAYER M1 ;
		RECT 10.9 5.76 11.38 5.84 ;
		LAYER M1 ;
		RECT 9.94 5.44 10.42 5.46 ;
		LAYER M1 ;
		RECT 7.14 5.08 10.42 5.44 ;
		LAYER M1 ;
		RECT 6.2 4.68 6.8 4.8 ;
		LAYER M1 ;
		RECT 5.22 4.32 6.8 4.68 ;
		LAYER M1 ;
		RECT 2.78 3.06 3.12 4.2 ;
		LAYER M1 ;
		RECT 5.22 3.56 5.56 4.32 ;
		LAYER M1 ;
		RECT 6.2 4.2 6.8 4.32 ;
		LAYER M1 ;
		RECT 3.52 3.24 5.56 3.56 ;
		LAYER M1 ;
		RECT 2.66 2.92 3.14 3.06 ;
		LAYER M1 ;
		RECT 0.26 2.58 3.14 2.92 ;
		LAYER M1 ;
		RECT 0.26 2.56 3.12 2.58 ;
		LAYER M1 ;
		RECT 0.26 2.22 0.58 2.56 ;
		LAYER M1 ;
		RECT 3.52 2.22 3.88 3.24 ;
		LAYER M1 ;
		RECT 7.14 2.86 7.5 5.08 ;
		LAYER M1 ;
		RECT 9.94 4.98 10.42 5.08 ;
		LAYER M1 ;
		RECT 5.8 2.54 7.5 2.86 ;
		LAYER M1 ;
		RECT 8.98 4.64 9.46 4.74 ;
		LAYER M1 ;
		RECT 13.34 4.64 13.7 6.56 ;
		LAYER M1 ;
		RECT 8.98 4.28 13.7 4.64 ;
		LAYER M1 ;
		RECT 8.98 4.26 9.46 4.28 ;
		LAYER M1 ;
		RECT 5.8 2.22 6.16 2.54 ;
		LAYER M1 ;
		RECT 13.34 2.22 13.7 4.28 ;
		LAYER M1 ;
		RECT 0.26 1.1 0.74 2.22 ;
		LAYER M1 ;
		RECT 3 1.86 3.88 2.22 ;
		LAYER M1 ;
		RECT 3 1.1 3.48 1.86 ;
		LAYER M1 ;
		RECT 5.74 1.1 6.22 2.22 ;
		LAYER M1 ;
		RECT 8.2 1.62 8.96 2.22 ;
		LAYER M1 ;
		RECT 8.48 1.1 8.96 1.62 ;
		LAYER M1 ;
		RECT 13.22 1.1 13.7 2.22 ;
		LAYER M2 ;
		RECT 8.2 6.56 8.8 7.16 ;
		LAYER M2 ;
		RECT 8.32 2.22 8.72 6.56 ;
		LAYER M2 ;
		RECT 8.2 1.62 8.8 2.22 ;
	END
END MMI_MUXI3B
MACRO MMI_MUXI3C
	CLASS CORE ;
	FOREIGN MMI_MUXI3C 0 0 ;
	SIZE 14 BY 10 ;
	SYMMETRY X Y ;
	SITE CORE1 ;
	PIN out
		DIRECTION output ;
		PORT
			LAYER M1 ;
			RECT 11.22 7.16 11.7 8.88 ;
			LAYER M1 ;
			RECT 11.2 6.56 11.8 7.16 ;
			LAYER M1 ;
			RECT 11.2 1.62 11.8 2.22 ;
			LAYER M1 ;
			RECT 11.22 1.1 11.7 1.62 ;
			LAYER VIA1 ;
			RECT 11.32 6.68 11.68 7.04 ;
			LAYER VIA1 ;
			RECT 11.32 1.74 11.68 2.1 ;
			LAYER M2 ;
			RECT 11.2 6.56 11.8 7.16 ;
			LAYER M2 ;
			RECT 11.32 2.22 11.72 6.56 ;
			LAYER M2 ;
			RECT 11.2 1.62 11.8 2.22 ;
		END
	END out
	PIN in0
		DIRECTION input ;
		PORT
			LAYER M1 ;
			RECT 1.26 4.2 2.14 4.8 ;
		END
	END in0
	PIN in1
		DIRECTION input ;
		PORT
			LAYER M1 ;
			RECT 4.2 4.2 4.8 4.8 ;
		END
	END in1
	PIN GND
		DIRECTION inout ;
		USE GROUND ;
		SHAPE ABUTMENT ;
		PORT
			LAYER M1 ;
			RECT 1.26 1.1 1.74 2.22 ;
			LAYER M1 ;
			RECT 4.74 1.1 5.22 2.22 ;
			LAYER M1 ;
			RECT 6.74 1.1 7.22 2.22 ;
			LAYER M1 ;
			RECT 10.22 1.1 10.7 2.22 ;
			LAYER M1 ;
			RECT 12.22 1.1 12.7 2.22 ;
			LAYER M1 ;
			RECT 1.32 0.7 1.68 1.1 ;
			LAYER M1 ;
			RECT 4.8 0.7 5.16 1.1 ;
			LAYER M1 ;
			RECT 6.82 0.7 7.18 1.1 ;
			LAYER M1 ;
			RECT 10.26 0.7 10.64 1.1 ;
			LAYER M1 ;
			RECT 12.28 0.7 12.64 1.1 ;
			LAYER M1 ;
			RECT 0 -0.7 14 0.7 ;
		END
	END GND
	PIN in2
		DIRECTION input ;
		PORT
			LAYER M1 ;
			RECT 6.2 3.2 6.8 3.8 ;
		END
	END in2
	PIN sel0
		DIRECTION input ;
		PORT
			LAYER M1 ;
			RECT 0.9 5.88 3.18 6.24 ;
			LAYER M1 ;
			RECT 0.9 5.58 1.8 5.88 ;
			LAYER M1 ;
			RECT 2.58 5.64 3.18 5.88 ;
			LAYER M1 ;
			RECT 1.2 5.2 1.8 5.58 ;
		END
	END sel0
	PIN sel1
		DIRECTION input ;
		PORT
			LAYER M1 ;
			RECT 8.02 4.26 8.5 4.74 ;
			LAYER M1 ;
			RECT 8.02 2.92 8.38 4.26 ;
			LAYER M1 ;
			RECT 12.2 3.2 12.8 3.8 ;
			LAYER M1 ;
			RECT 8.8 2.92 9.28 3.02 ;
			LAYER M1 ;
			RECT 12.2 2.92 12.56 3.2 ;
			LAYER M1 ;
			RECT 8.02 2.56 12.56 2.92 ;
			LAYER M1 ;
			RECT 8.8 2.54 9.28 2.56 ;
		END
	END sel1
	PIN VDD
		DIRECTION inout ;
		USE POWER ;
		SHAPE ABUTMENT ;
		PORT
			LAYER M1 ;
			RECT 0 9.3 14 10.7 ;
			LAYER M1 ;
			RECT 1.26 8.88 1.62 9.3 ;
			LAYER M1 ;
			RECT 4.86 8.88 5.22 9.3 ;
			LAYER M1 ;
			RECT 6.86 8.88 7.22 9.3 ;
			LAYER M1 ;
			RECT 10.3 8.88 10.66 9.3 ;
			LAYER M1 ;
			RECT 12.28 8.88 12.64 9.3 ;
			LAYER M1 ;
			RECT 1.26 6.56 1.74 8.88 ;
			LAYER M1 ;
			RECT 4.74 6.56 5.22 8.88 ;
			LAYER M1 ;
			RECT 6.74 6.56 7.22 8.88 ;
			LAYER M1 ;
			RECT 10.22 6.56 10.7 8.88 ;
			LAYER M1 ;
			RECT 12.22 6.56 12.7 8.88 ;
		END
	END VDD
	OBS
		LAYER M1 ;
		RECT 0.26 6.56 0.74 8.88 ;
		LAYER M1 ;
		RECT 3 6.92 3.48 8.88 ;
		LAYER M1 ;
		RECT 3 6.56 3.86 6.92 ;
		LAYER M1 ;
		RECT 5.74 6.56 6.22 8.88 ;
		LAYER M1 ;
		RECT 8.48 7.16 8.96 8.88 ;
		LAYER M1 ;
		RECT 8.2 6.56 8.96 7.16 ;
		LAYER M1 ;
		RECT 13.22 6.56 13.7 8.88 ;
		LAYER M1 ;
		RECT 0.26 2.92 0.58 6.56 ;
		LAYER M1 ;
		RECT 3.52 5.48 3.86 6.56 ;
		LAYER M1 ;
		RECT 5.8 6.24 6.16 6.56 ;
		LAYER M1 ;
		RECT 5.8 5.88 7.5 6.24 ;
		LAYER M1 ;
		RECT 3.52 5.12 5.56 5.48 ;
		LAYER M1 ;
		RECT 3.22 4.54 3.82 4.8 ;
		LAYER M1 ;
		RECT 2.78 4.2 3.82 4.54 ;
		LAYER M1 ;
		RECT 5.22 4.68 5.56 5.12 ;
		LAYER M1 ;
		RECT 7.14 5.44 7.5 5.88 ;
		LAYER M1 ;
		RECT 8.54 6.2 8.9 6.56 ;
		LAYER M1 ;
		RECT 10.9 6.2 11.38 6.24 ;
		LAYER M1 ;
		RECT 8.54 5.84 11.38 6.2 ;
		LAYER M1 ;
		RECT 10.9 5.76 11.38 5.84 ;
		LAYER M1 ;
		RECT 9.94 5.44 10.42 5.46 ;
		LAYER M1 ;
		RECT 7.14 5.08 10.42 5.44 ;
		LAYER M1 ;
		RECT 6.2 4.68 6.8 4.8 ;
		LAYER M1 ;
		RECT 5.22 4.32 6.8 4.68 ;
		LAYER M1 ;
		RECT 2.78 3.06 3.12 4.2 ;
		LAYER M1 ;
		RECT 5.22 3.56 5.56 4.32 ;
		LAYER M1 ;
		RECT 6.2 4.2 6.8 4.32 ;
		LAYER M1 ;
		RECT 3.52 3.24 5.56 3.56 ;
		LAYER M1 ;
		RECT 2.66 2.92 3.14 3.06 ;
		LAYER M1 ;
		RECT 0.26 2.58 3.14 2.92 ;
		LAYER M1 ;
		RECT 0.26 2.56 3.12 2.58 ;
		LAYER M1 ;
		RECT 0.26 2.22 0.58 2.56 ;
		LAYER M1 ;
		RECT 3.52 2.22 3.88 3.24 ;
		LAYER M1 ;
		RECT 7.14 2.86 7.5 5.08 ;
		LAYER M1 ;
		RECT 9.94 4.98 10.42 5.08 ;
		LAYER M1 ;
		RECT 5.8 2.54 7.5 2.86 ;
		LAYER M1 ;
		RECT 8.98 4.64 9.46 4.74 ;
		LAYER M1 ;
		RECT 13.34 4.64 13.7 6.56 ;
		LAYER M1 ;
		RECT 8.98 4.28 13.7 4.64 ;
		LAYER M1 ;
		RECT 8.98 4.26 9.46 4.28 ;
		LAYER M1 ;
		RECT 5.8 2.22 6.16 2.54 ;
		LAYER M1 ;
		RECT 13.34 2.22 13.7 4.28 ;
		LAYER M1 ;
		RECT 0.26 1.1 0.74 2.22 ;
		LAYER M1 ;
		RECT 3 1.86 3.88 2.22 ;
		LAYER M1 ;
		RECT 3 1.1 3.48 1.86 ;
		LAYER M1 ;
		RECT 5.74 1.1 6.22 2.22 ;
		LAYER M1 ;
		RECT 8.2 1.62 8.96 2.22 ;
		LAYER M1 ;
		RECT 8.48 1.1 8.96 1.62 ;
		LAYER M1 ;
		RECT 13.22 1.1 13.7 2.22 ;
		LAYER M2 ;
		RECT 8.2 6.56 8.8 7.16 ;
		LAYER M2 ;
		RECT 8.32 2.22 8.72 6.56 ;
		LAYER M2 ;
		RECT 8.2 1.62 8.8 2.22 ;
	END
END MMI_MUXI3C
MACRO MMI_MUXI4B
	CLASS CORE ;
	FOREIGN MMI_MUXI4B 0 0 ;
	SIZE 16 BY 10 ;
	SYMMETRY X Y ;
	SITE CORE1 ;
	PIN out
		DIRECTION output ;
		PORT
			LAYER M1 ;
			RECT 12.72 7.18 13.2 8.88 ;
			LAYER M1 ;
			RECT 12.66 6.58 13.26 7.18 ;
			LAYER M1 ;
			RECT 12.72 6.56 13.2 6.58 ;
			LAYER M1 ;
			RECT 12.72 1.62 13.4 2.22 ;
			LAYER M1 ;
			RECT 12.72 1.1 13.2 1.62 ;
			LAYER VIA1 ;
			RECT 12.78 6.7 13.14 7.06 ;
			LAYER VIA1 ;
			RECT 12.92 1.74 13.28 2.1 ;
			LAYER M2 ;
			RECT 12.66 7.02 13.26 7.18 ;
			LAYER M2 ;
			RECT 12.66 6.58 13.4 7.02 ;
			LAYER M2 ;
			RECT 13 2.22 13.4 6.58 ;
			LAYER M2 ;
			RECT 12.8 1.62 13.4 2.22 ;
		END
	END out
	PIN in0
		DIRECTION input ;
		PORT
			LAYER M1 ;
			RECT 1.2 4.2 2.08 4.8 ;
		END
	END in0
	PIN in1
		DIRECTION input ;
		PORT
			LAYER M1 ;
			RECT 4.2 3.2 4.8 3.8 ;
		END
	END in1
	PIN GND
		DIRECTION inout ;
		USE GROUND ;
		SHAPE ABUTMENT ;
		PORT
			LAYER M1 ;
			RECT 1.26 1.1 1.74 2.22 ;
			LAYER M1 ;
			RECT 4.74 1.1 5.22 2.22 ;
			LAYER M1 ;
			RECT 8.24 1.1 8.72 2.22 ;
			LAYER M1 ;
			RECT 11.72 1.1 12.2 2.22 ;
			LAYER M1 ;
			RECT 13.72 1.1 14.2 2.22 ;
			LAYER M1 ;
			RECT 1.32 0.7 1.68 1.1 ;
			LAYER M1 ;
			RECT 4.8 0.7 5.16 1.1 ;
			LAYER M1 ;
			RECT 8.32 0.7 8.68 1.1 ;
			LAYER M1 ;
			RECT 11.76 0.7 12.14 1.1 ;
			LAYER M1 ;
			RECT 13.78 0.7 14.14 1.1 ;
			LAYER M1 ;
			RECT 0 -0.7 16 0.7 ;
		END
	END GND
	PIN in2
		DIRECTION input ;
		PORT
			LAYER M1 ;
			RECT 7.72 3.2 8.8 3.8 ;
		END
	END in2
	PIN in3
		DIRECTION input ;
		PORT
			LAYER M1 ;
			RECT 5.2 3.2 5.8 3.8 ;
		END
	END in3
	PIN sel0
		DIRECTION input ;
		PORT
			LAYER M1 ;
			RECT 0.9 5.88 7.32 6.24 ;
			LAYER M1 ;
			RECT 0.9 5.58 1.8 5.88 ;
			LAYER M1 ;
			RECT 2.58 5.64 3.18 5.88 ;
			LAYER M1 ;
			RECT 6.84 5.76 7.32 5.88 ;
			LAYER M1 ;
			RECT 1.2 5.22 1.8 5.58 ;
		END
	END sel0
	PIN sel1
		DIRECTION input ;
		PORT
			LAYER M1 ;
			RECT 10.34 5.88 14.56 6.24 ;
			LAYER M1 ;
			RECT 10.34 5.76 10.82 5.88 ;
			LAYER M1 ;
			RECT 14.2 4.8 14.56 5.88 ;
			LAYER M1 ;
			RECT 14.2 4.2 14.8 4.8 ;
		END
	END sel1
	PIN VDD
		DIRECTION inout ;
		USE POWER ;
		SHAPE ABUTMENT ;
		PORT
			LAYER M1 ;
			RECT 0 9.3 16 10.7 ;
			LAYER M1 ;
			RECT 1.26 8.88 1.62 9.3 ;
			LAYER M1 ;
			RECT 4.86 8.88 5.22 9.3 ;
			LAYER M1 ;
			RECT 8.36 8.88 8.72 9.3 ;
			LAYER M1 ;
			RECT 11.8 8.88 12.16 9.3 ;
			LAYER M1 ;
			RECT 13.78 8.88 14.14 9.3 ;
			LAYER M1 ;
			RECT 1.26 6.56 1.74 8.88 ;
			LAYER M1 ;
			RECT 4.74 6.56 5.22 8.88 ;
			LAYER M1 ;
			RECT 8.24 6.56 8.72 8.88 ;
			LAYER M1 ;
			RECT 11.72 6.56 12.2 8.88 ;
			LAYER M1 ;
			RECT 13.72 6.56 14.2 8.88 ;
		END
	END VDD
	OBS
		LAYER M1 ;
		RECT 0.26 6.56 0.74 8.88 ;
		LAYER M1 ;
		RECT 3 7.18 3.48 8.88 ;
		LAYER M1 ;
		RECT 3 6.58 3.8 7.18 ;
		LAYER M1 ;
		RECT 3 6.56 3.48 6.58 ;
		LAYER M1 ;
		RECT 6.5 7.16 6.98 8.88 ;
		LAYER M1 ;
		RECT 6.5 6.56 7.8 7.16 ;
		LAYER M1 ;
		RECT 9.98 7.16 10.46 8.88 ;
		LAYER M1 ;
		RECT 9.98 6.56 10.8 7.16 ;
		LAYER M1 ;
		RECT 14.72 6.92 15.2 8.88 ;
		LAYER M1 ;
		RECT 14.72 6.56 15.54 6.92 ;
		LAYER M1 ;
		RECT 0.26 2.92 0.58 6.56 ;
		LAYER M1 ;
		RECT 4.18 5.44 4.78 5.48 ;
		LAYER M1 ;
		RECT 4.18 5.22 11.56 5.44 ;
		LAYER M1 ;
		RECT 4.18 5.08 11.74 5.22 ;
		LAYER M1 ;
		RECT 4.18 4.88 4.78 5.08 ;
		LAYER M1 ;
		RECT 11.2 4.88 11.74 5.08 ;
		LAYER M1 ;
		RECT 3.26 4.56 3.86 4.78 ;
		LAYER M1 ;
		RECT 6.18 4.56 6.66 4.7 ;
		LAYER M1 ;
		RECT 3.04 4.22 6.66 4.56 ;
		LAYER M1 ;
		RECT 7.2 4.64 7.8 4.76 ;
		LAYER M1 ;
		RECT 8.5 4.64 9.1 4.76 ;
		LAYER M1 ;
		RECT 7.2 4.28 9.1 4.64 ;
		LAYER M1 ;
		RECT 3.04 4.18 3.86 4.22 ;
		LAYER M1 ;
		RECT 3.04 3.06 3.38 4.18 ;
		LAYER M1 ;
		RECT 2.66 2.92 3.38 3.06 ;
		LAYER M1 ;
		RECT 0.26 2.56 3.38 2.92 ;
		LAYER M1 ;
		RECT 6.16 2.92 6.5 4.22 ;
		LAYER M1 ;
		RECT 7.2 4.16 7.8 4.28 ;
		LAYER M1 ;
		RECT 8.5 4.16 9.1 4.28 ;
		LAYER M1 ;
		RECT 9.52 4.28 10 4.76 ;
		LAYER M1 ;
		RECT 11.26 4.74 11.74 4.88 ;
		LAYER M1 ;
		RECT 6.82 2.92 7.3 3.04 ;
		LAYER M1 ;
		RECT 6.16 2.56 7.3 2.92 ;
		LAYER M1 ;
		RECT 9.52 2.92 9.88 4.28 ;
		LAYER M1 ;
		RECT 10.2 3.82 10.8 3.94 ;
		LAYER M1 ;
		RECT 12 3.82 12.48 3.96 ;
		LAYER M1 ;
		RECT 10.2 3.48 12.48 3.82 ;
		LAYER M1 ;
		RECT 10.2 3.34 10.8 3.48 ;
		LAYER M1 ;
		RECT 10.3 2.92 10.78 3.02 ;
		LAYER M1 ;
		RECT 15.18 2.92 15.54 6.56 ;
		LAYER M1 ;
		RECT 9.52 2.56 15.54 2.92 ;
		LAYER M1 ;
		RECT 0.26 2.22 0.58 2.56 ;
		LAYER M1 ;
		RECT 10.3 2.54 10.78 2.56 ;
		LAYER M1 ;
		RECT 14.84 2.22 15.2 2.56 ;
		LAYER M1 ;
		RECT 0.26 1.1 0.74 2.22 ;
		LAYER M1 ;
		RECT 3 2.2 3.48 2.22 ;
		LAYER M1 ;
		RECT 3 1.6 3.8 2.2 ;
		LAYER M1 ;
		RECT 3 1.1 3.48 1.6 ;
		LAYER M1 ;
		RECT 6.5 1.62 7.8 2.22 ;
		LAYER M1 ;
		RECT 6.5 1.1 6.98 1.62 ;
		LAYER M1 ;
		RECT 9.98 2.2 10.46 2.22 ;
		LAYER M1 ;
		RECT 9.98 1.6 10.8 2.2 ;
		LAYER M1 ;
		RECT 9.98 1.1 10.46 1.6 ;
		LAYER M1 ;
		RECT 14.72 1.1 15.2 2.22 ;
		LAYER M2 ;
		RECT 3.2 6.58 3.8 7.18 ;
		LAYER M2 ;
		RECT 3.3 5.48 3.7 6.58 ;
		LAYER M2 ;
		RECT 7.2 6.56 7.8 7.16 ;
		LAYER M2 ;
		RECT 10.2 6.56 10.8 7.16 ;
		LAYER M2 ;
		RECT 3.3 5.08 4.78 5.48 ;
		LAYER M2 ;
		RECT 3.3 2.2 3.7 5.08 ;
		LAYER M2 ;
		RECT 4.18 4.88 4.78 5.08 ;
		LAYER M2 ;
		RECT 7.3 4.76 7.7 6.56 ;
		LAYER M2 ;
		RECT 7.2 4.16 7.8 4.76 ;
		LAYER M2 ;
		RECT 7.3 2.22 7.7 4.16 ;
		LAYER M2 ;
		RECT 10.3 3.94 10.7 6.56 ;
		LAYER M2 ;
		RECT 10.2 3.34 10.8 3.94 ;
		LAYER M2 ;
		RECT 3.2 1.6 3.8 2.2 ;
		LAYER M2 ;
		RECT 7.2 1.62 7.8 2.22 ;
		LAYER M2 ;
		RECT 10.3 2.2 10.7 3.34 ;
		LAYER M2 ;
		RECT 10.2 1.6 10.8 2.2 ;
	END
END MMI_MUXI4B
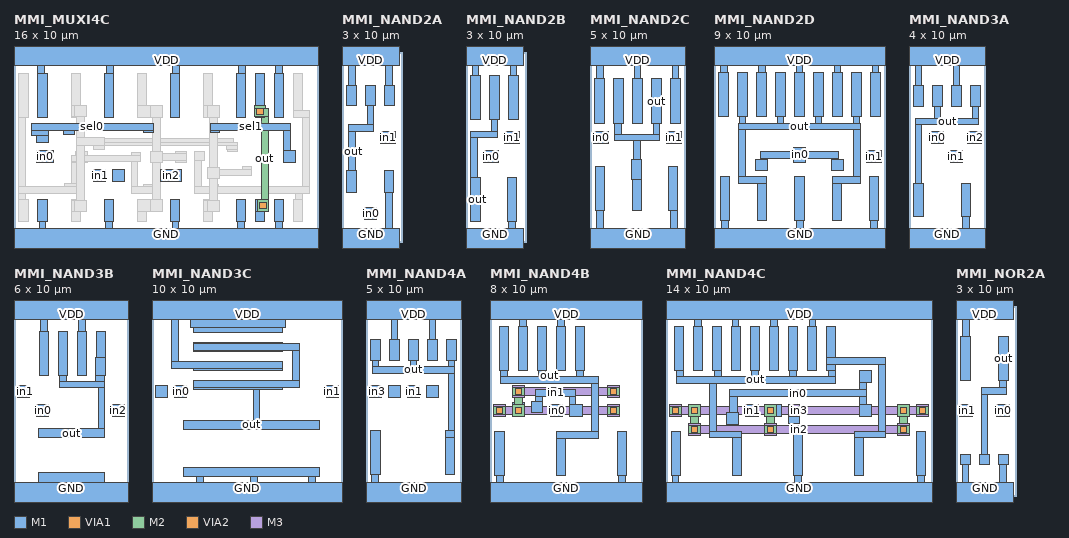
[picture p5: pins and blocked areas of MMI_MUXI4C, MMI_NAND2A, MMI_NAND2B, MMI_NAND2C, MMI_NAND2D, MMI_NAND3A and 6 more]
MACRO MMI_MUXI4C
	CLASS CORE ;
	FOREIGN MMI_MUXI4C 0 0 ;
	SIZE 16 BY 10 ;
	SYMMETRY X Y ;
	SITE CORE1 ;
	PIN out
		DIRECTION output ;
		PORT
			LAYER M1 ;
			RECT 12.72 7.18 13.2 8.88 ;
			LAYER M1 ;
			RECT 12.66 6.58 13.26 7.18 ;
			LAYER M1 ;
			RECT 12.72 6.56 13.2 6.58 ;
			LAYER M1 ;
			RECT 12.72 1.62 13.4 2.22 ;
			LAYER M1 ;
			RECT 12.72 1.1 13.2 1.62 ;
			LAYER VIA1 ;
			RECT 12.78 6.7 13.14 7.06 ;
			LAYER VIA1 ;
			RECT 12.92 1.74 13.28 2.1 ;
			LAYER M2 ;
			RECT 12.66 7.02 13.26 7.18 ;
			LAYER M2 ;
			RECT 12.66 6.58 13.4 7.02 ;
			LAYER M2 ;
			RECT 13 2.22 13.4 6.58 ;
			LAYER M2 ;
			RECT 12.8 1.62 13.4 2.22 ;
		END
	END out
	PIN in0
		DIRECTION input ;
		PORT
			LAYER M1 ;
			RECT 1.2 4.2 2.08 4.8 ;
		END
	END in0
	PIN in1
		DIRECTION input ;
		PORT
			LAYER M1 ;
			RECT 4.2 3.2 4.8 3.8 ;
		END
	END in1
	PIN GND
		DIRECTION inout ;
		USE GROUND ;
		SHAPE ABUTMENT ;
		PORT
			LAYER M1 ;
			RECT 1.26 1.1 1.74 2.22 ;
			LAYER M1 ;
			RECT 4.74 1.1 5.22 2.22 ;
			LAYER M1 ;
			RECT 8.24 1.1 8.72 2.22 ;
			LAYER M1 ;
			RECT 11.72 1.1 12.2 2.22 ;
			LAYER M1 ;
			RECT 13.72 1.1 14.2 2.22 ;
			LAYER M1 ;
			RECT 1.32 0.7 1.68 1.1 ;
			LAYER M1 ;
			RECT 4.8 0.7 5.16 1.1 ;
			LAYER M1 ;
			RECT 8.32 0.7 8.68 1.1 ;
			LAYER M1 ;
			RECT 11.76 0.7 12.14 1.1 ;
			LAYER M1 ;
			RECT 13.78 0.7 14.14 1.1 ;
			LAYER M1 ;
			RECT 0 -0.7 16 0.7 ;
		END
	END GND
	PIN in2
		DIRECTION input ;
		PORT
			LAYER M1 ;
			RECT 7.72 3.2 8.8 3.8 ;
		END
	END in2
	PIN in3
		DIRECTION input ;
		PORT
			LAYER M1 ;
			RECT 5.2 3.2 5.8 3.8 ;
		END
	END in3
	PIN sel0
		DIRECTION input ;
		PORT
			LAYER M1 ;
			RECT 0.9 5.88 7.32 6.24 ;
			LAYER M1 ;
			RECT 0.9 5.58 1.8 5.88 ;
			LAYER M1 ;
			RECT 2.58 5.64 3.18 5.88 ;
			LAYER M1 ;
			RECT 6.84 5.76 7.32 5.88 ;
			LAYER M1 ;
			RECT 1.2 5.22 1.8 5.58 ;
		END
	END sel0
	PIN sel1
		DIRECTION input ;
		PORT
			LAYER M1 ;
			RECT 10.34 5.88 14.56 6.24 ;
			LAYER M1 ;
			RECT 10.34 5.76 10.82 5.88 ;
			LAYER M1 ;
			RECT 14.2 4.8 14.56 5.88 ;
			LAYER M1 ;
			RECT 14.2 4.2 14.8 4.8 ;
		END
	END sel1
	PIN VDD
		DIRECTION inout ;
		USE POWER ;
		SHAPE ABUTMENT ;
		PORT
			LAYER M1 ;
			RECT 0 9.3 16 10.7 ;
			LAYER M1 ;
			RECT 1.26 8.88 1.62 9.3 ;
			LAYER M1 ;
			RECT 4.86 8.88 5.22 9.3 ;
			LAYER M1 ;
			RECT 8.36 8.88 8.72 9.3 ;
			LAYER M1 ;
			RECT 11.8 8.88 12.16 9.3 ;
			LAYER M1 ;
			RECT 13.78 8.88 14.14 9.3 ;
			LAYER M1 ;
			RECT 1.26 6.56 1.74 8.88 ;
			LAYER M1 ;
			RECT 4.74 6.56 5.22 8.88 ;
			LAYER M1 ;
			RECT 8.24 6.56 8.72 8.88 ;
			LAYER M1 ;
			RECT 11.72 6.56 12.2 8.88 ;
			LAYER M1 ;
			RECT 13.72 6.56 14.2 8.88 ;
		END
	END VDD
	OBS
		LAYER M1 ;
		RECT 0.26 6.56 0.74 8.88 ;
		LAYER M1 ;
		RECT 3 7.18 3.48 8.88 ;
		LAYER M1 ;
		RECT 3 6.58 3.8 7.18 ;
		LAYER M1 ;
		RECT 3 6.56 3.48 6.58 ;
		LAYER M1 ;
		RECT 6.5 7.16 6.98 8.88 ;
		LAYER M1 ;
		RECT 6.5 6.56 7.8 7.16 ;
		LAYER M1 ;
		RECT 9.98 7.16 10.46 8.88 ;
		LAYER M1 ;
		RECT 9.98 6.56 10.8 7.16 ;
		LAYER M1 ;
		RECT 14.72 6.92 15.2 8.88 ;
		LAYER M1 ;
		RECT 14.72 6.56 15.54 6.92 ;
		LAYER M1 ;
		RECT 0.26 2.92 0.58 6.56 ;
		LAYER M1 ;
		RECT 4.18 5.44 4.78 5.48 ;
		LAYER M1 ;
		RECT 4.18 5.22 11.56 5.44 ;
		LAYER M1 ;
		RECT 4.18 5.08 11.74 5.22 ;
		LAYER M1 ;
		RECT 4.18 4.88 4.78 5.08 ;
		LAYER M1 ;
		RECT 11.2 4.88 11.74 5.08 ;
		LAYER M1 ;
		RECT 3.26 4.56 3.86 4.78 ;
		LAYER M1 ;
		RECT 6.18 4.56 6.66 4.7 ;
		LAYER M1 ;
		RECT 3.04 4.22 6.66 4.56 ;
		LAYER M1 ;
		RECT 7.2 4.64 7.8 4.76 ;
		LAYER M1 ;
		RECT 8.5 4.64 9.1 4.76 ;
		LAYER M1 ;
		RECT 7.2 4.28 9.1 4.64 ;
		LAYER M1 ;
		RECT 3.04 4.18 3.86 4.22 ;
		LAYER M1 ;
		RECT 3.04 3.06 3.38 4.18 ;
		LAYER M1 ;
		RECT 2.66 2.92 3.38 3.06 ;
		LAYER M1 ;
		RECT 0.26 2.56 3.38 2.92 ;
		LAYER M1 ;
		RECT 6.16 2.92 6.5 4.22 ;
		LAYER M1 ;
		RECT 7.2 4.16 7.8 4.28 ;
		LAYER M1 ;
		RECT 8.5 4.16 9.1 4.28 ;
		LAYER M1 ;
		RECT 9.52 4.28 10 4.76 ;
		LAYER M1 ;
		RECT 11.26 4.74 11.74 4.88 ;
		LAYER M1 ;
		RECT 6.82 2.92 7.3 3.04 ;
		LAYER M1 ;
		RECT 6.16 2.56 7.3 2.92 ;
		LAYER M1 ;
		RECT 9.52 2.92 9.88 4.28 ;
		LAYER M1 ;
		RECT 10.2 3.82 10.8 3.94 ;
		LAYER M1 ;
		RECT 12 3.82 12.48 3.96 ;
		LAYER M1 ;
		RECT 10.2 3.48 12.48 3.82 ;
		LAYER M1 ;
		RECT 10.2 3.34 10.8 3.48 ;
		LAYER M1 ;
		RECT 10.3 2.92 10.78 3.02 ;
		LAYER M1 ;
		RECT 15.18 2.92 15.54 6.56 ;
		LAYER M1 ;
		RECT 9.52 2.56 15.54 2.92 ;
		LAYER M1 ;
		RECT 0.26 2.22 0.58 2.56 ;
		LAYER M1 ;
		RECT 10.3 2.54 10.78 2.56 ;
		LAYER M1 ;
		RECT 14.84 2.22 15.2 2.56 ;
		LAYER M1 ;
		RECT 0.26 1.1 0.74 2.22 ;
		LAYER M1 ;
		RECT 3 2.2 3.48 2.22 ;
		LAYER M1 ;
		RECT 3 1.6 3.8 2.2 ;
		LAYER M1 ;
		RECT 3 1.1 3.48 1.6 ;
		LAYER M1 ;
		RECT 6.5 1.62 7.8 2.22 ;
		LAYER M1 ;
		RECT 6.5 1.1 6.98 1.62 ;
		LAYER M1 ;
		RECT 9.98 2.2 10.46 2.22 ;
		LAYER M1 ;
		RECT 9.98 1.6 10.8 2.2 ;
		LAYER M1 ;
		RECT 9.98 1.1 10.46 1.6 ;
		LAYER M1 ;
		RECT 14.72 1.1 15.2 2.22 ;
		LAYER M2 ;
		RECT 3.2 6.58 3.8 7.18 ;
		LAYER M2 ;
		RECT 3.3 5.48 3.7 6.58 ;
		LAYER M2 ;
		RECT 7.2 6.56 7.8 7.16 ;
		LAYER M2 ;
		RECT 10.2 6.56 10.8 7.16 ;
		LAYER M2 ;
		RECT 3.3 5.08 4.78 5.48 ;
		LAYER M2 ;
		RECT 3.3 2.2 3.7 5.08 ;
		LAYER M2 ;
		RECT 4.18 4.88 4.78 5.08 ;
		LAYER M2 ;
		RECT 7.3 4.76 7.7 6.56 ;
		LAYER M2 ;
		RECT 7.2 4.16 7.8 4.76 ;
		LAYER M2 ;
		RECT 7.3 2.22 7.7 4.16 ;
		LAYER M2 ;
		RECT 10.3 3.94 10.7 6.56 ;
		LAYER M2 ;
		RECT 10.2 3.34 10.8 3.94 ;
		LAYER M2 ;
		RECT 3.2 1.6 3.8 2.2 ;
		LAYER M2 ;
		RECT 7.2 1.62 7.8 2.22 ;
		LAYER M2 ;
		RECT 10.3 2.2 10.7 3.34 ;
		LAYER M2 ;
		RECT 10.2 1.6 10.8 2.2 ;
	END
END MMI_MUXI4C
MACRO MMI_NAND2A
	CLASS CORE ;
	FOREIGN MMI_NAND2A 0 0 ;
	SIZE 3 BY 10 ;
	SYMMETRY X Y ;
	SITE CORE1 ;
	PIN in1
		DIRECTION input ;
		PORT
			LAYER M1 ;
			RECT 2.02 5.2 2.8 5.8 ;
		END
	END in1
	PIN out
		DIRECTION output ;
		PORT
			LAYER M1 ;
			RECT 1.26 7.16 1.74 8.26 ;
			LAYER M1 ;
			RECT 1.32 6.16 1.66 7.16 ;
			LAYER M1 ;
			RECT 0.34 5.82 1.66 6.16 ;
			LAYER M1 ;
			RECT 0.34 3.74 0.7 5.82 ;
			LAYER M1 ;
			RECT 0.26 2.62 0.74 3.74 ;
		END
	END out
	PIN GND
		DIRECTION inout ;
		USE GROUND ;
		SHAPE ABUTMENT ;
		PORT
			LAYER M1 ;
			RECT 2.22 2.62 2.7 3.74 ;
			LAYER M1 ;
			RECT 2.28 0.7 2.64 2.62 ;
			LAYER M1 ;
			RECT 0 -0.7 3 0.7 ;
		END
	END GND
	PIN VDD
		DIRECTION inout ;
		USE POWER ;
		SHAPE ABUTMENT ;
		PORT
			LAYER M1 ;
			RECT 0 9.3 3 10.7 ;
			LAYER M1 ;
			RECT 0.34 8.26 0.7 9.3 ;
			LAYER M1 ;
			RECT 2.28 8.26 2.64 9.3 ;
			LAYER M1 ;
			RECT 0.26 7.16 0.74 8.26 ;
			LAYER M1 ;
			RECT 2.26 7.16 2.74 8.26 ;
		END
	END VDD
	PIN in0
		DIRECTION input ;
		PORT
			LAYER M1 ;
			RECT 1.2 1.2 1.8 1.8 ;
		END
	END in0
	OBS
	END
END MMI_NAND2A
MACRO MMI_NAND2B
	CLASS CORE ;
	FOREIGN MMI_NAND2B 0 0 ;
	SIZE 3 BY 10 ;
	SYMMETRY X Y ;
	SITE CORE1 ;
	PIN out
		DIRECTION output ;
		PORT
			LAYER M1 ;
			RECT 1.26 6.46 1.74 8.78 ;
			LAYER M1 ;
			RECT 1.32 5.84 1.68 6.46 ;
			LAYER M1 ;
			RECT 0.26 5.48 1.68 5.84 ;
			LAYER M1 ;
			RECT 0.26 3.42 0.62 5.48 ;
			LAYER M1 ;
			RECT 0.26 1.1 0.74 3.42 ;
		END
	END out
	PIN in1
		DIRECTION input ;
		PORT
			LAYER M1 ;
			RECT 2 5.2 2.8 5.8 ;
		END
	END in1
	PIN GND
		DIRECTION inout ;
		USE GROUND ;
		SHAPE ABUTMENT ;
		PORT
			LAYER M1 ;
			RECT 2.2 1.1 2.68 3.42 ;
			LAYER M1 ;
			RECT 2.26 0.7 2.62 1.1 ;
			LAYER M1 ;
			RECT 0 -0.7 3 0.7 ;
		END
	END GND
	PIN VDD
		DIRECTION inout ;
		USE POWER ;
		SHAPE ABUTMENT ;
		PORT
			LAYER M1 ;
			RECT 0 9.3 3 10.7 ;
			LAYER M1 ;
			RECT 0.32 8.78 0.68 9.3 ;
			LAYER M1 ;
			RECT 2.32 8.78 2.68 9.3 ;
			LAYER M1 ;
			RECT 0.26 6.46 0.74 8.78 ;
			LAYER M1 ;
			RECT 2.26 6.46 2.74 8.78 ;
		END
	END VDD
	PIN in0
		DIRECTION input ;
		PORT
			LAYER M1 ;
			RECT 0.94 4.2 1.72 4.8 ;
		END
	END in0
	OBS
	END
END MMI_NAND2B
MACRO MMI_NAND2C
	CLASS CORE ;
	FOREIGN MMI_NAND2C 0 0 ;
	SIZE 5 BY 10 ;
	SYMMETRY X Y ;
	SITE CORE1 ;
	PIN in1
		DIRECTION input ;
		PORT
			LAYER M1 ;
			RECT 4 5.2 4.8 5.8 ;
		END
	END in1
	PIN out
		DIRECTION output ;
		PORT
			LAYER M1 ;
			RECT 1.26 6.26 1.74 8.58 ;
			LAYER M1 ;
			RECT 3.26 6.26 3.74 8.58 ;
			LAYER M1 ;
			RECT 1.3 5.66 1.66 6.26 ;
			LAYER M1 ;
			RECT 3.32 5.66 3.68 6.26 ;
			LAYER M1 ;
			RECT 1.3 5.32 3.68 5.66 ;
			LAYER M1 ;
			RECT 2.28 4.32 2.64 5.32 ;
			LAYER M1 ;
			RECT 2.2 3.28 2.7 4.32 ;
			LAYER M1 ;
			RECT 2.22 1.66 2.7 3.28 ;
		END
	END out
	PIN GND
		DIRECTION inout ;
		USE GROUND ;
		SHAPE ABUTMENT ;
		PORT
			LAYER M1 ;
			RECT 0.3 1.66 0.78 3.98 ;
			LAYER M1 ;
			RECT 4.14 1.66 4.62 3.98 ;
			LAYER M1 ;
			RECT 0.36 0.7 0.7 1.66 ;
			LAYER M1 ;
			RECT 4.22 0.7 4.58 1.66 ;
			LAYER M1 ;
			RECT 0 -0.7 5 0.7 ;
		END
	END GND
	PIN VDD
		DIRECTION inout ;
		USE POWER ;
		SHAPE ABUTMENT ;
		PORT
			LAYER M1 ;
			RECT 0 9.3 5 10.7 ;
			LAYER M1 ;
			RECT 0.34 8.58 0.7 9.3 ;
			LAYER M1 ;
			RECT 2.32 8.58 2.68 9.3 ;
			LAYER M1 ;
			RECT 4.32 8.58 4.68 9.3 ;
			LAYER M1 ;
			RECT 0.26 6.26 0.74 8.58 ;
			LAYER M1 ;
			RECT 2.26 6.26 2.74 8.58 ;
			LAYER M1 ;
			RECT 4.26 6.26 4.74 8.58 ;
		END
	END VDD
	PIN in0
		DIRECTION input ;
		PORT
			LAYER M1 ;
			RECT 0.2 5.2 0.98 5.8 ;
		END
	END in0
	OBS
	END
END MMI_NAND2C
MACRO MMI_NAND2D
	CLASS CORE ;
	FOREIGN MMI_NAND2D 0 0 ;
	SIZE 9 BY 10 ;
	SYMMETRY X Y ;
	SITE CORE1 ;
	PIN in1
		DIRECTION input ;
		PORT
			LAYER M1 ;
			RECT 8.04 4.2 8.8 4.8 ;
		END
	END in1
	PIN out
		DIRECTION output ;
		PORT
			LAYER M1 ;
			RECT 1.26 6.58 1.74 8.9 ;
			LAYER M1 ;
			RECT 3.26 6.58 3.74 8.9 ;
			LAYER M1 ;
			RECT 5.26 6.58 5.74 8.9 ;
			LAYER M1 ;
			RECT 7.26 6.58 7.74 8.9 ;
			LAYER M1 ;
			RECT 1.32 6.26 1.68 6.58 ;
			LAYER M1 ;
			RECT 3.32 6.26 3.68 6.58 ;
			LAYER M1 ;
			RECT 5.32 6.26 5.68 6.58 ;
			LAYER M1 ;
			RECT 7.32 6.26 7.68 6.58 ;
			LAYER M1 ;
			RECT 1.28 5.9 7.72 6.26 ;
			LAYER M1 ;
			RECT 1.28 3.44 1.64 5.9 ;
			LAYER M1 ;
			RECT 7.36 3.44 7.72 5.9 ;
			LAYER M1 ;
			RECT 1.28 3.08 2.78 3.44 ;
			LAYER M1 ;
			RECT 2.3 1.12 2.78 3.08 ;
			LAYER M1 ;
			RECT 6.22 3.08 7.72 3.44 ;
			LAYER M1 ;
			RECT 6.22 1.12 6.7 3.08 ;
		END
	END out
	PIN GND
		DIRECTION inout ;
		USE GROUND ;
		SHAPE ABUTMENT ;
		PORT
			LAYER M1 ;
			RECT 0.34 1.12 0.82 3.44 ;
			LAYER M1 ;
			RECT 4.26 1.12 4.74 3.44 ;
			LAYER M1 ;
			RECT 8.18 1.12 8.66 3.44 ;
			LAYER M1 ;
			RECT 0.42 0.7 0.76 1.12 ;
			LAYER M1 ;
			RECT 4.34 0.7 4.7 1.12 ;
			LAYER M1 ;
			RECT 8.24 0.7 8.6 1.12 ;
			LAYER M1 ;
			RECT 0 -0.7 9 0.7 ;
		END
	END GND
	PIN VDD
		DIRECTION inout ;
		USE POWER ;
		SHAPE ABUTMENT ;
		PORT
			LAYER M1 ;
			RECT 0 9.3 9 10.7 ;
			LAYER M1 ;
			RECT 0.34 8.9 0.7 9.3 ;
			LAYER M1 ;
			RECT 2.34 8.9 2.7 9.3 ;
			LAYER M1 ;
			RECT 4.32 8.9 4.68 9.3 ;
			LAYER M1 ;
			RECT 6.32 8.9 6.66 9.3 ;
			LAYER M1 ;
			RECT 8.32 8.9 8.68 9.3 ;
			LAYER M1 ;
			RECT 0.26 6.58 0.74 8.9 ;
			LAYER M1 ;
			RECT 2.26 6.58 2.74 8.9 ;
			LAYER M1 ;
			RECT 4.26 6.58 4.74 8.9 ;
			LAYER M1 ;
			RECT 6.26 6.58 6.74 8.9 ;
			LAYER M1 ;
			RECT 8.26 6.58 8.74 8.9 ;
		END
	END VDD
	PIN in0
		DIRECTION input ;
		PORT
			LAYER M1 ;
			RECT 4.2 4.76 4.8 5 ;
			LAYER M1 ;
			RECT 2.44 4.4 6.56 4.76 ;
			LAYER M1 ;
			RECT 2.44 4.36 2.8 4.4 ;
			LAYER M1 ;
			RECT 2.2 3.76 2.8 4.36 ;
			LAYER M1 ;
			RECT 4.2 4.2 4.8 4.4 ;
			LAYER M1 ;
			RECT 6.2 4.36 6.56 4.4 ;
			LAYER M1 ;
			RECT 6.2 3.76 6.8 4.36 ;
		END
	END in0
	OBS
	END
END MMI_NAND2D
MACRO MMI_NAND3A
	CLASS CORE ;
	FOREIGN MMI_NAND3A 0 0 ;
	SIZE 4 BY 10 ;
	SYMMETRY X Y ;
	SITE CORE1 ;
	PIN out
		DIRECTION output ;
		PORT
			LAYER M1 ;
			RECT 1.26 7.14 1.74 8.24 ;
			LAYER M1 ;
			RECT 3.26 7.14 3.74 8.24 ;
			LAYER M1 ;
			RECT 1.32 6.52 1.68 7.14 ;
			LAYER M1 ;
			RECT 3.32 6.52 3.68 7.14 ;
			LAYER M1 ;
			RECT 0.32 6.16 3.68 6.52 ;
			LAYER M1 ;
			RECT 0.32 3.08 0.68 6.16 ;
			LAYER M1 ;
			RECT 0.26 1.36 0.74 3.08 ;
		END
	END out
	PIN in1
		DIRECTION input ;
		PORT
			LAYER M1 ;
			RECT 2.16 4.2 2.8 4.8 ;
		END
	END in1
	PIN in2
		DIRECTION input ;
		PORT
			LAYER M1 ;
			RECT 3.1 5.2 3.8 5.8 ;
		END
	END in2
	PIN GND
		DIRECTION inout ;
		USE GROUND ;
		SHAPE ABUTMENT ;
		PORT
			LAYER M1 ;
			RECT 2.74 1.36 3.22 3.08 ;
			LAYER M1 ;
			RECT 2.8 0.7 3.16 1.36 ;
			LAYER M1 ;
			RECT 0 -0.7 4 0.7 ;
		END
	END GND
	PIN VDD
		DIRECTION inout ;
		USE POWER ;
		SHAPE ABUTMENT ;
		PORT
			LAYER M1 ;
			RECT 0 9.3 4 10.7 ;
			LAYER M1 ;
			RECT 0.32 8.24 0.68 9.3 ;
			LAYER M1 ;
			RECT 2.32 8.24 2.68 9.3 ;
			LAYER M1 ;
			RECT 0.26 7.14 0.74 8.24 ;
			LAYER M1 ;
			RECT 2.26 7.14 2.74 8.24 ;
		END
	END VDD
	PIN in0
		DIRECTION input ;
		PORT
			LAYER M1 ;
			RECT 1.16 5.2 1.8 5.8 ;
		END
	END in0
	OBS
	END
END MMI_NAND3A
MACRO MMI_NAND3B
	CLASS CORE ;
	FOREIGN MMI_NAND3B 0 0 ;
	SIZE 6 BY 10 ;
	SYMMETRY X Y ;
	SITE CORE1 ;
	PIN in1
		DIRECTION input ;
		PORT
			LAYER M1 ;
			RECT 0.2 5.2 0.8 5.8 ;
		END
	END in1
	PIN out
		DIRECTION output ;
		PORT
			LAYER M1 ;
			RECT 2.32 6.36 2.8 8.68 ;
			LAYER M1 ;
			RECT 4.32 7.28 4.8 8.68 ;
			LAYER M1 ;
			RECT 4.28 6.36 4.8 7.28 ;
			LAYER M1 ;
			RECT 2.42 6.02 2.78 6.36 ;
			LAYER M1 ;
			RECT 4.28 6.02 4.78 6.36 ;
			LAYER M1 ;
			RECT 2.42 5.7 4.78 6.02 ;
			LAYER M1 ;
			RECT 4.44 3.54 4.78 5.7 ;
			LAYER M1 ;
			RECT 1.3 3.06 4.78 3.54 ;
		END
	END out
	PIN in2
		DIRECTION input ;
		PORT
			LAYER M1 ;
			RECT 5.2 4.2 5.8 4.8 ;
		END
	END in2
	PIN GND
		DIRECTION inout ;
		USE GROUND ;
		SHAPE ABUTMENT ;
		PORT
			LAYER M1 ;
			RECT 1.3 0.7 4.78 1.26 ;
			LAYER M1 ;
			RECT 0 -0.7 6 0.7 ;
		END
	END GND
	PIN VDD
		DIRECTION inout ;
		USE POWER ;
		SHAPE ABUTMENT ;
		PORT
			LAYER M1 ;
			RECT 0 9.3 6 10.7 ;
			LAYER M1 ;
			RECT 1.42 8.68 1.78 9.3 ;
			LAYER M1 ;
			RECT 3.42 8.68 3.78 9.3 ;
			LAYER M1 ;
			RECT 1.32 6.36 1.8 8.68 ;
			LAYER M1 ;
			RECT 3.32 6.36 3.8 8.68 ;
		END
	END VDD
	PIN in0
		DIRECTION input ;
		PORT
			LAYER M1 ;
			RECT 1.2 4.2 1.8 4.8 ;
		END
	END in0
	OBS
	END
END MMI_NAND3B
MACRO MMI_NAND3C
	CLASS CORE ;
	FOREIGN MMI_NAND3C 0 0 ;
	SIZE 10 BY 10 ;
	SYMMETRY X Y ;
	SITE CORE1 ;
	PIN out
		DIRECTION output ;
		PORT
			LAYER M1 ;
			RECT 2.16 8.02 6.88 8.1 ;
			LAYER M1 ;
			RECT 2.16 7.66 7.74 8.02 ;
			LAYER M1 ;
			RECT 2.16 7.62 6.88 7.66 ;
			LAYER M1 ;
			RECT 2.16 6.06 6.88 6.1 ;
			LAYER M1 ;
			RECT 7.38 6.06 7.74 7.66 ;
			LAYER M1 ;
			RECT 2.16 5.7 7.74 6.06 ;
			LAYER M1 ;
			RECT 2.16 5.62 6.88 5.7 ;
			LAYER M1 ;
			RECT 5.32 4 5.66 5.62 ;
			LAYER M1 ;
			RECT 1.68 3.52 8.8 4 ;
		END
	END out
	PIN in1
		DIRECTION input ;
		PORT
			LAYER M1 ;
			RECT 9.2 5.2 9.8 5.8 ;
		END
	END in1
	PIN GND
		DIRECTION inout ;
		USE GROUND ;
		SHAPE ABUTMENT ;
		PORT
			LAYER M1 ;
			RECT 1.68 1.04 8.8 1.52 ;
			LAYER M1 ;
			RECT 2.34 0.7 2.7 1.04 ;
			LAYER M1 ;
			RECT 5.2 0.7 5.56 1.04 ;
			LAYER M1 ;
			RECT 8.24 0.7 8.6 1.04 ;
			LAYER M1 ;
			RECT 0 -0.7 10 0.7 ;
		END
	END GND
	PIN in2
		DIRECTION input ;
		PORT
			LAYER M1 ;
			RECT 0.2 5.2 0.8 5.8 ;
		END
	END in2
	PIN VDD
		DIRECTION inout ;
		USE POWER ;
		SHAPE ABUTMENT ;
		PORT
			LAYER M1 ;
			RECT 0 9.3 10 10.7 ;
			LAYER M1 ;
			RECT 1.02 7.06 1.38 9.3 ;
			LAYER M1 ;
			RECT 2.02 8.88 7.02 9.3 ;
			LAYER M1 ;
			RECT 2.16 8.62 6.88 8.88 ;
			LAYER M1 ;
			RECT 2.16 7.06 6.88 7.1 ;
			LAYER M1 ;
			RECT 1.02 6.7 6.88 7.06 ;
			LAYER M1 ;
			RECT 2.16 6.62 6.88 6.7 ;
		END
	END VDD
	PIN in0
		DIRECTION input ;
		PORT
			LAYER M1 ;
			RECT 1.2 5.2 1.8 5.8 ;
		END
	END in0
	OBS
	END
END MMI_NAND3C
MACRO MMI_NAND4A
	CLASS CORE ;
	FOREIGN MMI_NAND4A 0 0 ;
	SIZE 5 BY 10 ;
	SYMMETRY X Y ;
	SITE CORE1 ;
	PIN in1
		DIRECTION input ;
		PORT
			LAYER M1 ;
			RECT 2.2 5.2 2.8 5.8 ;
		END
	END in1
	PIN out
		DIRECTION output ;
		PORT
			LAYER M1 ;
			RECT 0.26 7.14 0.74 8.24 ;
			LAYER M1 ;
			RECT 2.26 7.14 2.74 8.24 ;
			LAYER M1 ;
			RECT 4.26 7.14 4.74 8.24 ;
			LAYER M1 ;
			RECT 0.32 6.82 0.68 7.14 ;
			LAYER M1 ;
			RECT 2.32 6.82 2.68 7.14 ;
			LAYER M1 ;
			RECT 4.32 6.82 4.68 7.14 ;
			LAYER M1 ;
			RECT 0.32 6.46 4.68 6.82 ;
			LAYER M1 ;
			RECT 4.32 3.44 4.68 6.46 ;
			LAYER M1 ;
			RECT 4.16 3.06 4.68 3.44 ;
			LAYER M1 ;
			RECT 4.16 1.12 4.64 3.06 ;
		END
	END out
	PIN in2
		DIRECTION input ;
		PORT
			LAYER M1 ;
			RECT 1.2 5.2 1.8 5.8 ;
		END
	END in2
	PIN GND
		DIRECTION inout ;
		USE GROUND ;
		SHAPE ABUTMENT ;
		PORT
			LAYER M1 ;
			RECT 0.26 1.12 0.74 3.44 ;
			LAYER M1 ;
			RECT 0.28 0.7 0.64 1.12 ;
			LAYER M1 ;
			RECT 0 -0.7 5 0.7 ;
		END
	END GND
	PIN VDD
		DIRECTION inout ;
		USE POWER ;
		SHAPE ABUTMENT ;
		PORT
			LAYER M1 ;
			RECT 0 9.3 5 10.7 ;
			LAYER M1 ;
			RECT 1.32 8.24 1.66 9.3 ;
			LAYER M1 ;
			RECT 3.32 8.24 3.68 9.3 ;
			LAYER M1 ;
			RECT 1.26 7.14 1.74 8.24 ;
			LAYER M1 ;
			RECT 3.26 7.14 3.74 8.24 ;
		END
	END VDD
	PIN in3
		DIRECTION input ;
		PORT
			LAYER M1 ;
			RECT 0.2 5.2 0.8 5.8 ;
		END
	END in3
	PIN in0
		DIRECTION input ;
		PORT
			LAYER M1 ;
			RECT 3.2 5.2 3.82 5.8 ;
		END
	END in0
	OBS
	END
END MMI_NAND4A
MACRO MMI_NAND4B
	CLASS CORE ;
	FOREIGN MMI_NAND4B 0 0 ;
	SIZE 8 BY 10 ;
	SYMMETRY X Y ;
	SITE CORE1 ;
	PIN out
		DIRECTION output ;
		PORT
			LAYER M1 ;
			RECT 0.48 6.62 0.96 8.94 ;
			LAYER M1 ;
			RECT 2.48 6.62 2.96 8.94 ;
			LAYER M1 ;
			RECT 4.48 6.62 4.96 8.94 ;
			LAYER M1 ;
			RECT 0.56 6.3 0.92 6.62 ;
			LAYER M1 ;
			RECT 2.54 6.3 2.9 6.62 ;
			LAYER M1 ;
			RECT 4.54 6.3 4.9 6.62 ;
			LAYER M1 ;
			RECT 0.56 5.94 5.72 6.3 ;
			LAYER M1 ;
			RECT 3.48 3.4 3.96 3.42 ;
			LAYER M1 ;
			RECT 5.36 3.4 5.72 5.94 ;
			LAYER M1 ;
			RECT 3.48 3.04 5.72 3.4 ;
			LAYER M1 ;
			RECT 3.48 1.1 3.96 3.04 ;
		END
	END out
	PIN in1
		DIRECTION input ;
		PORT
			LAYER M1 ;
			RECT 2.42 5.26 4.52 5.62 ;
			LAYER M1 ;
			RECT 2.42 4.98 2.78 5.26 ;
			LAYER M1 ;
			RECT 2.18 4.38 2.78 4.98 ;
			LAYER M1 ;
			RECT 4.16 4.8 4.52 5.26 ;
			LAYER M1 ;
			RECT 4.16 4.2 4.88 4.8 ;
		END
	END in1
	PIN in2
		DIRECTION input ;
		PORT
			LAYER M1 ;
			RECT 6.2 5.2 6.8 5.8 ;
			LAYER M1 ;
			RECT 1.2 4.2 1.8 4.9 ;
			LAYER VIA1 ;
			RECT 6.32 5.32 6.68 5.68 ;
			LAYER VIA1 ;
			RECT 1.32 4.32 1.68 4.68 ;
			LAYER M2 ;
			RECT 1.2 5.2 1.8 5.8 ;
			LAYER M2 ;
			RECT 6.2 5.2 6.8 5.8 ;
			LAYER M2 ;
			RECT 1.28 4.8 1.72 5.2 ;
			LAYER M2 ;
			RECT 1.2 4.2 1.8 4.8 ;
			LAYER VIA2 ;
			RECT 1.32 5.32 1.68 5.68 ;
			LAYER VIA2 ;
			RECT 6.32 5.32 6.68 5.68 ;
			LAYER M3 ;
			RECT 1.2 5.72 1.8 5.8 ;
			LAYER M3 ;
			RECT 6.2 5.72 6.8 5.8 ;
			LAYER M3 ;
			RECT 1.2 5.3 6.8 5.72 ;
			LAYER M3 ;
			RECT 1.2 5.2 1.8 5.3 ;
			LAYER M3 ;
			RECT 6.2 5.2 6.8 5.3 ;
		END
	END in2
	PIN GND
		DIRECTION inout ;
		USE GROUND ;
		SHAPE ABUTMENT ;
		PORT
			LAYER M1 ;
			RECT 0.26 1.1 0.74 3.42 ;
			LAYER M1 ;
			RECT 6.7 1.1 7.18 3.42 ;
			LAYER M1 ;
			RECT 0.34 0.7 0.7 1.1 ;
			LAYER M1 ;
			RECT 6.76 0.7 7.12 1.1 ;
			LAYER M1 ;
			RECT 0 -0.7 8 0.7 ;
		END
	END GND
	PIN VDD
		DIRECTION inout ;
		USE POWER ;
		SHAPE ABUTMENT ;
		PORT
			LAYER M1 ;
			RECT 0 9.3 8 10.7 ;
			LAYER M1 ;
			RECT 1.56 8.94 1.9 9.3 ;
			LAYER M1 ;
			RECT 3.56 8.94 3.9 9.3 ;
			LAYER M1 ;
			RECT 1.48 6.62 1.96 8.94 ;
			LAYER M1 ;
			RECT 3.48 6.62 3.96 8.94 ;
		END
	END VDD
	PIN in3
		DIRECTION input ;
		PORT
			LAYER M1 ;
			RECT 0.2 4.2 0.8 4.8 ;
			LAYER M1 ;
			RECT 6.2 4.2 6.8 4.8 ;
			LAYER VIA1 ;
			RECT 0.32 4.32 0.68 4.68 ;
			LAYER VIA1 ;
			RECT 6.32 4.32 6.68 4.68 ;
			LAYER M2 ;
			RECT 0.2 4.2 0.8 4.8 ;
			LAYER M2 ;
			RECT 6.2 4.2 6.8 4.8 ;
			LAYER VIA2 ;
			RECT 0.32 4.32 0.68 4.68 ;
			LAYER VIA2 ;
			RECT 6.32 4.32 6.68 4.68 ;
			LAYER M3 ;
			RECT 0.2 4.7 0.8 4.8 ;
			LAYER M3 ;
			RECT 6.2 4.7 6.8 4.8 ;
			LAYER M3 ;
			RECT 0.2 4.28 6.8 4.7 ;
			LAYER M3 ;
			RECT 0.2 4.2 0.8 4.28 ;
			LAYER M3 ;
			RECT 6.2 4.2 6.8 4.28 ;
		END
	END in3
	PIN in0
		DIRECTION input ;
		PORT
			LAYER M1 ;
			RECT 3.2 4.2 3.8 4.8 ;
		END
	END in0
	OBS
		LAYER M1 ;
		RECT 3.48 3.4 3.96 3.42 ;
	END
END MMI_NAND4B
MACRO MMI_NAND4C
	CLASS CORE ;
	FOREIGN MMI_NAND4C 0 0 ;
	SIZE 14 BY 10 ;
	SYMMETRY X Y ;
	SITE CORE1 ;
	PIN out
		DIRECTION output ;
		PORT
			LAYER M1 ;
			RECT 0.46 6.62 0.94 8.94 ;
			LAYER M1 ;
			RECT 2.46 6.62 2.94 8.94 ;
			LAYER M1 ;
			RECT 4.46 6.62 4.94 8.94 ;
			LAYER M1 ;
			RECT 6.46 6.62 6.94 8.94 ;
			LAYER M1 ;
			RECT 8.46 7.28 8.94 8.94 ;
			LAYER M1 ;
			RECT 8.46 6.92 11.54 7.28 ;
			LAYER M1 ;
			RECT 8.46 6.62 8.94 6.92 ;
			LAYER M1 ;
			RECT 0.56 6.3 0.92 6.62 ;
			LAYER M1 ;
			RECT 2.54 6.3 2.9 6.62 ;
			LAYER M1 ;
			RECT 4.52 6.3 4.88 6.62 ;
			LAYER M1 ;
			RECT 6.52 6.3 6.88 6.62 ;
			LAYER M1 ;
			RECT 8.54 6.3 8.9 6.62 ;
			LAYER M1 ;
			RECT 0.56 5.94 8.9 6.3 ;
			LAYER M1 ;
			RECT 2.28 3.42 2.64 5.94 ;
			LAYER M1 ;
			RECT 11.18 3.42 11.54 6.92 ;
			LAYER M1 ;
			RECT 2.28 3.06 3.98 3.42 ;
			LAYER M1 ;
			RECT 3.5 1.1 3.98 3.06 ;
			LAYER M1 ;
			RECT 9.94 3.06 11.54 3.42 ;
			LAYER M1 ;
			RECT 9.94 1.1 10.42 3.06 ;
		END
	END out
	PIN in1
		DIRECTION input ;
		PORT
			LAYER M1 ;
			RECT 4.2 4.2 4.86 4.8 ;
		END
	END in1
	PIN in2
		DIRECTION input ;
		PORT
			LAYER M1 ;
			RECT 1.2 4.2 1.8 4.8 ;
			LAYER M1 ;
			RECT 5.2 4.2 6.06 4.8 ;
			LAYER M1 ;
			RECT 12.2 4.2 12.8 4.8 ;
			LAYER VIA1 ;
			RECT 1.32 4.32 1.68 4.68 ;
			LAYER VIA1 ;
			RECT 5.32 4.32 5.68 4.68 ;
			LAYER VIA1 ;
			RECT 12.32 4.32 12.68 4.68 ;
			LAYER M2 ;
			RECT 1.2 4.2 1.8 4.8 ;
			LAYER M2 ;
			RECT 5.2 4.2 5.8 4.8 ;
			LAYER M2 ;
			RECT 12.2 4.2 12.8 4.8 ;
			LAYER M2 ;
			RECT 1.28 3.8 1.7 4.2 ;
			LAYER M2 ;
			RECT 5.28 3.8 5.7 4.2 ;
			LAYER M2 ;
			RECT 12.3 3.8 12.72 4.2 ;
			LAYER M2 ;
			RECT 1.2 3.2 1.8 3.8 ;
			LAYER M2 ;
			RECT 5.2 3.2 5.8 3.8 ;
			LAYER M2 ;
			RECT 12.2 3.2 12.8 3.8 ;
			LAYER VIA2 ;
			RECT 1.32 3.32 1.68 3.68 ;
			LAYER VIA2 ;
			RECT 5.32 3.32 5.68 3.68 ;
			LAYER VIA2 ;
			RECT 12.32 3.32 12.68 3.68 ;
			LAYER M3 ;
			RECT 1.2 3.7 1.8 3.8 ;
			LAYER M3 ;
			RECT 5.2 3.7 5.8 3.8 ;
			LAYER M3 ;
			RECT 12.2 3.7 12.8 3.8 ;
			LAYER M3 ;
			RECT 1.2 3.28 12.8 3.7 ;
			LAYER M3 ;
			RECT 1.2 3.2 1.8 3.28 ;
			LAYER M3 ;
			RECT 5.2 3.2 5.8 3.28 ;
			LAYER M3 ;
			RECT 12.2 3.2 12.8 3.28 ;
		END
	END in2
	PIN GND
		DIRECTION inout ;
		USE GROUND ;
		SHAPE ABUTMENT ;
		PORT
			LAYER M1 ;
			RECT 0.28 1.1 0.76 3.42 ;
			LAYER M1 ;
			RECT 6.72 1.1 7.2 3.42 ;
			LAYER M1 ;
			RECT 13.16 1.1 13.64 3.42 ;
			LAYER M1 ;
			RECT 0.32 0.7 0.68 1.1 ;
			LAYER M1 ;
			RECT 6.78 0.7 7.14 1.1 ;
			LAYER M1 ;
			RECT 13.24 0.7 13.58 1.1 ;
			LAYER M1 ;
			RECT 0 -0.7 14 0.7 ;
		END
	END GND
	PIN VDD
		DIRECTION inout ;
		USE POWER ;
		SHAPE ABUTMENT ;
		PORT
			LAYER M1 ;
			RECT 0 9.3 14 10.7 ;
			LAYER M1 ;
			RECT 1.52 8.94 1.86 9.3 ;
			LAYER M1 ;
			RECT 3.5 8.94 3.84 9.3 ;
			LAYER M1 ;
			RECT 5.52 8.94 5.88 9.3 ;
			LAYER M1 ;
			RECT 7.54 8.94 7.88 9.3 ;
			LAYER M1 ;
			RECT 1.46 6.62 1.94 8.94 ;
			LAYER M1 ;
			RECT 3.46 6.62 3.94 8.94 ;
			LAYER M1 ;
			RECT 5.46 6.62 5.94 8.94 ;
			LAYER M1 ;
			RECT 7.46 6.62 7.94 8.94 ;
		END
	END VDD
	PIN in3
		DIRECTION input ;
		PORT
			LAYER M1 ;
			RECT 0.2 4.2 0.8 4.8 ;
			LAYER M1 ;
			RECT 6.44 3.82 7.04 4.8 ;
			LAYER M1 ;
			RECT 13.2 4.2 13.8 4.8 ;
			LAYER VIA1 ;
			RECT 0.32 4.32 0.68 4.68 ;
			LAYER VIA1 ;
			RECT 6.56 4.32 6.92 4.68 ;
			LAYER VIA1 ;
			RECT 13.32 4.32 13.68 4.68 ;
			LAYER M2 ;
			RECT 0.2 4.2 0.8 4.8 ;
			LAYER M2 ;
			RECT 6.44 4.2 7.04 4.8 ;
			LAYER M2 ;
			RECT 13.2 4.2 13.8 4.8 ;
			LAYER VIA2 ;
			RECT 0.32 4.32 0.68 4.68 ;
			LAYER VIA2 ;
			RECT 6.56 4.32 6.92 4.68 ;
			LAYER VIA2 ;
			RECT 13.32 4.32 13.68 4.68 ;
			LAYER M3 ;
			RECT 0.2 4.7 0.8 4.8 ;
			LAYER M3 ;
			RECT 6.44 4.7 7.04 4.8 ;
			LAYER M3 ;
			RECT 13.2 4.7 13.8 4.8 ;
			LAYER M3 ;
			RECT 0.2 4.28 13.8 4.7 ;
			LAYER M3 ;
			RECT 0.2 4.2 0.8 4.28 ;
			LAYER M3 ;
			RECT 6.44 4.2 7.04 4.28 ;
			LAYER M3 ;
			RECT 13.2 4.2 13.8 4.28 ;
		END
	END in3
	PIN in0
		DIRECTION input ;
		PORT
			LAYER M1 ;
			RECT 10.2 6 10.8 6.6 ;
			LAYER M1 ;
			RECT 10.2 5.6 10.56 6 ;
			LAYER M1 ;
			RECT 3.32 5.24 10.56 5.6 ;
			LAYER M1 ;
			RECT 3.32 4.38 3.78 5.24 ;
			LAYER M1 ;
			RECT 10.2 4.8 10.56 5.24 ;
			LAYER M1 ;
			RECT 3.2 3.78 3.8 4.38 ;
			LAYER M1 ;
			RECT 10.2 4.2 10.8 4.8 ;
		END
	END in0
	OBS
	END
END MMI_NAND4C
MACRO MMI_NOR2A
	CLASS CORE ;
	FOREIGN MMI_NOR2A 0 0 ;
	SIZE 3 BY 10 ;
	SYMMETRY X Y ;
	SITE CORE1 ;
	PIN in1
		DIRECTION input ;
		PORT
			LAYER M1 ;
			RECT 0.2 4.2 0.88 4.8 ;
		END
	END in1
	PIN out
		DIRECTION output ;
		PORT
			LAYER M1 ;
			RECT 2.26 6.1 2.74 8.42 ;
			LAYER M1 ;
			RECT 2.28 5.72 2.64 6.1 ;
			LAYER M1 ;
			RECT 1.32 5.36 2.64 5.72 ;
			LAYER M1 ;
			RECT 1.32 2.16 1.66 5.36 ;
			LAYER M1 ;
			RECT 1.26 1.64 1.74 2.16 ;
		END
	END out
	PIN GND
		DIRECTION inout ;
		USE GROUND ;
		SHAPE ABUTMENT ;
		PORT
			LAYER M1 ;
			RECT 0.26 1.64 0.74 2.16 ;
			LAYER M1 ;
			RECT 2.26 1.64 2.74 2.16 ;
			LAYER M1 ;
			RECT 0.32 0.7 0.66 1.64 ;
			LAYER M1 ;
			RECT 2.28 0.7 2.64 1.64 ;
			LAYER M1 ;
			RECT 0 -0.7 3 0.7 ;
		END
	END GND
	PIN VDD
		DIRECTION inout ;
		USE POWER ;
		SHAPE ABUTMENT ;
		PORT
			LAYER M1 ;
			RECT 0 9.3 3 10.7 ;
			LAYER M1 ;
			RECT 0.34 8.42 0.7 9.3 ;
			LAYER M1 ;
			RECT 0.26 6.1 0.74 8.42 ;
		END
	END VDD
	PIN in0
		DIRECTION input ;
		PORT
			LAYER M1 ;
			RECT 2.12 4.2 2.8 4.8 ;
		END
	END in0
	OBS
	END
END MMI_NOR2A
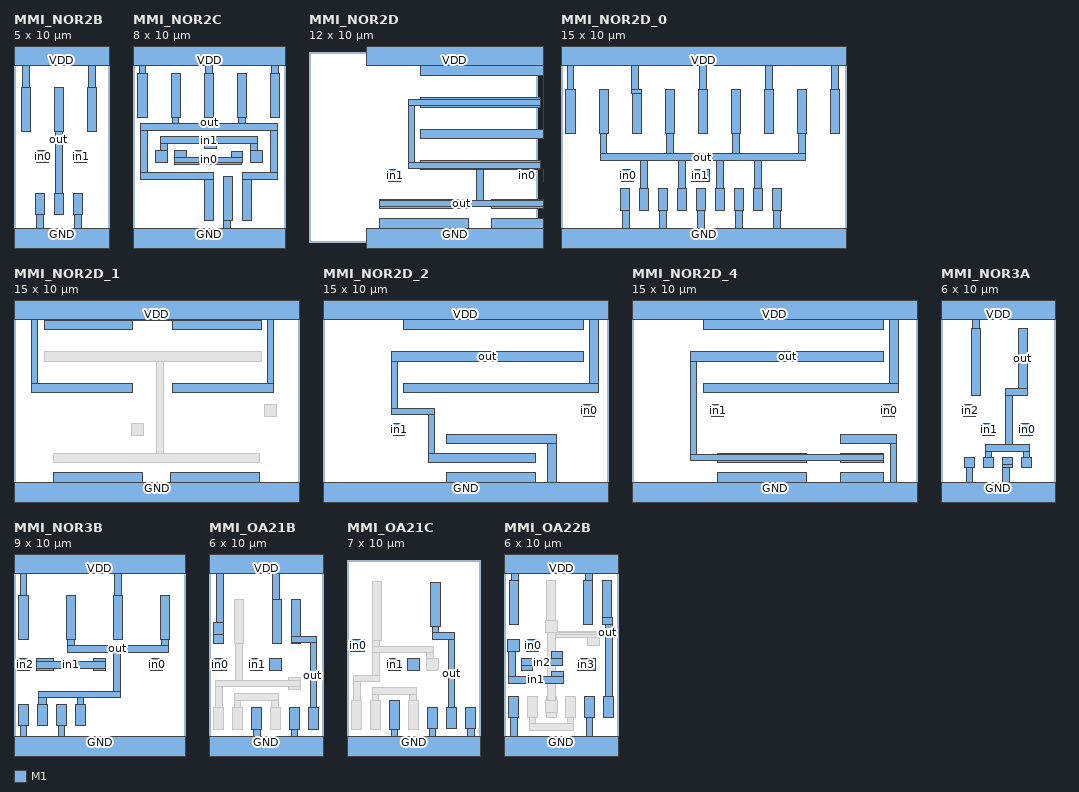
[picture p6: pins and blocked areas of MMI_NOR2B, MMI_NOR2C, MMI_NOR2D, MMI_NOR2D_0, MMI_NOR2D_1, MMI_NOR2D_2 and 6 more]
MACRO MMI_NOR2B
	CLASS CORE ;
	FOREIGN MMI_NOR2B 0 0 ;
	SIZE 5 BY 10 ;
	SYMMETRY X Y ;
	SITE CORE1 ;
	PIN in1
		DIRECTION input ;
		PORT
			LAYER M1 ;
			RECT 3.2 4.2 3.8 4.8 ;
		END
	END in1
	PIN out
		DIRECTION output ;
		PORT
			LAYER M1 ;
			RECT 2.12 5.8 2.6 8.12 ;
			LAYER M1 ;
			RECT 2.18 2.56 2.54 5.8 ;
			LAYER M1 ;
			RECT 2.12 1.44 2.6 2.56 ;
		END
	END out
	PIN GND
		DIRECTION inout ;
		USE GROUND ;
		SHAPE ABUTMENT ;
		PORT
			LAYER M1 ;
			RECT 1.12 1.44 1.6 2.56 ;
			LAYER M1 ;
			RECT 3.12 1.44 3.6 2.56 ;
			LAYER M1 ;
			RECT 1.18 0.7 1.54 1.44 ;
			LAYER M1 ;
			RECT 3.2 0.7 3.54 1.44 ;
			LAYER M1 ;
			RECT 0 -0.7 5 0.7 ;
		END
	END GND
	PIN VDD
		DIRECTION inout ;
		USE POWER ;
		SHAPE ABUTMENT ;
		PORT
			LAYER M1 ;
			RECT 0 9.3 5 10.7 ;
			LAYER M1 ;
			RECT 0.44 8.12 0.8 9.3 ;
			LAYER M1 ;
			RECT 3.92 8.12 4.28 9.3 ;
			LAYER M1 ;
			RECT 0.38 5.8 0.86 8.12 ;
			LAYER M1 ;
			RECT 3.86 5.8 4.34 8.12 ;
		END
	END VDD
	PIN in0
		DIRECTION input ;
		PORT
			LAYER M1 ;
			RECT 1.2 4.2 1.8 4.8 ;
		END
	END in0
	OBS
	END
END MMI_NOR2B
MACRO MMI_NOR2C
	CLASS CORE ;
	FOREIGN MMI_NOR2C 0 0 ;
	SIZE 8 BY 10 ;
	SYMMETRY X Y ;
	SITE CORE1 ;
	PIN in1
		DIRECTION input ;
		PORT
			LAYER M1 ;
			RECT 1.44 5.18 6.56 5.54 ;
			LAYER M1 ;
			RECT 1.44 4.8 1.8 5.18 ;
			LAYER M1 ;
			RECT 3.78 4.94 4.38 5.18 ;
			LAYER M1 ;
			RECT 1.2 4.2 1.8 4.8 ;
			LAYER M1 ;
			RECT 6.2 4.8 6.56 5.18 ;
			LAYER M1 ;
			RECT 6.2 4.2 6.8 4.8 ;
		END
	END in1
	PIN out
		DIRECTION output ;
		PORT
			LAYER M1 ;
			RECT 2 6.56 2.48 8.88 ;
			LAYER M1 ;
			RECT 5.48 6.56 5.96 8.88 ;
			LAYER M1 ;
			RECT 2.06 6.24 2.42 6.56 ;
			LAYER M1 ;
			RECT 5.54 6.24 5.9 6.56 ;
			LAYER M1 ;
			RECT 0.4 5.88 7.62 6.24 ;
			LAYER M1 ;
			RECT 0.4 3.64 0.76 5.88 ;
			LAYER M1 ;
			RECT 7.26 3.64 7.62 5.88 ;
			LAYER M1 ;
			RECT 0.4 3.28 4.22 3.64 ;
			LAYER M1 ;
			RECT 3.74 1.14 4.22 3.28 ;
			LAYER M1 ;
			RECT 5.74 3.28 7.62 3.64 ;
			LAYER M1 ;
			RECT 5.74 1.14 6.22 3.28 ;
		END
	END out
	PIN GND
		DIRECTION inout ;
		USE GROUND ;
		SHAPE ABUTMENT ;
		PORT
			LAYER M1 ;
			RECT 4.74 1.14 5.22 3.46 ;
			LAYER M1 ;
			RECT 4.78 0.7 5.14 1.14 ;
			LAYER M1 ;
			RECT 0 -0.7 8 0.7 ;
		END
	END GND
	PIN VDD
		DIRECTION inout ;
		USE POWER ;
		SHAPE ABUTMENT ;
		PORT
			LAYER M1 ;
			RECT 0 9.3 8 10.7 ;
			LAYER M1 ;
			RECT 0.32 8.88 0.68 9.3 ;
			LAYER M1 ;
			RECT 3.8 8.88 4.16 9.3 ;
			LAYER M1 ;
			RECT 7.28 8.88 7.64 9.3 ;
			LAYER M1 ;
			RECT 0.26 6.56 0.74 8.88 ;
			LAYER M1 ;
			RECT 3.74 6.56 4.22 8.88 ;
			LAYER M1 ;
			RECT 7.22 6.56 7.7 8.88 ;
		END
	END VDD
	PIN in0
		DIRECTION input ;
		PORT
			LAYER M1 ;
			RECT 2.2 4.46 2.8 4.8 ;
			LAYER M1 ;
			RECT 5.16 4.46 5.76 4.78 ;
			LAYER M1 ;
			RECT 2.2 4.18 5.76 4.46 ;
			LAYER M1 ;
			RECT 2.2 4.1 5.72 4.18 ;
		END
	END in0
	OBS
	END
END MMI_NOR2C
MACRO MMI_NOR2D
	CLASS CORE ;
	FOREIGN MMI_NOR2D 3 0 ;
	SIZE 12 BY 10 ;
	SYMMETRY X Y ;
	SITE CORE1 ;
	PIN in1
		DIRECTION input ;
		PORT
			LAYER M1 ;
			RECT 4.2 3.2 4.8 3.8 ;
		END
	END in1
	PIN out
		DIRECTION output ;
		PORT
			LAYER M1 ;
			RECT 5.88 7.48 12.16 7.58 ;
			LAYER M1 ;
			RECT 5.24 7.16 12.16 7.48 ;
			LAYER M1 ;
			RECT 5.24 4.2 5.56 7.16 ;
			LAYER M1 ;
			RECT 5.88 7.1 12.16 7.16 ;
			LAYER M1 ;
			RECT 5.88 4.2 12.16 4.28 ;
			LAYER M1 ;
			RECT 5.24 3.88 12.16 4.2 ;
			LAYER M1 ;
			RECT 5.88 3.8 12.16 3.88 ;
			LAYER M1 ;
			RECT 3.7 2.2 8.38 2.26 ;
			LAYER M1 ;
			RECT 8.84 2.2 9.16 3.8 ;
			LAYER M1 ;
			RECT 9.58 2.2 14.26 2.26 ;
			LAYER M1 ;
			RECT 3.7 1.88 14.26 2.2 ;
			LAYER M1 ;
			RECT 3.7 1.78 8.38 1.88 ;
			LAYER M1 ;
			RECT 9.58 1.78 14.26 1.88 ;
		END
	END out
	PIN GND
		DIRECTION inout ;
		USE GROUND ;
		SHAPE ABUTMENT ;
		PORT
			LAYER M1 ;
			RECT 3.7 0.7 8.38 1.26 ;
			LAYER M1 ;
			RECT 9.58 0.7 14.26 1.26 ;
			LAYER M1 ;
			RECT 3 -0.7 15 0.7 ;
		END
	END GND
	PIN VDD
		DIRECTION inout ;
		USE POWER ;
		SHAPE ABUTMENT ;
		PORT
			LAYER M1 ;
			RECT 3 9.3 15 10.7 ;
			LAYER M1 ;
			RECT 3 9.28 12.96 9.3 ;
			LAYER M1 ;
			RECT 5.88 8.74 12.96 9.28 ;
			LAYER M1 ;
			RECT 12.48 5.92 12.96 8.74 ;
			LAYER M1 ;
			RECT 5.88 5.44 12.96 5.92 ;
		END
	END VDD
	PIN in0
		DIRECTION input ;
		PORT
			LAYER M1 ;
			RECT 13.2 3.2 13.8 3.8 ;
		END
	END in0
	OBS
	END
END MMI_NOR2D
MACRO MMI_NOR2D_0
	CLASS CORE ;
	FOREIGN MMI_NOR2D_0 0 0 ;
	SIZE 15 BY 10 ;
	SYMMETRY X Y ;
	SITE CORE1 ;
	PIN in1
		DIRECTION input ;
		PORT
			LAYER M1 ;
			RECT 6.88 3.2 7.8 3.8 ;
		END
	END in1
	PIN out
		DIRECTION output ;
		PORT
			LAYER M1 ;
			RECT 2 5.72 2.48 8.04 ;
			LAYER M1 ;
			RECT 5.48 5.72 5.96 8.04 ;
			LAYER M1 ;
			RECT 8.96 5.72 9.44 8.04 ;
			LAYER M1 ;
			RECT 12.44 5.72 12.92 8.04 ;
			LAYER M1 ;
			RECT 2.06 4.64 2.4 5.72 ;
			LAYER M1 ;
			RECT 5.54 4.64 5.9 5.72 ;
			LAYER M1 ;
			RECT 9.02 4.64 9.38 5.72 ;
			LAYER M1 ;
			RECT 12.52 4.64 12.88 5.72 ;
			LAYER M1 ;
			RECT 2.06 4.28 12.88 4.64 ;
			LAYER M1 ;
			RECT 4.2 2.8 4.56 4.28 ;
			LAYER M1 ;
			RECT 6.2 2.8 6.54 4.28 ;
			LAYER M1 ;
			RECT 8.18 2.8 8.54 4.28 ;
			LAYER M1 ;
			RECT 10.18 2.8 10.54 4.28 ;
			LAYER M1 ;
			RECT 4.12 1.68 4.6 2.8 ;
			LAYER M1 ;
			RECT 6.12 1.68 6.6 2.8 ;
			LAYER M1 ;
			RECT 8.12 1.68 8.6 2.8 ;
			LAYER M1 ;
			RECT 10.12 1.68 10.6 2.8 ;
		END
	END out
	PIN GND
		DIRECTION inout ;
		USE GROUND ;
		SHAPE ABUTMENT ;
		PORT
			LAYER M1 ;
			RECT 3.12 1.68 3.6 2.8 ;
			LAYER M1 ;
			RECT 5.12 1.68 5.6 2.8 ;
			LAYER M1 ;
			RECT 7.12 1.68 7.6 2.8 ;
			LAYER M1 ;
			RECT 9.12 1.68 9.6 2.8 ;
			LAYER M1 ;
			RECT 11.12 1.68 11.6 2.8 ;
			LAYER M1 ;
			RECT 3.22 0.7 3.58 1.68 ;
			LAYER M1 ;
			RECT 5.2 0.7 5.56 1.68 ;
			LAYER M1 ;
			RECT 7.2 0.7 7.56 1.68 ;
			LAYER M1 ;
			RECT 9.18 0.7 9.54 1.68 ;
			LAYER M1 ;
			RECT 11.18 0.7 11.54 1.68 ;
			LAYER M1 ;
			RECT 0 -0.7 15 0.7 ;
		END
	END GND
	PIN VDD
		DIRECTION inout ;
		USE POWER ;
		SHAPE ABUTMENT ;
		PORT
			LAYER M1 ;
			RECT 0 9.3 15 10.7 ;
			LAYER M1 ;
			RECT 0.32 8.04 0.66 9.3 ;
			LAYER M1 ;
			RECT 3.7 8.04 4.06 9.3 ;
			LAYER M1 ;
			RECT 7.28 8.04 7.64 9.3 ;
			LAYER M1 ;
			RECT 10.76 8.04 11.12 9.3 ;
			LAYER M1 ;
			RECT 14.26 8.04 14.62 9.3 ;
			LAYER M1 ;
			RECT 0.26 5.72 0.74 8.04 ;
			LAYER M1 ;
			RECT 3.7 7.82 4.22 8.04 ;
			LAYER M1 ;
			RECT 3.74 5.72 4.22 7.82 ;
			LAYER M1 ;
			RECT 7.22 5.72 7.7 8.04 ;
			LAYER M1 ;
			RECT 10.7 5.72 11.18 8.04 ;
			LAYER M1 ;
			RECT 14.18 5.72 14.66 8.04 ;
		END
	END VDD
	PIN in0
		DIRECTION input ;
		PORT
			LAYER M1 ;
			RECT 3.2 3.2 3.8 3.8 ;
		END
	END in0
	OBS
	END
END MMI_NOR2D_0
MACRO MMI_NOR2D_1
	CLASS CORE ;
	FOREIGN MMI_NOR2D_1 0 0 ;
	SIZE 15 BY 10 ;
	SYMMETRY X Y ;
	SITE CORE1 ;
	PIN GND
		DIRECTION inout ;
		USE GROUND ;
		SHAPE ABUTMENT ;
		PORT
			LAYER M1 ;
			RECT 2.06 0.7 6.74 1.26 ;
			LAYER M1 ;
			RECT 8.22 0.7 12.9 1.26 ;
			LAYER M1 ;
			RECT 0 -0.7 15 0.7 ;
		END
	END GND
	PIN VDD
		DIRECTION inout ;
		USE POWER ;
		SHAPE ABUTMENT ;
		PORT
			LAYER M1 ;
			RECT 0 9.3 15 10.7 ;
			LAYER M1 ;
			RECT 0.92 5.94 1.26 9.3 ;
			LAYER M1 ;
			RECT 1.58 9.24 13 9.3 ;
			LAYER M1 ;
			RECT 1.58 8.74 6.26 9.24 ;
			LAYER M1 ;
			RECT 8.32 8.74 13 9.24 ;
			LAYER M1 ;
			RECT 13.32 5.94 13.64 9.3 ;
			LAYER M1 ;
			RECT 0.92 5.46 6.26 5.94 ;
			LAYER M1 ;
			RECT 8.32 5.46 13.64 5.94 ;
		END
	END VDD
	OBS
		LAYER M1 ;
		RECT 1.58 7.1 13 7.58 ;
		LAYER M1 ;
		RECT 6.2 3.2 6.8 3.8 ;
		LAYER M1 ;
		RECT 7.5 2.26 7.86 7.1 ;
		LAYER M1 ;
		RECT 13.2 4.2 13.8 4.8 ;
		LAYER M1 ;
		RECT 2.06 1.78 12.9 2.26 ;
	END
END MMI_NOR2D_1
MACRO MMI_NOR2D_2
	CLASS CORE ;
	FOREIGN MMI_NOR2D_2 0 0 ;
	SIZE 15 BY 10 ;
	SYMMETRY X Y ;
	SITE CORE1 ;
	PIN out
		DIRECTION output ;
		PORT
			LAYER M1 ;
			RECT 3.6 7.1 13.72 7.58 ;
			LAYER M1 ;
			RECT 3.6 4.62 3.92 7.1 ;
			LAYER M1 ;
			RECT 3.6 4.3 5.86 4.62 ;
			LAYER M1 ;
			RECT 5.54 2.26 5.86 4.3 ;
			LAYER M1 ;
			RECT 5.54 1.78 11.2 2.26 ;
		END
	END out
	PIN in1
		DIRECTION input ;
		PORT
			LAYER M1 ;
			RECT 3.7 3.2 4.3 3.8 ;
		END
	END in1
	PIN GND
		DIRECTION inout ;
		USE GROUND ;
		SHAPE ABUTMENT ;
		PORT
			LAYER M1 ;
			RECT 6.52 2.78 12.3 3.26 ;
			LAYER M1 ;
			RECT 6.52 0.7 11.2 1.26 ;
			LAYER M1 ;
			RECT 11.8 0.7 12.3 2.78 ;
			LAYER M1 ;
			RECT 0 -0.7 15 0.7 ;
		END
	END GND
	PIN VDD
		DIRECTION inout ;
		USE POWER ;
		SHAPE ABUTMENT ;
		PORT
			LAYER M1 ;
			RECT 0 9.3 15 10.7 ;
			LAYER M1 ;
			RECT 4.24 8.74 13.72 9.3 ;
			LAYER M1 ;
			RECT 14.04 5.94 14.5 9.3 ;
			LAYER M1 ;
			RECT 4.24 5.46 14.5 5.94 ;
		END
	END VDD
	PIN in0
		DIRECTION input ;
		PORT
			LAYER M1 ;
			RECT 13.7 4.2 14.3 4.8 ;
		END
	END in0
	OBS
	END
END MMI_NOR2D_2
MACRO MMI_NOR2D_4
	CLASS CORE ;
	FOREIGN MMI_NOR2D_4 0 0 ;
	SIZE 15 BY 10 ;
	SYMMETRY X Y ;
	SITE CORE1 ;
	PIN in1
		DIRECTION input ;
		PORT
			LAYER M1 ;
			RECT 4.2 4.2 4.8 4.8 ;
		END
	END in1
	PIN out
		DIRECTION output ;
		PORT
			LAYER M1 ;
			RECT 3.08 7.1 13.24 7.58 ;
			LAYER M1 ;
			RECT 3.08 2.18 3.4 7.1 ;
			LAYER M1 ;
			RECT 4.52 2.2 9.2 2.26 ;
			LAYER M1 ;
			RECT 10.98 2.2 13.26 2.26 ;
			LAYER M1 ;
			RECT 4.52 2.18 13.26 2.2 ;
			LAYER M1 ;
			RECT 3.08 1.88 13.26 2.18 ;
			LAYER M1 ;
			RECT 3.08 1.86 9.2 1.88 ;
			LAYER M1 ;
			RECT 4.52 1.78 9.2 1.86 ;
			LAYER M1 ;
			RECT 10.98 1.78 13.26 1.88 ;
		END
	END out
	PIN GND
		DIRECTION inout ;
		USE GROUND ;
		SHAPE ABUTMENT ;
		PORT
			LAYER M1 ;
			RECT 10.98 2.78 13.94 3.26 ;
			LAYER M1 ;
			RECT 4.52 0.7 9.2 1.26 ;
			LAYER M1 ;
			RECT 10.98 0.7 13.26 1.26 ;
			LAYER M1 ;
			RECT 13.62 0.7 13.94 2.78 ;
			LAYER M1 ;
			RECT 0 -0.7 15 0.7 ;
		END
	END GND
	PIN VDD
		DIRECTION inout ;
		USE POWER ;
		SHAPE ABUTMENT ;
		PORT
			LAYER M1 ;
			RECT 0 9.3 15 10.7 ;
			LAYER M1 ;
			RECT 3.76 8.74 13.24 9.3 ;
			LAYER M1 ;
			RECT 13.56 5.94 14.02 9.3 ;
			LAYER M1 ;
			RECT 3.76 5.46 14.02 5.94 ;
		END
	END VDD
	PIN in0
		DIRECTION input ;
		PORT
			LAYER M1 ;
			RECT 13.2 4.2 13.8 4.8 ;
		END
	END in0
	OBS
	END
END MMI_NOR2D_4
MACRO MMI_NOR3A
	CLASS CORE ;
	FOREIGN MMI_NOR3A 0 0 ;
	SIZE 6 BY 10 ;
	SYMMETRY X Y ;
	SITE CORE1 ;
	PIN out
		DIRECTION output ;
		PORT
			LAYER M1 ;
			RECT 4.06 5.66 4.54 8.82 ;
			LAYER M1 ;
			RECT 3.38 5.3 4.54 5.66 ;
			LAYER M1 ;
			RECT 3.38 2.7 3.74 5.3 ;
			LAYER M1 ;
			RECT 2.32 2.34 4.68 2.7 ;
			LAYER M1 ;
			RECT 2.32 2.02 2.68 2.34 ;
			LAYER M1 ;
			RECT 4.32 2.02 4.68 2.34 ;
			LAYER M1 ;
			RECT 2.26 1.5 2.74 2.02 ;
			LAYER M1 ;
			RECT 4.26 1.5 4.74 2.02 ;
		END
	END out
	PIN in1
		DIRECTION input ;
		PORT
			LAYER M1 ;
			RECT 2.2 3.2 2.8 3.8 ;
		END
	END in1
	PIN in2
		DIRECTION input ;
		PORT
			LAYER M1 ;
			RECT 1.2 4.2 1.8 4.8 ;
		END
	END in2
	PIN GND
		DIRECTION inout ;
		USE GROUND ;
		SHAPE ABUTMENT ;
		PORT
			LAYER M1 ;
			RECT 1.26 1.5 1.74 2.02 ;
			LAYER M1 ;
			RECT 3.26 1.68 3.74 2.02 ;
			LAYER M1 ;
			RECT 3.24 1.5 3.74 1.68 ;
			LAYER M1 ;
			RECT 1.32 0.7 1.66 1.5 ;
			LAYER M1 ;
			RECT 3.24 0.7 3.6 1.5 ;
			LAYER M1 ;
			RECT 0 -0.7 6 0.7 ;
		END
	END GND
	PIN VDD
		DIRECTION inout ;
		USE POWER ;
		SHAPE ABUTMENT ;
		PORT
			LAYER M1 ;
			RECT 0 9.3 6 10.7 ;
			LAYER M1 ;
			RECT 1.64 8.82 2 9.3 ;
			LAYER M1 ;
			RECT 1.58 5.3 2.06 8.82 ;
		END
	END VDD
	PIN in0
		DIRECTION input ;
		PORT
			LAYER M1 ;
			RECT 4.2 3.2 4.8 3.8 ;
		END
	END in0
	OBS
	END
END MMI_NOR3A
MACRO MMI_NOR3B
	CLASS CORE ;
	FOREIGN MMI_NOR3B 0 0 ;
	SIZE 9 BY 10 ;
	SYMMETRY X Y ;
	SITE CORE1 ;
	PIN out
		DIRECTION output ;
		PORT
			LAYER M1 ;
			RECT 2.74 5.82 3.22 8.14 ;
			LAYER M1 ;
			RECT 7.7 5.82 8.18 8.14 ;
			LAYER M1 ;
			RECT 2.8 5.5 3.16 5.82 ;
			LAYER M1 ;
			RECT 7.76 5.5 8.12 5.82 ;
			LAYER M1 ;
			RECT 2.8 5.14 8.12 5.5 ;
			LAYER M1 ;
			RECT 5.24 3.1 5.6 5.14 ;
			LAYER M1 ;
			RECT 1.28 2.74 5.6 3.1 ;
			LAYER M1 ;
			RECT 1.28 2.42 1.72 2.74 ;
			LAYER M1 ;
			RECT 3.32 2.42 3.68 2.74 ;
			LAYER M1 ;
			RECT 1.26 1.3 1.74 2.42 ;
			LAYER M1 ;
			RECT 3.26 1.3 3.74 2.42 ;
		END
	END out
	PIN in1
		DIRECTION input ;
		PORT
			LAYER M1 ;
			RECT 1.2 4.66 2.08 4.8 ;
			LAYER M1 ;
			RECT 4.2 4.66 4.8 4.8 ;
			LAYER M1 ;
			RECT 1.2 4.3 4.8 4.66 ;
			LAYER M1 ;
			RECT 1.2 4.2 2.08 4.3 ;
			LAYER M1 ;
			RECT 4.2 4.2 4.8 4.3 ;
		END
	END in1
	PIN in2
		DIRECTION input ;
		PORT
			LAYER M1 ;
			RECT 0.2 4.2 0.8 4.8 ;
		END
	END in2
	PIN GND
		DIRECTION inout ;
		USE GROUND ;
		SHAPE ABUTMENT ;
		PORT
			LAYER M1 ;
			RECT 0.26 1.3 0.74 2.42 ;
			LAYER M1 ;
			RECT 2.26 1.3 2.74 2.42 ;
			LAYER M1 ;
			RECT 0.34 0.7 0.68 1.3 ;
			LAYER M1 ;
			RECT 2.32 0.7 2.68 1.3 ;
			LAYER M1 ;
			RECT 0 -0.7 9 0.7 ;
		END
	END GND
	PIN VDD
		DIRECTION inout ;
		USE POWER ;
		SHAPE ABUTMENT ;
		PORT
			LAYER M1 ;
			RECT 0 9.3 9 10.7 ;
			LAYER M1 ;
			RECT 0.32 8.14 0.66 9.3 ;
			LAYER M1 ;
			RECT 5.28 8.14 5.64 9.3 ;
			LAYER M1 ;
			RECT 0.26 5.82 0.74 8.14 ;
			LAYER M1 ;
			RECT 5.22 5.82 5.7 8.14 ;
		END
	END VDD
	PIN in0
		DIRECTION input ;
		PORT
			LAYER M1 ;
			RECT 7.2 4.2 7.8 4.8 ;
		END
	END in0
	OBS
	END
END MMI_NOR3B
MACRO MMI_OA21B
	CLASS CORE ;
	FOREIGN MMI_OA21B 0 0 ;
	SIZE 6 BY 10 ;
	SYMMETRY X Y ;
	SITE CORE1 ;
	PIN out
		DIRECTION output ;
		PORT
			LAYER M1 ;
			RECT 4.32 5.98 4.8 7.94 ;
			LAYER M1 ;
			RECT 4.32 5.64 5.66 5.98 ;
			LAYER M1 ;
			RECT 4.32 5.62 4.8 5.64 ;
			LAYER M1 ;
			RECT 5.32 2.22 5.66 5.64 ;
			LAYER M1 ;
			RECT 5.26 1.1 5.74 2.22 ;
		END
	END out
	PIN in1
		DIRECTION input ;
		PORT
			LAYER M1 ;
			RECT 2.2 4.2 2.8 4.8 ;
		END
	END in1
	PIN in2
		DIRECTION input ;
		PORT
			LAYER M1 ;
			RECT 3.2 4.2 3.8 4.8 ;
		END
	END in2
	PIN GND
		DIRECTION inout ;
		USE GROUND ;
		SHAPE ABUTMENT ;
		PORT
			LAYER M1 ;
			RECT 2.26 1.1 2.74 2.22 ;
			LAYER M1 ;
			RECT 4.26 1.1 4.74 2.22 ;
			LAYER M1 ;
			RECT 2.34 0.7 2.7 1.1 ;
			LAYER M1 ;
			RECT 4.34 0.7 4.68 1.1 ;
			LAYER M1 ;
			RECT 0 -0.7 6 0.7 ;
		END
	END GND
	PIN VDD
		DIRECTION inout ;
		USE POWER ;
		SHAPE ABUTMENT ;
		PORT
			LAYER M1 ;
			RECT 0 9.3 6 10.7 ;
			LAYER M1 ;
			RECT 0.42 6.72 0.78 9.3 ;
			LAYER M1 ;
			RECT 3.34 7.94 3.7 9.3 ;
			LAYER M1 ;
			RECT 0.26 6.06 0.78 6.72 ;
			LAYER M1 ;
			RECT 0.26 5.62 0.74 6.06 ;
			LAYER M1 ;
			RECT 3.32 5.62 3.8 7.94 ;
		END
	END VDD
	PIN in0
		DIRECTION input ;
		PORT
			LAYER M1 ;
			RECT 0.2 4.2 0.9 4.8 ;
		END
	END in0
	OBS
		LAYER M1 ;
		RECT 1.32 5.62 1.8 7.94 ;
		LAYER M1 ;
		RECT 1.4 3.68 1.76 5.62 ;
		LAYER M1 ;
		RECT 4.2 3.68 4.8 3.8 ;
		LAYER M1 ;
		RECT 0.34 3.32 4.8 3.68 ;
		LAYER M1 ;
		RECT 0.34 2.22 0.7 3.32 ;
		LAYER M1 ;
		RECT 4.2 3.2 4.8 3.32 ;
		LAYER M1 ;
		RECT 1.32 2.6 3.66 2.96 ;
		LAYER M1 ;
		RECT 1.32 2.22 1.66 2.6 ;
		LAYER M1 ;
		RECT 3.3 2.22 3.66 2.6 ;
		LAYER M1 ;
		RECT 0.26 1.1 0.74 2.22 ;
		LAYER M1 ;
		RECT 1.26 1.1 1.74 2.22 ;
		LAYER M1 ;
		RECT 3.26 1.1 3.74 2.22 ;
	END
END MMI_OA21B
MACRO MMI_OA21C
	CLASS CORE ;
	FOREIGN MMI_OA21C 0 0 ;
	SIZE 7 BY 10 ;
	SYMMETRY X Y ;
	SITE CORE1 ;
	PIN in1
		DIRECTION input ;
		PORT
			LAYER M1 ;
			RECT 2.2 4.2 2.8 4.8 ;
		END
	END in1
	PIN out
		DIRECTION output ;
		PORT
			LAYER M1 ;
			RECT 4.42 6.48 4.9 8.8 ;
			LAYER M1 ;
			RECT 4.48 6.16 4.84 6.48 ;
			LAYER M1 ;
			RECT 4.48 5.8 5.66 6.16 ;
			LAYER M1 ;
			RECT 5.32 2.26 5.66 5.8 ;
			LAYER M1 ;
			RECT 5.26 1.14 5.74 2.26 ;
		END
	END out
	PIN in2
		DIRECTION input ;
		PORT
			LAYER M1 ;
			RECT 3.2 4.2 3.8 4.8 ;
		END
	END in2
	PIN GND
		DIRECTION inout ;
		USE GROUND ;
		SHAPE ABUTMENT ;
		PORT
			LAYER M1 ;
			RECT 2.26 1.1 2.74 2.62 ;
			LAYER M1 ;
			RECT 4.26 1.14 4.74 2.26 ;
			LAYER M1 ;
			RECT 6.26 1.14 6.74 2.26 ;
			LAYER M1 ;
			RECT 2.32 0.7 2.68 1.1 ;
			LAYER M1 ;
			RECT 4.32 0.7 4.66 1.14 ;
			LAYER M1 ;
			RECT 6.36 0.7 6.72 1.14 ;
			LAYER M1 ;
			RECT 0 -0.7 7 0.7 ;
		END
	END GND
	PIN in0
		DIRECTION input ;
		PORT
			LAYER M1 ;
			RECT 0.2 5.2 0.94 5.8 ;
		END
	END in0
	OBS
		LAYER M1 ;
		RECT 1.34 5.78 1.82 8.88 ;
		LAYER M1 ;
		RECT 1.36 5.46 1.72 5.78 ;
		LAYER M1 ;
		RECT 1.36 5.12 4.54 5.46 ;
		LAYER M1 ;
		RECT 1.36 3.94 1.72 5.12 ;
		LAYER M1 ;
		RECT 4.2 4.8 4.54 5.12 ;
		LAYER M1 ;
		RECT 4.2 4.2 4.8 4.8 ;
		LAYER M1 ;
		RECT 0.34 3.6 1.72 3.94 ;
		LAYER M1 ;
		RECT 0.34 2.62 0.7 3.6 ;
		LAYER M1 ;
		RECT 1.32 2.94 3.64 3.28 ;
		LAYER M1 ;
		RECT 1.32 2.62 1.66 2.94 ;
		LAYER M1 ;
		RECT 3.28 2.62 3.64 2.94 ;
		LAYER M1 ;
		RECT 0.26 1.1 0.74 2.62 ;
		LAYER M1 ;
		RECT 1.26 1.1 1.74 2.62 ;
		LAYER M1 ;
		RECT 3.26 1.1 3.74 2.62 ;
	END
END MMI_OA21C
MACRO MMI_OA22B
	CLASS CORE ;
	FOREIGN MMI_OA22B 0 0 ;
	SIZE 6 BY 10 ;
	SYMMETRY X Y ;
	SITE CORE1 ;
	PIN in1
		DIRECTION input ;
		PORT
			LAYER M1 ;
			RECT 0.2 5.2 0.8 5.8 ;
			LAYER M1 ;
			RECT 0.22 3.88 0.58 5.2 ;
			LAYER M1 ;
			RECT 2.52 3.88 3.12 4.12 ;
			LAYER M1 ;
			RECT 0.22 3.52 3.12 3.88 ;
		END
	END in1
	PIN out
		DIRECTION output ;
		PORT
			LAYER M1 ;
			RECT 5.2 6.98 5.68 8.9 ;
			LAYER M1 ;
			RECT 5.2 6.58 5.7 6.98 ;
			LAYER M1 ;
			RECT 5.34 2.84 5.7 6.58 ;
			LAYER M1 ;
			RECT 5.26 1.72 5.74 2.84 ;
		END
	END out
	PIN in2
		DIRECTION input ;
		PORT
			LAYER M1 ;
			RECT 2.5 4.8 3.1 5.18 ;
			LAYER M1 ;
			RECT 0.9 4.44 3.1 4.8 ;
			LAYER M1 ;
			RECT 0.9 4.2 1.5 4.44 ;
		END
	END in2
	PIN GND
		DIRECTION inout ;
		USE GROUND ;
		SHAPE ABUTMENT ;
		PORT
			LAYER M1 ;
			RECT 0.26 1.72 0.74 2.84 ;
			LAYER M1 ;
			RECT 4.26 1.72 4.74 2.84 ;
			LAYER M1 ;
			RECT 0.34 0.7 0.7 1.72 ;
			LAYER M1 ;
			RECT 4.32 0.7 4.66 1.72 ;
			LAYER M1 ;
			RECT 0 -0.7 6 0.7 ;
		END
	END GND
	PIN in3
		DIRECTION input ;
		PORT
			LAYER M1 ;
			RECT 3.86 4.2 4.8 4.8 ;
		END
	END in3
	PIN VDD
		DIRECTION inout ;
		USE POWER ;
		SHAPE ABUTMENT ;
		PORT
			LAYER M1 ;
			RECT 0 9.3 6 10.7 ;
			LAYER M1 ;
			RECT 0.38 8.9 0.74 9.3 ;
			LAYER M1 ;
			RECT 4.28 8.9 4.64 9.3 ;
			LAYER M1 ;
			RECT 0.28 6.58 0.76 8.9 ;
			LAYER M1 ;
			RECT 4.2 6.58 4.68 8.9 ;
		END
	END VDD
	PIN in0
		DIRECTION input ;
		PORT
			LAYER M1 ;
			RECT 1.2 5.2 1.82 5.8 ;
		END
	END in0
	OBS
		LAYER M1 ;
		RECT 2.24 6.8 2.72 8.9 ;
		LAYER M1 ;
		RECT 2.2 6.66 2.8 6.8 ;
		LAYER M1 ;
		RECT 2.2 6.24 2.82 6.66 ;
		LAYER M1 ;
		RECT 2.2 6.2 4.88 6.24 ;
		LAYER M1 ;
		RECT 2.46 6.08 4.88 6.2 ;
		LAYER M1 ;
		RECT 2.46 5.9 5.02 6.08 ;
		LAYER M1 ;
		RECT 4.42 5.48 5.02 5.9 ;
		LAYER M1 ;
		RECT 1.26 1.72 1.74 2.84 ;
		LAYER M1 ;
		RECT 2.26 2.6 2.74 2.84 ;
		LAYER M1 ;
		RECT 2.2 2 2.8 2.6 ;
		LAYER M1 ;
		RECT 2.26 1.72 2.74 2 ;
		LAYER M1 ;
		RECT 3.26 1.72 3.74 2.84 ;
		LAYER M1 ;
		RECT 1.32 1.4 1.66 1.72 ;
		LAYER M1 ;
		RECT 3.32 1.4 3.68 1.72 ;
		LAYER M1 ;
		RECT 1.32 1.04 3.68 1.4 ;
		LAYER M2 ;
		RECT 2.2 6.2 2.8 6.8 ;
		LAYER M2 ;
		RECT 2.28 2.6 2.7 6.2 ;
		LAYER M2 ;
		RECT 2.2 2 2.8 2.6 ;
	END
END MMI_OA22B
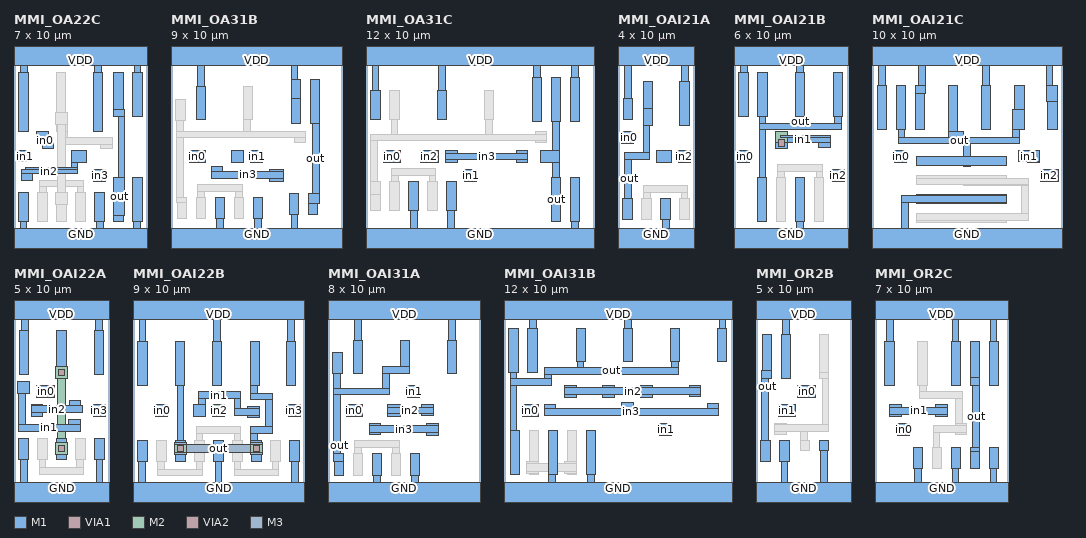
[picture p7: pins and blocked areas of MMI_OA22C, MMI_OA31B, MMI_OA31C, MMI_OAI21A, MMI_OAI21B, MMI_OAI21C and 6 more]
MACRO MMI_OA22C
	CLASS CORE ;
	FOREIGN MMI_OA22C 0 0 ;
	SIZE 7 BY 10 ;
	SYMMETRY X Y ;
	SITE CORE1 ;
	PIN in1
		DIRECTION input ;
		PORT
			LAYER M1 ;
			RECT 0.2 4.22 0.8 4.82 ;
		END
	END in1
	PIN out
		DIRECTION output ;
		PORT
			LAYER M1 ;
			RECT 5.26 6.98 5.74 8.94 ;
			LAYER M1 ;
			RECT 5.26 6.62 5.84 6.98 ;
			LAYER M1 ;
			RECT 5.48 3.42 5.84 6.62 ;
			LAYER M1 ;
			RECT 5.26 1.38 5.84 3.42 ;
			LAYER M1 ;
			RECT 5.26 1.1 5.74 1.38 ;
		END
	END out
	PIN in2
		DIRECTION input ;
		PORT
			LAYER M1 ;
			RECT 3 4.2 3.8 4.8 ;
			LAYER M1 ;
			RECT 3 3.9 3.32 4.2 ;
			LAYER M1 ;
			RECT 0.6 3.84 3.32 3.9 ;
			LAYER M1 ;
			RECT 0.38 3.58 3.32 3.84 ;
			LAYER M1 ;
			RECT 0.38 3.24 0.98 3.58 ;
		END
	END in2
	PIN GND
		DIRECTION inout ;
		USE GROUND ;
		SHAPE ABUTMENT ;
		PORT
			LAYER M1 ;
			RECT 0.26 1.1 0.74 2.62 ;
			LAYER M1 ;
			RECT 4.26 1.1 4.74 2.62 ;
			LAYER M1 ;
			RECT 6.26 1.1 6.74 3.42 ;
			LAYER M1 ;
			RECT 0.34 0.7 0.68 1.1 ;
			LAYER M1 ;
			RECT 4.34 0.7 4.7 1.1 ;
			LAYER M1 ;
			RECT 6.28 0.7 6.64 1.1 ;
			LAYER M1 ;
			RECT 0 -0.7 7 0.7 ;
		END
	END GND
	PIN in3
		DIRECTION input ;
		PORT
			LAYER M1 ;
			RECT 4.2 3.2 4.8 3.8 ;
		END
	END in3
	PIN VDD
		DIRECTION inout ;
		USE POWER ;
		SHAPE ABUTMENT ;
		PORT
			LAYER M1 ;
			RECT 0 9.3 7 10.7 ;
			LAYER M1 ;
			RECT 0.34 8.94 0.7 9.3 ;
			LAYER M1 ;
			RECT 0.26 5.84 0.74 8.94 ;
			LAYER M1 ;
			RECT 4.24 8.92 4.6 9.3 ;
			LAYER M1 ;
			RECT 6.32 8.94 6.66 9.3 ;
			LAYER M1 ;
			RECT 4.2 5.82 4.68 8.92 ;
			LAYER M1 ;
			RECT 6.26 6.62 6.74 8.94 ;
		END
	END VDD
	PIN in0
		DIRECTION input ;
		PORT
			LAYER M1 ;
			RECT 1.2 5.5 1.8 5.8 ;
			LAYER M1 ;
			RECT 1.2 5.2 2.08 5.5 ;
			LAYER M1 ;
			RECT 1.48 4.9 2.08 5.2 ;
		END
	END in0
	OBS
		LAYER M1 ;
		RECT 2.24 6.8 2.72 8.92 ;
		LAYER M1 ;
		RECT 2.2 6.2 2.8 6.8 ;
		LAYER M1 ;
		RECT 2.24 5.82 2.8 6.2 ;
		LAYER M1 ;
		RECT 2.44 5.5 2.8 5.82 ;
		LAYER M1 ;
		RECT 2.44 5.14 5.16 5.5 ;
		LAYER M1 ;
		RECT 4.56 4.9 5.16 5.14 ;
		LAYER M1 ;
		RECT 1.34 2.94 3.68 3.26 ;
		LAYER M1 ;
		RECT 1.34 2.62 1.7 2.94 ;
		LAYER M1 ;
		RECT 3.32 2.62 3.68 2.94 ;
		LAYER M1 ;
		RECT 1.26 1.1 1.74 2.62 ;
		LAYER M1 ;
		RECT 2.26 2.6 2.74 2.62 ;
		LAYER M1 ;
		RECT 2.2 2 2.8 2.6 ;
		LAYER M1 ;
		RECT 2.26 1.1 2.74 2 ;
		LAYER M1 ;
		RECT 3.26 1.1 3.74 2.62 ;
		LAYER M2 ;
		RECT 2.2 6.2 2.8 6.8 ;
		LAYER M2 ;
		RECT 2.28 2.6 2.7 6.2 ;
		LAYER M2 ;
		RECT 2.2 2 2.8 2.6 ;
	END
END MMI_OA22C
MACRO MMI_OA31B
	CLASS CORE ;
	FOREIGN MMI_OA31B 0 0 ;
	SIZE 9 BY 10 ;
	SYMMETRY X Y ;
	SITE CORE1 ;
	PIN out
		DIRECTION output ;
		PORT
			LAYER M1 ;
			RECT 7.34 6.22 7.82 8.54 ;
			LAYER M1 ;
			RECT 7.44 2.56 7.8 6.22 ;
			LAYER M1 ;
			RECT 7.22 2.02 7.8 2.56 ;
			LAYER M1 ;
			RECT 7.22 1.44 7.7 2.02 ;
		END
	END out
	PIN in1
		DIRECTION input ;
		PORT
			LAYER M1 ;
			RECT 4.2 4.2 4.8 4.8 ;
		END
	END in1
	PIN in2
		DIRECTION input ;
		PORT
			LAYER M1 ;
			RECT 3.2 4.2 3.8 4.8 ;
		END
	END in2
	PIN GND
		DIRECTION inout ;
		USE GROUND ;
		SHAPE ABUTMENT ;
		PORT
			LAYER M1 ;
			RECT 2.32 1.24 2.8 2.36 ;
			LAYER M1 ;
			RECT 4.32 1.24 4.8 2.36 ;
			LAYER M1 ;
			RECT 6.22 1.44 6.7 2.56 ;
			LAYER M1 ;
			RECT 2.38 0.7 2.74 1.24 ;
			LAYER M1 ;
			RECT 4.38 0.7 4.74 1.24 ;
			LAYER M1 ;
			RECT 6.32 0.7 6.66 1.44 ;
			LAYER M1 ;
			RECT 0 -0.7 9 0.7 ;
		END
	END GND
	PIN in3
		DIRECTION input ;
		PORT
			LAYER M1 ;
			RECT 2.12 3.72 2.72 3.96 ;
			LAYER M1 ;
			RECT 5.2 3.72 5.94 3.8 ;
			LAYER M1 ;
			RECT 2.12 3.36 5.94 3.72 ;
			LAYER M1 ;
			RECT 5.2 3.2 5.94 3.36 ;
		END
	END in3
	PIN VDD
		DIRECTION inout ;
		USE POWER ;
		SHAPE ABUTMENT ;
		PORT
			LAYER M1 ;
			RECT 0 9.3 9 10.7 ;
			LAYER M1 ;
			RECT 1.38 8.18 1.74 9.3 ;
			LAYER M1 ;
			RECT 6.32 8.54 6.68 9.3 ;
			LAYER M1 ;
			RECT 1.32 6.46 1.8 8.18 ;
			LAYER M1 ;
			RECT 6.32 7.56 6.82 8.54 ;
			LAYER M1 ;
			RECT 6.34 6.22 6.82 7.56 ;
		END
	END VDD
	PIN in0
		DIRECTION input ;
		PORT
			LAYER M1 ;
			RECT 0.98 4.2 1.8 4.8 ;
		END
	END in0
	OBS
		LAYER M1 ;
		RECT 0.26 6.42 0.74 7.52 ;
		LAYER M1 ;
		RECT 3.8 6.46 4.28 8.18 ;
		LAYER M1 ;
		RECT 0.3 5.84 0.66 6.42 ;
		LAYER M1 ;
		RECT 3.82 5.84 4.16 6.46 ;
		LAYER M1 ;
		RECT 0.3 5.5 7.1 5.84 ;
		LAYER M1 ;
		RECT 0.3 2.36 0.66 5.5 ;
		LAYER M1 ;
		RECT 6.5 5.24 7.1 5.5 ;
		LAYER M1 ;
		RECT 1.38 2.68 3.76 3.04 ;
		LAYER M1 ;
		RECT 1.38 2.36 1.74 2.68 ;
		LAYER M1 ;
		RECT 3.4 2.36 3.76 2.68 ;
		LAYER M1 ;
		RECT 0.3 2.1 0.8 2.36 ;
		LAYER M1 ;
		RECT 0.32 1.24 0.8 2.1 ;
		LAYER M1 ;
		RECT 1.32 1.24 1.8 2.36 ;
		LAYER M1 ;
		RECT 3.32 1.24 3.8 2.36 ;
	END
END MMI_OA31B
MACRO MMI_OA31C
	CLASS CORE ;
	FOREIGN MMI_OA31C 0 0 ;
	SIZE 12 BY 10 ;
	SYMMETRY X Y ;
	SITE CORE1 ;
	PIN out
		DIRECTION output ;
		PORT
			LAYER M1 ;
			RECT 9.76 6.36 10.24 8.68 ;
			LAYER M1 ;
			RECT 9.84 4.8 10.2 6.36 ;
			LAYER M1 ;
			RECT 9.2 4.2 10.2 4.8 ;
			LAYER M1 ;
			RECT 9.84 3.4 10.2 4.2 ;
			LAYER M1 ;
			RECT 9.76 1.08 10.24 3.4 ;
		END
	END out
	PIN in1
		DIRECTION input ;
		PORT
			LAYER M1 ;
			RECT 5.2 3.2 5.82 3.8 ;
		END
	END in1
	PIN in2
		DIRECTION input ;
		PORT
			LAYER M1 ;
			RECT 2.88 4.2 3.8 4.8 ;
		END
	END in2
	PIN GND
		DIRECTION inout ;
		USE GROUND ;
		SHAPE ABUTMENT ;
		PORT
			LAYER M1 ;
			RECT 2.26 1.66 2.74 3.18 ;
			LAYER M1 ;
			RECT 4.26 1.66 4.74 3.18 ;
			LAYER M1 ;
			RECT 2.34 0.7 2.7 1.66 ;
			LAYER M1 ;
			RECT 4.28 0.7 4.64 1.66 ;
			LAYER M1 ;
			RECT 10.76 1.08 11.24 3.4 ;
			LAYER M1 ;
			RECT 10.8 0.7 11.16 1.08 ;
			LAYER M1 ;
			RECT 0 -0.7 12 0.7 ;
		END
	END GND
	PIN in3
		DIRECTION input ;
		PORT
			LAYER M1 ;
			RECT 4.2 4.66 4.8 4.8 ;
			LAYER M1 ;
			RECT 7.92 4.66 8.52 4.8 ;
			LAYER M1 ;
			RECT 4.2 4.32 8.52 4.66 ;
			LAYER M1 ;
			RECT 4.2 4.2 4.8 4.32 ;
			LAYER M1 ;
			RECT 7.92 4.2 8.52 4.32 ;
		END
	END in3
	PIN VDD
		DIRECTION inout ;
		USE POWER ;
		SHAPE ABUTMENT ;
		PORT
			LAYER M1 ;
			RECT 0 9.3 12 10.7 ;
			LAYER M1 ;
			RECT 0.32 7.98 0.68 9.3 ;
			LAYER M1 ;
			RECT 3.8 7.98 4.16 9.3 ;
			LAYER M1 ;
			RECT 8.8 8.68 9.16 9.3 ;
			LAYER M1 ;
			RECT 10.82 8.68 11.18 9.3 ;
			LAYER M1 ;
			RECT 0.26 6.46 0.74 7.98 ;
			LAYER M1 ;
			RECT 3.74 6.46 4.22 7.98 ;
			LAYER M1 ;
			RECT 8.76 6.36 9.24 8.68 ;
			LAYER M1 ;
			RECT 10.76 6.36 11.24 8.68 ;
		END
	END VDD
	PIN in0
		DIRECTION input ;
		PORT
			LAYER M1 ;
			RECT 0.92 4.2 1.8 4.8 ;
		END
	END in0
	OBS
		LAYER M1 ;
		RECT 1.26 6.46 1.74 7.98 ;
		LAYER M1 ;
		RECT 6.22 6.46 6.7 7.98 ;
		LAYER M1 ;
		RECT 1.32 5.66 1.66 6.46 ;
		LAYER M1 ;
		RECT 6.3 5.66 6.64 6.46 ;
		LAYER M1 ;
		RECT 8.92 5.66 9.52 5.84 ;
		LAYER M1 ;
		RECT 0.24 5.32 9.52 5.66 ;
		LAYER M1 ;
		RECT 0.24 3.18 0.6 5.32 ;
		LAYER M1 ;
		RECT 8.92 5.24 9.52 5.32 ;
		LAYER M1 ;
		RECT 1.34 3.5 3.66 3.86 ;
		LAYER M1 ;
		RECT 1.34 3.18 1.7 3.5 ;
		LAYER M1 ;
		RECT 3.32 3.18 3.66 3.5 ;
		LAYER M1 ;
		RECT 0.24 2.5 0.74 3.18 ;
		LAYER M1 ;
		RECT 0.26 1.66 0.74 2.5 ;
		LAYER M1 ;
		RECT 1.26 1.66 1.74 3.18 ;
		LAYER M1 ;
		RECT 3.26 1.66 3.74 3.18 ;
	END
END MMI_OA31C
MACRO MMI_OAI21A
	CLASS CORE ;
	FOREIGN MMI_OAI21A 0 0 ;
	SIZE 4 BY 10 ;
	SYMMETRY X Y ;
	SITE CORE1 ;
	PIN in1
		DIRECTION input ;
		PORT
			LAYER M1 ;
			RECT 2 4.2 2.8 4.8 ;
		END
	END in1
	PIN out
		DIRECTION output ;
		PORT
			LAYER M1 ;
			RECT 1.34 7.02 1.82 8.46 ;
			LAYER M1 ;
			RECT 1.32 6.14 1.82 7.02 ;
			LAYER M1 ;
			RECT 1.32 4.72 1.68 6.14 ;
			LAYER M1 ;
			RECT 0.34 4.36 1.68 4.72 ;
			LAYER M1 ;
			RECT 0.34 2.3 0.7 4.36 ;
			LAYER M1 ;
			RECT 0.26 1.18 0.74 2.3 ;
		END
	END out
	PIN in2
		DIRECTION input ;
		PORT
			LAYER M1 ;
			RECT 3.16 4.2 3.8 4.8 ;
		END
	END in2
	PIN GND
		DIRECTION inout ;
		USE GROUND ;
		SHAPE ABUTMENT ;
		PORT
			LAYER M1 ;
			RECT 2.26 1.18 2.74 2.3 ;
			LAYER M1 ;
			RECT 2.34 0.7 2.7 1.18 ;
			LAYER M1 ;
			RECT 0 -0.7 4 0.7 ;
		END
	END GND
	PIN VDD
		DIRECTION inout ;
		USE POWER ;
		SHAPE ABUTMENT ;
		PORT
			LAYER M1 ;
			RECT 0 9.3 4 10.7 ;
			LAYER M1 ;
			RECT 0.36 7.56 0.72 9.3 ;
			LAYER M1 ;
			RECT 3.34 8.46 3.7 9.3 ;
			LAYER M1 ;
			RECT 0.28 6.46 0.76 7.56 ;
			LAYER M1 ;
			RECT 3.26 6.14 3.74 8.46 ;
		END
	END VDD
	PIN in0
		DIRECTION input ;
		PORT
			LAYER M1 ;
			RECT 0.2 5.2 0.8 5.8 ;
		END
	END in0
	OBS
		LAYER M1 ;
		RECT 1.34 2.62 3.68 2.98 ;
		LAYER M1 ;
		RECT 1.34 2.3 1.7 2.62 ;
		LAYER M1 ;
		RECT 3.32 2.3 3.68 2.62 ;
		LAYER M1 ;
		RECT 1.26 1.18 1.74 2.3 ;
		LAYER M1 ;
		RECT 3.26 1.18 3.74 2.3 ;
	END
END MMI_OAI21A
MACRO MMI_OAI21B
	CLASS CORE ;
	FOREIGN MMI_OAI21B 0 0 ;
	SIZE 6 BY 10 ;
	SYMMETRY X Y ;
	SITE CORE1 ;
	PIN in1
		DIRECTION input ;
		PORT
			LAYER M1 ;
			RECT 2.44 5.52 5.06 5.58 ;
			LAYER M1 ;
			RECT 2.2 5.22 5.06 5.52 ;
			LAYER M1 ;
			RECT 2.2 4.9 2.8 5.22 ;
			LAYER M1 ;
			RECT 4.46 4.98 5.06 5.22 ;
			LAYER VIA1 ;
			RECT 2.32 5.04 2.68 5.4 ;
			LAYER M2 ;
			RECT 2.2 4.92 2.8 5.8 ;
		END
	END in1
	PIN out
		DIRECTION output ;
		PORT
			LAYER M1 ;
			RECT 1.26 6.58 1.74 8.9 ;
			LAYER M1 ;
			RECT 5.22 6.58 5.7 8.9 ;
			LAYER M1 ;
			RECT 1.32 6.26 1.68 6.58 ;
			LAYER M1 ;
			RECT 5.3 6.26 5.66 6.58 ;
			LAYER M1 ;
			RECT 1.32 5.9 5.66 6.26 ;
			LAYER M1 ;
			RECT 1.32 3.38 1.68 5.9 ;
			LAYER M1 ;
			RECT 1.24 1.06 1.72 3.38 ;
		END
	END out
	PIN in2
		DIRECTION input ;
		PORT
			LAYER M1 ;
			RECT 5.2 3.2 5.8 3.8 ;
		END
	END in2
	PIN GND
		DIRECTION inout ;
		USE GROUND ;
		SHAPE ABUTMENT ;
		PORT
			LAYER M1 ;
			RECT 3.24 1.06 3.72 3.38 ;
			LAYER M1 ;
			RECT 3.3 0.7 3.66 1.06 ;
			LAYER M1 ;
			RECT 0 -0.7 6 0.7 ;
		END
	END GND
	PIN VDD
		DIRECTION inout ;
		USE POWER ;
		SHAPE ABUTMENT ;
		PORT
			LAYER M1 ;
			RECT 0 9.3 6 10.7 ;
			LAYER M1 ;
			RECT 0.34 8.9 0.7 9.3 ;
			LAYER M1 ;
			RECT 3.3 8.9 3.66 9.3 ;
			LAYER M1 ;
			RECT 0.26 6.58 0.74 8.9 ;
			LAYER M1 ;
			RECT 3.24 6.58 3.72 8.9 ;
		END
	END VDD
	PIN in0
		DIRECTION input ;
		PORT
			LAYER M1 ;
			RECT 0.2 4.2 0.82 4.8 ;
		END
	END in0
	OBS
		LAYER M1 ;
		RECT 2.28 3.7 4.66 4.06 ;
		LAYER M1 ;
		RECT 2.28 3.38 2.64 3.7 ;
		LAYER M1 ;
		RECT 4.32 3.38 4.66 3.7 ;
		LAYER M1 ;
		RECT 2.24 1.06 2.72 3.38 ;
		LAYER M1 ;
		RECT 4.24 1.06 4.72 3.38 ;
	END
END MMI_OAI21B
MACRO MMI_OAI21C
	CLASS CORE ;
	FOREIGN MMI_OAI21C 0 0 ;
	SIZE 10 BY 10 ;
	SYMMETRY X Y ;
	SITE CORE1 ;
	PIN in1
		DIRECTION input ;
		PORT
			LAYER M1 ;
			RECT 7.7 4.8 8.3 4.84 ;
			LAYER M1 ;
			RECT 7.7 4.24 8.8 4.8 ;
			LAYER M1 ;
			RECT 8.16 4.2 8.8 4.24 ;
		END
	END in1
	PIN out
		DIRECTION output ;
		PORT
			LAYER M1 ;
			RECT 1.3 5.9 1.78 8.22 ;
			LAYER M1 ;
			RECT 1.38 5.52 1.72 5.9 ;
			LAYER M1 ;
			RECT 4.04 5.82 4.52 8.22 ;
			LAYER M1 ;
			RECT 7.52 6.96 8 8.22 ;
			LAYER M1 ;
			RECT 7.42 5.9 8 6.96 ;
			LAYER M1 ;
			RECT 4.04 5.52 4.82 5.82 ;
			LAYER M1 ;
			RECT 7.42 5.52 7.78 5.9 ;
			LAYER M1 ;
			RECT 1.38 5.16 7.78 5.52 ;
			LAYER M1 ;
			RECT 4.82 4.5 5.16 5.16 ;
			LAYER M1 ;
			RECT 2.36 4.02 7.08 4.5 ;
			LAYER M1 ;
			RECT 4.82 3.96 5.16 4.02 ;
		END
	END out
	PIN in2
		DIRECTION input ;
		PORT
			LAYER M1 ;
			RECT 8.88 3.2 9.8 3.8 ;
		END
	END in2
	PIN GND
		DIRECTION inout ;
		USE GROUND ;
		SHAPE ABUTMENT ;
		PORT
			LAYER M1 ;
			RECT 2.36 2.46 7.08 2.5 ;
			LAYER M1 ;
			RECT 1.56 2.1 7.08 2.46 ;
			LAYER M1 ;
			RECT 1.56 0.7 1.92 2.1 ;
			LAYER M1 ;
			RECT 2.36 2.02 7.08 2.1 ;
			LAYER M1 ;
			RECT 0 -0.7 10 0.7 ;
		END
	END GND
	PIN VDD
		DIRECTION inout ;
		USE POWER ;
		SHAPE ABUTMENT ;
		PORT
			LAYER M1 ;
			RECT 0 9.3 10 10.7 ;
			LAYER M1 ;
			RECT 0.36 8.22 0.72 9.3 ;
			LAYER M1 ;
			RECT 2.46 8.22 2.82 9.3 ;
			LAYER M1 ;
			RECT 5.82 8.22 6.16 9.3 ;
			LAYER M1 ;
			RECT 9.16 8.22 9.52 9.3 ;
			LAYER M1 ;
			RECT 0.3 5.9 0.78 8.22 ;
			LAYER M1 ;
			RECT 2.3 7.82 2.82 8.22 ;
			LAYER M1 ;
			RECT 2.3 5.9 2.78 7.82 ;
			LAYER M1 ;
			RECT 5.78 5.9 6.26 8.22 ;
			LAYER M1 ;
			RECT 9.16 7.42 9.74 8.22 ;
			LAYER M1 ;
			RECT 9.26 5.9 9.74 7.42 ;
		END
	END VDD
	PIN in0
		DIRECTION input ;
		PORT
			LAYER M1 ;
			RECT 1.2 4.2 1.8 4.8 ;
		END
	END in0
	OBS
		LAYER M1 ;
		RECT 2.36 3.32 7.08 3.5 ;
		LAYER M1 ;
		RECT 2.36 3.02 8.24 3.32 ;
		LAYER M1 ;
		RECT 4.82 2.96 8.24 3.02 ;
		LAYER M1 ;
		RECT 7.88 1.5 8.24 2.96 ;
		LAYER M1 ;
		RECT 2.36 1.14 8.24 1.5 ;
		LAYER M1 ;
		RECT 2.36 1.02 7.08 1.14 ;
	END
END MMI_OAI21C
MACRO MMI_OAI22A
	CLASS CORE ;
	FOREIGN MMI_OAI22A 0 0 ;
	SIZE 5 BY 10 ;
	SYMMETRY X Y ;
	SITE CORE1 ;
	PIN in1
		DIRECTION input ;
		PORT
			LAYER M1 ;
			RECT 0.2 5.42 0.8 6.02 ;
			LAYER M1 ;
			RECT 0.24 3.78 0.6 5.42 ;
			LAYER M1 ;
			RECT 2.88 3.78 3.48 4.02 ;
			LAYER M1 ;
			RECT 0.24 3.42 3.48 3.78 ;
		END
	END in1
	PIN out
		DIRECTION output ;
		PORT
			LAYER M1 ;
			RECT 2.26 6.8 2.74 8.72 ;
			LAYER M1 ;
			RECT 2.2 6.2 2.8 6.8 ;
			LAYER M1 ;
			RECT 2.26 2.8 2.74 3.02 ;
			LAYER M1 ;
			RECT 2.2 2.2 2.8 2.8 ;
			LAYER M1 ;
			RECT 2.26 1.9 2.74 2.2 ;
			LAYER VIA1 ;
			RECT 2.32 6.32 2.68 6.68 ;
			LAYER VIA1 ;
			RECT 2.32 2.32 2.68 2.68 ;
			LAYER M2 ;
			RECT 2.2 6.2 2.8 6.8 ;
			LAYER M2 ;
			RECT 2.28 2.8 2.7 6.2 ;
			LAYER M2 ;
			RECT 2.2 2.2 2.8 2.8 ;
		END
	END out
	PIN in2
		DIRECTION input ;
		PORT
			LAYER M1 ;
			RECT 0.92 4.74 1.52 4.8 ;
			LAYER M1 ;
			RECT 2.92 4.74 3.52 5.02 ;
			LAYER M1 ;
			RECT 0.92 4.38 3.6 4.74 ;
			LAYER M1 ;
			RECT 0.92 4.2 1.52 4.38 ;
		END
	END in2
	PIN GND
		DIRECTION inout ;
		USE GROUND ;
		SHAPE ABUTMENT ;
		PORT
			LAYER M1 ;
			RECT 0.26 1.9 0.74 3.02 ;
			LAYER M1 ;
			RECT 4.26 1.9 4.74 3.02 ;
			LAYER M1 ;
			RECT 0.34 0.7 0.7 1.9 ;
			LAYER M1 ;
			RECT 4.32 0.7 4.66 1.9 ;
			LAYER M1 ;
			RECT 0 -0.7 5 0.7 ;
		END
	END GND
	PIN in3
		DIRECTION input ;
		PORT
			LAYER M1 ;
			RECT 4.2 4.2 4.8 4.8 ;
		END
	END in3
	PIN VDD
		DIRECTION inout ;
		USE POWER ;
		SHAPE ABUTMENT ;
		PORT
			LAYER M1 ;
			RECT 0 9.3 5 10.7 ;
			LAYER M1 ;
			RECT 0.38 8.72 0.74 9.3 ;
			LAYER M1 ;
			RECT 4.28 8.72 4.64 9.3 ;
			LAYER M1 ;
			RECT 0.3 6.4 0.78 8.72 ;
			LAYER M1 ;
			RECT 4.22 6.4 4.7 8.72 ;
		END
	END VDD
	PIN in0
		DIRECTION input ;
		PORT
			LAYER M1 ;
			RECT 1.2 5.2 2.12 5.8 ;
		END
	END in0
	OBS
		LAYER M1 ;
		RECT 1.26 1.9 1.74 3.02 ;
		LAYER M1 ;
		RECT 3.26 1.9 3.74 3.02 ;
		LAYER M1 ;
		RECT 1.32 1.5 1.66 1.9 ;
		LAYER M1 ;
		RECT 3.28 1.5 3.64 1.9 ;
		LAYER M1 ;
		RECT 1.32 1.14 3.64 1.5 ;
	END
END MMI_OAI22A
MACRO MMI_OAI22B
	CLASS CORE ;
	FOREIGN MMI_OAI22B 0 0 ;
	SIZE 9 BY 10 ;
	SYMMETRY X Y ;
	SITE CORE1 ;
	PIN in1
		DIRECTION input ;
		PORT
			LAYER M1 ;
			RECT 3.44 5.12 5.66 5.48 ;
			LAYER M1 ;
			RECT 3.44 4.8 3.8 5.12 ;
			LAYER M1 ;
			RECT 3.2 4.2 3.8 4.8 ;
			LAYER M1 ;
			RECT 5.32 4.6 5.66 5.12 ;
			LAYER M1 ;
			RECT 6.04 4.6 6.64 4.72 ;
			LAYER M1 ;
			RECT 5.32 4.24 6.64 4.6 ;
			LAYER M1 ;
			RECT 6.04 4.12 6.64 4.24 ;
		END
	END in1
	PIN out
		DIRECTION output ;
		PORT
			LAYER M1 ;
			RECT 2.22 5.8 2.7 8.12 ;
			LAYER M1 ;
			RECT 6.16 5.8 6.64 8.12 ;
			LAYER M1 ;
			RECT 2.32 2.92 2.66 5.8 ;
			LAYER M1 ;
			RECT 6.2 5.42 6.56 5.8 ;
			LAYER M1 ;
			RECT 6.2 5.06 7.32 5.42 ;
			LAYER M1 ;
			RECT 6.96 3.64 7.32 5.06 ;
			LAYER M1 ;
			RECT 6.2 3.28 7.32 3.64 ;
			LAYER M1 ;
			RECT 6.2 2.92 6.56 3.28 ;
			LAYER M1 ;
			RECT 2.26 2.8 2.74 2.92 ;
			LAYER M1 ;
			RECT 6.2 2.8 6.74 2.92 ;
			LAYER M1 ;
			RECT 2.2 2.2 2.8 2.8 ;
			LAYER M1 ;
			RECT 6.2 2.2 6.8 2.8 ;
			LAYER M1 ;
			RECT 2.26 1.8 2.74 2.2 ;
			LAYER M1 ;
			RECT 6.26 1.8 6.74 2.2 ;
			LAYER VIA1 ;
			RECT 2.32 2.32 2.68 2.68 ;
			LAYER VIA1 ;
			RECT 6.32 2.32 6.68 2.68 ;
			LAYER M2 ;
			RECT 2.2 2.2 2.8 2.8 ;
			LAYER M2 ;
			RECT 6.2 2.2 6.8 2.8 ;
			LAYER VIA2 ;
			RECT 2.32 2.32 2.68 2.68 ;
			LAYER VIA2 ;
			RECT 6.32 2.32 6.68 2.68 ;
			LAYER M3 ;
			RECT 2.2 2.7 2.8 2.8 ;
			LAYER M3 ;
			RECT 6.2 2.7 6.8 2.8 ;
			LAYER M3 ;
			RECT 2.2 2.28 6.8 2.7 ;
			LAYER M3 ;
			RECT 2.2 2.2 2.8 2.28 ;
			LAYER M3 ;
			RECT 6.2 2.2 6.8 2.28 ;
		END
	END out
	PIN in2
		DIRECTION input ;
		PORT
			LAYER M1 ;
			RECT 4.2 4.2 4.8 4.8 ;
			LAYER VIA1 ;
			RECT 4.32 4.32 4.68 4.68 ;
			LAYER M2 ;
			RECT 4.2 4.2 4.8 4.8 ;
		END
	END in2
	PIN GND
		DIRECTION inout ;
		USE GROUND ;
		SHAPE ABUTMENT ;
		PORT
			LAYER M1 ;
			RECT 0.26 1.8 0.74 2.92 ;
			LAYER M1 ;
			RECT 4.26 1.8 4.74 2.92 ;
			LAYER M1 ;
			RECT 8.26 1.8 8.74 2.92 ;
			LAYER M1 ;
			RECT 0.28 0.7 0.64 1.8 ;
			LAYER M1 ;
			RECT 4.32 0.7 4.68 1.8 ;
			LAYER M1 ;
			RECT 8.34 0.7 8.7 1.8 ;
			LAYER M1 ;
			RECT 0 -0.7 9 0.7 ;
		END
	END GND
	PIN in3
		DIRECTION input ;
		PORT
			LAYER M1 ;
			RECT 8.2 4.2 8.8 4.8 ;
		END
	END in3
	PIN VDD
		DIRECTION inout ;
		USE POWER ;
		SHAPE ABUTMENT ;
		PORT
			LAYER M1 ;
			RECT 0 9.3 9 10.7 ;
			LAYER M1 ;
			RECT 0.32 8.12 0.66 9.3 ;
			LAYER M1 ;
			RECT 4.26 8.12 4.62 9.3 ;
			LAYER M1 ;
			RECT 8.12 8.12 8.48 9.3 ;
			LAYER M1 ;
			RECT 0.26 5.8 0.74 8.12 ;
			LAYER M1 ;
			RECT 4.2 5.8 4.68 8.12 ;
			LAYER M1 ;
			RECT 8.08 5.8 8.56 8.12 ;
		END
	END VDD
	PIN in0
		DIRECTION input ;
		PORT
			LAYER M1 ;
			RECT 1.2 4.2 1.8 4.8 ;
		END
	END in0
	OBS
		LAYER M1 ;
		RECT 3.32 3.28 5.68 3.64 ;
		LAYER M1 ;
		RECT 3.32 2.92 3.68 3.28 ;
		LAYER M1 ;
		RECT 5.32 2.92 5.68 3.28 ;
		LAYER M1 ;
		RECT 1.26 1.8 1.74 2.92 ;
		LAYER M1 ;
		RECT 3.26 1.8 3.74 2.92 ;
		LAYER M1 ;
		RECT 5.26 1.8 5.74 2.92 ;
		LAYER M1 ;
		RECT 7.26 1.8 7.74 2.92 ;
		LAYER M1 ;
		RECT 1.28 1.42 1.64 1.8 ;
		LAYER M1 ;
		RECT 3.32 1.42 3.68 1.8 ;
		LAYER M1 ;
		RECT 1.28 1.06 3.68 1.42 ;
		LAYER M1 ;
		RECT 5.32 1.42 5.68 1.8 ;
		LAYER M1 ;
		RECT 7.32 1.42 7.68 1.8 ;
		LAYER M1 ;
		RECT 5.32 1.06 7.68 1.42 ;
	END
END MMI_OAI22B
MACRO MMI_OAI31A
	CLASS CORE ;
	FOREIGN MMI_OAI31A 0 0 ;
	SIZE 8 BY 10 ;
	SYMMETRY X Y ;
	SITE CORE1 ;
	PIN in1
		DIRECTION input ;
		PORT
			LAYER M1 ;
			RECT 4.2 5.2 4.8 5.8 ;
		END
	END in1
	PIN out
		DIRECTION output ;
		PORT
			LAYER M1 ;
			RECT 0.26 6.46 0.74 7.56 ;
			LAYER M1 ;
			RECT 3.8 6.82 4.28 8.18 ;
			LAYER M1 ;
			RECT 2.86 6.46 4.28 6.82 ;
			LAYER M1 ;
			RECT 0.3 5.66 0.66 6.46 ;
			LAYER M1 ;
			RECT 2.86 5.66 3.22 6.46 ;
			LAYER M1 ;
			RECT 0.3 5.32 3.22 5.66 ;
			LAYER M1 ;
			RECT 0.3 2.22 0.66 5.32 ;
			LAYER M1 ;
			RECT 0.3 1.8 0.8 2.22 ;
			LAYER M1 ;
			RECT 0.32 1.1 0.8 1.8 ;
		END
	END out
	PIN in2
		DIRECTION input ;
		PORT
			LAYER M1 ;
			RECT 3.14 4.68 3.8 4.8 ;
			LAYER M1 ;
			RECT 4.94 4.68 5.54 4.82 ;
			LAYER M1 ;
			RECT 3.14 4.32 5.54 4.68 ;
			LAYER M1 ;
			RECT 3.14 4.2 3.8 4.32 ;
			LAYER M1 ;
			RECT 4.94 4.22 5.54 4.32 ;
		END
	END in2
	PIN GND
		DIRECTION inout ;
		USE GROUND ;
		SHAPE ABUTMENT ;
		PORT
			LAYER M1 ;
			RECT 2.32 1.1 2.8 2.22 ;
			LAYER M1 ;
			RECT 4.32 1.1 4.8 2.22 ;
			LAYER M1 ;
			RECT 2.38 0.7 2.74 1.1 ;
			LAYER M1 ;
			RECT 4.38 0.7 4.74 1.1 ;
			LAYER M1 ;
			RECT 0 -0.7 8 0.7 ;
		END
	END GND
	PIN VDD
		DIRECTION inout ;
		USE POWER ;
		SHAPE ABUTMENT ;
		PORT
			LAYER M1 ;
			RECT 0 9.3 8 10.7 ;
			LAYER M1 ;
			RECT 1.38 8.18 1.74 9.3 ;
			LAYER M1 ;
			RECT 6.34 8.18 6.7 9.3 ;
			LAYER M1 ;
			RECT 1.32 6.46 1.8 8.18 ;
			LAYER M1 ;
			RECT 6.28 6.46 6.76 8.18 ;
		END
	END VDD
	PIN in3
		DIRECTION input ;
		PORT
			LAYER M1 ;
			RECT 2.16 3.7 2.76 3.82 ;
			LAYER M1 ;
			RECT 5.2 3.7 5.82 3.8 ;
			LAYER M1 ;
			RECT 2.16 3.34 5.82 3.7 ;
			LAYER M1 ;
			RECT 2.16 3.22 2.76 3.34 ;
			LAYER M1 ;
			RECT 5.2 3.2 5.82 3.34 ;
		END
	END in3
	PIN in0
		DIRECTION input ;
		PORT
			LAYER M1 ;
			RECT 0.98 4.2 1.8 4.8 ;
		END
	END in0
	OBS
		LAYER M1 ;
		RECT 1.42 2.54 3.74 2.9 ;
		LAYER M1 ;
		RECT 1.42 2.22 1.78 2.54 ;
		LAYER M1 ;
		RECT 3.38 2.22 3.74 2.54 ;
		LAYER M1 ;
		RECT 1.32 1.1 1.8 2.22 ;
		LAYER M1 ;
		RECT 3.32 1.1 3.8 2.22 ;
	END
END MMI_OAI31A
MACRO MMI_OAI31B
	CLASS CORE ;
	FOREIGN MMI_OAI31B 0 0 ;
	SIZE 12 BY 10 ;
	SYMMETRY X Y ;
	SITE CORE1 ;
	PIN out
		DIRECTION output ;
		PORT
			LAYER M1 ;
			RECT 0.26 6.48 0.74 8.8 ;
			LAYER M1 ;
			RECT 3.8 7.08 4.28 8.8 ;
			LAYER M1 ;
			RECT 8.76 7.08 9.24 8.8 ;
			LAYER M1 ;
			RECT 3.86 6.76 4.2 7.08 ;
			LAYER M1 ;
			RECT 8.82 6.76 9.18 7.08 ;
			LAYER M1 ;
			RECT 0.32 6.16 0.66 6.48 ;
			LAYER M1 ;
			RECT 2.14 6.42 9.18 6.76 ;
			LAYER M1 ;
			RECT 2.14 6.16 2.5 6.42 ;
			LAYER M1 ;
			RECT 0.32 5.82 2.5 6.16 ;
			LAYER M1 ;
			RECT 0.32 3.44 0.66 5.82 ;
			LAYER M1 ;
			RECT 0.32 1.12 0.8 3.44 ;
		END
	END out
	PIN in1
		DIRECTION input ;
		PORT
			LAYER M1 ;
			RECT 8.2 3.2 8.8 3.8 ;
		END
	END in1
	PIN in2
		DIRECTION input ;
		PORT
			LAYER M1 ;
			RECT 3.2 5.7 3.8 5.8 ;
			LAYER M1 ;
			RECT 5.2 5.7 5.8 5.8 ;
			LAYER M1 ;
			RECT 7.2 5.7 7.8 5.8 ;
			LAYER M1 ;
			RECT 9.76 5.7 10.36 5.84 ;
			LAYER M1 ;
			RECT 3.2 5.34 10.36 5.7 ;
			LAYER M1 ;
			RECT 3.2 5.2 3.8 5.34 ;
			LAYER M1 ;
			RECT 5.2 5.2 5.8 5.34 ;
			LAYER M1 ;
			RECT 7.2 5.2 7.8 5.34 ;
			LAYER M1 ;
			RECT 9.76 5.24 10.36 5.34 ;
		END
	END in2
	PIN GND
		DIRECTION inout ;
		USE GROUND ;
		SHAPE ABUTMENT ;
		PORT
			LAYER M1 ;
			RECT 2.32 1.12 2.8 3.44 ;
			LAYER M1 ;
			RECT 4.32 1.12 4.8 3.44 ;
			LAYER M1 ;
			RECT 2.34 0.7 2.7 1.12 ;
			LAYER M1 ;
			RECT 4.38 0.7 4.74 1.12 ;
			LAYER M1 ;
			RECT 0 -0.7 12 0.7 ;
		END
	END GND
	PIN in3
		DIRECTION input ;
		PORT
			LAYER M1 ;
			RECT 2.12 4.62 2.72 4.82 ;
			LAYER M1 ;
			RECT 6.2 4.62 6.8 4.9 ;
			LAYER M1 ;
			RECT 10.7 4.62 11.3 4.86 ;
			LAYER M1 ;
			RECT 2.12 4.26 11.3 4.62 ;
			LAYER M1 ;
			RECT 2.12 4.22 2.72 4.26 ;
		END
	END in3
	PIN VDD
		DIRECTION inout ;
		USE POWER ;
		SHAPE ABUTMENT ;
		PORT
			LAYER M1 ;
			RECT 0 9.3 12 10.7 ;
			LAYER M1 ;
			RECT 1.34 8.8 1.7 9.3 ;
			LAYER M1 ;
			RECT 6.34 8.8 6.7 9.3 ;
			LAYER M1 ;
			RECT 11.32 8.8 11.68 9.3 ;
			LAYER M1 ;
			RECT 1.26 6.48 1.74 8.8 ;
			LAYER M1 ;
			RECT 6.28 7.08 6.76 8.8 ;
			LAYER M1 ;
			RECT 11.24 7.08 11.72 8.8 ;
		END
	END VDD
	PIN in0
		DIRECTION input ;
		PORT
			LAYER M1 ;
			RECT 0.98 4.2 1.8 4.8 ;
		END
	END in0
	OBS
		LAYER M1 ;
		RECT 1.32 1.8 1.8 3.44 ;
		LAYER M1 ;
		RECT 1.2 1.2 1.8 1.8 ;
		LAYER M1 ;
		RECT 1.32 1.12 1.8 1.2 ;
		LAYER M1 ;
		RECT 3.32 1.8 3.8 3.44 ;
		LAYER M1 ;
		RECT 3.2 1.2 3.8 1.8 ;
		LAYER M1 ;
		RECT 3.32 1.12 3.8 1.2 ;
		LAYER M2 ;
		RECT 1.2 1.2 1.8 1.8 ;
		LAYER M2 ;
		RECT 3.2 1.2 3.8 1.8 ;
		LAYER M3 ;
		RECT 1.2 1.7 1.8 1.8 ;
		LAYER M3 ;
		RECT 3.2 1.7 3.8 1.8 ;
		LAYER M3 ;
		RECT 1.2 1.28 3.8 1.7 ;
		LAYER M3 ;
		RECT 1.2 1.2 1.8 1.28 ;
		LAYER M3 ;
		RECT 3.2 1.2 3.8 1.28 ;
	END
END MMI_OAI31B
MACRO MMI_OR2B
	CLASS CORE ;
	FOREIGN MMI_OR2B 0 0 ;
	SIZE 5 BY 10 ;
	SYMMETRY X Y ;
	SITE CORE1 ;
	PIN in1
		DIRECTION input ;
		PORT
			LAYER M1 ;
			RECT 1.2 4.2 2.08 4.8 ;
		END
	END in1
	PIN out
		DIRECTION output ;
		PORT
			LAYER M1 ;
			RECT 0.32 6.6 0.8 8.48 ;
			LAYER M1 ;
			RECT 0.3 6.16 0.8 6.6 ;
			LAYER M1 ;
			RECT 0.3 2.92 0.66 6.16 ;
			LAYER M1 ;
			RECT 0.26 1.8 0.74 2.92 ;
		END
	END out
	PIN GND
		DIRECTION inout ;
		USE GROUND ;
		SHAPE ABUTMENT ;
		PORT
			LAYER M1 ;
			RECT 1.26 1.8 1.74 2.92 ;
			LAYER M1 ;
			RECT 3.32 2.4 3.8 2.92 ;
			LAYER M1 ;
			RECT 1.32 0.7 1.66 1.8 ;
			LAYER M1 ;
			RECT 3.4 0.7 3.74 2.4 ;
			LAYER M1 ;
			RECT 0 -0.7 5 0.7 ;
		END
	END GND
	PIN VDD
		DIRECTION inout ;
		USE POWER ;
		SHAPE ABUTMENT ;
		PORT
			LAYER M1 ;
			RECT 0 9.3 5 10.7 ;
			LAYER M1 ;
			RECT 1.42 8.48 1.78 9.3 ;
			LAYER M1 ;
			RECT 1.32 6.16 1.8 8.48 ;
		END
	END VDD
	PIN in0
		DIRECTION input ;
		PORT
			LAYER M1 ;
			RECT 2.2 5.2 3.14 5.8 ;
		END
	END in0
	OBS
		LAYER M1 ;
		RECT 3.32 6.52 3.8 8.48 ;
		LAYER M1 ;
		RECT 3.32 6.16 3.84 6.52 ;
		LAYER M1 ;
		RECT 0.98 3.74 1.58 3.84 ;
		LAYER M1 ;
		RECT 3.48 3.74 3.84 6.16 ;
		LAYER M1 ;
		RECT 0.98 3.38 3.84 3.74 ;
		LAYER M1 ;
		RECT 0.98 3.24 1.58 3.38 ;
		LAYER M1 ;
		RECT 2.34 2.92 2.7 3.38 ;
		LAYER M1 ;
		RECT 2.32 2.4 2.8 2.92 ;
	END
END MMI_OR2B
MACRO MMI_OR2C
	CLASS CORE ;
	FOREIGN MMI_OR2C 0 0 ;
	SIZE 7 BY 10 ;
	SYMMETRY X Y ;
	SITE CORE1 ;
	PIN in1
		DIRECTION input ;
		PORT
			LAYER M1 ;
			RECT 0.78 4.66 1.38 4.8 ;
			LAYER M1 ;
			RECT 3.2 4.66 3.8 4.8 ;
			LAYER M1 ;
			RECT 0.78 4.3 3.8 4.66 ;
			LAYER M1 ;
			RECT 0.78 4.2 1.38 4.3 ;
			LAYER M1 ;
			RECT 3.2 4.2 3.8 4.3 ;
		END
	END in1
	PIN out
		DIRECTION output ;
		PORT
			LAYER M1 ;
			RECT 5 6.26 5.48 8.12 ;
			LAYER M1 ;
			RECT 5 5.8 5.5 6.26 ;
			LAYER M1 ;
			RECT 5.14 2.56 5.5 5.8 ;
			LAYER M1 ;
			RECT 5 2.34 5.5 2.56 ;
			LAYER M1 ;
			RECT 5 1.44 5.48 2.34 ;
		END
	END out
	PIN GND
		DIRECTION inout ;
		USE GROUND ;
		SHAPE ABUTMENT ;
		PORT
			LAYER M1 ;
			RECT 2 1.44 2.48 2.56 ;
			LAYER M1 ;
			RECT 4 1.44 4.48 2.56 ;
			LAYER M1 ;
			RECT 6 1.44 6.48 2.56 ;
			LAYER M1 ;
			RECT 2.08 0.7 2.44 1.44 ;
			LAYER M1 ;
			RECT 4.06 0.7 4.42 1.44 ;
			LAYER M1 ;
			RECT 6.06 0.7 6.42 1.44 ;
			LAYER M1 ;
			RECT 0 -0.7 7 0.7 ;
		END
	END GND
	PIN VDD
		DIRECTION inout ;
		USE POWER ;
		SHAPE ABUTMENT ;
		PORT
			LAYER M1 ;
			RECT 0 9.3 7 10.7 ;
			LAYER M1 ;
			RECT 0.6 8.12 0.96 9.3 ;
			LAYER M1 ;
			RECT 4.06 8.12 4.42 9.3 ;
			LAYER M1 ;
			RECT 6.06 8.12 6.42 9.3 ;
			LAYER M1 ;
			RECT 0.52 5.8 1 8.12 ;
			LAYER M1 ;
			RECT 4 5.8 4.48 8.12 ;
			LAYER M1 ;
			RECT 6 5.8 6.48 8.12 ;
		END
	END VDD
	PIN in0
		DIRECTION input ;
		PORT
			LAYER M1 ;
			RECT 1.2 3.2 1.8 3.8 ;
		END
	END in0
	OBS
		LAYER M1 ;
		RECT 2.26 5.8 2.74 8.12 ;
		LAYER M1 ;
		RECT 2.34 5.48 2.7 5.8 ;
		LAYER M1 ;
		RECT 2.34 5.12 4.6 5.48 ;
		LAYER M1 ;
		RECT 4.24 3.82 4.6 5.12 ;
		LAYER M1 ;
		RECT 4.22 3.7 4.82 3.82 ;
		LAYER M1 ;
		RECT 3.06 3.34 4.82 3.7 ;
		LAYER M1 ;
		RECT 3.06 2.56 3.42 3.34 ;
		LAYER M1 ;
		RECT 4.22 3.22 4.82 3.34 ;
		LAYER M1 ;
		RECT 3 1.44 3.48 2.56 ;
	END
END MMI_OR2C
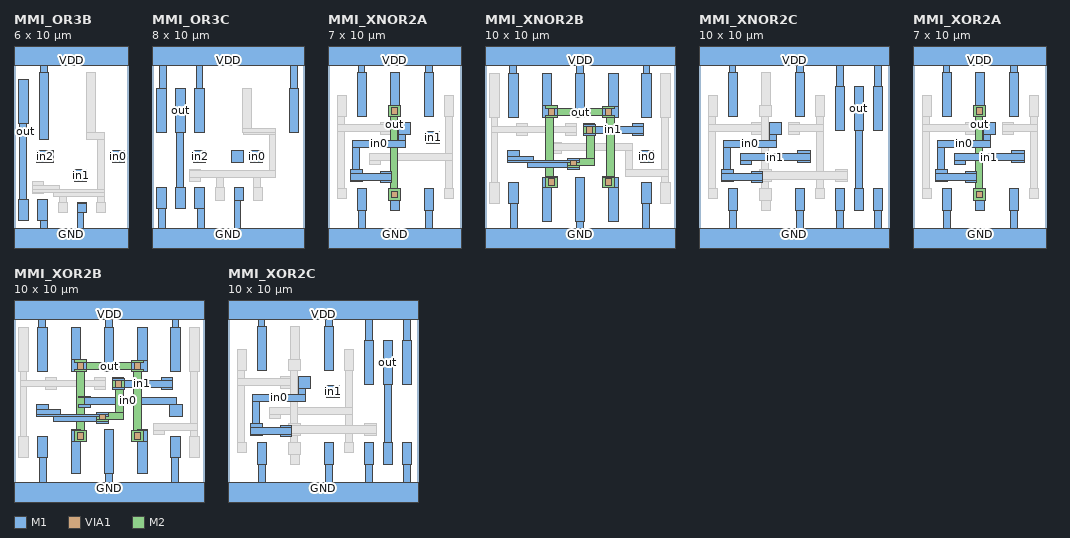
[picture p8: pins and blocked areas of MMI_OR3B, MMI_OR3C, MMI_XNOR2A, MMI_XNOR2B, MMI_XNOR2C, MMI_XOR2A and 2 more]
MACRO MMI_OR3B
	CLASS CORE ;
	FOREIGN MMI_OR3B 0 0 ;
	SIZE 6 BY 10 ;
	SYMMETRY X Y ;
	SITE CORE1 ;
	PIN in1
		DIRECTION input ;
		PORT
			LAYER M1 ;
			RECT 3.2 3.2 3.8 3.8 ;
		END
	END in1
	PIN out
		DIRECTION output ;
		PORT
			LAYER M1 ;
			RECT 0.26 6.22 0.74 8.54 ;
			LAYER M1 ;
			RECT 0.28 2.24 0.64 6.22 ;
			LAYER M1 ;
			RECT 0.26 1.12 0.74 2.24 ;
		END
	END out
	PIN in2
		DIRECTION input ;
		PORT
			LAYER M1 ;
			RECT 1.2 4.2 2.08 4.8 ;
		END
	END in2
	PIN GND
		DIRECTION inout ;
		USE GROUND ;
		SHAPE ABUTMENT ;
		PORT
			LAYER M1 ;
			RECT 1.26 1.12 1.74 2.24 ;
			LAYER M1 ;
			RECT 3.34 2.02 3.82 2.08 ;
			LAYER M1 ;
			RECT 1.38 0.7 1.74 1.12 ;
			LAYER M1 ;
			RECT 3.32 1.56 3.82 2.02 ;
			LAYER M1 ;
			RECT 3.32 0.7 3.66 1.56 ;
			LAYER M1 ;
			RECT 0 -0.7 6 0.7 ;
		END
	END GND
	PIN VDD
		DIRECTION inout ;
		USE POWER ;
		SHAPE ABUTMENT ;
		PORT
			LAYER M1 ;
			RECT 0 9.3 6 10.7 ;
			LAYER M1 ;
			RECT 1.4 8.92 1.74 9.3 ;
			LAYER M1 ;
			RECT 1.34 5.4 1.82 8.92 ;
		END
	END VDD
	PIN in0
		DIRECTION input ;
		PORT
			LAYER M1 ;
			RECT 5.2 4.2 5.8 4.8 ;
		END
	END in0
	OBS
		LAYER M1 ;
		RECT 3.82 5.76 4.3 8.92 ;
		LAYER M1 ;
		RECT 3.82 5.4 4.76 5.76 ;
		LAYER M1 ;
		RECT 0.96 2.96 1.56 3.16 ;
		LAYER M1 ;
		RECT 0.96 2.76 2.42 2.96 ;
		LAYER M1 ;
		RECT 4.4 2.76 4.76 5.4 ;
		LAYER M1 ;
		RECT 0.96 2.6 4.76 2.76 ;
		LAYER M1 ;
		RECT 0.96 2.56 1.56 2.6 ;
		LAYER M1 ;
		RECT 2.06 2.4 4.76 2.6 ;
		LAYER M1 ;
		RECT 2.38 2.08 2.74 2.4 ;
		LAYER M1 ;
		RECT 4.4 2.08 4.76 2.4 ;
		LAYER M1 ;
		RECT 2.34 1.56 2.82 2.08 ;
		LAYER M1 ;
		RECT 4.34 1.56 4.82 2.08 ;
	END
END MMI_OR3B
MACRO MMI_OR3C
	CLASS CORE ;
	FOREIGN MMI_OR3C 0 0 ;
	SIZE 8 BY 10 ;
	SYMMETRY X Y ;
	SITE CORE1 ;
	PIN in1
		DIRECTION input ;
		PORT
			LAYER M1 ;
			RECT 4.2 4.2 4.8 4.8 ;
		END
	END in1
	PIN out
		DIRECTION output ;
		PORT
			LAYER M1 ;
			RECT 1.26 5.74 1.74 8.06 ;
			LAYER M1 ;
			RECT 1.28 2.88 1.64 5.74 ;
			LAYER M1 ;
			RECT 1.26 1.76 1.74 2.88 ;
		END
	END out
	PIN in2
		DIRECTION input ;
		PORT
			LAYER M1 ;
			RECT 2.2 4.2 2.82 4.8 ;
		END
	END in2
	PIN GND
		DIRECTION inout ;
		USE GROUND ;
		SHAPE ABUTMENT ;
		PORT
			LAYER M1 ;
			RECT 0.26 1.76 0.74 2.88 ;
			LAYER M1 ;
			RECT 2.26 1.76 2.74 2.88 ;
			LAYER M1 ;
			RECT 0.34 0.7 0.7 1.76 ;
			LAYER M1 ;
			RECT 2.38 0.7 2.74 1.76 ;
			LAYER M1 ;
			RECT 4.32 2.16 4.84 2.88 ;
			LAYER M1 ;
			RECT 4.32 0.7 4.66 2.16 ;
			LAYER M1 ;
			RECT 0 -0.7 8 0.7 ;
		END
	END GND
	PIN VDD
		DIRECTION inout ;
		USE POWER ;
		SHAPE ABUTMENT ;
		PORT
			LAYER M1 ;
			RECT 0 9.3 8 10.7 ;
			LAYER M1 ;
			RECT 0.38 8.06 0.74 9.3 ;
			LAYER M1 ;
			RECT 2.32 8.06 2.66 9.3 ;
			LAYER M1 ;
			RECT 7.28 8.06 7.64 9.3 ;
			LAYER M1 ;
			RECT 0.26 5.74 0.74 8.06 ;
			LAYER M1 ;
			RECT 2.26 5.74 2.74 8.06 ;
			LAYER M1 ;
			RECT 7.22 5.74 7.7 8.06 ;
		END
	END VDD
	PIN in0
		DIRECTION input ;
		PORT
			LAYER M1 ;
			RECT 5.2 4.2 5.8 4.8 ;
		END
	END in0
	OBS
		LAYER M1 ;
		RECT 4.74 5.98 5.22 8.06 ;
		LAYER M1 ;
		RECT 4.74 5.74 6.52 5.98 ;
		LAYER M1 ;
		RECT 4.82 5.64 6.52 5.74 ;
		LAYER M1 ;
		RECT 1.96 3.74 2.56 3.8 ;
		LAYER M1 ;
		RECT 6.16 3.74 6.52 5.64 ;
		LAYER M1 ;
		RECT 1.96 3.38 6.52 3.74 ;
		LAYER M1 ;
		RECT 1.96 3.2 2.56 3.38 ;
		LAYER M1 ;
		RECT 3.38 2.88 3.74 3.38 ;
		LAYER M1 ;
		RECT 5.34 2.88 5.7 3.38 ;
		LAYER M1 ;
		RECT 3.32 2.16 3.84 2.88 ;
		LAYER M1 ;
		RECT 5.32 2.16 5.82 2.88 ;
	END
END MMI_OR3C
MACRO MMI_XNOR2A
	CLASS CORE ;
	FOREIGN MMI_XNOR2A 0 0 ;
	SIZE 7 BY 10 ;
	SYMMETRY X Y ;
	SITE CORE1 ;
	PIN out
		DIRECTION output ;
		PORT
			LAYER M1 ;
			RECT 3.3 7.2 3.78 8.92 ;
			LAYER M1 ;
			RECT 3.2 6.6 3.8 7.2 ;
			LAYER M1 ;
			RECT 3.2 2.2 3.8 2.8 ;
			LAYER M1 ;
			RECT 3.3 1.68 3.78 2.2 ;
			LAYER VIA1 ;
			RECT 3.32 6.72 3.68 7.08 ;
			LAYER VIA1 ;
			RECT 3.32 2.32 3.68 2.68 ;
			LAYER M2 ;
			RECT 3.2 6.6 3.8 7.2 ;
			LAYER M2 ;
			RECT 3.28 2.8 3.68 6.6 ;
			LAYER M2 ;
			RECT 3.2 2.2 3.8 2.8 ;
		END
	END out
	PIN in1
		DIRECTION input ;
		PORT
			LAYER M1 ;
			RECT 5.2 5.2 5.88 5.8 ;
		END
	END in1
	PIN GND
		DIRECTION inout ;
		USE GROUND ;
		SHAPE ABUTMENT ;
		PORT
			LAYER M1 ;
			RECT 1.54 1.68 2.02 2.8 ;
			LAYER M1 ;
			RECT 5.06 1.68 5.54 2.8 ;
			LAYER M1 ;
			RECT 1.6 0.7 1.96 1.68 ;
			LAYER M1 ;
			RECT 5.12 0.7 5.48 1.68 ;
			LAYER M1 ;
			RECT 0 -0.7 7 0.7 ;
		END
	END GND
	PIN VDD
		DIRECTION inout ;
		USE POWER ;
		SHAPE ABUTMENT ;
		PORT
			LAYER M1 ;
			RECT 0 9.3 7 10.7 ;
			LAYER M1 ;
			RECT 1.6 8.92 1.94 9.3 ;
			LAYER M1 ;
			RECT 5.14 8.92 5.5 9.3 ;
			LAYER M1 ;
			RECT 1.54 6.6 2.02 8.92 ;
			LAYER M1 ;
			RECT 5.06 6.6 5.54 8.92 ;
		END
	END VDD
	PIN in0
		DIRECTION input ;
		PORT
			LAYER M1 ;
			RECT 3.72 5.68 4.32 6.28 ;
			LAYER M1 ;
			RECT 3.72 5.36 4.08 5.68 ;
			LAYER M1 ;
			RECT 1.3 5 4.08 5.36 ;
			LAYER M1 ;
			RECT 1.3 3.8 1.64 5 ;
			LAYER M1 ;
			RECT 1.2 3.62 1.8 3.8 ;
			LAYER M1 ;
			RECT 2.76 3.62 3.36 3.72 ;
			LAYER M1 ;
			RECT 1.2 3.26 3.36 3.62 ;
			LAYER M1 ;
			RECT 1.2 3.2 1.8 3.26 ;
			LAYER M1 ;
			RECT 2.76 3.12 3.36 3.26 ;
		END
	END in0
	OBS
		LAYER M1 ;
		RECT 0.48 6.6 0.96 7.7 ;
		LAYER M1 ;
		RECT 6.12 6.6 6.6 7.7 ;
		LAYER M1 ;
		RECT 0.52 6.16 0.88 6.6 ;
		LAYER M1 ;
		RECT 2.76 6.16 3.36 6.28 ;
		LAYER M1 ;
		RECT 0.52 5.8 3.36 6.16 ;
		LAYER M1 ;
		RECT 0.52 2.8 0.88 5.8 ;
		LAYER M1 ;
		RECT 2.76 5.68 3.36 5.8 ;
		LAYER M1 ;
		RECT 2.16 4.64 2.76 4.68 ;
		LAYER M1 ;
		RECT 6.2 4.64 6.56 6.6 ;
		LAYER M1 ;
		RECT 2.16 4.28 6.56 4.64 ;
		LAYER M1 ;
		RECT 2.16 4.08 2.76 4.28 ;
		LAYER M1 ;
		RECT 6.2 2.8 6.56 4.28 ;
		LAYER M1 ;
		RECT 0.48 2.28 0.96 2.8 ;
		LAYER M1 ;
		RECT 6.12 2.28 6.6 2.8 ;
	END
END MMI_XNOR2A
MACRO MMI_XNOR2B
	CLASS CORE ;
	FOREIGN MMI_XNOR2B 0 0 ;
	SIZE 10 BY 10 ;
	SYMMETRY X Y ;
	SITE CORE1 ;
	PIN out
		DIRECTION output ;
		PORT
			LAYER M1 ;
			RECT 3 7.16 3.48 8.86 ;
			LAYER M1 ;
			RECT 3 6.56 3.8 7.16 ;
			LAYER M1 ;
			RECT 6.52 7.14 7 8.86 ;
			LAYER M1 ;
			RECT 3 6.54 3.48 6.56 ;
			LAYER M1 ;
			RECT 6.2 6.54 7 7.14 ;
			LAYER M1 ;
			RECT 3.2 3.42 3.8 3.46 ;
			LAYER M1 ;
			RECT 3 2.86 3.8 3.42 ;
			LAYER M1 ;
			RECT 6.2 3.42 6.8 3.46 ;
			LAYER M1 ;
			RECT 6.2 2.86 7 3.42 ;
			LAYER M1 ;
			RECT 3 1.1 3.48 2.86 ;
			LAYER M1 ;
			RECT 6.52 1.1 7 2.86 ;
			LAYER VIA1 ;
			RECT 3.32 6.68 3.68 7.04 ;
			LAYER VIA1 ;
			RECT 6.32 6.66 6.68 7.02 ;
			LAYER VIA1 ;
			RECT 3.32 2.98 3.68 3.34 ;
			LAYER VIA1 ;
			RECT 6.32 2.98 6.68 3.34 ;
			LAYER M2 ;
			RECT 3.2 7.04 3.8 7.16 ;
			LAYER M2 ;
			RECT 6.2 7.04 6.8 7.14 ;
			LAYER M2 ;
			RECT 3.2 6.64 6.8 7.04 ;
			LAYER M2 ;
			RECT 3.2 6.56 3.8 6.64 ;
			LAYER M2 ;
			RECT 3.2 3.46 3.6 6.56 ;
			LAYER M2 ;
			RECT 6.2 6.54 6.8 6.64 ;
			LAYER M2 ;
			RECT 6.4 3.46 6.8 6.54 ;
			LAYER M2 ;
			RECT 3.2 2.86 3.8 3.46 ;
			LAYER M2 ;
			RECT 6.2 2.86 6.8 3.46 ;
		END
	END out
	PIN in1
		DIRECTION input ;
		PORT
			LAYER M1 ;
			RECT 5.18 6.2 5.78 6.22 ;
			LAYER M1 ;
			RECT 5.18 6.08 5.8 6.2 ;
			LAYER M1 ;
			RECT 7.74 6.08 8.34 6.22 ;
			LAYER M1 ;
			RECT 5.18 5.72 8.34 6.08 ;
			LAYER M1 ;
			RECT 5.18 5.62 5.8 5.72 ;
			LAYER M1 ;
			RECT 7.74 5.62 8.34 5.72 ;
			LAYER M1 ;
			RECT 5.2 5.6 5.8 5.62 ;
			LAYER M1 ;
			RECT 1.2 4.52 1.8 4.8 ;
			LAYER M1 ;
			RECT 1.2 4.28 2.54 4.52 ;
			LAYER M1 ;
			RECT 4.36 4.4 4.96 4.42 ;
			LAYER M1 ;
			RECT 4.36 4.28 4.98 4.4 ;
			LAYER M1 ;
			RECT 1.2 4.2 4.98 4.28 ;
			LAYER M1 ;
			RECT 2.22 3.92 4.98 4.2 ;
			LAYER M1 ;
			RECT 4.36 3.82 4.98 3.92 ;
			LAYER M1 ;
			RECT 4.38 3.8 4.98 3.82 ;
			LAYER VIA1 ;
			RECT 5.32 5.72 5.68 6.08 ;
			LAYER VIA1 ;
			RECT 4.48 3.94 4.84 4.3 ;
			LAYER M2 ;
			RECT 5.2 5.6 5.8 6.2 ;
			LAYER M2 ;
			RECT 5.34 4.42 5.74 5.6 ;
			LAYER M2 ;
			RECT 4.36 4.02 5.74 4.42 ;
			LAYER M2 ;
			RECT 4.36 3.82 4.96 4.02 ;
		END
	END in1
	PIN GND
		DIRECTION inout ;
		USE GROUND ;
		SHAPE ABUTMENT ;
		PORT
			LAYER M1 ;
			RECT 1.26 2.02 1.74 3.14 ;
			LAYER M1 ;
			RECT 1.34 0.7 1.7 2.02 ;
			LAYER M1 ;
			RECT 4.76 1.1 5.24 3.42 ;
			LAYER M1 ;
			RECT 8.26 2.02 8.74 3.14 ;
			LAYER M1 ;
			RECT 4.84 0.7 5.2 1.1 ;
			LAYER M1 ;
			RECT 8.3 0.7 8.66 2.02 ;
			LAYER M1 ;
			RECT 0 -0.7 10 0.7 ;
		END
	END GND
	PIN VDD
		DIRECTION inout ;
		USE POWER ;
		SHAPE ABUTMENT ;
		PORT
			LAYER M1 ;
			RECT 0 9.3 10 10.7 ;
			LAYER M1 ;
			RECT 1.3 8.86 1.64 9.3 ;
			LAYER M1 ;
			RECT 4.82 8.86 5.18 9.3 ;
			LAYER M1 ;
			RECT 8.32 8.86 8.68 9.3 ;
			LAYER M1 ;
			RECT 1.26 6.54 1.74 8.86 ;
			LAYER M1 ;
			RECT 4.76 6.54 5.24 8.86 ;
			LAYER M1 ;
			RECT 8.26 6.54 8.74 8.86 ;
		END
	END VDD
	PIN in0
		DIRECTION input ;
		PORT
			LAYER M1 ;
			RECT 8.2 4.2 8.88 4.8 ;
		END
	END in0
	OBS
		LAYER M1 ;
		RECT 0.26 6.54 0.74 8.86 ;
		LAYER M1 ;
		RECT 9.26 6.54 9.74 8.86 ;
		LAYER M1 ;
		RECT 0.32 6.1 0.68 6.54 ;
		LAYER M1 ;
		RECT 1.66 6.1 2.26 6.22 ;
		LAYER M1 ;
		RECT 4.22 6.1 4.82 6.22 ;
		LAYER M1 ;
		RECT 0.32 5.74 4.82 6.1 ;
		LAYER M1 ;
		RECT 0.32 3.14 0.68 5.74 ;
		LAYER M1 ;
		RECT 1.66 5.62 2.26 5.74 ;
		LAYER M1 ;
		RECT 4.22 5.62 4.82 5.74 ;
		LAYER M1 ;
		RECT 5.18 6.2 5.78 6.22 ;
		LAYER M1 ;
		RECT 3.42 5.2 4.02 5.24 ;
		LAYER M1 ;
		RECT 3.42 4.84 7.74 5.2 ;
		LAYER M1 ;
		RECT 3.42 4.64 4.02 4.84 ;
		LAYER M1 ;
		RECT 4.36 4.4 4.96 4.42 ;
		LAYER M1 ;
		RECT 7.38 3.82 7.74 4.84 ;
		LAYER M1 ;
		RECT 9.3 3.82 9.66 6.54 ;
		LAYER M1 ;
		RECT 7.38 3.46 9.66 3.82 ;
		LAYER M1 ;
		RECT 0.26 2.02 0.74 3.14 ;
		LAYER M1 ;
		RECT 9.3 3.14 9.66 3.46 ;
		LAYER M1 ;
		RECT 9.26 2.02 9.74 3.14 ;
	END
END MMI_XNOR2B
MACRO MMI_XNOR2C
	CLASS CORE ;
	FOREIGN MMI_XNOR2C 0 0 ;
	SIZE 10 BY 10 ;
	SYMMETRY X Y ;
	SITE CORE1 ;
	PIN out
		DIRECTION output ;
		PORT
			LAYER M1 ;
			RECT 8.18 5.88 8.66 8.2 ;
			LAYER M1 ;
			RECT 8.24 2.8 8.6 5.88 ;
			LAYER M1 ;
			RECT 8.18 1.68 8.66 2.8 ;
		END
	END out
	PIN in1
		DIRECTION input ;
		PORT
			LAYER M1 ;
			RECT 2.16 4.64 2.76 4.68 ;
			LAYER M1 ;
			RECT 5.2 4.64 5.88 4.8 ;
			LAYER M1 ;
			RECT 2.16 4.28 5.88 4.64 ;
			LAYER M1 ;
			RECT 2.16 4.08 2.76 4.28 ;
			LAYER M1 ;
			RECT 5.2 4.2 5.88 4.28 ;
		END
	END in1
	PIN GND
		DIRECTION inout ;
		USE GROUND ;
		SHAPE ABUTMENT ;
		PORT
			LAYER M1 ;
			RECT 1.54 1.68 2.02 2.8 ;
			LAYER M1 ;
			RECT 5.06 1.68 5.54 2.8 ;
			LAYER M1 ;
			RECT 7.18 1.68 7.66 2.8 ;
			LAYER M1 ;
			RECT 9.18 1.68 9.66 2.8 ;
			LAYER M1 ;
			RECT 1.6 0.7 1.96 1.68 ;
			LAYER M1 ;
			RECT 5.12 0.7 5.48 1.68 ;
			LAYER M1 ;
			RECT 7.24 0.7 7.6 1.68 ;
			LAYER M1 ;
			RECT 9.24 0.7 9.6 1.68 ;
			LAYER M1 ;
			RECT 0 -0.7 10 0.7 ;
		END
	END GND
	PIN VDD
		DIRECTION inout ;
		USE POWER ;
		SHAPE ABUTMENT ;
		PORT
			LAYER M1 ;
			RECT 0 9.3 10 10.7 ;
			LAYER M1 ;
			RECT 1.6 8.92 1.94 9.3 ;
			LAYER M1 ;
			RECT 5.14 8.92 5.5 9.3 ;
			LAYER M1 ;
			RECT 1.54 6.6 2.02 8.92 ;
			LAYER M1 ;
			RECT 5.06 6.6 5.54 8.92 ;
			LAYER M1 ;
			RECT 7.24 8.2 7.6 9.3 ;
			LAYER M1 ;
			RECT 9.24 8.2 9.6 9.3 ;
			LAYER M1 ;
			RECT 7.18 5.88 7.66 8.2 ;
			LAYER M1 ;
			RECT 9.18 5.88 9.66 8.2 ;
		END
	END VDD
	PIN in0
		DIRECTION input ;
		PORT
			LAYER M1 ;
			RECT 3.72 5.68 4.32 6.28 ;
			LAYER M1 ;
			RECT 3.72 5.36 4.08 5.68 ;
			LAYER M1 ;
			RECT 1.3 5 4.08 5.36 ;
			LAYER M1 ;
			RECT 1.3 3.8 1.64 5 ;
			LAYER M1 ;
			RECT 1.2 3.62 1.8 3.8 ;
			LAYER M1 ;
			RECT 2.76 3.62 3.36 3.72 ;
			LAYER M1 ;
			RECT 1.2 3.26 3.36 3.62 ;
			LAYER M1 ;
			RECT 1.2 3.2 1.8 3.26 ;
			LAYER M1 ;
			RECT 2.76 3.12 3.36 3.26 ;
		END
	END in0
	OBS
		LAYER M1 ;
		RECT 0.48 6.6 0.96 7.7 ;
		LAYER M1 ;
		RECT 3.3 7.2 3.78 8.92 ;
		LAYER M1 ;
		RECT 3.2 6.6 3.8 7.2 ;
		LAYER M1 ;
		RECT 6.12 6.6 6.6 7.7 ;
		LAYER M1 ;
		RECT 0.52 6.16 0.88 6.6 ;
		LAYER M1 ;
		RECT 2.76 6.16 3.36 6.28 ;
		LAYER M1 ;
		RECT 0.52 5.8 3.36 6.16 ;
		LAYER M1 ;
		RECT 0.52 2.8 0.88 5.8 ;
		LAYER M1 ;
		RECT 2.76 5.68 3.36 5.8 ;
		LAYER M1 ;
		RECT 4.7 6.16 5.3 6.28 ;
		LAYER M1 ;
		RECT 6.2 6.16 6.56 6.6 ;
		LAYER M1 ;
		RECT 4.7 5.8 6.56 6.16 ;
		LAYER M1 ;
		RECT 4.7 5.68 5.3 5.8 ;
		LAYER M1 ;
		RECT 6.2 2.8 6.56 5.8 ;
		LAYER M1 ;
		RECT 7.2 3.2 7.8 3.8 ;
		LAYER M1 ;
		RECT 0.48 2.28 0.96 2.8 ;
		LAYER M1 ;
		RECT 3.2 2.2 3.8 2.8 ;
		LAYER M1 ;
		RECT 3.3 1.68 3.78 2.2 ;
		LAYER M1 ;
		RECT 6.12 2.28 6.6 2.8 ;
		LAYER M2 ;
		RECT 3.2 6.6 3.8 7.2 ;
		LAYER M2 ;
		RECT 3.28 3.8 3.68 6.6 ;
		LAYER M2 ;
		RECT 3.2 3.2 3.8 3.8 ;
		LAYER M2 ;
		RECT 7.2 3.2 7.8 3.8 ;
		LAYER M2 ;
		RECT 3.28 2.8 3.68 3.2 ;
		LAYER M2 ;
		RECT 3.2 2.2 3.8 2.8 ;
		LAYER M3 ;
		RECT 3.2 3.7 3.8 3.8 ;
		LAYER M3 ;
		RECT 7.2 3.7 7.8 3.8 ;
		LAYER M3 ;
		RECT 3.2 3.3 7.8 3.7 ;
		LAYER M3 ;
		RECT 3.2 3.2 3.8 3.3 ;
		LAYER M3 ;
		RECT 7.2 3.2 7.8 3.3 ;
	END
END MMI_XNOR2C
MACRO MMI_XOR2A
	CLASS CORE ;
	FOREIGN MMI_XOR2A 0 0 ;
	SIZE 7 BY 10 ;
	SYMMETRY X Y ;
	SITE CORE1 ;
	PIN in1
		DIRECTION input ;
		PORT
			LAYER M1 ;
			RECT 2.16 4.64 2.76 4.68 ;
			LAYER M1 ;
			RECT 5.2 4.64 5.88 4.8 ;
			LAYER M1 ;
			RECT 2.16 4.28 5.88 4.64 ;
			LAYER M1 ;
			RECT 2.16 4.08 2.76 4.28 ;
			LAYER M1 ;
			RECT 5.2 4.2 5.88 4.28 ;
		END
	END in1
	PIN out
		DIRECTION output ;
		PORT
			LAYER M1 ;
			RECT 3.3 7.2 3.78 8.92 ;
			LAYER M1 ;
			RECT 3.2 6.6 3.8 7.2 ;
			LAYER M1 ;
			RECT 3.2 2.2 3.8 2.8 ;
			LAYER M1 ;
			RECT 3.3 1.68 3.78 2.2 ;
			LAYER VIA1 ;
			RECT 3.32 6.72 3.68 7.08 ;
			LAYER VIA1 ;
			RECT 3.32 2.32 3.68 2.68 ;
			LAYER M2 ;
			RECT 3.2 6.6 3.8 7.2 ;
			LAYER M2 ;
			RECT 3.28 2.8 3.68 6.6 ;
			LAYER M2 ;
			RECT 3.2 2.2 3.8 2.8 ;
		END
	END out
	PIN GND
		DIRECTION inout ;
		USE GROUND ;
		SHAPE ABUTMENT ;
		PORT
			LAYER M1 ;
			RECT 1.54 1.68 2.02 2.8 ;
			LAYER M1 ;
			RECT 5.06 1.68 5.54 2.8 ;
			LAYER M1 ;
			RECT 1.6 0.7 1.96 1.68 ;
			LAYER M1 ;
			RECT 5.12 0.7 5.48 1.68 ;
			LAYER M1 ;
			RECT 0 -0.7 7 0.7 ;
		END
	END GND
	PIN VDD
		DIRECTION inout ;
		USE POWER ;
		SHAPE ABUTMENT ;
		PORT
			LAYER M1 ;
			RECT 0 9.3 7 10.7 ;
			LAYER M1 ;
			RECT 1.6 8.92 1.94 9.3 ;
			LAYER M1 ;
			RECT 5.14 8.92 5.5 9.3 ;
			LAYER M1 ;
			RECT 1.54 6.6 2.02 8.92 ;
			LAYER M1 ;
			RECT 5.06 6.6 5.54 8.92 ;
		END
	END VDD
	PIN in0
		DIRECTION input ;
		PORT
			LAYER M1 ;
			RECT 3.72 5.68 4.32 6.28 ;
			LAYER M1 ;
			RECT 3.72 5.36 4.08 5.68 ;
			LAYER M1 ;
			RECT 1.3 5 4.08 5.36 ;
			LAYER M1 ;
			RECT 1.3 3.8 1.64 5 ;
			LAYER M1 ;
			RECT 1.2 3.62 1.8 3.8 ;
			LAYER M1 ;
			RECT 2.76 3.62 3.36 3.72 ;
			LAYER M1 ;
			RECT 1.2 3.26 3.36 3.62 ;
			LAYER M1 ;
			RECT 1.2 3.2 1.8 3.26 ;
			LAYER M1 ;
			RECT 2.76 3.12 3.36 3.26 ;
		END
	END in0
	OBS
		LAYER M1 ;
		RECT 0.48 6.6 0.96 7.7 ;
		LAYER M1 ;
		RECT 6.12 6.6 6.6 7.7 ;
		LAYER M1 ;
		RECT 0.52 6.16 0.88 6.6 ;
		LAYER M1 ;
		RECT 2.76 6.16 3.36 6.28 ;
		LAYER M1 ;
		RECT 0.52 5.8 3.36 6.16 ;
		LAYER M1 ;
		RECT 0.52 2.8 0.88 5.8 ;
		LAYER M1 ;
		RECT 2.76 5.68 3.36 5.8 ;
		LAYER M1 ;
		RECT 4.7 6.16 5.3 6.28 ;
		LAYER M1 ;
		RECT 6.2 6.16 6.56 6.6 ;
		LAYER M1 ;
		RECT 4.7 5.8 6.56 6.16 ;
		LAYER M1 ;
		RECT 4.7 5.68 5.3 5.8 ;
		LAYER M1 ;
		RECT 6.2 2.8 6.56 5.8 ;
		LAYER M1 ;
		RECT 0.48 2.28 0.96 2.8 ;
		LAYER M1 ;
		RECT 6.12 2.28 6.6 2.8 ;
	END
END MMI_XOR2A
MACRO MMI_XOR2B
	CLASS CORE ;
	FOREIGN MMI_XOR2B 0 0 ;
	SIZE 10 BY 10 ;
	SYMMETRY X Y ;
	SITE CORE1 ;
	PIN out
		DIRECTION output ;
		PORT
			LAYER M1 ;
			RECT 3 7.16 3.48 8.86 ;
			LAYER M1 ;
			RECT 3 6.56 3.8 7.16 ;
			LAYER M1 ;
			RECT 6.52 7.14 7 8.86 ;
			LAYER M1 ;
			RECT 3 6.54 3.48 6.56 ;
			LAYER M1 ;
			RECT 6.2 6.54 7 7.14 ;
			LAYER M1 ;
			RECT 3 3.46 3.48 3.48 ;
			LAYER M1 ;
			RECT 6.52 3.46 7 3.48 ;
			LAYER M1 ;
			RECT 3 2.86 3.8 3.46 ;
			LAYER M1 ;
			RECT 6.2 2.86 7 3.46 ;
			LAYER M1 ;
			RECT 3 1.16 3.48 2.86 ;
			LAYER M1 ;
			RECT 6.52 1.16 7 2.86 ;
			LAYER VIA1 ;
			RECT 3.32 6.68 3.68 7.04 ;
			LAYER VIA1 ;
			RECT 6.32 6.66 6.68 7.02 ;
			LAYER VIA1 ;
			RECT 3.32 2.98 3.68 3.34 ;
			LAYER VIA1 ;
			RECT 6.32 2.98 6.68 3.34 ;
			LAYER M2 ;
			RECT 3.2 7.04 3.8 7.16 ;
			LAYER M2 ;
			RECT 6.2 7.04 6.8 7.14 ;
			LAYER M2 ;
			RECT 3.2 6.64 6.8 7.04 ;
			LAYER M2 ;
			RECT 3.2 6.56 3.8 6.64 ;
			LAYER M2 ;
			RECT 3.3 3.46 3.7 6.56 ;
			LAYER M2 ;
			RECT 6.2 6.54 6.8 6.64 ;
			LAYER M2 ;
			RECT 6.3 3.46 6.7 6.54 ;
			LAYER M2 ;
			RECT 3.2 2.86 3.8 3.46 ;
			LAYER M2 ;
			RECT 6.2 2.86 6.8 3.46 ;
		END
	END out
	PIN in1
		DIRECTION input ;
		PORT
			LAYER M1 ;
			RECT 5.18 6.2 5.78 6.22 ;
			LAYER M1 ;
			RECT 5.18 6.08 5.8 6.2 ;
			LAYER M1 ;
			RECT 7.74 6.08 8.34 6.22 ;
			LAYER M1 ;
			RECT 5.18 5.72 8.34 6.08 ;
			LAYER M1 ;
			RECT 5.18 5.62 5.8 5.72 ;
			LAYER M1 ;
			RECT 7.74 5.62 8.34 5.72 ;
			LAYER M1 ;
			RECT 5.2 5.6 5.8 5.62 ;
			LAYER M1 ;
			RECT 1.2 4.56 1.8 4.8 ;
			LAYER M1 ;
			RECT 1.2 4.28 2.46 4.56 ;
			LAYER M1 ;
			RECT 4.36 4.4 4.96 4.42 ;
			LAYER M1 ;
			RECT 4.36 4.28 4.98 4.4 ;
			LAYER M1 ;
			RECT 1.2 4.2 4.98 4.28 ;
			LAYER M1 ;
			RECT 2.1 3.92 4.98 4.2 ;
			LAYER M1 ;
			RECT 4.36 3.82 4.98 3.92 ;
			LAYER M1 ;
			RECT 4.38 3.8 4.98 3.82 ;
			LAYER VIA1 ;
			RECT 5.32 5.72 5.68 6.08 ;
			LAYER VIA1 ;
			RECT 4.48 3.94 4.84 4.3 ;
			LAYER M2 ;
			RECT 5.2 5.6 5.8 6.2 ;
			LAYER M2 ;
			RECT 5.34 4.42 5.74 5.6 ;
			LAYER M2 ;
			RECT 4.36 4.02 5.74 4.42 ;
			LAYER M2 ;
			RECT 4.36 3.82 4.96 4.02 ;
		END
	END in1
	PIN GND
		DIRECTION inout ;
		USE GROUND ;
		SHAPE ABUTMENT ;
		PORT
			LAYER M1 ;
			RECT 1.26 2.02 1.74 3.14 ;
			LAYER M1 ;
			RECT 1.34 0.7 1.7 2.02 ;
			LAYER M1 ;
			RECT 4.76 1.16 5.24 3.48 ;
			LAYER M1 ;
			RECT 8.26 2.02 8.74 3.14 ;
			LAYER M1 ;
			RECT 4.84 0.7 5.2 1.16 ;
			LAYER M1 ;
			RECT 8.3 0.7 8.66 2.02 ;
			LAYER M1 ;
			RECT 0 -0.7 10 0.7 ;
		END
	END GND
	PIN VDD
		DIRECTION inout ;
		USE POWER ;
		SHAPE ABUTMENT ;
		PORT
			LAYER M1 ;
			RECT 0 9.3 10 10.7 ;
			LAYER M1 ;
			RECT 1.3 8.86 1.64 9.3 ;
			LAYER M1 ;
			RECT 4.82 8.86 5.18 9.3 ;
			LAYER M1 ;
			RECT 8.32 8.86 8.68 9.3 ;
			LAYER M1 ;
			RECT 1.26 6.54 1.74 8.86 ;
			LAYER M1 ;
			RECT 4.76 6.54 5.24 8.86 ;
			LAYER M1 ;
			RECT 8.26 6.54 8.74 8.86 ;
		END
	END VDD
	PIN in0
		DIRECTION input ;
		PORT
			LAYER M1 ;
			RECT 3.42 5.2 4.02 5.24 ;
			LAYER M1 ;
			RECT 3.42 4.84 8.56 5.2 ;
			LAYER M1 ;
			RECT 3.42 4.64 4.02 4.84 ;
			LAYER M1 ;
			RECT 8.2 4.8 8.56 4.84 ;
			LAYER M1 ;
			RECT 8.2 4.2 8.88 4.8 ;
		END
	END in0
	OBS
		LAYER M1 ;
		RECT 0.26 6.54 0.74 8.86 ;
		LAYER M1 ;
		RECT 9.26 6.54 9.74 8.86 ;
		LAYER M1 ;
		RECT 0.32 6.1 0.68 6.54 ;
		LAYER M1 ;
		RECT 1.66 6.1 2.26 6.22 ;
		LAYER M1 ;
		RECT 4.22 6.1 4.82 6.22 ;
		LAYER M1 ;
		RECT 0.32 5.74 4.82 6.1 ;
		LAYER M1 ;
		RECT 0.32 3.14 0.68 5.74 ;
		LAYER M1 ;
		RECT 1.66 5.62 2.26 5.74 ;
		LAYER M1 ;
		RECT 4.22 5.62 4.82 5.74 ;
		LAYER M1 ;
		RECT 5.18 6.2 5.78 6.22 ;
		LAYER M1 ;
		RECT 4.36 4.4 4.96 4.42 ;
		LAYER M1 ;
		RECT 9.3 3.82 9.66 6.54 ;
		LAYER M1 ;
		RECT 3 3.46 3.48 3.48 ;
		LAYER M1 ;
		RECT 0.26 2.02 0.74 3.14 ;
		LAYER M1 ;
		RECT 6.52 3.46 7 3.48 ;
		LAYER M1 ;
		RECT 7.34 3.46 9.66 3.82 ;
		LAYER M1 ;
		RECT 7.34 3.22 7.94 3.46 ;
		LAYER M1 ;
		RECT 9.3 3.14 9.66 3.46 ;
		LAYER M1 ;
		RECT 9.26 2.02 9.74 3.14 ;
	END
END MMI_XOR2B
MACRO MMI_XOR2C
	CLASS CORE ;
	FOREIGN MMI_XOR2C 0 0 ;
	SIZE 10 BY 10 ;
	SYMMETRY X Y ;
	SITE CORE1 ;
	PIN in1
		DIRECTION input ;
		PORT
			LAYER M1 ;
			RECT 5.2 5.2 5.88 5.8 ;
		END
	END in1
	PIN out
		DIRECTION output ;
		PORT
			LAYER M1 ;
			RECT 8.18 5.88 8.66 8.2 ;
			LAYER M1 ;
			RECT 8.24 2.8 8.6 5.88 ;
			LAYER M1 ;
			RECT 8.18 1.68 8.66 2.8 ;
		END
	END out
	PIN GND
		DIRECTION inout ;
		USE GROUND ;
		SHAPE ABUTMENT ;
		PORT
			LAYER M1 ;
			RECT 1.54 1.68 2.02 2.8 ;
			LAYER M1 ;
			RECT 5.06 1.68 5.54 2.8 ;
			LAYER M1 ;
			RECT 7.18 1.68 7.66 2.8 ;
			LAYER M1 ;
			RECT 9.18 1.68 9.66 2.8 ;
			LAYER M1 ;
			RECT 1.6 0.7 1.96 1.68 ;
			LAYER M1 ;
			RECT 5.12 0.7 5.48 1.68 ;
			LAYER M1 ;
			RECT 7.24 0.7 7.6 1.68 ;
			LAYER M1 ;
			RECT 9.24 0.7 9.6 1.68 ;
			LAYER M1 ;
			RECT 0 -0.7 10 0.7 ;
		END
	END GND
	PIN VDD
		DIRECTION inout ;
		USE POWER ;
		SHAPE ABUTMENT ;
		PORT
			LAYER M1 ;
			RECT 0 9.3 10 10.7 ;
			LAYER M1 ;
			RECT 1.6 8.92 1.94 9.3 ;
			LAYER M1 ;
			RECT 5.14 8.92 5.5 9.3 ;
			LAYER M1 ;
			RECT 1.54 6.6 2.02 8.92 ;
			LAYER M1 ;
			RECT 5.06 6.6 5.54 8.92 ;
			LAYER M1 ;
			RECT 7.24 8.2 7.6 9.3 ;
			LAYER M1 ;
			RECT 9.24 8.2 9.6 9.3 ;
			LAYER M1 ;
			RECT 7.18 5.88 7.66 8.2 ;
			LAYER M1 ;
			RECT 9.18 5.88 9.66 8.2 ;
		END
	END VDD
	PIN in0
		DIRECTION input ;
		PORT
			LAYER M1 ;
			RECT 3.72 5.68 4.32 6.28 ;
			LAYER M1 ;
			RECT 3.72 5.36 4.08 5.68 ;
			LAYER M1 ;
			RECT 1.3 5 4.08 5.36 ;
			LAYER M1 ;
			RECT 1.3 3.8 1.64 5 ;
			LAYER M1 ;
			RECT 1.2 3.62 1.8 3.8 ;
			LAYER M1 ;
			RECT 2.76 3.62 3.36 3.72 ;
			LAYER M1 ;
			RECT 1.2 3.26 3.36 3.62 ;
			LAYER M1 ;
			RECT 1.2 3.2 1.8 3.26 ;
			LAYER M1 ;
			RECT 2.76 3.12 3.36 3.26 ;
		END
	END in0
	OBS
		LAYER M1 ;
		RECT 0.48 6.6 0.96 7.7 ;
		LAYER M1 ;
		RECT 3.3 7.2 3.78 8.92 ;
		LAYER M1 ;
		RECT 3.2 6.6 3.8 7.2 ;
		LAYER M1 ;
		RECT 6.12 6.6 6.6 7.7 ;
		LAYER M1 ;
		RECT 0.52 6.16 0.88 6.6 ;
		LAYER M1 ;
		RECT 2.76 6.16 3.36 6.28 ;
		LAYER M1 ;
		RECT 0.52 5.8 3.36 6.16 ;
		LAYER M1 ;
		RECT 0.52 2.8 0.88 5.8 ;
		LAYER M1 ;
		RECT 2.76 5.68 3.36 5.8 ;
		LAYER M1 ;
		RECT 2.16 4.64 2.76 4.68 ;
		LAYER M1 ;
		RECT 6.2 4.64 6.56 6.6 ;
		LAYER M1 ;
		RECT 2.16 4.28 6.56 4.64 ;
		LAYER M1 ;
		RECT 2.16 4.08 2.76 4.28 ;
		LAYER M1 ;
		RECT 6.2 2.8 6.56 4.28 ;
		LAYER M1 ;
		RECT 7.2 3.2 7.8 3.8 ;
		LAYER M1 ;
		RECT 0.48 2.28 0.96 2.8 ;
		LAYER M1 ;
		RECT 3.2 2.2 3.8 2.8 ;
		LAYER M1 ;
		RECT 3.3 1.68 3.78 2.2 ;
		LAYER M1 ;
		RECT 6.12 2.28 6.6 2.8 ;
		LAYER M2 ;
		RECT 3.2 6.6 3.8 7.2 ;
		LAYER M2 ;
		RECT 3.28 3.8 3.68 6.6 ;
		LAYER M2 ;
		RECT 3.2 3.2 3.8 3.8 ;
		LAYER M2 ;
		RECT 7.2 3.2 7.8 3.8 ;
		LAYER M2 ;
		RECT 3.28 2.8 3.68 3.2 ;
		LAYER M2 ;
		RECT 3.2 2.2 3.8 2.8 ;
		LAYER M3 ;
		RECT 3.2 3.7 3.8 3.8 ;
		LAYER M3 ;
		RECT 7.2 3.7 7.8 3.8 ;
		LAYER M3 ;
		RECT 3.2 3.3 7.8 3.7 ;
		LAYER M3 ;
		RECT 3.2 3.2 3.8 3.3 ;
		LAYER M3 ;
		RECT 7.2 3.2 7.8 3.3 ;
	END
END MMI_XOR2C
END LIBRARY
